VERSION 5.8 ;
BUSBITCHARS "[]" ;
DIVIDERCHAR "/" ;
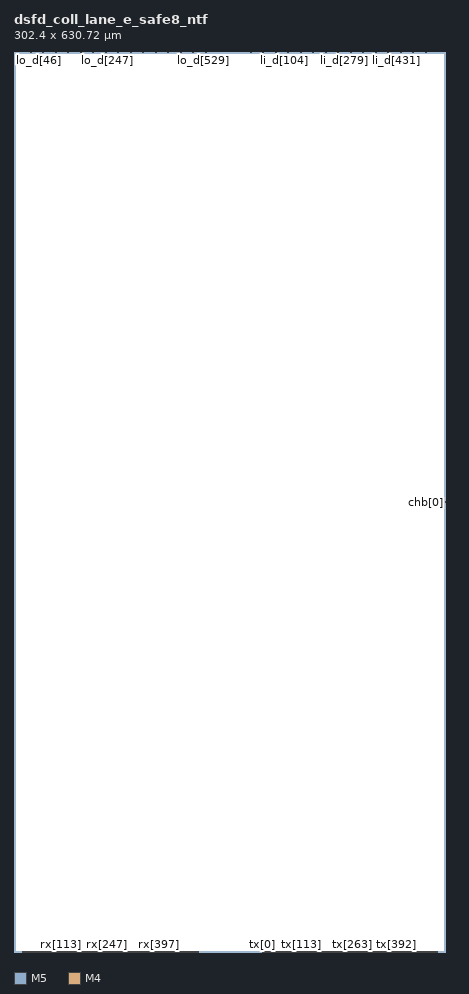
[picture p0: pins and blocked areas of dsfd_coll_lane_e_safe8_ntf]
MACRO dsfd_coll_lane_e_safe8_ntf
 CLASS BLOCK ;
 ORIGIN 0 0 ;
 SIZE 302.4 BY 630.72 ;
 SYMMETRY X Y ;
 PIN rx[0]
  DIRECTION INPUT ;
  USE SIGNAL ;
  PORT
   LAYER M5 ;
   RECT 6.1440 0.0000 6.1680 0.0840 ;
  END
 END rx[0]
 PIN rx[1]
  DIRECTION INPUT ;
  USE SIGNAL ;
  PORT
   LAYER M5 ;
   RECT 6.3840 0.0000 6.4080 0.0840 ;
  END
 END rx[1]
 PIN rx[2]
  DIRECTION INPUT ;
  USE SIGNAL ;
  PORT
   LAYER M5 ;
   RECT 6.6240 0.0000 6.6480 0.0840 ;
  END
 END rx[2]
 PIN rx[3]
  DIRECTION INPUT ;
  USE SIGNAL ;
  PORT
   LAYER M5 ;
   RECT 6.8640 0.0000 6.8880 0.0840 ;
  END
 END rx[3]
 PIN rx[4]
  DIRECTION INPUT ;
  USE SIGNAL ;
  PORT
   LAYER M5 ;
   RECT 7.1040 0.0000 7.1280 0.0840 ;
  END
 END rx[4]
 PIN rx[5]
  DIRECTION INPUT ;
  USE SIGNAL ;
  PORT
   LAYER M5 ;
   RECT 7.3440 0.0000 7.3680 0.0840 ;
  END
 END rx[5]
 PIN rx[6]
  DIRECTION INPUT ;
  USE SIGNAL ;
  PORT
   LAYER M5 ;
   RECT 7.5840 0.0000 7.6080 0.0840 ;
  END
 END rx[6]
 PIN rx[7]
  DIRECTION INPUT ;
  USE SIGNAL ;
  PORT
   LAYER M5 ;
   RECT 7.8240 0.0000 7.8480 0.0840 ;
  END
 END rx[7]
 PIN rx[8]
  DIRECTION INPUT ;
  USE SIGNAL ;
  PORT
   LAYER M5 ;
   RECT 8.0640 0.0000 8.0880 0.0840 ;
  END
 END rx[8]
 PIN rx[9]
  DIRECTION INPUT ;
  USE SIGNAL ;
  PORT
   LAYER M5 ;
   RECT 8.3040 0.0000 8.3280 0.0840 ;
  END
 END rx[9]
 PIN rx[10]
  DIRECTION INPUT ;
  USE SIGNAL ;
  PORT
   LAYER M5 ;
   RECT 8.5440 0.0000 8.5680 0.0840 ;
  END
 END rx[10]
 PIN rx[11]
  DIRECTION INPUT ;
  USE SIGNAL ;
  PORT
   LAYER M5 ;
   RECT 8.7840 0.0000 8.8080 0.0840 ;
  END
 END rx[11]
 PIN rx[12]
  DIRECTION INPUT ;
  USE SIGNAL ;
  PORT
   LAYER M5 ;
   RECT 9.0240 0.0000 9.0480 0.0840 ;
  END
 END rx[12]
 PIN rx[13]
  DIRECTION INPUT ;
  USE SIGNAL ;
  PORT
   LAYER M5 ;
   RECT 9.2640 0.0000 9.2880 0.0840 ;
  END
 END rx[13]
 PIN rx[14]
  DIRECTION INPUT ;
  USE SIGNAL ;
  PORT
   LAYER M5 ;
   RECT 9.5040 0.0000 9.5280 0.0840 ;
  END
 END rx[14]
 PIN rx[15]
  DIRECTION INPUT ;
  USE SIGNAL ;
  PORT
   LAYER M5 ;
   RECT 9.7440 0.0000 9.7680 0.0840 ;
  END
 END rx[15]
 PIN rx[16]
  DIRECTION INPUT ;
  USE SIGNAL ;
  PORT
   LAYER M5 ;
   RECT 9.9840 0.0000 10.0080 0.0840 ;
  END
 END rx[16]
 PIN rx[17]
  DIRECTION INPUT ;
  USE SIGNAL ;
  PORT
   LAYER M5 ;
   RECT 10.2240 0.0000 10.2480 0.0840 ;
  END
 END rx[17]
 PIN rx[18]
  DIRECTION INPUT ;
  USE SIGNAL ;
  PORT
   LAYER M5 ;
   RECT 10.4640 0.0000 10.4880 0.0840 ;
  END
 END rx[18]
 PIN rx[19]
  DIRECTION INPUT ;
  USE SIGNAL ;
  PORT
   LAYER M5 ;
   RECT 10.7040 0.0000 10.7280 0.0840 ;
  END
 END rx[19]
 PIN rx[20]
  DIRECTION INPUT ;
  USE SIGNAL ;
  PORT
   LAYER M5 ;
   RECT 10.9440 0.0000 10.9680 0.0840 ;
  END
 END rx[20]
 PIN rx[21]
  DIRECTION INPUT ;
  USE SIGNAL ;
  PORT
   LAYER M5 ;
   RECT 11.1840 0.0000 11.2080 0.0840 ;
  END
 END rx[21]
 PIN rx[22]
  DIRECTION INPUT ;
  USE SIGNAL ;
  PORT
   LAYER M5 ;
   RECT 11.4240 0.0000 11.4480 0.0840 ;
  END
 END rx[22]
 PIN rx[23]
  DIRECTION INPUT ;
  USE SIGNAL ;
  PORT
   LAYER M5 ;
   RECT 11.6640 0.0000 11.6880 0.0840 ;
  END
 END rx[23]
 PIN rx[24]
  DIRECTION INPUT ;
  USE SIGNAL ;
  PORT
   LAYER M5 ;
   RECT 11.9040 0.0000 11.9280 0.0840 ;
  END
 END rx[24]
 PIN rx[25]
  DIRECTION INPUT ;
  USE SIGNAL ;
  PORT
   LAYER M5 ;
   RECT 12.1440 0.0000 12.1680 0.0840 ;
  END
 END rx[25]
 PIN rx[26]
  DIRECTION INPUT ;
  USE SIGNAL ;
  PORT
   LAYER M5 ;
   RECT 12.3840 0.0000 12.4080 0.0840 ;
  END
 END rx[26]
 PIN rx[27]
  DIRECTION INPUT ;
  USE SIGNAL ;
  PORT
   LAYER M5 ;
   RECT 12.6240 0.0000 12.6480 0.0840 ;
  END
 END rx[27]
 PIN rx[28]
  DIRECTION INPUT ;
  USE SIGNAL ;
  PORT
   LAYER M5 ;
   RECT 12.8640 0.0000 12.8880 0.0840 ;
  END
 END rx[28]
 PIN rx[29]
  DIRECTION INPUT ;
  USE SIGNAL ;
  PORT
   LAYER M5 ;
   RECT 13.1040 0.0000 13.1280 0.0840 ;
  END
 END rx[29]
 PIN rx[30]
  DIRECTION INPUT ;
  USE SIGNAL ;
  PORT
   LAYER M5 ;
   RECT 13.3440 0.0000 13.3680 0.0840 ;
  END
 END rx[30]
 PIN rx[31]
  DIRECTION INPUT ;
  USE SIGNAL ;
  PORT
   LAYER M5 ;
   RECT 13.5840 0.0000 13.6080 0.0840 ;
  END
 END rx[31]
 PIN rx[32]
  DIRECTION INPUT ;
  USE SIGNAL ;
  PORT
   LAYER M5 ;
   RECT 13.8240 0.0000 13.8480 0.0840 ;
  END
 END rx[32]
 PIN rx[33]
  DIRECTION INPUT ;
  USE SIGNAL ;
  PORT
   LAYER M5 ;
   RECT 14.0640 0.0000 14.0880 0.0840 ;
  END
 END rx[33]
 PIN rx[34]
  DIRECTION INPUT ;
  USE SIGNAL ;
  PORT
   LAYER M5 ;
   RECT 14.3040 0.0000 14.3280 0.0840 ;
  END
 END rx[34]
 PIN rx[35]
  DIRECTION INPUT ;
  USE SIGNAL ;
  PORT
   LAYER M5 ;
   RECT 14.5440 0.0000 14.5680 0.0840 ;
  END
 END rx[35]
 PIN rx[36]
  DIRECTION INPUT ;
  USE SIGNAL ;
  PORT
   LAYER M5 ;
   RECT 14.7840 0.0000 14.8080 0.0840 ;
  END
 END rx[36]
 PIN rx[37]
  DIRECTION INPUT ;
  USE SIGNAL ;
  PORT
   LAYER M5 ;
   RECT 15.0240 0.0000 15.0480 0.0840 ;
  END
 END rx[37]
 PIN rx[38]
  DIRECTION INPUT ;
  USE SIGNAL ;
  PORT
   LAYER M5 ;
   RECT 15.2640 0.0000 15.2880 0.0840 ;
  END
 END rx[38]
 PIN rx[39]
  DIRECTION INPUT ;
  USE SIGNAL ;
  PORT
   LAYER M5 ;
   RECT 15.5040 0.0000 15.5280 0.0840 ;
  END
 END rx[39]
 PIN rx[40]
  DIRECTION INPUT ;
  USE SIGNAL ;
  PORT
   LAYER M5 ;
   RECT 15.7440 0.0000 15.7680 0.0840 ;
  END
 END rx[40]
 PIN rx[41]
  DIRECTION INPUT ;
  USE SIGNAL ;
  PORT
   LAYER M5 ;
   RECT 15.9840 0.0000 16.0080 0.0840 ;
  END
 END rx[41]
 PIN rx[42]
  DIRECTION INPUT ;
  USE SIGNAL ;
  PORT
   LAYER M5 ;
   RECT 16.2240 0.0000 16.2480 0.0840 ;
  END
 END rx[42]
 PIN rx[43]
  DIRECTION INPUT ;
  USE SIGNAL ;
  PORT
   LAYER M5 ;
   RECT 16.4640 0.0000 16.4880 0.0840 ;
  END
 END rx[43]
 PIN rx[44]
  DIRECTION INPUT ;
  USE SIGNAL ;
  PORT
   LAYER M5 ;
   RECT 16.7040 0.0000 16.7280 0.0840 ;
  END
 END rx[44]
 PIN rx[45]
  DIRECTION INPUT ;
  USE SIGNAL ;
  PORT
   LAYER M5 ;
   RECT 16.9440 0.0000 16.9680 0.0840 ;
  END
 END rx[45]
 PIN rx[46]
  DIRECTION INPUT ;
  USE SIGNAL ;
  PORT
   LAYER M5 ;
   RECT 17.1840 0.0000 17.2080 0.0840 ;
  END
 END rx[46]
 PIN rx[47]
  DIRECTION INPUT ;
  USE SIGNAL ;
  PORT
   LAYER M5 ;
   RECT 17.4240 0.0000 17.4480 0.0840 ;
  END
 END rx[47]
 PIN rx[48]
  DIRECTION INPUT ;
  USE SIGNAL ;
  PORT
   LAYER M5 ;
   RECT 17.6640 0.0000 17.6880 0.0840 ;
  END
 END rx[48]
 PIN rx[49]
  DIRECTION INPUT ;
  USE SIGNAL ;
  PORT
   LAYER M5 ;
   RECT 17.9040 0.0000 17.9280 0.0840 ;
  END
 END rx[49]
 PIN rx[50]
  DIRECTION INPUT ;
  USE SIGNAL ;
  PORT
   LAYER M5 ;
   RECT 18.1440 0.0000 18.1680 0.0840 ;
  END
 END rx[50]
 PIN rx[51]
  DIRECTION INPUT ;
  USE SIGNAL ;
  PORT
   LAYER M5 ;
   RECT 18.3840 0.0000 18.4080 0.0840 ;
  END
 END rx[51]
 PIN rx[52]
  DIRECTION INPUT ;
  USE SIGNAL ;
  PORT
   LAYER M5 ;
   RECT 18.6240 0.0000 18.6480 0.0840 ;
  END
 END rx[52]
 PIN rx[53]
  DIRECTION INPUT ;
  USE SIGNAL ;
  PORT
   LAYER M5 ;
   RECT 18.8640 0.0000 18.8880 0.0840 ;
  END
 END rx[53]
 PIN rx[54]
  DIRECTION INPUT ;
  USE SIGNAL ;
  PORT
   LAYER M5 ;
   RECT 19.1040 0.0000 19.1280 0.0840 ;
  END
 END rx[54]
 PIN rx[55]
  DIRECTION INPUT ;
  USE SIGNAL ;
  PORT
   LAYER M5 ;
   RECT 19.3440 0.0000 19.3680 0.0840 ;
  END
 END rx[55]
 PIN rx[56]
  DIRECTION INPUT ;
  USE SIGNAL ;
  PORT
   LAYER M5 ;
   RECT 19.5840 0.0000 19.6080 0.0840 ;
  END
 END rx[56]
 PIN rx[57]
  DIRECTION INPUT ;
  USE SIGNAL ;
  PORT
   LAYER M5 ;
   RECT 19.8240 0.0000 19.8480 0.0840 ;
  END
 END rx[57]
 PIN rx[58]
  DIRECTION INPUT ;
  USE SIGNAL ;
  PORT
   LAYER M5 ;
   RECT 20.0640 0.0000 20.0880 0.0840 ;
  END
 END rx[58]
 PIN rx[59]
  DIRECTION INPUT ;
  USE SIGNAL ;
  PORT
   LAYER M5 ;
   RECT 20.3040 0.0000 20.3280 0.0840 ;
  END
 END rx[59]
 PIN rx[60]
  DIRECTION INPUT ;
  USE SIGNAL ;
  PORT
   LAYER M5 ;
   RECT 20.5440 0.0000 20.5680 0.0840 ;
  END
 END rx[60]
 PIN rx[61]
  DIRECTION INPUT ;
  USE SIGNAL ;
  PORT
   LAYER M5 ;
   RECT 20.7840 0.0000 20.8080 0.0840 ;
  END
 END rx[61]
 PIN rx[62]
  DIRECTION INPUT ;
  USE SIGNAL ;
  PORT
   LAYER M5 ;
   RECT 21.0240 0.0000 21.0480 0.0840 ;
  END
 END rx[62]
 PIN rx[63]
  DIRECTION INPUT ;
  USE SIGNAL ;
  PORT
   LAYER M5 ;
   RECT 21.2640 0.0000 21.2880 0.0840 ;
  END
 END rx[63]
 PIN rx[64]
  DIRECTION INPUT ;
  USE SIGNAL ;
  PORT
   LAYER M5 ;
   RECT 21.5040 0.0000 21.5280 0.0840 ;
  END
 END rx[64]
 PIN rx[65]
  DIRECTION INPUT ;
  USE SIGNAL ;
  PORT
   LAYER M5 ;
   RECT 21.7440 0.0000 21.7680 0.0840 ;
  END
 END rx[65]
 PIN rx[66]
  DIRECTION INPUT ;
  USE SIGNAL ;
  PORT
   LAYER M5 ;
   RECT 21.9840 0.0000 22.0080 0.0840 ;
  END
 END rx[66]
 PIN rx[67]
  DIRECTION INPUT ;
  USE SIGNAL ;
  PORT
   LAYER M5 ;
   RECT 22.2240 0.0000 22.2480 0.0840 ;
  END
 END rx[67]
 PIN rx[68]
  DIRECTION INPUT ;
  USE SIGNAL ;
  PORT
   LAYER M5 ;
   RECT 22.4640 0.0000 22.4880 0.0840 ;
  END
 END rx[68]
 PIN rx[69]
  DIRECTION INPUT ;
  USE SIGNAL ;
  PORT
   LAYER M5 ;
   RECT 22.7040 0.0000 22.7280 0.0840 ;
  END
 END rx[69]
 PIN rx[70]
  DIRECTION INPUT ;
  USE SIGNAL ;
  PORT
   LAYER M5 ;
   RECT 22.9440 0.0000 22.9680 0.0840 ;
  END
 END rx[70]
 PIN rx[71]
  DIRECTION INPUT ;
  USE SIGNAL ;
  PORT
   LAYER M5 ;
   RECT 23.1840 0.0000 23.2080 0.0840 ;
  END
 END rx[71]
 PIN rx[72]
  DIRECTION INPUT ;
  USE SIGNAL ;
  PORT
   LAYER M5 ;
   RECT 23.4240 0.0000 23.4480 0.0840 ;
  END
 END rx[72]
 PIN rx[73]
  DIRECTION INPUT ;
  USE SIGNAL ;
  PORT
   LAYER M5 ;
   RECT 23.6640 0.0000 23.6880 0.0840 ;
  END
 END rx[73]
 PIN rx[74]
  DIRECTION INPUT ;
  USE SIGNAL ;
  PORT
   LAYER M5 ;
   RECT 23.9040 0.0000 23.9280 0.0840 ;
  END
 END rx[74]
 PIN rx[75]
  DIRECTION INPUT ;
  USE SIGNAL ;
  PORT
   LAYER M5 ;
   RECT 24.1440 0.0000 24.1680 0.0840 ;
  END
 END rx[75]
 PIN rx[76]
  DIRECTION INPUT ;
  USE SIGNAL ;
  PORT
   LAYER M5 ;
   RECT 24.3840 0.0000 24.4080 0.0840 ;
  END
 END rx[76]
 PIN rx[77]
  DIRECTION INPUT ;
  USE SIGNAL ;
  PORT
   LAYER M5 ;
   RECT 24.6240 0.0000 24.6480 0.0840 ;
  END
 END rx[77]
 PIN rx[78]
  DIRECTION INPUT ;
  USE SIGNAL ;
  PORT
   LAYER M5 ;
   RECT 24.8640 0.0000 24.8880 0.0840 ;
  END
 END rx[78]
 PIN rx[79]
  DIRECTION INPUT ;
  USE SIGNAL ;
  PORT
   LAYER M5 ;
   RECT 25.1040 0.0000 25.1280 0.0840 ;
  END
 END rx[79]
 PIN rx[80]
  DIRECTION INPUT ;
  USE SIGNAL ;
  PORT
   LAYER M5 ;
   RECT 25.3440 0.0000 25.3680 0.0840 ;
  END
 END rx[80]
 PIN rx[81]
  DIRECTION INPUT ;
  USE SIGNAL ;
  PORT
   LAYER M5 ;
   RECT 25.5840 0.0000 25.6080 0.0840 ;
  END
 END rx[81]
 PIN rx[82]
  DIRECTION INPUT ;
  USE SIGNAL ;
  PORT
   LAYER M5 ;
   RECT 25.8240 0.0000 25.8480 0.0840 ;
  END
 END rx[82]
 PIN rx[83]
  DIRECTION INPUT ;
  USE SIGNAL ;
  PORT
   LAYER M5 ;
   RECT 26.0640 0.0000 26.0880 0.0840 ;
  END
 END rx[83]
 PIN rx[84]
  DIRECTION INPUT ;
  USE SIGNAL ;
  PORT
   LAYER M5 ;
   RECT 26.3040 0.0000 26.3280 0.0840 ;
  END
 END rx[84]
 PIN rx[85]
  DIRECTION INPUT ;
  USE SIGNAL ;
  PORT
   LAYER M5 ;
   RECT 26.5440 0.0000 26.5680 0.0840 ;
  END
 END rx[85]
 PIN rx[86]
  DIRECTION INPUT ;
  USE SIGNAL ;
  PORT
   LAYER M5 ;
   RECT 26.7840 0.0000 26.8080 0.0840 ;
  END
 END rx[86]
 PIN rx[87]
  DIRECTION INPUT ;
  USE SIGNAL ;
  PORT
   LAYER M5 ;
   RECT 27.0240 0.0000 27.0480 0.0840 ;
  END
 END rx[87]
 PIN rx[88]
  DIRECTION INPUT ;
  USE SIGNAL ;
  PORT
   LAYER M5 ;
   RECT 27.2640 0.0000 27.2880 0.0840 ;
  END
 END rx[88]
 PIN rx[89]
  DIRECTION INPUT ;
  USE SIGNAL ;
  PORT
   LAYER M5 ;
   RECT 27.5040 0.0000 27.5280 0.0840 ;
  END
 END rx[89]
 PIN rx[90]
  DIRECTION INPUT ;
  USE SIGNAL ;
  PORT
   LAYER M5 ;
   RECT 27.7440 0.0000 27.7680 0.0840 ;
  END
 END rx[90]
 PIN rx[91]
  DIRECTION INPUT ;
  USE SIGNAL ;
  PORT
   LAYER M5 ;
   RECT 27.9840 0.0000 28.0080 0.0840 ;
  END
 END rx[91]
 PIN rx[92]
  DIRECTION INPUT ;
  USE SIGNAL ;
  PORT
   LAYER M5 ;
   RECT 28.2240 0.0000 28.2480 0.0840 ;
  END
 END rx[92]
 PIN rx[93]
  DIRECTION INPUT ;
  USE SIGNAL ;
  PORT
   LAYER M5 ;
   RECT 28.4640 0.0000 28.4880 0.0840 ;
  END
 END rx[93]
 PIN rx[94]
  DIRECTION INPUT ;
  USE SIGNAL ;
  PORT
   LAYER M5 ;
   RECT 28.7040 0.0000 28.7280 0.0840 ;
  END
 END rx[94]
 PIN rx[95]
  DIRECTION INPUT ;
  USE SIGNAL ;
  PORT
   LAYER M5 ;
   RECT 28.9440 0.0000 28.9680 0.0840 ;
  END
 END rx[95]
 PIN rx[96]
  DIRECTION INPUT ;
  USE SIGNAL ;
  PORT
   LAYER M5 ;
   RECT 29.1840 0.0000 29.2080 0.0840 ;
  END
 END rx[96]
 PIN rx[97]
  DIRECTION INPUT ;
  USE SIGNAL ;
  PORT
   LAYER M5 ;
   RECT 29.4240 0.0000 29.4480 0.0840 ;
  END
 END rx[97]
 PIN rx[98]
  DIRECTION INPUT ;
  USE SIGNAL ;
  PORT
   LAYER M5 ;
   RECT 29.6640 0.0000 29.6880 0.0840 ;
  END
 END rx[98]
 PIN rx[99]
  DIRECTION INPUT ;
  USE SIGNAL ;
  PORT
   LAYER M5 ;
   RECT 29.9040 0.0000 29.9280 0.0840 ;
  END
 END rx[99]
 PIN rx[100]
  DIRECTION INPUT ;
  USE SIGNAL ;
  PORT
   LAYER M5 ;
   RECT 30.1440 0.0000 30.1680 0.0840 ;
  END
 END rx[100]
 PIN rx[101]
  DIRECTION INPUT ;
  USE SIGNAL ;
  PORT
   LAYER M5 ;
   RECT 30.3840 0.0000 30.4080 0.0840 ;
  END
 END rx[101]
 PIN rx[102]
  DIRECTION INPUT ;
  USE SIGNAL ;
  PORT
   LAYER M5 ;
   RECT 30.6240 0.0000 30.6480 0.0840 ;
  END
 END rx[102]
 PIN rx[103]
  DIRECTION INPUT ;
  USE SIGNAL ;
  PORT
   LAYER M5 ;
   RECT 30.8640 0.0000 30.8880 0.0840 ;
  END
 END rx[103]
 PIN rx[104]
  DIRECTION INPUT ;
  USE SIGNAL ;
  PORT
   LAYER M5 ;
   RECT 31.1040 0.0000 31.1280 0.0840 ;
  END
 END rx[104]
 PIN rx[105]
  DIRECTION INPUT ;
  USE SIGNAL ;
  PORT
   LAYER M5 ;
   RECT 31.3440 0.0000 31.3680 0.0840 ;
  END
 END rx[105]
 PIN rx[106]
  DIRECTION INPUT ;
  USE SIGNAL ;
  PORT
   LAYER M5 ;
   RECT 31.5840 0.0000 31.6080 0.0840 ;
  END
 END rx[106]
 PIN rx[107]
  DIRECTION INPUT ;
  USE SIGNAL ;
  PORT
   LAYER M5 ;
   RECT 31.8240 0.0000 31.8480 0.0840 ;
  END
 END rx[107]
 PIN rx[108]
  DIRECTION INPUT ;
  USE SIGNAL ;
  PORT
   LAYER M5 ;
   RECT 32.0640 0.0000 32.0880 0.0840 ;
  END
 END rx[108]
 PIN rx[109]
  DIRECTION INPUT ;
  USE SIGNAL ;
  PORT
   LAYER M5 ;
   RECT 32.3040 0.0000 32.3280 0.0840 ;
  END
 END rx[109]
 PIN rx[110]
  DIRECTION INPUT ;
  USE SIGNAL ;
  PORT
   LAYER M5 ;
   RECT 32.5440 0.0000 32.5680 0.0840 ;
  END
 END rx[110]
 PIN rx[111]
  DIRECTION INPUT ;
  USE SIGNAL ;
  PORT
   LAYER M5 ;
   RECT 32.7840 0.0000 32.8080 0.0840 ;
  END
 END rx[111]
 PIN rx[112]
  DIRECTION INPUT ;
  USE SIGNAL ;
  PORT
   LAYER M5 ;
   RECT 33.0240 0.0000 33.0480 0.0840 ;
  END
 END rx[112]
 PIN rx[113]
  DIRECTION INPUT ;
  USE SIGNAL ;
  PORT
   LAYER M5 ;
   RECT 33.2640 0.0000 33.2880 0.0840 ;
  END
 END rx[113]
 PIN rx[114]
  DIRECTION INPUT ;
  USE SIGNAL ;
  PORT
   LAYER M5 ;
   RECT 33.5040 0.0000 33.5280 0.0840 ;
  END
 END rx[114]
 PIN rx[115]
  DIRECTION INPUT ;
  USE SIGNAL ;
  PORT
   LAYER M5 ;
   RECT 33.7440 0.0000 33.7680 0.0840 ;
  END
 END rx[115]
 PIN rx[116]
  DIRECTION INPUT ;
  USE SIGNAL ;
  PORT
   LAYER M5 ;
   RECT 33.9840 0.0000 34.0080 0.0840 ;
  END
 END rx[116]
 PIN rx[117]
  DIRECTION INPUT ;
  USE SIGNAL ;
  PORT
   LAYER M5 ;
   RECT 34.2240 0.0000 34.2480 0.0840 ;
  END
 END rx[117]
 PIN rx[118]
  DIRECTION INPUT ;
  USE SIGNAL ;
  PORT
   LAYER M5 ;
   RECT 34.4640 0.0000 34.4880 0.0840 ;
  END
 END rx[118]
 PIN rx[119]
  DIRECTION INPUT ;
  USE SIGNAL ;
  PORT
   LAYER M5 ;
   RECT 34.7040 0.0000 34.7280 0.0840 ;
  END
 END rx[119]
 PIN rx[120]
  DIRECTION INPUT ;
  USE SIGNAL ;
  PORT
   LAYER M5 ;
   RECT 34.9440 0.0000 34.9680 0.0840 ;
  END
 END rx[120]
 PIN rx[121]
  DIRECTION INPUT ;
  USE SIGNAL ;
  PORT
   LAYER M5 ;
   RECT 35.1840 0.0000 35.2080 0.0840 ;
  END
 END rx[121]
 PIN rx[122]
  DIRECTION INPUT ;
  USE SIGNAL ;
  PORT
   LAYER M5 ;
   RECT 35.4240 0.0000 35.4480 0.0840 ;
  END
 END rx[122]
 PIN rx[123]
  DIRECTION INPUT ;
  USE SIGNAL ;
  PORT
   LAYER M5 ;
   RECT 35.6640 0.0000 35.6880 0.0840 ;
  END
 END rx[123]
 PIN rx[124]
  DIRECTION INPUT ;
  USE SIGNAL ;
  PORT
   LAYER M5 ;
   RECT 35.9040 0.0000 35.9280 0.0840 ;
  END
 END rx[124]
 PIN rx[125]
  DIRECTION INPUT ;
  USE SIGNAL ;
  PORT
   LAYER M5 ;
   RECT 36.1440 0.0000 36.1680 0.0840 ;
  END
 END rx[125]
 PIN rx[126]
  DIRECTION INPUT ;
  USE SIGNAL ;
  PORT
   LAYER M5 ;
   RECT 36.3840 0.0000 36.4080 0.0840 ;
  END
 END rx[126]
 PIN rx[127]
  DIRECTION INPUT ;
  USE SIGNAL ;
  PORT
   LAYER M5 ;
   RECT 36.6240 0.0000 36.6480 0.0840 ;
  END
 END rx[127]
 PIN rx[128]
  DIRECTION INPUT ;
  USE SIGNAL ;
  PORT
   LAYER M5 ;
   RECT 36.8640 0.0000 36.8880 0.0840 ;
  END
 END rx[128]
 PIN rx[129]
  DIRECTION INPUT ;
  USE SIGNAL ;
  PORT
   LAYER M5 ;
   RECT 37.1040 0.0000 37.1280 0.0840 ;
  END
 END rx[129]
 PIN rx[130]
  DIRECTION INPUT ;
  USE SIGNAL ;
  PORT
   LAYER M5 ;
   RECT 37.3440 0.0000 37.3680 0.0840 ;
  END
 END rx[130]
 PIN rx[131]
  DIRECTION INPUT ;
  USE SIGNAL ;
  PORT
   LAYER M5 ;
   RECT 37.5840 0.0000 37.6080 0.0840 ;
  END
 END rx[131]
 PIN rx[132]
  DIRECTION INPUT ;
  USE SIGNAL ;
  PORT
   LAYER M5 ;
   RECT 37.8240 0.0000 37.8480 0.0840 ;
  END
 END rx[132]
 PIN rx[133]
  DIRECTION INPUT ;
  USE SIGNAL ;
  PORT
   LAYER M5 ;
   RECT 38.0640 0.0000 38.0880 0.0840 ;
  END
 END rx[133]
 PIN rx[134]
  DIRECTION INPUT ;
  USE SIGNAL ;
  PORT
   LAYER M5 ;
   RECT 38.3040 0.0000 38.3280 0.0840 ;
  END
 END rx[134]
 PIN rx[135]
  DIRECTION INPUT ;
  USE SIGNAL ;
  PORT
   LAYER M5 ;
   RECT 38.5440 0.0000 38.5680 0.0840 ;
  END
 END rx[135]
 PIN rx[136]
  DIRECTION INPUT ;
  USE SIGNAL ;
  PORT
   LAYER M5 ;
   RECT 38.7840 0.0000 38.8080 0.0840 ;
  END
 END rx[136]
 PIN rx[137]
  DIRECTION INPUT ;
  USE SIGNAL ;
  PORT
   LAYER M5 ;
   RECT 39.0240 0.0000 39.0480 0.0840 ;
  END
 END rx[137]
 PIN rx[138]
  DIRECTION INPUT ;
  USE SIGNAL ;
  PORT
   LAYER M5 ;
   RECT 39.2640 0.0000 39.2880 0.0840 ;
  END
 END rx[138]
 PIN rx[139]
  DIRECTION INPUT ;
  USE SIGNAL ;
  PORT
   LAYER M5 ;
   RECT 39.5040 0.0000 39.5280 0.0840 ;
  END
 END rx[139]
 PIN rx[140]
  DIRECTION INPUT ;
  USE SIGNAL ;
  PORT
   LAYER M5 ;
   RECT 39.7440 0.0000 39.7680 0.0840 ;
  END
 END rx[140]
 PIN rx[141]
  DIRECTION INPUT ;
  USE SIGNAL ;
  PORT
   LAYER M5 ;
   RECT 39.9840 0.0000 40.0080 0.0840 ;
  END
 END rx[141]
 PIN rx[142]
  DIRECTION INPUT ;
  USE SIGNAL ;
  PORT
   LAYER M5 ;
   RECT 40.2240 0.0000 40.2480 0.0840 ;
  END
 END rx[142]
 PIN rx[143]
  DIRECTION INPUT ;
  USE SIGNAL ;
  PORT
   LAYER M5 ;
   RECT 40.4640 0.0000 40.4880 0.0840 ;
  END
 END rx[143]
 PIN rx[144]
  DIRECTION INPUT ;
  USE SIGNAL ;
  PORT
   LAYER M5 ;
   RECT 40.7040 0.0000 40.7280 0.0840 ;
  END
 END rx[144]
 PIN rx[145]
  DIRECTION INPUT ;
  USE SIGNAL ;
  PORT
   LAYER M5 ;
   RECT 40.9440 0.0000 40.9680 0.0840 ;
  END
 END rx[145]
 PIN rx[146]
  DIRECTION INPUT ;
  USE SIGNAL ;
  PORT
   LAYER M5 ;
   RECT 41.1840 0.0000 41.2080 0.0840 ;
  END
 END rx[146]
 PIN rx[147]
  DIRECTION INPUT ;
  USE SIGNAL ;
  PORT
   LAYER M5 ;
   RECT 41.4240 0.0000 41.4480 0.0840 ;
  END
 END rx[147]
 PIN rx[148]
  DIRECTION INPUT ;
  USE SIGNAL ;
  PORT
   LAYER M5 ;
   RECT 41.6640 0.0000 41.6880 0.0840 ;
  END
 END rx[148]
 PIN rx[149]
  DIRECTION INPUT ;
  USE SIGNAL ;
  PORT
   LAYER M5 ;
   RECT 41.9040 0.0000 41.9280 0.0840 ;
  END
 END rx[149]
 PIN rx[150]
  DIRECTION INPUT ;
  USE SIGNAL ;
  PORT
   LAYER M5 ;
   RECT 42.1440 0.0000 42.1680 0.0840 ;
  END
 END rx[150]
 PIN rx[151]
  DIRECTION INPUT ;
  USE SIGNAL ;
  PORT
   LAYER M5 ;
   RECT 42.3840 0.0000 42.4080 0.0840 ;
  END
 END rx[151]
 PIN rx[152]
  DIRECTION INPUT ;
  USE SIGNAL ;
  PORT
   LAYER M5 ;
   RECT 42.6240 0.0000 42.6480 0.0840 ;
  END
 END rx[152]
 PIN rx[153]
  DIRECTION INPUT ;
  USE SIGNAL ;
  PORT
   LAYER M5 ;
   RECT 42.8640 0.0000 42.8880 0.0840 ;
  END
 END rx[153]
 PIN rx[154]
  DIRECTION INPUT ;
  USE SIGNAL ;
  PORT
   LAYER M5 ;
   RECT 43.1040 0.0000 43.1280 0.0840 ;
  END
 END rx[154]
 PIN rx[155]
  DIRECTION INPUT ;
  USE SIGNAL ;
  PORT
   LAYER M5 ;
   RECT 43.3440 0.0000 43.3680 0.0840 ;
  END
 END rx[155]
 PIN rx[156]
  DIRECTION INPUT ;
  USE SIGNAL ;
  PORT
   LAYER M5 ;
   RECT 43.5840 0.0000 43.6080 0.0840 ;
  END
 END rx[156]
 PIN rx[157]
  DIRECTION INPUT ;
  USE SIGNAL ;
  PORT
   LAYER M5 ;
   RECT 43.8240 0.0000 43.8480 0.0840 ;
  END
 END rx[157]
 PIN rx[158]
  DIRECTION INPUT ;
  USE SIGNAL ;
  PORT
   LAYER M5 ;
   RECT 44.0640 0.0000 44.0880 0.0840 ;
  END
 END rx[158]
 PIN rx[159]
  DIRECTION INPUT ;
  USE SIGNAL ;
  PORT
   LAYER M5 ;
   RECT 44.3040 0.0000 44.3280 0.0840 ;
  END
 END rx[159]
 PIN rx[160]
  DIRECTION INPUT ;
  USE SIGNAL ;
  PORT
   LAYER M5 ;
   RECT 44.5440 0.0000 44.5680 0.0840 ;
  END
 END rx[160]
 PIN rx[161]
  DIRECTION INPUT ;
  USE SIGNAL ;
  PORT
   LAYER M5 ;
   RECT 44.7840 0.0000 44.8080 0.0840 ;
  END
 END rx[161]
 PIN rx[162]
  DIRECTION INPUT ;
  USE SIGNAL ;
  PORT
   LAYER M5 ;
   RECT 45.0240 0.0000 45.0480 0.0840 ;
  END
 END rx[162]
 PIN rx[163]
  DIRECTION INPUT ;
  USE SIGNAL ;
  PORT
   LAYER M5 ;
   RECT 45.2640 0.0000 45.2880 0.0840 ;
  END
 END rx[163]
 PIN rx[164]
  DIRECTION INPUT ;
  USE SIGNAL ;
  PORT
   LAYER M5 ;
   RECT 45.5040 0.0000 45.5280 0.0840 ;
  END
 END rx[164]
 PIN rx[165]
  DIRECTION INPUT ;
  USE SIGNAL ;
  PORT
   LAYER M5 ;
   RECT 45.7440 0.0000 45.7680 0.0840 ;
  END
 END rx[165]
 PIN rx[166]
  DIRECTION INPUT ;
  USE SIGNAL ;
  PORT
   LAYER M5 ;
   RECT 45.9840 0.0000 46.0080 0.0840 ;
  END
 END rx[166]
 PIN rx[167]
  DIRECTION INPUT ;
  USE SIGNAL ;
  PORT
   LAYER M5 ;
   RECT 46.2240 0.0000 46.2480 0.0840 ;
  END
 END rx[167]
 PIN rx[168]
  DIRECTION INPUT ;
  USE SIGNAL ;
  PORT
   LAYER M5 ;
   RECT 46.4640 0.0000 46.4880 0.0840 ;
  END
 END rx[168]
 PIN rx[169]
  DIRECTION INPUT ;
  USE SIGNAL ;
  PORT
   LAYER M5 ;
   RECT 46.7040 0.0000 46.7280 0.0840 ;
  END
 END rx[169]
 PIN rx[170]
  DIRECTION INPUT ;
  USE SIGNAL ;
  PORT
   LAYER M5 ;
   RECT 46.9440 0.0000 46.9680 0.0840 ;
  END
 END rx[170]
 PIN rx[171]
  DIRECTION INPUT ;
  USE SIGNAL ;
  PORT
   LAYER M5 ;
   RECT 47.1840 0.0000 47.2080 0.0840 ;
  END
 END rx[171]
 PIN rx[172]
  DIRECTION INPUT ;
  USE SIGNAL ;
  PORT
   LAYER M5 ;
   RECT 47.4240 0.0000 47.4480 0.0840 ;
  END
 END rx[172]
 PIN rx[173]
  DIRECTION INPUT ;
  USE SIGNAL ;
  PORT
   LAYER M5 ;
   RECT 47.6640 0.0000 47.6880 0.0840 ;
  END
 END rx[173]
 PIN rx[174]
  DIRECTION INPUT ;
  USE SIGNAL ;
  PORT
   LAYER M5 ;
   RECT 47.9040 0.0000 47.9280 0.0840 ;
  END
 END rx[174]
 PIN rx[175]
  DIRECTION INPUT ;
  USE SIGNAL ;
  PORT
   LAYER M5 ;
   RECT 48.1440 0.0000 48.1680 0.0840 ;
  END
 END rx[175]
 PIN rx[176]
  DIRECTION INPUT ;
  USE SIGNAL ;
  PORT
   LAYER M5 ;
   RECT 48.3840 0.0000 48.4080 0.0840 ;
  END
 END rx[176]
 PIN rx[177]
  DIRECTION INPUT ;
  USE SIGNAL ;
  PORT
   LAYER M5 ;
   RECT 48.6240 0.0000 48.6480 0.0840 ;
  END
 END rx[177]
 PIN rx[178]
  DIRECTION INPUT ;
  USE SIGNAL ;
  PORT
   LAYER M5 ;
   RECT 48.8640 0.0000 48.8880 0.0840 ;
  END
 END rx[178]
 PIN rx[179]
  DIRECTION INPUT ;
  USE SIGNAL ;
  PORT
   LAYER M5 ;
   RECT 49.1040 0.0000 49.1280 0.0840 ;
  END
 END rx[179]
 PIN rx[180]
  DIRECTION INPUT ;
  USE SIGNAL ;
  PORT
   LAYER M5 ;
   RECT 49.3440 0.0000 49.3680 0.0840 ;
  END
 END rx[180]
 PIN rx[181]
  DIRECTION INPUT ;
  USE SIGNAL ;
  PORT
   LAYER M5 ;
   RECT 49.5840 0.0000 49.6080 0.0840 ;
  END
 END rx[181]
 PIN rx[182]
  DIRECTION INPUT ;
  USE SIGNAL ;
  PORT
   LAYER M5 ;
   RECT 49.8240 0.0000 49.8480 0.0840 ;
  END
 END rx[182]
 PIN rx[183]
  DIRECTION INPUT ;
  USE SIGNAL ;
  PORT
   LAYER M5 ;
   RECT 50.0640 0.0000 50.0880 0.0840 ;
  END
 END rx[183]
 PIN rx[184]
  DIRECTION INPUT ;
  USE SIGNAL ;
  PORT
   LAYER M5 ;
   RECT 50.3040 0.0000 50.3280 0.0840 ;
  END
 END rx[184]
 PIN rx[185]
  DIRECTION INPUT ;
  USE SIGNAL ;
  PORT
   LAYER M5 ;
   RECT 50.5440 0.0000 50.5680 0.0840 ;
  END
 END rx[185]
 PIN rx[186]
  DIRECTION INPUT ;
  USE SIGNAL ;
  PORT
   LAYER M5 ;
   RECT 50.7840 0.0000 50.8080 0.0840 ;
  END
 END rx[186]
 PIN rx[187]
  DIRECTION INPUT ;
  USE SIGNAL ;
  PORT
   LAYER M5 ;
   RECT 51.0240 0.0000 51.0480 0.0840 ;
  END
 END rx[187]
 PIN rx[188]
  DIRECTION INPUT ;
  USE SIGNAL ;
  PORT
   LAYER M5 ;
   RECT 51.2640 0.0000 51.2880 0.0840 ;
  END
 END rx[188]
 PIN rx[189]
  DIRECTION INPUT ;
  USE SIGNAL ;
  PORT
   LAYER M5 ;
   RECT 51.5040 0.0000 51.5280 0.0840 ;
  END
 END rx[189]
 PIN rx[190]
  DIRECTION INPUT ;
  USE SIGNAL ;
  PORT
   LAYER M5 ;
   RECT 51.7440 0.0000 51.7680 0.0840 ;
  END
 END rx[190]
 PIN rx[191]
  DIRECTION INPUT ;
  USE SIGNAL ;
  PORT
   LAYER M5 ;
   RECT 51.9840 0.0000 52.0080 0.0840 ;
  END
 END rx[191]
 PIN rx[192]
  DIRECTION INPUT ;
  USE SIGNAL ;
  PORT
   LAYER M5 ;
   RECT 52.2240 0.0000 52.2480 0.0840 ;
  END
 END rx[192]
 PIN rx[193]
  DIRECTION INPUT ;
  USE SIGNAL ;
  PORT
   LAYER M5 ;
   RECT 52.4640 0.0000 52.4880 0.0840 ;
  END
 END rx[193]
 PIN rx[194]
  DIRECTION INPUT ;
  USE SIGNAL ;
  PORT
   LAYER M5 ;
   RECT 52.7040 0.0000 52.7280 0.0840 ;
  END
 END rx[194]
 PIN rx[195]
  DIRECTION INPUT ;
  USE SIGNAL ;
  PORT
   LAYER M5 ;
   RECT 52.9440 0.0000 52.9680 0.0840 ;
  END
 END rx[195]
 PIN rx[196]
  DIRECTION INPUT ;
  USE SIGNAL ;
  PORT
   LAYER M5 ;
   RECT 53.1840 0.0000 53.2080 0.0840 ;
  END
 END rx[196]
 PIN rx[197]
  DIRECTION INPUT ;
  USE SIGNAL ;
  PORT
   LAYER M5 ;
   RECT 53.4240 0.0000 53.4480 0.0840 ;
  END
 END rx[197]
 PIN rx[198]
  DIRECTION INPUT ;
  USE SIGNAL ;
  PORT
   LAYER M5 ;
   RECT 53.6640 0.0000 53.6880 0.0840 ;
  END
 END rx[198]
 PIN rx[199]
  DIRECTION INPUT ;
  USE SIGNAL ;
  PORT
   LAYER M5 ;
   RECT 53.9040 0.0000 53.9280 0.0840 ;
  END
 END rx[199]
 PIN rx[200]
  DIRECTION INPUT ;
  USE SIGNAL ;
  PORT
   LAYER M5 ;
   RECT 54.1440 0.0000 54.1680 0.0840 ;
  END
 END rx[200]
 PIN rx[201]
  DIRECTION INPUT ;
  USE SIGNAL ;
  PORT
   LAYER M5 ;
   RECT 54.3840 0.0000 54.4080 0.0840 ;
  END
 END rx[201]
 PIN rx[202]
  DIRECTION INPUT ;
  USE SIGNAL ;
  PORT
   LAYER M5 ;
   RECT 54.6240 0.0000 54.6480 0.0840 ;
  END
 END rx[202]
 PIN rx[203]
  DIRECTION INPUT ;
  USE SIGNAL ;
  PORT
   LAYER M5 ;
   RECT 54.8640 0.0000 54.8880 0.0840 ;
  END
 END rx[203]
 PIN rx[204]
  DIRECTION INPUT ;
  USE SIGNAL ;
  PORT
   LAYER M5 ;
   RECT 55.1040 0.0000 55.1280 0.0840 ;
  END
 END rx[204]
 PIN rx[205]
  DIRECTION INPUT ;
  USE SIGNAL ;
  PORT
   LAYER M5 ;
   RECT 55.3440 0.0000 55.3680 0.0840 ;
  END
 END rx[205]
 PIN rx[206]
  DIRECTION INPUT ;
  USE SIGNAL ;
  PORT
   LAYER M5 ;
   RECT 55.5840 0.0000 55.6080 0.0840 ;
  END
 END rx[206]
 PIN rx[207]
  DIRECTION INPUT ;
  USE SIGNAL ;
  PORT
   LAYER M5 ;
   RECT 55.8240 0.0000 55.8480 0.0840 ;
  END
 END rx[207]
 PIN rx[208]
  DIRECTION INPUT ;
  USE SIGNAL ;
  PORT
   LAYER M5 ;
   RECT 56.0640 0.0000 56.0880 0.0840 ;
  END
 END rx[208]
 PIN rx[209]
  DIRECTION INPUT ;
  USE SIGNAL ;
  PORT
   LAYER M5 ;
   RECT 56.3040 0.0000 56.3280 0.0840 ;
  END
 END rx[209]
 PIN rx[210]
  DIRECTION INPUT ;
  USE SIGNAL ;
  PORT
   LAYER M5 ;
   RECT 56.5440 0.0000 56.5680 0.0840 ;
  END
 END rx[210]
 PIN rx[211]
  DIRECTION INPUT ;
  USE SIGNAL ;
  PORT
   LAYER M5 ;
   RECT 56.7840 0.0000 56.8080 0.0840 ;
  END
 END rx[211]
 PIN rx[212]
  DIRECTION INPUT ;
  USE SIGNAL ;
  PORT
   LAYER M5 ;
   RECT 57.0240 0.0000 57.0480 0.0840 ;
  END
 END rx[212]
 PIN rx[213]
  DIRECTION INPUT ;
  USE SIGNAL ;
  PORT
   LAYER M5 ;
   RECT 57.2640 0.0000 57.2880 0.0840 ;
  END
 END rx[213]
 PIN rx[214]
  DIRECTION INPUT ;
  USE SIGNAL ;
  PORT
   LAYER M5 ;
   RECT 57.5040 0.0000 57.5280 0.0840 ;
  END
 END rx[214]
 PIN rx[215]
  DIRECTION INPUT ;
  USE SIGNAL ;
  PORT
   LAYER M5 ;
   RECT 57.7440 0.0000 57.7680 0.0840 ;
  END
 END rx[215]
 PIN rx[216]
  DIRECTION INPUT ;
  USE SIGNAL ;
  PORT
   LAYER M5 ;
   RECT 57.9840 0.0000 58.0080 0.0840 ;
  END
 END rx[216]
 PIN rx[217]
  DIRECTION INPUT ;
  USE SIGNAL ;
  PORT
   LAYER M5 ;
   RECT 58.2240 0.0000 58.2480 0.0840 ;
  END
 END rx[217]
 PIN rx[218]
  DIRECTION INPUT ;
  USE SIGNAL ;
  PORT
   LAYER M5 ;
   RECT 58.4640 0.0000 58.4880 0.0840 ;
  END
 END rx[218]
 PIN rx[219]
  DIRECTION INPUT ;
  USE SIGNAL ;
  PORT
   LAYER M5 ;
   RECT 58.7040 0.0000 58.7280 0.0840 ;
  END
 END rx[219]
 PIN rx[220]
  DIRECTION INPUT ;
  USE SIGNAL ;
  PORT
   LAYER M5 ;
   RECT 58.9440 0.0000 58.9680 0.0840 ;
  END
 END rx[220]
 PIN rx[221]
  DIRECTION INPUT ;
  USE SIGNAL ;
  PORT
   LAYER M5 ;
   RECT 59.1840 0.0000 59.2080 0.0840 ;
  END
 END rx[221]
 PIN rx[222]
  DIRECTION INPUT ;
  USE SIGNAL ;
  PORT
   LAYER M5 ;
   RECT 59.4240 0.0000 59.4480 0.0840 ;
  END
 END rx[222]
 PIN rx[223]
  DIRECTION INPUT ;
  USE SIGNAL ;
  PORT
   LAYER M5 ;
   RECT 59.6640 0.0000 59.6880 0.0840 ;
  END
 END rx[223]
 PIN rx[224]
  DIRECTION INPUT ;
  USE SIGNAL ;
  PORT
   LAYER M5 ;
   RECT 59.9040 0.0000 59.9280 0.0840 ;
  END
 END rx[224]
 PIN rx[225]
  DIRECTION INPUT ;
  USE SIGNAL ;
  PORT
   LAYER M5 ;
   RECT 60.1440 0.0000 60.1680 0.0840 ;
  END
 END rx[225]
 PIN rx[226]
  DIRECTION INPUT ;
  USE SIGNAL ;
  PORT
   LAYER M5 ;
   RECT 60.3840 0.0000 60.4080 0.0840 ;
  END
 END rx[226]
 PIN rx[227]
  DIRECTION INPUT ;
  USE SIGNAL ;
  PORT
   LAYER M5 ;
   RECT 60.6240 0.0000 60.6480 0.0840 ;
  END
 END rx[227]
 PIN rx[228]
  DIRECTION INPUT ;
  USE SIGNAL ;
  PORT
   LAYER M5 ;
   RECT 60.8640 0.0000 60.8880 0.0840 ;
  END
 END rx[228]
 PIN rx[229]
  DIRECTION INPUT ;
  USE SIGNAL ;
  PORT
   LAYER M5 ;
   RECT 61.1040 0.0000 61.1280 0.0840 ;
  END
 END rx[229]
 PIN rx[230]
  DIRECTION INPUT ;
  USE SIGNAL ;
  PORT
   LAYER M5 ;
   RECT 61.3440 0.0000 61.3680 0.0840 ;
  END
 END rx[230]
 PIN rx[231]
  DIRECTION INPUT ;
  USE SIGNAL ;
  PORT
   LAYER M5 ;
   RECT 61.5840 0.0000 61.6080 0.0840 ;
  END
 END rx[231]
 PIN rx[232]
  DIRECTION INPUT ;
  USE SIGNAL ;
  PORT
   LAYER M5 ;
   RECT 61.8240 0.0000 61.8480 0.0840 ;
  END
 END rx[232]
 PIN rx[233]
  DIRECTION INPUT ;
  USE SIGNAL ;
  PORT
   LAYER M5 ;
   RECT 62.0640 0.0000 62.0880 0.0840 ;
  END
 END rx[233]
 PIN rx[234]
  DIRECTION INPUT ;
  USE SIGNAL ;
  PORT
   LAYER M5 ;
   RECT 62.3040 0.0000 62.3280 0.0840 ;
  END
 END rx[234]
 PIN rx[235]
  DIRECTION INPUT ;
  USE SIGNAL ;
  PORT
   LAYER M5 ;
   RECT 62.5440 0.0000 62.5680 0.0840 ;
  END
 END rx[235]
 PIN rx[236]
  DIRECTION INPUT ;
  USE SIGNAL ;
  PORT
   LAYER M5 ;
   RECT 62.7840 0.0000 62.8080 0.0840 ;
  END
 END rx[236]
 PIN rx[237]
  DIRECTION INPUT ;
  USE SIGNAL ;
  PORT
   LAYER M5 ;
   RECT 63.0240 0.0000 63.0480 0.0840 ;
  END
 END rx[237]
 PIN rx[238]
  DIRECTION INPUT ;
  USE SIGNAL ;
  PORT
   LAYER M5 ;
   RECT 63.2640 0.0000 63.2880 0.0840 ;
  END
 END rx[238]
 PIN rx[239]
  DIRECTION INPUT ;
  USE SIGNAL ;
  PORT
   LAYER M5 ;
   RECT 63.5040 0.0000 63.5280 0.0840 ;
  END
 END rx[239]
 PIN rx[240]
  DIRECTION INPUT ;
  USE SIGNAL ;
  PORT
   LAYER M5 ;
   RECT 63.7440 0.0000 63.7680 0.0840 ;
  END
 END rx[240]
 PIN rx[241]
  DIRECTION INPUT ;
  USE SIGNAL ;
  PORT
   LAYER M5 ;
   RECT 63.9840 0.0000 64.0080 0.0840 ;
  END
 END rx[241]
 PIN rx[242]
  DIRECTION INPUT ;
  USE SIGNAL ;
  PORT
   LAYER M5 ;
   RECT 64.2240 0.0000 64.2480 0.0840 ;
  END
 END rx[242]
 PIN rx[243]
  DIRECTION INPUT ;
  USE SIGNAL ;
  PORT
   LAYER M5 ;
   RECT 64.4640 0.0000 64.4880 0.0840 ;
  END
 END rx[243]
 PIN rx[244]
  DIRECTION INPUT ;
  USE SIGNAL ;
  PORT
   LAYER M5 ;
   RECT 64.7040 0.0000 64.7280 0.0840 ;
  END
 END rx[244]
 PIN rx[245]
  DIRECTION INPUT ;
  USE SIGNAL ;
  PORT
   LAYER M5 ;
   RECT 64.9440 0.0000 64.9680 0.0840 ;
  END
 END rx[245]
 PIN rx[246]
  DIRECTION INPUT ;
  USE SIGNAL ;
  PORT
   LAYER M5 ;
   RECT 65.1840 0.0000 65.2080 0.0840 ;
  END
 END rx[246]
 PIN rx[247]
  DIRECTION INPUT ;
  USE SIGNAL ;
  PORT
   LAYER M5 ;
   RECT 65.4240 0.0000 65.4480 0.0840 ;
  END
 END rx[247]
 PIN rx[248]
  DIRECTION INPUT ;
  USE SIGNAL ;
  PORT
   LAYER M5 ;
   RECT 65.6640 0.0000 65.6880 0.0840 ;
  END
 END rx[248]
 PIN rx[249]
  DIRECTION INPUT ;
  USE SIGNAL ;
  PORT
   LAYER M5 ;
   RECT 65.9040 0.0000 65.9280 0.0840 ;
  END
 END rx[249]
 PIN rx[250]
  DIRECTION INPUT ;
  USE SIGNAL ;
  PORT
   LAYER M5 ;
   RECT 66.1440 0.0000 66.1680 0.0840 ;
  END
 END rx[250]
 PIN rx[251]
  DIRECTION INPUT ;
  USE SIGNAL ;
  PORT
   LAYER M5 ;
   RECT 66.3840 0.0000 66.4080 0.0840 ;
  END
 END rx[251]
 PIN rx[252]
  DIRECTION INPUT ;
  USE SIGNAL ;
  PORT
   LAYER M5 ;
   RECT 66.6240 0.0000 66.6480 0.0840 ;
  END
 END rx[252]
 PIN rx[253]
  DIRECTION INPUT ;
  USE SIGNAL ;
  PORT
   LAYER M5 ;
   RECT 66.8640 0.0000 66.8880 0.0840 ;
  END
 END rx[253]
 PIN rx[254]
  DIRECTION INPUT ;
  USE SIGNAL ;
  PORT
   LAYER M5 ;
   RECT 67.1040 0.0000 67.1280 0.0840 ;
  END
 END rx[254]
 PIN rx[255]
  DIRECTION INPUT ;
  USE SIGNAL ;
  PORT
   LAYER M5 ;
   RECT 67.3440 0.0000 67.3680 0.0840 ;
  END
 END rx[255]
 PIN rx[256]
  DIRECTION INPUT ;
  USE SIGNAL ;
  PORT
   LAYER M5 ;
   RECT 67.5840 0.0000 67.6080 0.0840 ;
  END
 END rx[256]
 PIN rx[257]
  DIRECTION INPUT ;
  USE SIGNAL ;
  PORT
   LAYER M5 ;
   RECT 67.8240 0.0000 67.8480 0.0840 ;
  END
 END rx[257]
 PIN rx[258]
  DIRECTION INPUT ;
  USE SIGNAL ;
  PORT
   LAYER M5 ;
   RECT 68.0640 0.0000 68.0880 0.0840 ;
  END
 END rx[258]
 PIN rx[259]
  DIRECTION INPUT ;
  USE SIGNAL ;
  PORT
   LAYER M5 ;
   RECT 68.3040 0.0000 68.3280 0.0840 ;
  END
 END rx[259]
 PIN rx[260]
  DIRECTION INPUT ;
  USE SIGNAL ;
  PORT
   LAYER M5 ;
   RECT 68.5440 0.0000 68.5680 0.0840 ;
  END
 END rx[260]
 PIN rx[261]
  DIRECTION INPUT ;
  USE SIGNAL ;
  PORT
   LAYER M5 ;
   RECT 68.7840 0.0000 68.8080 0.0840 ;
  END
 END rx[261]
 PIN rx[262]
  DIRECTION INPUT ;
  USE SIGNAL ;
  PORT
   LAYER M5 ;
   RECT 69.0240 0.0000 69.0480 0.0840 ;
  END
 END rx[262]
 PIN rx[263]
  DIRECTION INPUT ;
  USE SIGNAL ;
  PORT
   LAYER M5 ;
   RECT 69.2640 0.0000 69.2880 0.0840 ;
  END
 END rx[263]
 PIN rx[264]
  DIRECTION INPUT ;
  USE SIGNAL ;
  PORT
   LAYER M5 ;
   RECT 69.5040 0.0000 69.5280 0.0840 ;
  END
 END rx[264]
 PIN rx[265]
  DIRECTION INPUT ;
  USE SIGNAL ;
  PORT
   LAYER M5 ;
   RECT 69.7440 0.0000 69.7680 0.0840 ;
  END
 END rx[265]
 PIN rx[266]
  DIRECTION INPUT ;
  USE SIGNAL ;
  PORT
   LAYER M5 ;
   RECT 69.9840 0.0000 70.0080 0.0840 ;
  END
 END rx[266]
 PIN rx[267]
  DIRECTION INPUT ;
  USE SIGNAL ;
  PORT
   LAYER M5 ;
   RECT 70.2240 0.0000 70.2480 0.0840 ;
  END
 END rx[267]
 PIN rx[268]
  DIRECTION INPUT ;
  USE SIGNAL ;
  PORT
   LAYER M5 ;
   RECT 70.4640 0.0000 70.4880 0.0840 ;
  END
 END rx[268]
 PIN rx[269]
  DIRECTION INPUT ;
  USE SIGNAL ;
  PORT
   LAYER M5 ;
   RECT 70.7040 0.0000 70.7280 0.0840 ;
  END
 END rx[269]
 PIN rx[270]
  DIRECTION INPUT ;
  USE SIGNAL ;
  PORT
   LAYER M5 ;
   RECT 70.9440 0.0000 70.9680 0.0840 ;
  END
 END rx[270]
 PIN rx[271]
  DIRECTION INPUT ;
  USE SIGNAL ;
  PORT
   LAYER M5 ;
   RECT 71.1840 0.0000 71.2080 0.0840 ;
  END
 END rx[271]
 PIN rx[272]
  DIRECTION INPUT ;
  USE SIGNAL ;
  PORT
   LAYER M5 ;
   RECT 71.4240 0.0000 71.4480 0.0840 ;
  END
 END rx[272]
 PIN rx[273]
  DIRECTION INPUT ;
  USE SIGNAL ;
  PORT
   LAYER M5 ;
   RECT 71.6640 0.0000 71.6880 0.0840 ;
  END
 END rx[273]
 PIN rx[274]
  DIRECTION INPUT ;
  USE SIGNAL ;
  PORT
   LAYER M5 ;
   RECT 71.9040 0.0000 71.9280 0.0840 ;
  END
 END rx[274]
 PIN rx[275]
  DIRECTION INPUT ;
  USE SIGNAL ;
  PORT
   LAYER M5 ;
   RECT 72.1440 0.0000 72.1680 0.0840 ;
  END
 END rx[275]
 PIN rx[276]
  DIRECTION INPUT ;
  USE SIGNAL ;
  PORT
   LAYER M5 ;
   RECT 72.3840 0.0000 72.4080 0.0840 ;
  END
 END rx[276]
 PIN rx[277]
  DIRECTION INPUT ;
  USE SIGNAL ;
  PORT
   LAYER M5 ;
   RECT 72.6240 0.0000 72.6480 0.0840 ;
  END
 END rx[277]
 PIN rx[278]
  DIRECTION INPUT ;
  USE SIGNAL ;
  PORT
   LAYER M5 ;
   RECT 72.8640 0.0000 72.8880 0.0840 ;
  END
 END rx[278]
 PIN rx[279]
  DIRECTION INPUT ;
  USE SIGNAL ;
  PORT
   LAYER M5 ;
   RECT 73.1040 0.0000 73.1280 0.0840 ;
  END
 END rx[279]
 PIN rx[280]
  DIRECTION INPUT ;
  USE SIGNAL ;
  PORT
   LAYER M5 ;
   RECT 73.3440 0.0000 73.3680 0.0840 ;
  END
 END rx[280]
 PIN rx[281]
  DIRECTION INPUT ;
  USE SIGNAL ;
  PORT
   LAYER M5 ;
   RECT 73.5840 0.0000 73.6080 0.0840 ;
  END
 END rx[281]
 PIN rx[282]
  DIRECTION INPUT ;
  USE SIGNAL ;
  PORT
   LAYER M5 ;
   RECT 73.8240 0.0000 73.8480 0.0840 ;
  END
 END rx[282]
 PIN rx[283]
  DIRECTION INPUT ;
  USE SIGNAL ;
  PORT
   LAYER M5 ;
   RECT 74.0640 0.0000 74.0880 0.0840 ;
  END
 END rx[283]
 PIN rx[284]
  DIRECTION INPUT ;
  USE SIGNAL ;
  PORT
   LAYER M5 ;
   RECT 74.3040 0.0000 74.3280 0.0840 ;
  END
 END rx[284]
 PIN rx[285]
  DIRECTION INPUT ;
  USE SIGNAL ;
  PORT
   LAYER M5 ;
   RECT 74.5440 0.0000 74.5680 0.0840 ;
  END
 END rx[285]
 PIN rx[286]
  DIRECTION INPUT ;
  USE SIGNAL ;
  PORT
   LAYER M5 ;
   RECT 74.7840 0.0000 74.8080 0.0840 ;
  END
 END rx[286]
 PIN rx[287]
  DIRECTION INPUT ;
  USE SIGNAL ;
  PORT
   LAYER M5 ;
   RECT 75.0240 0.0000 75.0480 0.0840 ;
  END
 END rx[287]
 PIN rx[288]
  DIRECTION INPUT ;
  USE SIGNAL ;
  PORT
   LAYER M5 ;
   RECT 75.2640 0.0000 75.2880 0.0840 ;
  END
 END rx[288]
 PIN rx[289]
  DIRECTION INPUT ;
  USE SIGNAL ;
  PORT
   LAYER M5 ;
   RECT 75.5040 0.0000 75.5280 0.0840 ;
  END
 END rx[289]
 PIN rx[290]
  DIRECTION INPUT ;
  USE SIGNAL ;
  PORT
   LAYER M5 ;
   RECT 75.7440 0.0000 75.7680 0.0840 ;
  END
 END rx[290]
 PIN rx[291]
  DIRECTION INPUT ;
  USE SIGNAL ;
  PORT
   LAYER M5 ;
   RECT 75.9840 0.0000 76.0080 0.0840 ;
  END
 END rx[291]
 PIN rx[292]
  DIRECTION INPUT ;
  USE SIGNAL ;
  PORT
   LAYER M5 ;
   RECT 76.2240 0.0000 76.2480 0.0840 ;
  END
 END rx[292]
 PIN rx[293]
  DIRECTION INPUT ;
  USE SIGNAL ;
  PORT
   LAYER M5 ;
   RECT 76.4640 0.0000 76.4880 0.0840 ;
  END
 END rx[293]
 PIN rx[294]
  DIRECTION INPUT ;
  USE SIGNAL ;
  PORT
   LAYER M5 ;
   RECT 76.7040 0.0000 76.7280 0.0840 ;
  END
 END rx[294]
 PIN rx[295]
  DIRECTION INPUT ;
  USE SIGNAL ;
  PORT
   LAYER M5 ;
   RECT 76.9440 0.0000 76.9680 0.0840 ;
  END
 END rx[295]
 PIN rx[296]
  DIRECTION INPUT ;
  USE SIGNAL ;
  PORT
   LAYER M5 ;
   RECT 77.1840 0.0000 77.2080 0.0840 ;
  END
 END rx[296]
 PIN rx[297]
  DIRECTION INPUT ;
  USE SIGNAL ;
  PORT
   LAYER M5 ;
   RECT 77.4240 0.0000 77.4480 0.0840 ;
  END
 END rx[297]
 PIN rx[298]
  DIRECTION INPUT ;
  USE SIGNAL ;
  PORT
   LAYER M5 ;
   RECT 77.6640 0.0000 77.6880 0.0840 ;
  END
 END rx[298]
 PIN rx[299]
  DIRECTION INPUT ;
  USE SIGNAL ;
  PORT
   LAYER M5 ;
   RECT 77.9040 0.0000 77.9280 0.0840 ;
  END
 END rx[299]
 PIN rx[300]
  DIRECTION INPUT ;
  USE SIGNAL ;
  PORT
   LAYER M5 ;
   RECT 78.1440 0.0000 78.1680 0.0840 ;
  END
 END rx[300]
 PIN rx[301]
  DIRECTION INPUT ;
  USE SIGNAL ;
  PORT
   LAYER M5 ;
   RECT 78.3840 0.0000 78.4080 0.0840 ;
  END
 END rx[301]
 PIN rx[302]
  DIRECTION INPUT ;
  USE SIGNAL ;
  PORT
   LAYER M5 ;
   RECT 78.6240 0.0000 78.6480 0.0840 ;
  END
 END rx[302]
 PIN rx[303]
  DIRECTION INPUT ;
  USE SIGNAL ;
  PORT
   LAYER M5 ;
   RECT 78.8640 0.0000 78.8880 0.0840 ;
  END
 END rx[303]
 PIN rx[304]
  DIRECTION INPUT ;
  USE SIGNAL ;
  PORT
   LAYER M5 ;
   RECT 79.1040 0.0000 79.1280 0.0840 ;
  END
 END rx[304]
 PIN rx[305]
  DIRECTION INPUT ;
  USE SIGNAL ;
  PORT
   LAYER M5 ;
   RECT 79.3440 0.0000 79.3680 0.0840 ;
  END
 END rx[305]
 PIN rx[306]
  DIRECTION INPUT ;
  USE SIGNAL ;
  PORT
   LAYER M5 ;
   RECT 79.5840 0.0000 79.6080 0.0840 ;
  END
 END rx[306]
 PIN rx[307]
  DIRECTION INPUT ;
  USE SIGNAL ;
  PORT
   LAYER M5 ;
   RECT 79.8240 0.0000 79.8480 0.0840 ;
  END
 END rx[307]
 PIN rx[308]
  DIRECTION INPUT ;
  USE SIGNAL ;
  PORT
   LAYER M5 ;
   RECT 80.0640 0.0000 80.0880 0.0840 ;
  END
 END rx[308]
 PIN rx[309]
  DIRECTION INPUT ;
  USE SIGNAL ;
  PORT
   LAYER M5 ;
   RECT 80.3040 0.0000 80.3280 0.0840 ;
  END
 END rx[309]
 PIN rx[310]
  DIRECTION INPUT ;
  USE SIGNAL ;
  PORT
   LAYER M5 ;
   RECT 80.5440 0.0000 80.5680 0.0840 ;
  END
 END rx[310]
 PIN rx[311]
  DIRECTION INPUT ;
  USE SIGNAL ;
  PORT
   LAYER M5 ;
   RECT 80.7840 0.0000 80.8080 0.0840 ;
  END
 END rx[311]
 PIN rx[312]
  DIRECTION INPUT ;
  USE SIGNAL ;
  PORT
   LAYER M5 ;
   RECT 81.0240 0.0000 81.0480 0.0840 ;
  END
 END rx[312]
 PIN rx[313]
  DIRECTION INPUT ;
  USE SIGNAL ;
  PORT
   LAYER M5 ;
   RECT 81.2640 0.0000 81.2880 0.0840 ;
  END
 END rx[313]
 PIN rx[314]
  DIRECTION INPUT ;
  USE SIGNAL ;
  PORT
   LAYER M5 ;
   RECT 81.5040 0.0000 81.5280 0.0840 ;
  END
 END rx[314]
 PIN rx[315]
  DIRECTION INPUT ;
  USE SIGNAL ;
  PORT
   LAYER M5 ;
   RECT 81.7440 0.0000 81.7680 0.0840 ;
  END
 END rx[315]
 PIN rx[316]
  DIRECTION INPUT ;
  USE SIGNAL ;
  PORT
   LAYER M5 ;
   RECT 81.9840 0.0000 82.0080 0.0840 ;
  END
 END rx[316]
 PIN rx[317]
  DIRECTION INPUT ;
  USE SIGNAL ;
  PORT
   LAYER M5 ;
   RECT 82.2240 0.0000 82.2480 0.0840 ;
  END
 END rx[317]
 PIN rx[318]
  DIRECTION INPUT ;
  USE SIGNAL ;
  PORT
   LAYER M5 ;
   RECT 82.4640 0.0000 82.4880 0.0840 ;
  END
 END rx[318]
 PIN rx[319]
  DIRECTION INPUT ;
  USE SIGNAL ;
  PORT
   LAYER M5 ;
   RECT 82.7040 0.0000 82.7280 0.0840 ;
  END
 END rx[319]
 PIN rx[320]
  DIRECTION INPUT ;
  USE SIGNAL ;
  PORT
   LAYER M5 ;
   RECT 82.9440 0.0000 82.9680 0.0840 ;
  END
 END rx[320]
 PIN rx[321]
  DIRECTION INPUT ;
  USE SIGNAL ;
  PORT
   LAYER M5 ;
   RECT 83.1840 0.0000 83.2080 0.0840 ;
  END
 END rx[321]
 PIN rx[322]
  DIRECTION INPUT ;
  USE SIGNAL ;
  PORT
   LAYER M5 ;
   RECT 83.4240 0.0000 83.4480 0.0840 ;
  END
 END rx[322]
 PIN rx[323]
  DIRECTION INPUT ;
  USE SIGNAL ;
  PORT
   LAYER M5 ;
   RECT 83.6640 0.0000 83.6880 0.0840 ;
  END
 END rx[323]
 PIN rx[324]
  DIRECTION INPUT ;
  USE SIGNAL ;
  PORT
   LAYER M5 ;
   RECT 83.9040 0.0000 83.9280 0.0840 ;
  END
 END rx[324]
 PIN rx[325]
  DIRECTION INPUT ;
  USE SIGNAL ;
  PORT
   LAYER M5 ;
   RECT 84.1440 0.0000 84.1680 0.0840 ;
  END
 END rx[325]
 PIN rx[326]
  DIRECTION INPUT ;
  USE SIGNAL ;
  PORT
   LAYER M5 ;
   RECT 84.3840 0.0000 84.4080 0.0840 ;
  END
 END rx[326]
 PIN rx[327]
  DIRECTION INPUT ;
  USE SIGNAL ;
  PORT
   LAYER M5 ;
   RECT 84.6240 0.0000 84.6480 0.0840 ;
  END
 END rx[327]
 PIN rx[328]
  DIRECTION INPUT ;
  USE SIGNAL ;
  PORT
   LAYER M5 ;
   RECT 84.8640 0.0000 84.8880 0.0840 ;
  END
 END rx[328]
 PIN rx[329]
  DIRECTION INPUT ;
  USE SIGNAL ;
  PORT
   LAYER M5 ;
   RECT 85.1040 0.0000 85.1280 0.0840 ;
  END
 END rx[329]
 PIN rx[330]
  DIRECTION INPUT ;
  USE SIGNAL ;
  PORT
   LAYER M5 ;
   RECT 85.3440 0.0000 85.3680 0.0840 ;
  END
 END rx[330]
 PIN rx[331]
  DIRECTION INPUT ;
  USE SIGNAL ;
  PORT
   LAYER M5 ;
   RECT 85.5840 0.0000 85.6080 0.0840 ;
  END
 END rx[331]
 PIN rx[332]
  DIRECTION INPUT ;
  USE SIGNAL ;
  PORT
   LAYER M5 ;
   RECT 85.8240 0.0000 85.8480 0.0840 ;
  END
 END rx[332]
 PIN rx[333]
  DIRECTION INPUT ;
  USE SIGNAL ;
  PORT
   LAYER M5 ;
   RECT 86.0640 0.0000 86.0880 0.0840 ;
  END
 END rx[333]
 PIN rx[334]
  DIRECTION INPUT ;
  USE SIGNAL ;
  PORT
   LAYER M5 ;
   RECT 86.3040 0.0000 86.3280 0.0840 ;
  END
 END rx[334]
 PIN rx[335]
  DIRECTION INPUT ;
  USE SIGNAL ;
  PORT
   LAYER M5 ;
   RECT 86.5440 0.0000 86.5680 0.0840 ;
  END
 END rx[335]
 PIN rx[336]
  DIRECTION INPUT ;
  USE SIGNAL ;
  PORT
   LAYER M5 ;
   RECT 86.7840 0.0000 86.8080 0.0840 ;
  END
 END rx[336]
 PIN rx[337]
  DIRECTION INPUT ;
  USE SIGNAL ;
  PORT
   LAYER M5 ;
   RECT 87.0240 0.0000 87.0480 0.0840 ;
  END
 END rx[337]
 PIN rx[338]
  DIRECTION INPUT ;
  USE SIGNAL ;
  PORT
   LAYER M5 ;
   RECT 87.2640 0.0000 87.2880 0.0840 ;
  END
 END rx[338]
 PIN rx[339]
  DIRECTION INPUT ;
  USE SIGNAL ;
  PORT
   LAYER M5 ;
   RECT 87.5040 0.0000 87.5280 0.0840 ;
  END
 END rx[339]
 PIN rx[340]
  DIRECTION INPUT ;
  USE SIGNAL ;
  PORT
   LAYER M5 ;
   RECT 87.7440 0.0000 87.7680 0.0840 ;
  END
 END rx[340]
 PIN rx[341]
  DIRECTION INPUT ;
  USE SIGNAL ;
  PORT
   LAYER M5 ;
   RECT 87.9840 0.0000 88.0080 0.0840 ;
  END
 END rx[341]
 PIN rx[342]
  DIRECTION INPUT ;
  USE SIGNAL ;
  PORT
   LAYER M5 ;
   RECT 88.2240 0.0000 88.2480 0.0840 ;
  END
 END rx[342]
 PIN rx[343]
  DIRECTION INPUT ;
  USE SIGNAL ;
  PORT
   LAYER M5 ;
   RECT 88.4640 0.0000 88.4880 0.0840 ;
  END
 END rx[343]
 PIN rx[344]
  DIRECTION INPUT ;
  USE SIGNAL ;
  PORT
   LAYER M5 ;
   RECT 88.7040 0.0000 88.7280 0.0840 ;
  END
 END rx[344]
 PIN rx[345]
  DIRECTION INPUT ;
  USE SIGNAL ;
  PORT
   LAYER M5 ;
   RECT 88.9440 0.0000 88.9680 0.0840 ;
  END
 END rx[345]
 PIN rx[346]
  DIRECTION INPUT ;
  USE SIGNAL ;
  PORT
   LAYER M5 ;
   RECT 89.1840 0.0000 89.2080 0.0840 ;
  END
 END rx[346]
 PIN rx[347]
  DIRECTION INPUT ;
  USE SIGNAL ;
  PORT
   LAYER M5 ;
   RECT 89.4240 0.0000 89.4480 0.0840 ;
  END
 END rx[347]
 PIN rx[348]
  DIRECTION INPUT ;
  USE SIGNAL ;
  PORT
   LAYER M5 ;
   RECT 89.6640 0.0000 89.6880 0.0840 ;
  END
 END rx[348]
 PIN rx[349]
  DIRECTION INPUT ;
  USE SIGNAL ;
  PORT
   LAYER M5 ;
   RECT 89.9040 0.0000 89.9280 0.0840 ;
  END
 END rx[349]
 PIN rx[350]
  DIRECTION INPUT ;
  USE SIGNAL ;
  PORT
   LAYER M5 ;
   RECT 90.1440 0.0000 90.1680 0.0840 ;
  END
 END rx[350]
 PIN rx[351]
  DIRECTION INPUT ;
  USE SIGNAL ;
  PORT
   LAYER M5 ;
   RECT 90.3840 0.0000 90.4080 0.0840 ;
  END
 END rx[351]
 PIN rx[352]
  DIRECTION INPUT ;
  USE SIGNAL ;
  PORT
   LAYER M5 ;
   RECT 90.6240 0.0000 90.6480 0.0840 ;
  END
 END rx[352]
 PIN rx[353]
  DIRECTION INPUT ;
  USE SIGNAL ;
  PORT
   LAYER M5 ;
   RECT 90.8640 0.0000 90.8880 0.0840 ;
  END
 END rx[353]
 PIN rx[354]
  DIRECTION INPUT ;
  USE SIGNAL ;
  PORT
   LAYER M5 ;
   RECT 91.1040 0.0000 91.1280 0.0840 ;
  END
 END rx[354]
 PIN rx[355]
  DIRECTION INPUT ;
  USE SIGNAL ;
  PORT
   LAYER M5 ;
   RECT 91.3440 0.0000 91.3680 0.0840 ;
  END
 END rx[355]
 PIN rx[356]
  DIRECTION INPUT ;
  USE SIGNAL ;
  PORT
   LAYER M5 ;
   RECT 91.5840 0.0000 91.6080 0.0840 ;
  END
 END rx[356]
 PIN rx[357]
  DIRECTION INPUT ;
  USE SIGNAL ;
  PORT
   LAYER M5 ;
   RECT 91.8240 0.0000 91.8480 0.0840 ;
  END
 END rx[357]
 PIN rx[358]
  DIRECTION INPUT ;
  USE SIGNAL ;
  PORT
   LAYER M5 ;
   RECT 92.0640 0.0000 92.0880 0.0840 ;
  END
 END rx[358]
 PIN rx[359]
  DIRECTION INPUT ;
  USE SIGNAL ;
  PORT
   LAYER M5 ;
   RECT 92.3040 0.0000 92.3280 0.0840 ;
  END
 END rx[359]
 PIN rx[360]
  DIRECTION INPUT ;
  USE SIGNAL ;
  PORT
   LAYER M5 ;
   RECT 92.5440 0.0000 92.5680 0.0840 ;
  END
 END rx[360]
 PIN rx[361]
  DIRECTION INPUT ;
  USE SIGNAL ;
  PORT
   LAYER M5 ;
   RECT 92.7840 0.0000 92.8080 0.0840 ;
  END
 END rx[361]
 PIN rx[362]
  DIRECTION INPUT ;
  USE SIGNAL ;
  PORT
   LAYER M5 ;
   RECT 93.0240 0.0000 93.0480 0.0840 ;
  END
 END rx[362]
 PIN rx[363]
  DIRECTION INPUT ;
  USE SIGNAL ;
  PORT
   LAYER M5 ;
   RECT 93.2640 0.0000 93.2880 0.0840 ;
  END
 END rx[363]
 PIN rx[364]
  DIRECTION INPUT ;
  USE SIGNAL ;
  PORT
   LAYER M5 ;
   RECT 93.5040 0.0000 93.5280 0.0840 ;
  END
 END rx[364]
 PIN rx[365]
  DIRECTION INPUT ;
  USE SIGNAL ;
  PORT
   LAYER M5 ;
   RECT 93.7440 0.0000 93.7680 0.0840 ;
  END
 END rx[365]
 PIN rx[366]
  DIRECTION INPUT ;
  USE SIGNAL ;
  PORT
   LAYER M5 ;
   RECT 93.9840 0.0000 94.0080 0.0840 ;
  END
 END rx[366]
 PIN rx[367]
  DIRECTION INPUT ;
  USE SIGNAL ;
  PORT
   LAYER M5 ;
   RECT 94.2240 0.0000 94.2480 0.0840 ;
  END
 END rx[367]
 PIN rx[368]
  DIRECTION INPUT ;
  USE SIGNAL ;
  PORT
   LAYER M5 ;
   RECT 94.4640 0.0000 94.4880 0.0840 ;
  END
 END rx[368]
 PIN rx[369]
  DIRECTION INPUT ;
  USE SIGNAL ;
  PORT
   LAYER M5 ;
   RECT 94.7040 0.0000 94.7280 0.0840 ;
  END
 END rx[369]
 PIN rx[370]
  DIRECTION INPUT ;
  USE SIGNAL ;
  PORT
   LAYER M5 ;
   RECT 94.9440 0.0000 94.9680 0.0840 ;
  END
 END rx[370]
 PIN rx[371]
  DIRECTION INPUT ;
  USE SIGNAL ;
  PORT
   LAYER M5 ;
   RECT 95.1840 0.0000 95.2080 0.0840 ;
  END
 END rx[371]
 PIN rx[372]
  DIRECTION INPUT ;
  USE SIGNAL ;
  PORT
   LAYER M5 ;
   RECT 95.4240 0.0000 95.4480 0.0840 ;
  END
 END rx[372]
 PIN rx[373]
  DIRECTION INPUT ;
  USE SIGNAL ;
  PORT
   LAYER M5 ;
   RECT 95.6640 0.0000 95.6880 0.0840 ;
  END
 END rx[373]
 PIN rx[374]
  DIRECTION INPUT ;
  USE SIGNAL ;
  PORT
   LAYER M5 ;
   RECT 95.9040 0.0000 95.9280 0.0840 ;
  END
 END rx[374]
 PIN rx[375]
  DIRECTION INPUT ;
  USE SIGNAL ;
  PORT
   LAYER M5 ;
   RECT 96.1440 0.0000 96.1680 0.0840 ;
  END
 END rx[375]
 PIN rx[376]
  DIRECTION INPUT ;
  USE SIGNAL ;
  PORT
   LAYER M5 ;
   RECT 96.3840 0.0000 96.4080 0.0840 ;
  END
 END rx[376]
 PIN rx[377]
  DIRECTION INPUT ;
  USE SIGNAL ;
  PORT
   LAYER M5 ;
   RECT 96.6240 0.0000 96.6480 0.0840 ;
  END
 END rx[377]
 PIN rx[378]
  DIRECTION INPUT ;
  USE SIGNAL ;
  PORT
   LAYER M5 ;
   RECT 96.8640 0.0000 96.8880 0.0840 ;
  END
 END rx[378]
 PIN rx[379]
  DIRECTION INPUT ;
  USE SIGNAL ;
  PORT
   LAYER M5 ;
   RECT 97.1040 0.0000 97.1280 0.0840 ;
  END
 END rx[379]
 PIN rx[380]
  DIRECTION INPUT ;
  USE SIGNAL ;
  PORT
   LAYER M5 ;
   RECT 97.3440 0.0000 97.3680 0.0840 ;
  END
 END rx[380]
 PIN rx[381]
  DIRECTION INPUT ;
  USE SIGNAL ;
  PORT
   LAYER M5 ;
   RECT 97.5840 0.0000 97.6080 0.0840 ;
  END
 END rx[381]
 PIN rx[382]
  DIRECTION INPUT ;
  USE SIGNAL ;
  PORT
   LAYER M5 ;
   RECT 97.8240 0.0000 97.8480 0.0840 ;
  END
 END rx[382]
 PIN rx[383]
  DIRECTION INPUT ;
  USE SIGNAL ;
  PORT
   LAYER M5 ;
   RECT 98.0640 0.0000 98.0880 0.0840 ;
  END
 END rx[383]
 PIN rx[384]
  DIRECTION INPUT ;
  USE SIGNAL ;
  PORT
   LAYER M5 ;
   RECT 98.3040 0.0000 98.3280 0.0840 ;
  END
 END rx[384]
 PIN rx[385]
  DIRECTION INPUT ;
  USE SIGNAL ;
  PORT
   LAYER M5 ;
   RECT 98.5440 0.0000 98.5680 0.0840 ;
  END
 END rx[385]
 PIN rx[386]
  DIRECTION INPUT ;
  USE SIGNAL ;
  PORT
   LAYER M5 ;
   RECT 98.7840 0.0000 98.8080 0.0840 ;
  END
 END rx[386]
 PIN rx[387]
  DIRECTION INPUT ;
  USE SIGNAL ;
  PORT
   LAYER M5 ;
   RECT 99.0240 0.0000 99.0480 0.0840 ;
  END
 END rx[387]
 PIN rx[388]
  DIRECTION INPUT ;
  USE SIGNAL ;
  PORT
   LAYER M5 ;
   RECT 99.2640 0.0000 99.2880 0.0840 ;
  END
 END rx[388]
 PIN rx[389]
  DIRECTION INPUT ;
  USE SIGNAL ;
  PORT
   LAYER M5 ;
   RECT 99.5040 0.0000 99.5280 0.0840 ;
  END
 END rx[389]
 PIN rx[390]
  DIRECTION INPUT ;
  USE SIGNAL ;
  PORT
   LAYER M5 ;
   RECT 99.7440 0.0000 99.7680 0.0840 ;
  END
 END rx[390]
 PIN rx[391]
  DIRECTION INPUT ;
  USE SIGNAL ;
  PORT
   LAYER M5 ;
   RECT 99.9840 0.0000 100.0080 0.0840 ;
  END
 END rx[391]
 PIN rx[392]
  DIRECTION INPUT ;
  USE SIGNAL ;
  PORT
   LAYER M5 ;
   RECT 100.2240 0.0000 100.2480 0.0840 ;
  END
 END rx[392]
 PIN rx[393]
  DIRECTION INPUT ;
  USE SIGNAL ;
  PORT
   LAYER M5 ;
   RECT 100.4640 0.0000 100.4880 0.0840 ;
  END
 END rx[393]
 PIN rx[394]
  DIRECTION INPUT ;
  USE SIGNAL ;
  PORT
   LAYER M5 ;
   RECT 100.7040 0.0000 100.7280 0.0840 ;
  END
 END rx[394]
 PIN rx[395]
  DIRECTION INPUT ;
  USE SIGNAL ;
  PORT
   LAYER M5 ;
   RECT 100.9440 0.0000 100.9680 0.0840 ;
  END
 END rx[395]
 PIN rx[396]
  DIRECTION INPUT ;
  USE SIGNAL ;
  PORT
   LAYER M5 ;
   RECT 101.1840 0.0000 101.2080 0.0840 ;
  END
 END rx[396]
 PIN rx[397]
  DIRECTION INPUT ;
  USE SIGNAL ;
  PORT
   LAYER M5 ;
   RECT 101.4240 0.0000 101.4480 0.0840 ;
  END
 END rx[397]
 PIN rx[398]
  DIRECTION INPUT ;
  USE SIGNAL ;
  PORT
   LAYER M5 ;
   RECT 101.6640 0.0000 101.6880 0.0840 ;
  END
 END rx[398]
 PIN rx[399]
  DIRECTION INPUT ;
  USE SIGNAL ;
  PORT
   LAYER M5 ;
   RECT 101.9040 0.0000 101.9280 0.0840 ;
  END
 END rx[399]
 PIN rx[400]
  DIRECTION INPUT ;
  USE SIGNAL ;
  PORT
   LAYER M5 ;
   RECT 102.1440 0.0000 102.1680 0.0840 ;
  END
 END rx[400]
 PIN rx[401]
  DIRECTION INPUT ;
  USE SIGNAL ;
  PORT
   LAYER M5 ;
   RECT 102.3840 0.0000 102.4080 0.0840 ;
  END
 END rx[401]
 PIN rx[402]
  DIRECTION INPUT ;
  USE SIGNAL ;
  PORT
   LAYER M5 ;
   RECT 102.6240 0.0000 102.6480 0.0840 ;
  END
 END rx[402]
 PIN rx[403]
  DIRECTION INPUT ;
  USE SIGNAL ;
  PORT
   LAYER M5 ;
   RECT 102.8640 0.0000 102.8880 0.0840 ;
  END
 END rx[403]
 PIN rx[404]
  DIRECTION INPUT ;
  USE SIGNAL ;
  PORT
   LAYER M5 ;
   RECT 103.1040 0.0000 103.1280 0.0840 ;
  END
 END rx[404]
 PIN rx[405]
  DIRECTION INPUT ;
  USE SIGNAL ;
  PORT
   LAYER M5 ;
   RECT 103.3440 0.0000 103.3680 0.0840 ;
  END
 END rx[405]
 PIN rx[406]
  DIRECTION INPUT ;
  USE SIGNAL ;
  PORT
   LAYER M5 ;
   RECT 103.5840 0.0000 103.6080 0.0840 ;
  END
 END rx[406]
 PIN rx[407]
  DIRECTION INPUT ;
  USE SIGNAL ;
  PORT
   LAYER M5 ;
   RECT 103.8240 0.0000 103.8480 0.0840 ;
  END
 END rx[407]
 PIN rx[408]
  DIRECTION INPUT ;
  USE SIGNAL ;
  PORT
   LAYER M5 ;
   RECT 104.0640 0.0000 104.0880 0.0840 ;
  END
 END rx[408]
 PIN rx[409]
  DIRECTION INPUT ;
  USE SIGNAL ;
  PORT
   LAYER M5 ;
   RECT 104.3040 0.0000 104.3280 0.0840 ;
  END
 END rx[409]
 PIN rx[410]
  DIRECTION INPUT ;
  USE SIGNAL ;
  PORT
   LAYER M5 ;
   RECT 104.5440 0.0000 104.5680 0.0840 ;
  END
 END rx[410]
 PIN rx[411]
  DIRECTION INPUT ;
  USE SIGNAL ;
  PORT
   LAYER M5 ;
   RECT 104.7840 0.0000 104.8080 0.0840 ;
  END
 END rx[411]
 PIN rx[412]
  DIRECTION INPUT ;
  USE SIGNAL ;
  PORT
   LAYER M5 ;
   RECT 105.0240 0.0000 105.0480 0.0840 ;
  END
 END rx[412]
 PIN rx[413]
  DIRECTION INPUT ;
  USE SIGNAL ;
  PORT
   LAYER M5 ;
   RECT 105.2640 0.0000 105.2880 0.0840 ;
  END
 END rx[413]
 PIN rx[414]
  DIRECTION INPUT ;
  USE SIGNAL ;
  PORT
   LAYER M5 ;
   RECT 105.5040 0.0000 105.5280 0.0840 ;
  END
 END rx[414]
 PIN rx[415]
  DIRECTION INPUT ;
  USE SIGNAL ;
  PORT
   LAYER M5 ;
   RECT 105.7440 0.0000 105.7680 0.0840 ;
  END
 END rx[415]
 PIN rx[416]
  DIRECTION INPUT ;
  USE SIGNAL ;
  PORT
   LAYER M5 ;
   RECT 105.9840 0.0000 106.0080 0.0840 ;
  END
 END rx[416]
 PIN rx[417]
  DIRECTION INPUT ;
  USE SIGNAL ;
  PORT
   LAYER M5 ;
   RECT 106.2240 0.0000 106.2480 0.0840 ;
  END
 END rx[417]
 PIN rx[418]
  DIRECTION INPUT ;
  USE SIGNAL ;
  PORT
   LAYER M5 ;
   RECT 106.4640 0.0000 106.4880 0.0840 ;
  END
 END rx[418]
 PIN rx[419]
  DIRECTION INPUT ;
  USE SIGNAL ;
  PORT
   LAYER M5 ;
   RECT 106.7040 0.0000 106.7280 0.0840 ;
  END
 END rx[419]
 PIN rx[420]
  DIRECTION INPUT ;
  USE SIGNAL ;
  PORT
   LAYER M5 ;
   RECT 106.9440 0.0000 106.9680 0.0840 ;
  END
 END rx[420]
 PIN rx[421]
  DIRECTION INPUT ;
  USE SIGNAL ;
  PORT
   LAYER M5 ;
   RECT 107.1840 0.0000 107.2080 0.0840 ;
  END
 END rx[421]
 PIN rx[422]
  DIRECTION INPUT ;
  USE SIGNAL ;
  PORT
   LAYER M5 ;
   RECT 107.4240 0.0000 107.4480 0.0840 ;
  END
 END rx[422]
 PIN rx[423]
  DIRECTION INPUT ;
  USE SIGNAL ;
  PORT
   LAYER M5 ;
   RECT 107.6640 0.0000 107.6880 0.0840 ;
  END
 END rx[423]
 PIN rx[424]
  DIRECTION INPUT ;
  USE SIGNAL ;
  PORT
   LAYER M5 ;
   RECT 107.9040 0.0000 107.9280 0.0840 ;
  END
 END rx[424]
 PIN rx[425]
  DIRECTION INPUT ;
  USE SIGNAL ;
  PORT
   LAYER M5 ;
   RECT 108.1440 0.0000 108.1680 0.0840 ;
  END
 END rx[425]
 PIN rx[426]
  DIRECTION INPUT ;
  USE SIGNAL ;
  PORT
   LAYER M5 ;
   RECT 108.3840 0.0000 108.4080 0.0840 ;
  END
 END rx[426]
 PIN rx[427]
  DIRECTION INPUT ;
  USE SIGNAL ;
  PORT
   LAYER M5 ;
   RECT 108.6240 0.0000 108.6480 0.0840 ;
  END
 END rx[427]
 PIN rx[428]
  DIRECTION INPUT ;
  USE SIGNAL ;
  PORT
   LAYER M5 ;
   RECT 108.8640 0.0000 108.8880 0.0840 ;
  END
 END rx[428]
 PIN rx[429]
  DIRECTION INPUT ;
  USE SIGNAL ;
  PORT
   LAYER M5 ;
   RECT 109.1040 0.0000 109.1280 0.0840 ;
  END
 END rx[429]
 PIN rx[430]
  DIRECTION INPUT ;
  USE SIGNAL ;
  PORT
   LAYER M5 ;
   RECT 109.3440 0.0000 109.3680 0.0840 ;
  END
 END rx[430]
 PIN rx[431]
  DIRECTION INPUT ;
  USE SIGNAL ;
  PORT
   LAYER M5 ;
   RECT 109.5840 0.0000 109.6080 0.0840 ;
  END
 END rx[431]
 PIN rx[432]
  DIRECTION INPUT ;
  USE SIGNAL ;
  PORT
   LAYER M5 ;
   RECT 109.8240 0.0000 109.8480 0.0840 ;
  END
 END rx[432]
 PIN rx[433]
  DIRECTION INPUT ;
  USE SIGNAL ;
  PORT
   LAYER M5 ;
   RECT 110.0640 0.0000 110.0880 0.0840 ;
  END
 END rx[433]
 PIN rx[434]
  DIRECTION INPUT ;
  USE SIGNAL ;
  PORT
   LAYER M5 ;
   RECT 110.3040 0.0000 110.3280 0.0840 ;
  END
 END rx[434]
 PIN rx[435]
  DIRECTION INPUT ;
  USE SIGNAL ;
  PORT
   LAYER M5 ;
   RECT 110.5440 0.0000 110.5680 0.0840 ;
  END
 END rx[435]
 PIN rx[436]
  DIRECTION INPUT ;
  USE SIGNAL ;
  PORT
   LAYER M5 ;
   RECT 110.7840 0.0000 110.8080 0.0840 ;
  END
 END rx[436]
 PIN rx[437]
  DIRECTION INPUT ;
  USE SIGNAL ;
  PORT
   LAYER M5 ;
   RECT 111.0240 0.0000 111.0480 0.0840 ;
  END
 END rx[437]
 PIN rx[438]
  DIRECTION INPUT ;
  USE SIGNAL ;
  PORT
   LAYER M5 ;
   RECT 111.2640 0.0000 111.2880 0.0840 ;
  END
 END rx[438]
 PIN rx[439]
  DIRECTION INPUT ;
  USE SIGNAL ;
  PORT
   LAYER M5 ;
   RECT 111.5040 0.0000 111.5280 0.0840 ;
  END
 END rx[439]
 PIN rx[440]
  DIRECTION INPUT ;
  USE SIGNAL ;
  PORT
   LAYER M5 ;
   RECT 111.7440 0.0000 111.7680 0.0840 ;
  END
 END rx[440]
 PIN rx[441]
  DIRECTION INPUT ;
  USE SIGNAL ;
  PORT
   LAYER M5 ;
   RECT 111.9840 0.0000 112.0080 0.0840 ;
  END
 END rx[441]
 PIN rx[442]
  DIRECTION INPUT ;
  USE SIGNAL ;
  PORT
   LAYER M5 ;
   RECT 112.2240 0.0000 112.2480 0.0840 ;
  END
 END rx[442]
 PIN rx[443]
  DIRECTION INPUT ;
  USE SIGNAL ;
  PORT
   LAYER M5 ;
   RECT 112.4640 0.0000 112.4880 0.0840 ;
  END
 END rx[443]
 PIN rx[444]
  DIRECTION INPUT ;
  USE SIGNAL ;
  PORT
   LAYER M5 ;
   RECT 112.7040 0.0000 112.7280 0.0840 ;
  END
 END rx[444]
 PIN rx[445]
  DIRECTION INPUT ;
  USE SIGNAL ;
  PORT
   LAYER M5 ;
   RECT 112.9440 0.0000 112.9680 0.0840 ;
  END
 END rx[445]
 PIN rx[446]
  DIRECTION INPUT ;
  USE SIGNAL ;
  PORT
   LAYER M5 ;
   RECT 113.1840 0.0000 113.2080 0.0840 ;
  END
 END rx[446]
 PIN rx[447]
  DIRECTION INPUT ;
  USE SIGNAL ;
  PORT
   LAYER M5 ;
   RECT 113.4240 0.0000 113.4480 0.0840 ;
  END
 END rx[447]
 PIN rx[448]
  DIRECTION INPUT ;
  USE SIGNAL ;
  PORT
   LAYER M5 ;
   RECT 113.6640 0.0000 113.6880 0.0840 ;
  END
 END rx[448]
 PIN rx[449]
  DIRECTION INPUT ;
  USE SIGNAL ;
  PORT
   LAYER M5 ;
   RECT 113.9040 0.0000 113.9280 0.0840 ;
  END
 END rx[449]
 PIN rx[450]
  DIRECTION INPUT ;
  USE SIGNAL ;
  PORT
   LAYER M5 ;
   RECT 114.1440 0.0000 114.1680 0.0840 ;
  END
 END rx[450]
 PIN rx[451]
  DIRECTION INPUT ;
  USE SIGNAL ;
  PORT
   LAYER M5 ;
   RECT 114.3840 0.0000 114.4080 0.0840 ;
  END
 END rx[451]
 PIN rx[452]
  DIRECTION INPUT ;
  USE SIGNAL ;
  PORT
   LAYER M5 ;
   RECT 114.6240 0.0000 114.6480 0.0840 ;
  END
 END rx[452]
 PIN rx[453]
  DIRECTION INPUT ;
  USE SIGNAL ;
  PORT
   LAYER M5 ;
   RECT 114.8640 0.0000 114.8880 0.0840 ;
  END
 END rx[453]
 PIN rx[454]
  DIRECTION INPUT ;
  USE SIGNAL ;
  PORT
   LAYER M5 ;
   RECT 115.1040 0.0000 115.1280 0.0840 ;
  END
 END rx[454]
 PIN rx[455]
  DIRECTION INPUT ;
  USE SIGNAL ;
  PORT
   LAYER M5 ;
   RECT 115.3440 0.0000 115.3680 0.0840 ;
  END
 END rx[455]
 PIN rx[456]
  DIRECTION INPUT ;
  USE SIGNAL ;
  PORT
   LAYER M5 ;
   RECT 115.5840 0.0000 115.6080 0.0840 ;
  END
 END rx[456]
 PIN rx[457]
  DIRECTION INPUT ;
  USE SIGNAL ;
  PORT
   LAYER M5 ;
   RECT 115.8240 0.0000 115.8480 0.0840 ;
  END
 END rx[457]
 PIN rx[458]
  DIRECTION INPUT ;
  USE SIGNAL ;
  PORT
   LAYER M5 ;
   RECT 116.0640 0.0000 116.0880 0.0840 ;
  END
 END rx[458]
 PIN rx[459]
  DIRECTION INPUT ;
  USE SIGNAL ;
  PORT
   LAYER M5 ;
   RECT 116.3040 0.0000 116.3280 0.0840 ;
  END
 END rx[459]
 PIN rx[460]
  DIRECTION INPUT ;
  USE SIGNAL ;
  PORT
   LAYER M5 ;
   RECT 116.5440 0.0000 116.5680 0.0840 ;
  END
 END rx[460]
 PIN rx[461]
  DIRECTION INPUT ;
  USE SIGNAL ;
  PORT
   LAYER M5 ;
   RECT 116.7840 0.0000 116.8080 0.0840 ;
  END
 END rx[461]
 PIN rx[462]
  DIRECTION INPUT ;
  USE SIGNAL ;
  PORT
   LAYER M5 ;
   RECT 117.0240 0.0000 117.0480 0.0840 ;
  END
 END rx[462]
 PIN rx[463]
  DIRECTION INPUT ;
  USE SIGNAL ;
  PORT
   LAYER M5 ;
   RECT 117.2640 0.0000 117.2880 0.0840 ;
  END
 END rx[463]
 PIN rx[464]
  DIRECTION INPUT ;
  USE SIGNAL ;
  PORT
   LAYER M5 ;
   RECT 117.5040 0.0000 117.5280 0.0840 ;
  END
 END rx[464]
 PIN rx[465]
  DIRECTION INPUT ;
  USE SIGNAL ;
  PORT
   LAYER M5 ;
   RECT 117.7440 0.0000 117.7680 0.0840 ;
  END
 END rx[465]
 PIN rx[466]
  DIRECTION INPUT ;
  USE SIGNAL ;
  PORT
   LAYER M5 ;
   RECT 117.9840 0.0000 118.0080 0.0840 ;
  END
 END rx[466]
 PIN rx[467]
  DIRECTION INPUT ;
  USE SIGNAL ;
  PORT
   LAYER M5 ;
   RECT 118.2240 0.0000 118.2480 0.0840 ;
  END
 END rx[467]
 PIN rx[468]
  DIRECTION INPUT ;
  USE SIGNAL ;
  PORT
   LAYER M5 ;
   RECT 118.4640 0.0000 118.4880 0.0840 ;
  END
 END rx[468]
 PIN rx[469]
  DIRECTION INPUT ;
  USE SIGNAL ;
  PORT
   LAYER M5 ;
   RECT 118.7040 0.0000 118.7280 0.0840 ;
  END
 END rx[469]
 PIN rx[470]
  DIRECTION INPUT ;
  USE SIGNAL ;
  PORT
   LAYER M5 ;
   RECT 118.9440 0.0000 118.9680 0.0840 ;
  END
 END rx[470]
 PIN rx[471]
  DIRECTION INPUT ;
  USE SIGNAL ;
  PORT
   LAYER M5 ;
   RECT 119.1840 0.0000 119.2080 0.0840 ;
  END
 END rx[471]
 PIN rx[472]
  DIRECTION INPUT ;
  USE SIGNAL ;
  PORT
   LAYER M5 ;
   RECT 119.4240 0.0000 119.4480 0.0840 ;
  END
 END rx[472]
 PIN rx[473]
  DIRECTION INPUT ;
  USE SIGNAL ;
  PORT
   LAYER M5 ;
   RECT 119.6640 0.0000 119.6880 0.0840 ;
  END
 END rx[473]
 PIN rx[474]
  DIRECTION INPUT ;
  USE SIGNAL ;
  PORT
   LAYER M5 ;
   RECT 119.9040 0.0000 119.9280 0.0840 ;
  END
 END rx[474]
 PIN rx[475]
  DIRECTION INPUT ;
  USE SIGNAL ;
  PORT
   LAYER M5 ;
   RECT 120.1440 0.0000 120.1680 0.0840 ;
  END
 END rx[475]
 PIN rx[476]
  DIRECTION INPUT ;
  USE SIGNAL ;
  PORT
   LAYER M5 ;
   RECT 120.3840 0.0000 120.4080 0.0840 ;
  END
 END rx[476]
 PIN rx[477]
  DIRECTION INPUT ;
  USE SIGNAL ;
  PORT
   LAYER M5 ;
   RECT 120.6240 0.0000 120.6480 0.0840 ;
  END
 END rx[477]
 PIN rx[478]
  DIRECTION INPUT ;
  USE SIGNAL ;
  PORT
   LAYER M5 ;
   RECT 120.8640 0.0000 120.8880 0.0840 ;
  END
 END rx[478]
 PIN rx[479]
  DIRECTION INPUT ;
  USE SIGNAL ;
  PORT
   LAYER M5 ;
   RECT 121.1040 0.0000 121.1280 0.0840 ;
  END
 END rx[479]
 PIN rx[480]
  DIRECTION INPUT ;
  USE SIGNAL ;
  PORT
   LAYER M5 ;
   RECT 121.3440 0.0000 121.3680 0.0840 ;
  END
 END rx[480]
 PIN rx[481]
  DIRECTION INPUT ;
  USE SIGNAL ;
  PORT
   LAYER M5 ;
   RECT 121.5840 0.0000 121.6080 0.0840 ;
  END
 END rx[481]
 PIN rx[482]
  DIRECTION INPUT ;
  USE SIGNAL ;
  PORT
   LAYER M5 ;
   RECT 121.8240 0.0000 121.8480 0.0840 ;
  END
 END rx[482]
 PIN rx[483]
  DIRECTION INPUT ;
  USE SIGNAL ;
  PORT
   LAYER M5 ;
   RECT 122.0640 0.0000 122.0880 0.0840 ;
  END
 END rx[483]
 PIN rx[484]
  DIRECTION INPUT ;
  USE SIGNAL ;
  PORT
   LAYER M5 ;
   RECT 122.3040 0.0000 122.3280 0.0840 ;
  END
 END rx[484]
 PIN rx[485]
  DIRECTION INPUT ;
  USE SIGNAL ;
  PORT
   LAYER M5 ;
   RECT 122.5440 0.0000 122.5680 0.0840 ;
  END
 END rx[485]
 PIN rx[486]
  DIRECTION INPUT ;
  USE SIGNAL ;
  PORT
   LAYER M5 ;
   RECT 122.7840 0.0000 122.8080 0.0840 ;
  END
 END rx[486]
 PIN rx[487]
  DIRECTION INPUT ;
  USE SIGNAL ;
  PORT
   LAYER M5 ;
   RECT 123.0240 0.0000 123.0480 0.0840 ;
  END
 END rx[487]
 PIN rx[488]
  DIRECTION INPUT ;
  USE SIGNAL ;
  PORT
   LAYER M5 ;
   RECT 123.2640 0.0000 123.2880 0.0840 ;
  END
 END rx[488]
 PIN rx[489]
  DIRECTION INPUT ;
  USE SIGNAL ;
  PORT
   LAYER M5 ;
   RECT 123.5040 0.0000 123.5280 0.0840 ;
  END
 END rx[489]
 PIN rx[490]
  DIRECTION INPUT ;
  USE SIGNAL ;
  PORT
   LAYER M5 ;
   RECT 123.7440 0.0000 123.7680 0.0840 ;
  END
 END rx[490]
 PIN rx[491]
  DIRECTION INPUT ;
  USE SIGNAL ;
  PORT
   LAYER M5 ;
   RECT 123.9840 0.0000 124.0080 0.0840 ;
  END
 END rx[491]
 PIN rx[492]
  DIRECTION INPUT ;
  USE SIGNAL ;
  PORT
   LAYER M5 ;
   RECT 124.2240 0.0000 124.2480 0.0840 ;
  END
 END rx[492]
 PIN rx[493]
  DIRECTION INPUT ;
  USE SIGNAL ;
  PORT
   LAYER M5 ;
   RECT 124.4640 0.0000 124.4880 0.0840 ;
  END
 END rx[493]
 PIN rx[494]
  DIRECTION INPUT ;
  USE SIGNAL ;
  PORT
   LAYER M5 ;
   RECT 124.7040 0.0000 124.7280 0.0840 ;
  END
 END rx[494]
 PIN rx[495]
  DIRECTION INPUT ;
  USE SIGNAL ;
  PORT
   LAYER M5 ;
   RECT 124.9440 0.0000 124.9680 0.0840 ;
  END
 END rx[495]
 PIN rx[496]
  DIRECTION INPUT ;
  USE SIGNAL ;
  PORT
   LAYER M5 ;
   RECT 125.1840 0.0000 125.2080 0.0840 ;
  END
 END rx[496]
 PIN rx[497]
  DIRECTION INPUT ;
  USE SIGNAL ;
  PORT
   LAYER M5 ;
   RECT 125.4240 0.0000 125.4480 0.0840 ;
  END
 END rx[497]
 PIN rx[498]
  DIRECTION INPUT ;
  USE SIGNAL ;
  PORT
   LAYER M5 ;
   RECT 125.6640 0.0000 125.6880 0.0840 ;
  END
 END rx[498]
 PIN rx[499]
  DIRECTION INPUT ;
  USE SIGNAL ;
  PORT
   LAYER M5 ;
   RECT 125.9040 0.0000 125.9280 0.0840 ;
  END
 END rx[499]
 PIN rx[500]
  DIRECTION INPUT ;
  USE SIGNAL ;
  PORT
   LAYER M5 ;
   RECT 126.1440 0.0000 126.1680 0.0840 ;
  END
 END rx[500]
 PIN rx[501]
  DIRECTION INPUT ;
  USE SIGNAL ;
  PORT
   LAYER M5 ;
   RECT 126.3840 0.0000 126.4080 0.0840 ;
  END
 END rx[501]
 PIN rx[502]
  DIRECTION INPUT ;
  USE SIGNAL ;
  PORT
   LAYER M5 ;
   RECT 126.6240 0.0000 126.6480 0.0840 ;
  END
 END rx[502]
 PIN rx[503]
  DIRECTION INPUT ;
  USE SIGNAL ;
  PORT
   LAYER M5 ;
   RECT 126.8640 0.0000 126.8880 0.0840 ;
  END
 END rx[503]
 PIN rx[504]
  DIRECTION INPUT ;
  USE SIGNAL ;
  PORT
   LAYER M5 ;
   RECT 127.1040 0.0000 127.1280 0.0840 ;
  END
 END rx[504]
 PIN rx[505]
  DIRECTION INPUT ;
  USE SIGNAL ;
  PORT
   LAYER M5 ;
   RECT 127.3440 0.0000 127.3680 0.0840 ;
  END
 END rx[505]
 PIN rx[506]
  DIRECTION INPUT ;
  USE SIGNAL ;
  PORT
   LAYER M5 ;
   RECT 127.5840 0.0000 127.6080 0.0840 ;
  END
 END rx[506]
 PIN rx[507]
  DIRECTION INPUT ;
  USE SIGNAL ;
  PORT
   LAYER M5 ;
   RECT 127.8240 0.0000 127.8480 0.0840 ;
  END
 END rx[507]
 PIN rx[508]
  DIRECTION INPUT ;
  USE SIGNAL ;
  PORT
   LAYER M5 ;
   RECT 128.0640 0.0000 128.0880 0.0840 ;
  END
 END rx[508]
 PIN rx[509]
  DIRECTION INPUT ;
  USE SIGNAL ;
  PORT
   LAYER M5 ;
   RECT 128.3040 0.0000 128.3280 0.0840 ;
  END
 END rx[509]
 PIN rx[510]
  DIRECTION INPUT ;
  USE SIGNAL ;
  PORT
   LAYER M5 ;
   RECT 128.5440 0.0000 128.5680 0.0840 ;
  END
 END rx[510]
 PIN rx[511]
  DIRECTION INPUT ;
  USE SIGNAL ;
  PORT
   LAYER M5 ;
   RECT 128.7840 0.0000 128.8080 0.0840 ;
  END
 END rx[511]
 PIN rx[512]
  DIRECTION INPUT ;
  USE SIGNAL ;
  PORT
   LAYER M5 ;
   RECT 129.0240 0.0000 129.0480 0.0840 ;
  END
 END rx[512]
 PIN rx[513]
  DIRECTION INPUT ;
  USE SIGNAL ;
  PORT
   LAYER M5 ;
   RECT 129.2640 0.0000 129.2880 0.0840 ;
  END
 END rx[513]
 PIN rx[514]
  DIRECTION INPUT ;
  USE SIGNAL ;
  PORT
   LAYER M5 ;
   RECT 129.5040 0.0000 129.5280 0.0840 ;
  END
 END rx[514]
 PIN tx[0]
  DIRECTION OUTPUT ;
  USE SIGNAL ;
  PORT
   LAYER M5 ;
   RECT 174.2400 0.0000 174.2640 0.0840 ;
  END
 END tx[0]
 PIN tx[1]
  DIRECTION OUTPUT ;
  USE SIGNAL ;
  PORT
   LAYER M5 ;
   RECT 174.4800 0.0000 174.5040 0.0840 ;
  END
 END tx[1]
 PIN tx[2]
  DIRECTION OUTPUT ;
  USE SIGNAL ;
  PORT
   LAYER M5 ;
   RECT 174.7200 0.0000 174.7440 0.0840 ;
  END
 END tx[2]
 PIN tx[3]
  DIRECTION OUTPUT ;
  USE SIGNAL ;
  PORT
   LAYER M5 ;
   RECT 174.9600 0.0000 174.9840 0.0840 ;
  END
 END tx[3]
 PIN tx[4]
  DIRECTION OUTPUT ;
  USE SIGNAL ;
  PORT
   LAYER M5 ;
   RECT 175.2000 0.0000 175.2240 0.0840 ;
  END
 END tx[4]
 PIN tx[5]
  DIRECTION OUTPUT ;
  USE SIGNAL ;
  PORT
   LAYER M5 ;
   RECT 175.4400 0.0000 175.4640 0.0840 ;
  END
 END tx[5]
 PIN tx[6]
  DIRECTION OUTPUT ;
  USE SIGNAL ;
  PORT
   LAYER M5 ;
   RECT 175.6800 0.0000 175.7040 0.0840 ;
  END
 END tx[6]
 PIN tx[7]
  DIRECTION OUTPUT ;
  USE SIGNAL ;
  PORT
   LAYER M5 ;
   RECT 175.9200 0.0000 175.9440 0.0840 ;
  END
 END tx[7]
 PIN tx[8]
  DIRECTION OUTPUT ;
  USE SIGNAL ;
  PORT
   LAYER M5 ;
   RECT 176.1600 0.0000 176.1840 0.0840 ;
  END
 END tx[8]
 PIN tx[9]
  DIRECTION OUTPUT ;
  USE SIGNAL ;
  PORT
   LAYER M5 ;
   RECT 176.4000 0.0000 176.4240 0.0840 ;
  END
 END tx[9]
 PIN tx[10]
  DIRECTION OUTPUT ;
  USE SIGNAL ;
  PORT
   LAYER M5 ;
   RECT 176.6400 0.0000 176.6640 0.0840 ;
  END
 END tx[10]
 PIN tx[11]
  DIRECTION OUTPUT ;
  USE SIGNAL ;
  PORT
   LAYER M5 ;
   RECT 176.8800 0.0000 176.9040 0.0840 ;
  END
 END tx[11]
 PIN tx[12]
  DIRECTION OUTPUT ;
  USE SIGNAL ;
  PORT
   LAYER M5 ;
   RECT 177.1200 0.0000 177.1440 0.0840 ;
  END
 END tx[12]
 PIN tx[13]
  DIRECTION OUTPUT ;
  USE SIGNAL ;
  PORT
   LAYER M5 ;
   RECT 177.3600 0.0000 177.3840 0.0840 ;
  END
 END tx[13]
 PIN tx[14]
  DIRECTION OUTPUT ;
  USE SIGNAL ;
  PORT
   LAYER M5 ;
   RECT 177.6000 0.0000 177.6240 0.0840 ;
  END
 END tx[14]
 PIN tx[15]
  DIRECTION OUTPUT ;
  USE SIGNAL ;
  PORT
   LAYER M5 ;
   RECT 177.8400 0.0000 177.8640 0.0840 ;
  END
 END tx[15]
 PIN tx[16]
  DIRECTION OUTPUT ;
  USE SIGNAL ;
  PORT
   LAYER M5 ;
   RECT 178.0800 0.0000 178.1040 0.0840 ;
  END
 END tx[16]
 PIN tx[17]
  DIRECTION OUTPUT ;
  USE SIGNAL ;
  PORT
   LAYER M5 ;
   RECT 178.3200 0.0000 178.3440 0.0840 ;
  END
 END tx[17]
 PIN tx[18]
  DIRECTION OUTPUT ;
  USE SIGNAL ;
  PORT
   LAYER M5 ;
   RECT 178.5600 0.0000 178.5840 0.0840 ;
  END
 END tx[18]
 PIN tx[19]
  DIRECTION OUTPUT ;
  USE SIGNAL ;
  PORT
   LAYER M5 ;
   RECT 178.8000 0.0000 178.8240 0.0840 ;
  END
 END tx[19]
 PIN tx[20]
  DIRECTION OUTPUT ;
  USE SIGNAL ;
  PORT
   LAYER M5 ;
   RECT 179.0400 0.0000 179.0640 0.0840 ;
  END
 END tx[20]
 PIN tx[21]
  DIRECTION OUTPUT ;
  USE SIGNAL ;
  PORT
   LAYER M5 ;
   RECT 179.2800 0.0000 179.3040 0.0840 ;
  END
 END tx[21]
 PIN tx[22]
  DIRECTION OUTPUT ;
  USE SIGNAL ;
  PORT
   LAYER M5 ;
   RECT 179.5200 0.0000 179.5440 0.0840 ;
  END
 END tx[22]
 PIN tx[23]
  DIRECTION OUTPUT ;
  USE SIGNAL ;
  PORT
   LAYER M5 ;
   RECT 179.7600 0.0000 179.7840 0.0840 ;
  END
 END tx[23]
 PIN tx[24]
  DIRECTION OUTPUT ;
  USE SIGNAL ;
  PORT
   LAYER M5 ;
   RECT 180.0000 0.0000 180.0240 0.0840 ;
  END
 END tx[24]
 PIN tx[25]
  DIRECTION OUTPUT ;
  USE SIGNAL ;
  PORT
   LAYER M5 ;
   RECT 180.2400 0.0000 180.2640 0.0840 ;
  END
 END tx[25]
 PIN tx[26]
  DIRECTION OUTPUT ;
  USE SIGNAL ;
  PORT
   LAYER M5 ;
   RECT 180.4800 0.0000 180.5040 0.0840 ;
  END
 END tx[26]
 PIN tx[27]
  DIRECTION OUTPUT ;
  USE SIGNAL ;
  PORT
   LAYER M5 ;
   RECT 180.7200 0.0000 180.7440 0.0840 ;
  END
 END tx[27]
 PIN tx[28]
  DIRECTION OUTPUT ;
  USE SIGNAL ;
  PORT
   LAYER M5 ;
   RECT 180.9600 0.0000 180.9840 0.0840 ;
  END
 END tx[28]
 PIN tx[29]
  DIRECTION OUTPUT ;
  USE SIGNAL ;
  PORT
   LAYER M5 ;
   RECT 181.2000 0.0000 181.2240 0.0840 ;
  END
 END tx[29]
 PIN tx[30]
  DIRECTION OUTPUT ;
  USE SIGNAL ;
  PORT
   LAYER M5 ;
   RECT 181.4400 0.0000 181.4640 0.0840 ;
  END
 END tx[30]
 PIN tx[31]
  DIRECTION OUTPUT ;
  USE SIGNAL ;
  PORT
   LAYER M5 ;
   RECT 181.6800 0.0000 181.7040 0.0840 ;
  END
 END tx[31]
 PIN tx[32]
  DIRECTION OUTPUT ;
  USE SIGNAL ;
  PORT
   LAYER M5 ;
   RECT 181.9200 0.0000 181.9440 0.0840 ;
  END
 END tx[32]
 PIN tx[33]
  DIRECTION OUTPUT ;
  USE SIGNAL ;
  PORT
   LAYER M5 ;
   RECT 182.1600 0.0000 182.1840 0.0840 ;
  END
 END tx[33]
 PIN tx[34]
  DIRECTION OUTPUT ;
  USE SIGNAL ;
  PORT
   LAYER M5 ;
   RECT 182.4000 0.0000 182.4240 0.0840 ;
  END
 END tx[34]
 PIN tx[35]
  DIRECTION OUTPUT ;
  USE SIGNAL ;
  PORT
   LAYER M5 ;
   RECT 182.6400 0.0000 182.6640 0.0840 ;
  END
 END tx[35]
 PIN tx[36]
  DIRECTION OUTPUT ;
  USE SIGNAL ;
  PORT
   LAYER M5 ;
   RECT 182.8800 0.0000 182.9040 0.0840 ;
  END
 END tx[36]
 PIN tx[37]
  DIRECTION OUTPUT ;
  USE SIGNAL ;
  PORT
   LAYER M5 ;
   RECT 183.1200 0.0000 183.1440 0.0840 ;
  END
 END tx[37]
 PIN tx[38]
  DIRECTION OUTPUT ;
  USE SIGNAL ;
  PORT
   LAYER M5 ;
   RECT 183.3600 0.0000 183.3840 0.0840 ;
  END
 END tx[38]
 PIN tx[39]
  DIRECTION OUTPUT ;
  USE SIGNAL ;
  PORT
   LAYER M5 ;
   RECT 183.6000 0.0000 183.6240 0.0840 ;
  END
 END tx[39]
 PIN tx[40]
  DIRECTION OUTPUT ;
  USE SIGNAL ;
  PORT
   LAYER M5 ;
   RECT 183.8400 0.0000 183.8640 0.0840 ;
  END
 END tx[40]
 PIN tx[41]
  DIRECTION OUTPUT ;
  USE SIGNAL ;
  PORT
   LAYER M5 ;
   RECT 184.0800 0.0000 184.1040 0.0840 ;
  END
 END tx[41]
 PIN tx[42]
  DIRECTION OUTPUT ;
  USE SIGNAL ;
  PORT
   LAYER M5 ;
   RECT 184.3200 0.0000 184.3440 0.0840 ;
  END
 END tx[42]
 PIN tx[43]
  DIRECTION OUTPUT ;
  USE SIGNAL ;
  PORT
   LAYER M5 ;
   RECT 184.5600 0.0000 184.5840 0.0840 ;
  END
 END tx[43]
 PIN tx[44]
  DIRECTION OUTPUT ;
  USE SIGNAL ;
  PORT
   LAYER M5 ;
   RECT 184.8000 0.0000 184.8240 0.0840 ;
  END
 END tx[44]
 PIN tx[45]
  DIRECTION OUTPUT ;
  USE SIGNAL ;
  PORT
   LAYER M5 ;
   RECT 185.0400 0.0000 185.0640 0.0840 ;
  END
 END tx[45]
 PIN tx[46]
  DIRECTION OUTPUT ;
  USE SIGNAL ;
  PORT
   LAYER M5 ;
   RECT 185.2800 0.0000 185.3040 0.0840 ;
  END
 END tx[46]
 PIN tx[47]
  DIRECTION OUTPUT ;
  USE SIGNAL ;
  PORT
   LAYER M5 ;
   RECT 185.5200 0.0000 185.5440 0.0840 ;
  END
 END tx[47]
 PIN tx[48]
  DIRECTION OUTPUT ;
  USE SIGNAL ;
  PORT
   LAYER M5 ;
   RECT 185.7600 0.0000 185.7840 0.0840 ;
  END
 END tx[48]
 PIN tx[49]
  DIRECTION OUTPUT ;
  USE SIGNAL ;
  PORT
   LAYER M5 ;
   RECT 186.0000 0.0000 186.0240 0.0840 ;
  END
 END tx[49]
 PIN tx[50]
  DIRECTION OUTPUT ;
  USE SIGNAL ;
  PORT
   LAYER M5 ;
   RECT 186.2400 0.0000 186.2640 0.0840 ;
  END
 END tx[50]
 PIN tx[51]
  DIRECTION OUTPUT ;
  USE SIGNAL ;
  PORT
   LAYER M5 ;
   RECT 186.4800 0.0000 186.5040 0.0840 ;
  END
 END tx[51]
 PIN tx[52]
  DIRECTION OUTPUT ;
  USE SIGNAL ;
  PORT
   LAYER M5 ;
   RECT 186.7200 0.0000 186.7440 0.0840 ;
  END
 END tx[52]
 PIN tx[53]
  DIRECTION OUTPUT ;
  USE SIGNAL ;
  PORT
   LAYER M5 ;
   RECT 186.9600 0.0000 186.9840 0.0840 ;
  END
 END tx[53]
 PIN tx[54]
  DIRECTION OUTPUT ;
  USE SIGNAL ;
  PORT
   LAYER M5 ;
   RECT 187.2000 0.0000 187.2240 0.0840 ;
  END
 END tx[54]
 PIN tx[55]
  DIRECTION OUTPUT ;
  USE SIGNAL ;
  PORT
   LAYER M5 ;
   RECT 187.4400 0.0000 187.4640 0.0840 ;
  END
 END tx[55]
 PIN tx[56]
  DIRECTION OUTPUT ;
  USE SIGNAL ;
  PORT
   LAYER M5 ;
   RECT 187.6800 0.0000 187.7040 0.0840 ;
  END
 END tx[56]
 PIN tx[57]
  DIRECTION OUTPUT ;
  USE SIGNAL ;
  PORT
   LAYER M5 ;
   RECT 187.9200 0.0000 187.9440 0.0840 ;
  END
 END tx[57]
 PIN tx[58]
  DIRECTION OUTPUT ;
  USE SIGNAL ;
  PORT
   LAYER M5 ;
   RECT 188.1600 0.0000 188.1840 0.0840 ;
  END
 END tx[58]
 PIN tx[59]
  DIRECTION OUTPUT ;
  USE SIGNAL ;
  PORT
   LAYER M5 ;
   RECT 188.4000 0.0000 188.4240 0.0840 ;
  END
 END tx[59]
 PIN tx[60]
  DIRECTION OUTPUT ;
  USE SIGNAL ;
  PORT
   LAYER M5 ;
   RECT 188.6400 0.0000 188.6640 0.0840 ;
  END
 END tx[60]
 PIN tx[61]
  DIRECTION OUTPUT ;
  USE SIGNAL ;
  PORT
   LAYER M5 ;
   RECT 188.8800 0.0000 188.9040 0.0840 ;
  END
 END tx[61]
 PIN tx[62]
  DIRECTION OUTPUT ;
  USE SIGNAL ;
  PORT
   LAYER M5 ;
   RECT 189.1200 0.0000 189.1440 0.0840 ;
  END
 END tx[62]
 PIN tx[63]
  DIRECTION OUTPUT ;
  USE SIGNAL ;
  PORT
   LAYER M5 ;
   RECT 189.3600 0.0000 189.3840 0.0840 ;
  END
 END tx[63]
 PIN tx[64]
  DIRECTION OUTPUT ;
  USE SIGNAL ;
  PORT
   LAYER M5 ;
   RECT 189.6000 0.0000 189.6240 0.0840 ;
  END
 END tx[64]
 PIN tx[65]
  DIRECTION OUTPUT ;
  USE SIGNAL ;
  PORT
   LAYER M5 ;
   RECT 189.8400 0.0000 189.8640 0.0840 ;
  END
 END tx[65]
 PIN tx[66]
  DIRECTION OUTPUT ;
  USE SIGNAL ;
  PORT
   LAYER M5 ;
   RECT 190.0800 0.0000 190.1040 0.0840 ;
  END
 END tx[66]
 PIN tx[67]
  DIRECTION OUTPUT ;
  USE SIGNAL ;
  PORT
   LAYER M5 ;
   RECT 190.3200 0.0000 190.3440 0.0840 ;
  END
 END tx[67]
 PIN tx[68]
  DIRECTION OUTPUT ;
  USE SIGNAL ;
  PORT
   LAYER M5 ;
   RECT 190.5600 0.0000 190.5840 0.0840 ;
  END
 END tx[68]
 PIN tx[69]
  DIRECTION OUTPUT ;
  USE SIGNAL ;
  PORT
   LAYER M5 ;
   RECT 190.8000 0.0000 190.8240 0.0840 ;
  END
 END tx[69]
 PIN tx[70]
  DIRECTION OUTPUT ;
  USE SIGNAL ;
  PORT
   LAYER M5 ;
   RECT 191.0400 0.0000 191.0640 0.0840 ;
  END
 END tx[70]
 PIN tx[71]
  DIRECTION OUTPUT ;
  USE SIGNAL ;
  PORT
   LAYER M5 ;
   RECT 191.2800 0.0000 191.3040 0.0840 ;
  END
 END tx[71]
 PIN tx[72]
  DIRECTION OUTPUT ;
  USE SIGNAL ;
  PORT
   LAYER M5 ;
   RECT 191.5200 0.0000 191.5440 0.0840 ;
  END
 END tx[72]
 PIN tx[73]
  DIRECTION OUTPUT ;
  USE SIGNAL ;
  PORT
   LAYER M5 ;
   RECT 191.7600 0.0000 191.7840 0.0840 ;
  END
 END tx[73]
 PIN tx[74]
  DIRECTION OUTPUT ;
  USE SIGNAL ;
  PORT
   LAYER M5 ;
   RECT 192.0000 0.0000 192.0240 0.0840 ;
  END
 END tx[74]
 PIN tx[75]
  DIRECTION OUTPUT ;
  USE SIGNAL ;
  PORT
   LAYER M5 ;
   RECT 192.2400 0.0000 192.2640 0.0840 ;
  END
 END tx[75]
 PIN tx[76]
  DIRECTION OUTPUT ;
  USE SIGNAL ;
  PORT
   LAYER M5 ;
   RECT 192.4800 0.0000 192.5040 0.0840 ;
  END
 END tx[76]
 PIN tx[77]
  DIRECTION OUTPUT ;
  USE SIGNAL ;
  PORT
   LAYER M5 ;
   RECT 192.7200 0.0000 192.7440 0.0840 ;
  END
 END tx[77]
 PIN tx[78]
  DIRECTION OUTPUT ;
  USE SIGNAL ;
  PORT
   LAYER M5 ;
   RECT 192.9600 0.0000 192.9840 0.0840 ;
  END
 END tx[78]
 PIN tx[79]
  DIRECTION OUTPUT ;
  USE SIGNAL ;
  PORT
   LAYER M5 ;
   RECT 193.2000 0.0000 193.2240 0.0840 ;
  END
 END tx[79]
 PIN tx[80]
  DIRECTION OUTPUT ;
  USE SIGNAL ;
  PORT
   LAYER M5 ;
   RECT 193.4400 0.0000 193.4640 0.0840 ;
  END
 END tx[80]
 PIN tx[81]
  DIRECTION OUTPUT ;
  USE SIGNAL ;
  PORT
   LAYER M5 ;
   RECT 193.6800 0.0000 193.7040 0.0840 ;
  END
 END tx[81]
 PIN tx[82]
  DIRECTION OUTPUT ;
  USE SIGNAL ;
  PORT
   LAYER M5 ;
   RECT 193.9200 0.0000 193.9440 0.0840 ;
  END
 END tx[82]
 PIN tx[83]
  DIRECTION OUTPUT ;
  USE SIGNAL ;
  PORT
   LAYER M5 ;
   RECT 194.1600 0.0000 194.1840 0.0840 ;
  END
 END tx[83]
 PIN tx[84]
  DIRECTION OUTPUT ;
  USE SIGNAL ;
  PORT
   LAYER M5 ;
   RECT 194.4000 0.0000 194.4240 0.0840 ;
  END
 END tx[84]
 PIN tx[85]
  DIRECTION OUTPUT ;
  USE SIGNAL ;
  PORT
   LAYER M5 ;
   RECT 194.6400 0.0000 194.6640 0.0840 ;
  END
 END tx[85]
 PIN tx[86]
  DIRECTION OUTPUT ;
  USE SIGNAL ;
  PORT
   LAYER M5 ;
   RECT 194.8800 0.0000 194.9040 0.0840 ;
  END
 END tx[86]
 PIN tx[87]
  DIRECTION OUTPUT ;
  USE SIGNAL ;
  PORT
   LAYER M5 ;
   RECT 195.1200 0.0000 195.1440 0.0840 ;
  END
 END tx[87]
 PIN tx[88]
  DIRECTION OUTPUT ;
  USE SIGNAL ;
  PORT
   LAYER M5 ;
   RECT 195.3600 0.0000 195.3840 0.0840 ;
  END
 END tx[88]
 PIN tx[89]
  DIRECTION OUTPUT ;
  USE SIGNAL ;
  PORT
   LAYER M5 ;
   RECT 195.6000 0.0000 195.6240 0.0840 ;
  END
 END tx[89]
 PIN tx[90]
  DIRECTION OUTPUT ;
  USE SIGNAL ;
  PORT
   LAYER M5 ;
   RECT 195.8400 0.0000 195.8640 0.0840 ;
  END
 END tx[90]
 PIN tx[91]
  DIRECTION OUTPUT ;
  USE SIGNAL ;
  PORT
   LAYER M5 ;
   RECT 196.0800 0.0000 196.1040 0.0840 ;
  END
 END tx[91]
 PIN tx[92]
  DIRECTION OUTPUT ;
  USE SIGNAL ;
  PORT
   LAYER M5 ;
   RECT 196.3200 0.0000 196.3440 0.0840 ;
  END
 END tx[92]
 PIN tx[93]
  DIRECTION OUTPUT ;
  USE SIGNAL ;
  PORT
   LAYER M5 ;
   RECT 196.5600 0.0000 196.5840 0.0840 ;
  END
 END tx[93]
 PIN tx[94]
  DIRECTION OUTPUT ;
  USE SIGNAL ;
  PORT
   LAYER M5 ;
   RECT 196.8000 0.0000 196.8240 0.0840 ;
  END
 END tx[94]
 PIN tx[95]
  DIRECTION OUTPUT ;
  USE SIGNAL ;
  PORT
   LAYER M5 ;
   RECT 197.0400 0.0000 197.0640 0.0840 ;
  END
 END tx[95]
 PIN tx[96]
  DIRECTION OUTPUT ;
  USE SIGNAL ;
  PORT
   LAYER M5 ;
   RECT 197.2800 0.0000 197.3040 0.0840 ;
  END
 END tx[96]
 PIN tx[97]
  DIRECTION OUTPUT ;
  USE SIGNAL ;
  PORT
   LAYER M5 ;
   RECT 197.5200 0.0000 197.5440 0.0840 ;
  END
 END tx[97]
 PIN tx[98]
  DIRECTION OUTPUT ;
  USE SIGNAL ;
  PORT
   LAYER M5 ;
   RECT 197.7600 0.0000 197.7840 0.0840 ;
  END
 END tx[98]
 PIN tx[99]
  DIRECTION OUTPUT ;
  USE SIGNAL ;
  PORT
   LAYER M5 ;
   RECT 198.0000 0.0000 198.0240 0.0840 ;
  END
 END tx[99]
 PIN tx[100]
  DIRECTION OUTPUT ;
  USE SIGNAL ;
  PORT
   LAYER M5 ;
   RECT 198.2400 0.0000 198.2640 0.0840 ;
  END
 END tx[100]
 PIN tx[101]
  DIRECTION OUTPUT ;
  USE SIGNAL ;
  PORT
   LAYER M5 ;
   RECT 198.4800 0.0000 198.5040 0.0840 ;
  END
 END tx[101]
 PIN tx[102]
  DIRECTION OUTPUT ;
  USE SIGNAL ;
  PORT
   LAYER M5 ;
   RECT 198.7200 0.0000 198.7440 0.0840 ;
  END
 END tx[102]
 PIN tx[103]
  DIRECTION OUTPUT ;
  USE SIGNAL ;
  PORT
   LAYER M5 ;
   RECT 198.9600 0.0000 198.9840 0.0840 ;
  END
 END tx[103]
 PIN tx[104]
  DIRECTION OUTPUT ;
  USE SIGNAL ;
  PORT
   LAYER M5 ;
   RECT 199.2000 0.0000 199.2240 0.0840 ;
  END
 END tx[104]
 PIN tx[105]
  DIRECTION OUTPUT ;
  USE SIGNAL ;
  PORT
   LAYER M5 ;
   RECT 199.4400 0.0000 199.4640 0.0840 ;
  END
 END tx[105]
 PIN tx[106]
  DIRECTION OUTPUT ;
  USE SIGNAL ;
  PORT
   LAYER M5 ;
   RECT 199.6800 0.0000 199.7040 0.0840 ;
  END
 END tx[106]
 PIN tx[107]
  DIRECTION OUTPUT ;
  USE SIGNAL ;
  PORT
   LAYER M5 ;
   RECT 199.9200 0.0000 199.9440 0.0840 ;
  END
 END tx[107]
 PIN tx[108]
  DIRECTION OUTPUT ;
  USE SIGNAL ;
  PORT
   LAYER M5 ;
   RECT 200.1600 0.0000 200.1840 0.0840 ;
  END
 END tx[108]
 PIN tx[109]
  DIRECTION OUTPUT ;
  USE SIGNAL ;
  PORT
   LAYER M5 ;
   RECT 200.4000 0.0000 200.4240 0.0840 ;
  END
 END tx[109]
 PIN tx[110]
  DIRECTION OUTPUT ;
  USE SIGNAL ;
  PORT
   LAYER M5 ;
   RECT 200.6400 0.0000 200.6640 0.0840 ;
  END
 END tx[110]
 PIN tx[111]
  DIRECTION OUTPUT ;
  USE SIGNAL ;
  PORT
   LAYER M5 ;
   RECT 200.8800 0.0000 200.9040 0.0840 ;
  END
 END tx[111]
 PIN tx[112]
  DIRECTION OUTPUT ;
  USE SIGNAL ;
  PORT
   LAYER M5 ;
   RECT 201.1200 0.0000 201.1440 0.0840 ;
  END
 END tx[112]
 PIN tx[113]
  DIRECTION OUTPUT ;
  USE SIGNAL ;
  PORT
   LAYER M5 ;
   RECT 201.3600 0.0000 201.3840 0.0840 ;
  END
 END tx[113]
 PIN tx[114]
  DIRECTION OUTPUT ;
  USE SIGNAL ;
  PORT
   LAYER M5 ;
   RECT 201.6000 0.0000 201.6240 0.0840 ;
  END
 END tx[114]
 PIN tx[115]
  DIRECTION OUTPUT ;
  USE SIGNAL ;
  PORT
   LAYER M5 ;
   RECT 201.8400 0.0000 201.8640 0.0840 ;
  END
 END tx[115]
 PIN tx[116]
  DIRECTION OUTPUT ;
  USE SIGNAL ;
  PORT
   LAYER M5 ;
   RECT 202.0800 0.0000 202.1040 0.0840 ;
  END
 END tx[116]
 PIN tx[117]
  DIRECTION OUTPUT ;
  USE SIGNAL ;
  PORT
   LAYER M5 ;
   RECT 202.3200 0.0000 202.3440 0.0840 ;
  END
 END tx[117]
 PIN tx[118]
  DIRECTION OUTPUT ;
  USE SIGNAL ;
  PORT
   LAYER M5 ;
   RECT 202.5600 0.0000 202.5840 0.0840 ;
  END
 END tx[118]
 PIN tx[119]
  DIRECTION OUTPUT ;
  USE SIGNAL ;
  PORT
   LAYER M5 ;
   RECT 202.8000 0.0000 202.8240 0.0840 ;
  END
 END tx[119]
 PIN tx[120]
  DIRECTION OUTPUT ;
  USE SIGNAL ;
  PORT
   LAYER M5 ;
   RECT 203.0400 0.0000 203.0640 0.0840 ;
  END
 END tx[120]
 PIN tx[121]
  DIRECTION OUTPUT ;
  USE SIGNAL ;
  PORT
   LAYER M5 ;
   RECT 203.2800 0.0000 203.3040 0.0840 ;
  END
 END tx[121]
 PIN tx[122]
  DIRECTION OUTPUT ;
  USE SIGNAL ;
  PORT
   LAYER M5 ;
   RECT 203.5200 0.0000 203.5440 0.0840 ;
  END
 END tx[122]
 PIN tx[123]
  DIRECTION OUTPUT ;
  USE SIGNAL ;
  PORT
   LAYER M5 ;
   RECT 203.7600 0.0000 203.7840 0.0840 ;
  END
 END tx[123]
 PIN tx[124]
  DIRECTION OUTPUT ;
  USE SIGNAL ;
  PORT
   LAYER M5 ;
   RECT 204.0000 0.0000 204.0240 0.0840 ;
  END
 END tx[124]
 PIN tx[125]
  DIRECTION OUTPUT ;
  USE SIGNAL ;
  PORT
   LAYER M5 ;
   RECT 204.2400 0.0000 204.2640 0.0840 ;
  END
 END tx[125]
 PIN tx[126]
  DIRECTION OUTPUT ;
  USE SIGNAL ;
  PORT
   LAYER M5 ;
   RECT 204.4800 0.0000 204.5040 0.0840 ;
  END
 END tx[126]
 PIN tx[127]
  DIRECTION OUTPUT ;
  USE SIGNAL ;
  PORT
   LAYER M5 ;
   RECT 204.7200 0.0000 204.7440 0.0840 ;
  END
 END tx[127]
 PIN tx[128]
  DIRECTION OUTPUT ;
  USE SIGNAL ;
  PORT
   LAYER M5 ;
   RECT 204.9600 0.0000 204.9840 0.0840 ;
  END
 END tx[128]
 PIN tx[129]
  DIRECTION OUTPUT ;
  USE SIGNAL ;
  PORT
   LAYER M5 ;
   RECT 205.2000 0.0000 205.2240 0.0840 ;
  END
 END tx[129]
 PIN tx[130]
  DIRECTION OUTPUT ;
  USE SIGNAL ;
  PORT
   LAYER M5 ;
   RECT 205.4400 0.0000 205.4640 0.0840 ;
  END
 END tx[130]
 PIN tx[131]
  DIRECTION OUTPUT ;
  USE SIGNAL ;
  PORT
   LAYER M5 ;
   RECT 205.6800 0.0000 205.7040 0.0840 ;
  END
 END tx[131]
 PIN tx[132]
  DIRECTION OUTPUT ;
  USE SIGNAL ;
  PORT
   LAYER M5 ;
   RECT 205.9200 0.0000 205.9440 0.0840 ;
  END
 END tx[132]
 PIN tx[133]
  DIRECTION OUTPUT ;
  USE SIGNAL ;
  PORT
   LAYER M5 ;
   RECT 206.1600 0.0000 206.1840 0.0840 ;
  END
 END tx[133]
 PIN tx[134]
  DIRECTION OUTPUT ;
  USE SIGNAL ;
  PORT
   LAYER M5 ;
   RECT 206.4000 0.0000 206.4240 0.0840 ;
  END
 END tx[134]
 PIN tx[135]
  DIRECTION OUTPUT ;
  USE SIGNAL ;
  PORT
   LAYER M5 ;
   RECT 206.6400 0.0000 206.6640 0.0840 ;
  END
 END tx[135]
 PIN tx[136]
  DIRECTION OUTPUT ;
  USE SIGNAL ;
  PORT
   LAYER M5 ;
   RECT 206.8800 0.0000 206.9040 0.0840 ;
  END
 END tx[136]
 PIN tx[137]
  DIRECTION OUTPUT ;
  USE SIGNAL ;
  PORT
   LAYER M5 ;
   RECT 207.1200 0.0000 207.1440 0.0840 ;
  END
 END tx[137]
 PIN tx[138]
  DIRECTION OUTPUT ;
  USE SIGNAL ;
  PORT
   LAYER M5 ;
   RECT 207.3600 0.0000 207.3840 0.0840 ;
  END
 END tx[138]
 PIN tx[139]
  DIRECTION OUTPUT ;
  USE SIGNAL ;
  PORT
   LAYER M5 ;
   RECT 207.6000 0.0000 207.6240 0.0840 ;
  END
 END tx[139]
 PIN tx[140]
  DIRECTION OUTPUT ;
  USE SIGNAL ;
  PORT
   LAYER M5 ;
   RECT 207.8400 0.0000 207.8640 0.0840 ;
  END
 END tx[140]
 PIN tx[141]
  DIRECTION OUTPUT ;
  USE SIGNAL ;
  PORT
   LAYER M5 ;
   RECT 208.0800 0.0000 208.1040 0.0840 ;
  END
 END tx[141]
 PIN tx[142]
  DIRECTION OUTPUT ;
  USE SIGNAL ;
  PORT
   LAYER M5 ;
   RECT 208.3200 0.0000 208.3440 0.0840 ;
  END
 END tx[142]
 PIN tx[143]
  DIRECTION OUTPUT ;
  USE SIGNAL ;
  PORT
   LAYER M5 ;
   RECT 208.5600 0.0000 208.5840 0.0840 ;
  END
 END tx[143]
 PIN tx[144]
  DIRECTION OUTPUT ;
  USE SIGNAL ;
  PORT
   LAYER M5 ;
   RECT 208.8000 0.0000 208.8240 0.0840 ;
  END
 END tx[144]
 PIN tx[145]
  DIRECTION OUTPUT ;
  USE SIGNAL ;
  PORT
   LAYER M5 ;
   RECT 209.0400 0.0000 209.0640 0.0840 ;
  END
 END tx[145]
 PIN tx[146]
  DIRECTION OUTPUT ;
  USE SIGNAL ;
  PORT
   LAYER M5 ;
   RECT 209.2800 0.0000 209.3040 0.0840 ;
  END
 END tx[146]
 PIN tx[147]
  DIRECTION OUTPUT ;
  USE SIGNAL ;
  PORT
   LAYER M5 ;
   RECT 209.5200 0.0000 209.5440 0.0840 ;
  END
 END tx[147]
 PIN tx[148]
  DIRECTION OUTPUT ;
  USE SIGNAL ;
  PORT
   LAYER M5 ;
   RECT 209.7600 0.0000 209.7840 0.0840 ;
  END
 END tx[148]
 PIN tx[149]
  DIRECTION OUTPUT ;
  USE SIGNAL ;
  PORT
   LAYER M5 ;
   RECT 210.0000 0.0000 210.0240 0.0840 ;
  END
 END tx[149]
 PIN tx[150]
  DIRECTION OUTPUT ;
  USE SIGNAL ;
  PORT
   LAYER M5 ;
   RECT 210.2400 0.0000 210.2640 0.0840 ;
  END
 END tx[150]
 PIN tx[151]
  DIRECTION OUTPUT ;
  USE SIGNAL ;
  PORT
   LAYER M5 ;
   RECT 210.4800 0.0000 210.5040 0.0840 ;
  END
 END tx[151]
 PIN tx[152]
  DIRECTION OUTPUT ;
  USE SIGNAL ;
  PORT
   LAYER M5 ;
   RECT 210.7200 0.0000 210.7440 0.0840 ;
  END
 END tx[152]
 PIN tx[153]
  DIRECTION OUTPUT ;
  USE SIGNAL ;
  PORT
   LAYER M5 ;
   RECT 210.9600 0.0000 210.9840 0.0840 ;
  END
 END tx[153]
 PIN tx[154]
  DIRECTION OUTPUT ;
  USE SIGNAL ;
  PORT
   LAYER M5 ;
   RECT 211.2000 0.0000 211.2240 0.0840 ;
  END
 END tx[154]
 PIN tx[155]
  DIRECTION OUTPUT ;
  USE SIGNAL ;
  PORT
   LAYER M5 ;
   RECT 211.4400 0.0000 211.4640 0.0840 ;
  END
 END tx[155]
 PIN tx[156]
  DIRECTION OUTPUT ;
  USE SIGNAL ;
  PORT
   LAYER M5 ;
   RECT 211.6800 0.0000 211.7040 0.0840 ;
  END
 END tx[156]
 PIN tx[157]
  DIRECTION OUTPUT ;
  USE SIGNAL ;
  PORT
   LAYER M5 ;
   RECT 211.9200 0.0000 211.9440 0.0840 ;
  END
 END tx[157]
 PIN tx[158]
  DIRECTION OUTPUT ;
  USE SIGNAL ;
  PORT
   LAYER M5 ;
   RECT 212.1600 0.0000 212.1840 0.0840 ;
  END
 END tx[158]
 PIN tx[159]
  DIRECTION OUTPUT ;
  USE SIGNAL ;
  PORT
   LAYER M5 ;
   RECT 212.4000 0.0000 212.4240 0.0840 ;
  END
 END tx[159]
 PIN tx[160]
  DIRECTION OUTPUT ;
  USE SIGNAL ;
  PORT
   LAYER M5 ;
   RECT 212.6400 0.0000 212.6640 0.0840 ;
  END
 END tx[160]
 PIN tx[161]
  DIRECTION OUTPUT ;
  USE SIGNAL ;
  PORT
   LAYER M5 ;
   RECT 212.8800 0.0000 212.9040 0.0840 ;
  END
 END tx[161]
 PIN tx[162]
  DIRECTION OUTPUT ;
  USE SIGNAL ;
  PORT
   LAYER M5 ;
   RECT 213.1200 0.0000 213.1440 0.0840 ;
  END
 END tx[162]
 PIN tx[163]
  DIRECTION OUTPUT ;
  USE SIGNAL ;
  PORT
   LAYER M5 ;
   RECT 213.3600 0.0000 213.3840 0.0840 ;
  END
 END tx[163]
 PIN tx[164]
  DIRECTION OUTPUT ;
  USE SIGNAL ;
  PORT
   LAYER M5 ;
   RECT 213.6000 0.0000 213.6240 0.0840 ;
  END
 END tx[164]
 PIN tx[165]
  DIRECTION OUTPUT ;
  USE SIGNAL ;
  PORT
   LAYER M5 ;
   RECT 213.8400 0.0000 213.8640 0.0840 ;
  END
 END tx[165]
 PIN tx[166]
  DIRECTION OUTPUT ;
  USE SIGNAL ;
  PORT
   LAYER M5 ;
   RECT 214.0800 0.0000 214.1040 0.0840 ;
  END
 END tx[166]
 PIN tx[167]
  DIRECTION OUTPUT ;
  USE SIGNAL ;
  PORT
   LAYER M5 ;
   RECT 214.3200 0.0000 214.3440 0.0840 ;
  END
 END tx[167]
 PIN tx[168]
  DIRECTION OUTPUT ;
  USE SIGNAL ;
  PORT
   LAYER M5 ;
   RECT 214.5600 0.0000 214.5840 0.0840 ;
  END
 END tx[168]
 PIN tx[169]
  DIRECTION OUTPUT ;
  USE SIGNAL ;
  PORT
   LAYER M5 ;
   RECT 214.8000 0.0000 214.8240 0.0840 ;
  END
 END tx[169]
 PIN tx[170]
  DIRECTION OUTPUT ;
  USE SIGNAL ;
  PORT
   LAYER M5 ;
   RECT 215.0400 0.0000 215.0640 0.0840 ;
  END
 END tx[170]
 PIN tx[171]
  DIRECTION OUTPUT ;
  USE SIGNAL ;
  PORT
   LAYER M5 ;
   RECT 215.2800 0.0000 215.3040 0.0840 ;
  END
 END tx[171]
 PIN tx[172]
  DIRECTION OUTPUT ;
  USE SIGNAL ;
  PORT
   LAYER M5 ;
   RECT 215.5200 0.0000 215.5440 0.0840 ;
  END
 END tx[172]
 PIN tx[173]
  DIRECTION OUTPUT ;
  USE SIGNAL ;
  PORT
   LAYER M5 ;
   RECT 215.7600 0.0000 215.7840 0.0840 ;
  END
 END tx[173]
 PIN tx[174]
  DIRECTION OUTPUT ;
  USE SIGNAL ;
  PORT
   LAYER M5 ;
   RECT 216.0000 0.0000 216.0240 0.0840 ;
  END
 END tx[174]
 PIN tx[175]
  DIRECTION OUTPUT ;
  USE SIGNAL ;
  PORT
   LAYER M5 ;
   RECT 216.2400 0.0000 216.2640 0.0840 ;
  END
 END tx[175]
 PIN tx[176]
  DIRECTION OUTPUT ;
  USE SIGNAL ;
  PORT
   LAYER M5 ;
   RECT 216.4800 0.0000 216.5040 0.0840 ;
  END
 END tx[176]
 PIN tx[177]
  DIRECTION OUTPUT ;
  USE SIGNAL ;
  PORT
   LAYER M5 ;
   RECT 216.7200 0.0000 216.7440 0.0840 ;
  END
 END tx[177]
 PIN tx[178]
  DIRECTION OUTPUT ;
  USE SIGNAL ;
  PORT
   LAYER M5 ;
   RECT 216.9600 0.0000 216.9840 0.0840 ;
  END
 END tx[178]
 PIN tx[179]
  DIRECTION OUTPUT ;
  USE SIGNAL ;
  PORT
   LAYER M5 ;
   RECT 217.2000 0.0000 217.2240 0.0840 ;
  END
 END tx[179]
 PIN tx[180]
  DIRECTION OUTPUT ;
  USE SIGNAL ;
  PORT
   LAYER M5 ;
   RECT 217.4400 0.0000 217.4640 0.0840 ;
  END
 END tx[180]
 PIN tx[181]
  DIRECTION OUTPUT ;
  USE SIGNAL ;
  PORT
   LAYER M5 ;
   RECT 217.6800 0.0000 217.7040 0.0840 ;
  END
 END tx[181]
 PIN tx[182]
  DIRECTION OUTPUT ;
  USE SIGNAL ;
  PORT
   LAYER M5 ;
   RECT 217.9200 0.0000 217.9440 0.0840 ;
  END
 END tx[182]
 PIN tx[183]
  DIRECTION OUTPUT ;
  USE SIGNAL ;
  PORT
   LAYER M5 ;
   RECT 218.1600 0.0000 218.1840 0.0840 ;
  END
 END tx[183]
 PIN tx[184]
  DIRECTION OUTPUT ;
  USE SIGNAL ;
  PORT
   LAYER M5 ;
   RECT 218.4000 0.0000 218.4240 0.0840 ;
  END
 END tx[184]
 PIN tx[185]
  DIRECTION OUTPUT ;
  USE SIGNAL ;
  PORT
   LAYER M5 ;
   RECT 218.6400 0.0000 218.6640 0.0840 ;
  END
 END tx[185]
 PIN tx[186]
  DIRECTION OUTPUT ;
  USE SIGNAL ;
  PORT
   LAYER M5 ;
   RECT 218.8800 0.0000 218.9040 0.0840 ;
  END
 END tx[186]
 PIN tx[187]
  DIRECTION OUTPUT ;
  USE SIGNAL ;
  PORT
   LAYER M5 ;
   RECT 219.1200 0.0000 219.1440 0.0840 ;
  END
 END tx[187]
 PIN tx[188]
  DIRECTION OUTPUT ;
  USE SIGNAL ;
  PORT
   LAYER M5 ;
   RECT 219.3600 0.0000 219.3840 0.0840 ;
  END
 END tx[188]
 PIN tx[189]
  DIRECTION OUTPUT ;
  USE SIGNAL ;
  PORT
   LAYER M5 ;
   RECT 219.6000 0.0000 219.6240 0.0840 ;
  END
 END tx[189]
 PIN tx[190]
  DIRECTION OUTPUT ;
  USE SIGNAL ;
  PORT
   LAYER M5 ;
   RECT 219.8400 0.0000 219.8640 0.0840 ;
  END
 END tx[190]
 PIN tx[191]
  DIRECTION OUTPUT ;
  USE SIGNAL ;
  PORT
   LAYER M5 ;
   RECT 220.0800 0.0000 220.1040 0.0840 ;
  END
 END tx[191]
 PIN tx[192]
  DIRECTION OUTPUT ;
  USE SIGNAL ;
  PORT
   LAYER M5 ;
   RECT 220.3200 0.0000 220.3440 0.0840 ;
  END
 END tx[192]
 PIN tx[193]
  DIRECTION OUTPUT ;
  USE SIGNAL ;
  PORT
   LAYER M5 ;
   RECT 220.5600 0.0000 220.5840 0.0840 ;
  END
 END tx[193]
 PIN tx[194]
  DIRECTION OUTPUT ;
  USE SIGNAL ;
  PORT
   LAYER M5 ;
   RECT 220.8000 0.0000 220.8240 0.0840 ;
  END
 END tx[194]
 PIN tx[195]
  DIRECTION OUTPUT ;
  USE SIGNAL ;
  PORT
   LAYER M5 ;
   RECT 221.0400 0.0000 221.0640 0.0840 ;
  END
 END tx[195]
 PIN tx[196]
  DIRECTION OUTPUT ;
  USE SIGNAL ;
  PORT
   LAYER M5 ;
   RECT 221.2800 0.0000 221.3040 0.0840 ;
  END
 END tx[196]
 PIN tx[197]
  DIRECTION OUTPUT ;
  USE SIGNAL ;
  PORT
   LAYER M5 ;
   RECT 221.5200 0.0000 221.5440 0.0840 ;
  END
 END tx[197]
 PIN tx[198]
  DIRECTION OUTPUT ;
  USE SIGNAL ;
  PORT
   LAYER M5 ;
   RECT 221.7600 0.0000 221.7840 0.0840 ;
  END
 END tx[198]
 PIN tx[199]
  DIRECTION OUTPUT ;
  USE SIGNAL ;
  PORT
   LAYER M5 ;
   RECT 222.0000 0.0000 222.0240 0.0840 ;
  END
 END tx[199]
 PIN tx[200]
  DIRECTION OUTPUT ;
  USE SIGNAL ;
  PORT
   LAYER M5 ;
   RECT 222.2400 0.0000 222.2640 0.0840 ;
  END
 END tx[200]
 PIN tx[201]
  DIRECTION OUTPUT ;
  USE SIGNAL ;
  PORT
   LAYER M5 ;
   RECT 222.4800 0.0000 222.5040 0.0840 ;
  END
 END tx[201]
 PIN tx[202]
  DIRECTION OUTPUT ;
  USE SIGNAL ;
  PORT
   LAYER M5 ;
   RECT 222.7200 0.0000 222.7440 0.0840 ;
  END
 END tx[202]
 PIN tx[203]
  DIRECTION OUTPUT ;
  USE SIGNAL ;
  PORT
   LAYER M5 ;
   RECT 222.9600 0.0000 222.9840 0.0840 ;
  END
 END tx[203]
 PIN tx[204]
  DIRECTION OUTPUT ;
  USE SIGNAL ;
  PORT
   LAYER M5 ;
   RECT 223.2000 0.0000 223.2240 0.0840 ;
  END
 END tx[204]
 PIN tx[205]
  DIRECTION OUTPUT ;
  USE SIGNAL ;
  PORT
   LAYER M5 ;
   RECT 223.4400 0.0000 223.4640 0.0840 ;
  END
 END tx[205]
 PIN tx[206]
  DIRECTION OUTPUT ;
  USE SIGNAL ;
  PORT
   LAYER M5 ;
   RECT 223.6800 0.0000 223.7040 0.0840 ;
  END
 END tx[206]
 PIN tx[207]
  DIRECTION OUTPUT ;
  USE SIGNAL ;
  PORT
   LAYER M5 ;
   RECT 223.9200 0.0000 223.9440 0.0840 ;
  END
 END tx[207]
 PIN tx[208]
  DIRECTION OUTPUT ;
  USE SIGNAL ;
  PORT
   LAYER M5 ;
   RECT 224.1600 0.0000 224.1840 0.0840 ;
  END
 END tx[208]
 PIN tx[209]
  DIRECTION OUTPUT ;
  USE SIGNAL ;
  PORT
   LAYER M5 ;
   RECT 224.4000 0.0000 224.4240 0.0840 ;
  END
 END tx[209]
 PIN tx[210]
  DIRECTION OUTPUT ;
  USE SIGNAL ;
  PORT
   LAYER M5 ;
   RECT 224.6400 0.0000 224.6640 0.0840 ;
  END
 END tx[210]
 PIN tx[211]
  DIRECTION OUTPUT ;
  USE SIGNAL ;
  PORT
   LAYER M5 ;
   RECT 224.8800 0.0000 224.9040 0.0840 ;
  END
 END tx[211]
 PIN tx[212]
  DIRECTION OUTPUT ;
  USE SIGNAL ;
  PORT
   LAYER M5 ;
   RECT 225.1200 0.0000 225.1440 0.0840 ;
  END
 END tx[212]
 PIN tx[213]
  DIRECTION OUTPUT ;
  USE SIGNAL ;
  PORT
   LAYER M5 ;
   RECT 225.3600 0.0000 225.3840 0.0840 ;
  END
 END tx[213]
 PIN tx[214]
  DIRECTION OUTPUT ;
  USE SIGNAL ;
  PORT
   LAYER M5 ;
   RECT 225.6000 0.0000 225.6240 0.0840 ;
  END
 END tx[214]
 PIN tx[215]
  DIRECTION OUTPUT ;
  USE SIGNAL ;
  PORT
   LAYER M5 ;
   RECT 225.8400 0.0000 225.8640 0.0840 ;
  END
 END tx[215]
 PIN tx[216]
  DIRECTION OUTPUT ;
  USE SIGNAL ;
  PORT
   LAYER M5 ;
   RECT 226.0800 0.0000 226.1040 0.0840 ;
  END
 END tx[216]
 PIN tx[217]
  DIRECTION OUTPUT ;
  USE SIGNAL ;
  PORT
   LAYER M5 ;
   RECT 226.3200 0.0000 226.3440 0.0840 ;
  END
 END tx[217]
 PIN tx[218]
  DIRECTION OUTPUT ;
  USE SIGNAL ;
  PORT
   LAYER M5 ;
   RECT 226.5600 0.0000 226.5840 0.0840 ;
  END
 END tx[218]
 PIN tx[219]
  DIRECTION OUTPUT ;
  USE SIGNAL ;
  PORT
   LAYER M5 ;
   RECT 226.8000 0.0000 226.8240 0.0840 ;
  END
 END tx[219]
 PIN tx[220]
  DIRECTION OUTPUT ;
  USE SIGNAL ;
  PORT
   LAYER M5 ;
   RECT 227.0400 0.0000 227.0640 0.0840 ;
  END
 END tx[220]
 PIN tx[221]
  DIRECTION OUTPUT ;
  USE SIGNAL ;
  PORT
   LAYER M5 ;
   RECT 227.2800 0.0000 227.3040 0.0840 ;
  END
 END tx[221]
 PIN tx[222]
  DIRECTION OUTPUT ;
  USE SIGNAL ;
  PORT
   LAYER M5 ;
   RECT 227.5200 0.0000 227.5440 0.0840 ;
  END
 END tx[222]
 PIN tx[223]
  DIRECTION OUTPUT ;
  USE SIGNAL ;
  PORT
   LAYER M5 ;
   RECT 227.7600 0.0000 227.7840 0.0840 ;
  END
 END tx[223]
 PIN tx[224]
  DIRECTION OUTPUT ;
  USE SIGNAL ;
  PORT
   LAYER M5 ;
   RECT 228.0000 0.0000 228.0240 0.0840 ;
  END
 END tx[224]
 PIN tx[225]
  DIRECTION OUTPUT ;
  USE SIGNAL ;
  PORT
   LAYER M5 ;
   RECT 228.2400 0.0000 228.2640 0.0840 ;
  END
 END tx[225]
 PIN tx[226]
  DIRECTION OUTPUT ;
  USE SIGNAL ;
  PORT
   LAYER M5 ;
   RECT 228.4800 0.0000 228.5040 0.0840 ;
  END
 END tx[226]
 PIN tx[227]
  DIRECTION OUTPUT ;
  USE SIGNAL ;
  PORT
   LAYER M5 ;
   RECT 228.7200 0.0000 228.7440 0.0840 ;
  END
 END tx[227]
 PIN tx[228]
  DIRECTION OUTPUT ;
  USE SIGNAL ;
  PORT
   LAYER M5 ;
   RECT 228.9600 0.0000 228.9840 0.0840 ;
  END
 END tx[228]
 PIN tx[229]
  DIRECTION OUTPUT ;
  USE SIGNAL ;
  PORT
   LAYER M5 ;
   RECT 229.2000 0.0000 229.2240 0.0840 ;
  END
 END tx[229]
 PIN tx[230]
  DIRECTION OUTPUT ;
  USE SIGNAL ;
  PORT
   LAYER M5 ;
   RECT 229.4400 0.0000 229.4640 0.0840 ;
  END
 END tx[230]
 PIN tx[231]
  DIRECTION OUTPUT ;
  USE SIGNAL ;
  PORT
   LAYER M5 ;
   RECT 229.6800 0.0000 229.7040 0.0840 ;
  END
 END tx[231]
 PIN tx[232]
  DIRECTION OUTPUT ;
  USE SIGNAL ;
  PORT
   LAYER M5 ;
   RECT 229.9200 0.0000 229.9440 0.0840 ;
  END
 END tx[232]
 PIN tx[233]
  DIRECTION OUTPUT ;
  USE SIGNAL ;
  PORT
   LAYER M5 ;
   RECT 230.1600 0.0000 230.1840 0.0840 ;
  END
 END tx[233]
 PIN tx[234]
  DIRECTION OUTPUT ;
  USE SIGNAL ;
  PORT
   LAYER M5 ;
   RECT 230.4000 0.0000 230.4240 0.0840 ;
  END
 END tx[234]
 PIN tx[235]
  DIRECTION OUTPUT ;
  USE SIGNAL ;
  PORT
   LAYER M5 ;
   RECT 230.6400 0.0000 230.6640 0.0840 ;
  END
 END tx[235]
 PIN tx[236]
  DIRECTION OUTPUT ;
  USE SIGNAL ;
  PORT
   LAYER M5 ;
   RECT 230.8800 0.0000 230.9040 0.0840 ;
  END
 END tx[236]
 PIN tx[237]
  DIRECTION OUTPUT ;
  USE SIGNAL ;
  PORT
   LAYER M5 ;
   RECT 231.1200 0.0000 231.1440 0.0840 ;
  END
 END tx[237]
 PIN tx[238]
  DIRECTION OUTPUT ;
  USE SIGNAL ;
  PORT
   LAYER M5 ;
   RECT 231.3600 0.0000 231.3840 0.0840 ;
  END
 END tx[238]
 PIN tx[239]
  DIRECTION OUTPUT ;
  USE SIGNAL ;
  PORT
   LAYER M5 ;
   RECT 231.6000 0.0000 231.6240 0.0840 ;
  END
 END tx[239]
 PIN tx[240]
  DIRECTION OUTPUT ;
  USE SIGNAL ;
  PORT
   LAYER M5 ;
   RECT 231.8400 0.0000 231.8640 0.0840 ;
  END
 END tx[240]
 PIN tx[241]
  DIRECTION OUTPUT ;
  USE SIGNAL ;
  PORT
   LAYER M5 ;
   RECT 232.0800 0.0000 232.1040 0.0840 ;
  END
 END tx[241]
 PIN tx[242]
  DIRECTION OUTPUT ;
  USE SIGNAL ;
  PORT
   LAYER M5 ;
   RECT 232.3200 0.0000 232.3440 0.0840 ;
  END
 END tx[242]
 PIN tx[243]
  DIRECTION OUTPUT ;
  USE SIGNAL ;
  PORT
   LAYER M5 ;
   RECT 232.5600 0.0000 232.5840 0.0840 ;
  END
 END tx[243]
 PIN tx[244]
  DIRECTION OUTPUT ;
  USE SIGNAL ;
  PORT
   LAYER M5 ;
   RECT 232.8000 0.0000 232.8240 0.0840 ;
  END
 END tx[244]
 PIN tx[245]
  DIRECTION OUTPUT ;
  USE SIGNAL ;
  PORT
   LAYER M5 ;
   RECT 233.0400 0.0000 233.0640 0.0840 ;
  END
 END tx[245]
 PIN tx[246]
  DIRECTION OUTPUT ;
  USE SIGNAL ;
  PORT
   LAYER M5 ;
   RECT 233.2800 0.0000 233.3040 0.0840 ;
  END
 END tx[246]
 PIN tx[247]
  DIRECTION OUTPUT ;
  USE SIGNAL ;
  PORT
   LAYER M5 ;
   RECT 233.5200 0.0000 233.5440 0.0840 ;
  END
 END tx[247]
 PIN tx[248]
  DIRECTION OUTPUT ;
  USE SIGNAL ;
  PORT
   LAYER M5 ;
   RECT 233.7600 0.0000 233.7840 0.0840 ;
  END
 END tx[248]
 PIN tx[249]
  DIRECTION OUTPUT ;
  USE SIGNAL ;
  PORT
   LAYER M5 ;
   RECT 234.0000 0.0000 234.0240 0.0840 ;
  END
 END tx[249]
 PIN tx[250]
  DIRECTION OUTPUT ;
  USE SIGNAL ;
  PORT
   LAYER M5 ;
   RECT 234.2400 0.0000 234.2640 0.0840 ;
  END
 END tx[250]
 PIN tx[251]
  DIRECTION OUTPUT ;
  USE SIGNAL ;
  PORT
   LAYER M5 ;
   RECT 234.4800 0.0000 234.5040 0.0840 ;
  END
 END tx[251]
 PIN tx[252]
  DIRECTION OUTPUT ;
  USE SIGNAL ;
  PORT
   LAYER M5 ;
   RECT 234.7200 0.0000 234.7440 0.0840 ;
  END
 END tx[252]
 PIN tx[253]
  DIRECTION OUTPUT ;
  USE SIGNAL ;
  PORT
   LAYER M5 ;
   RECT 234.9600 0.0000 234.9840 0.0840 ;
  END
 END tx[253]
 PIN tx[254]
  DIRECTION OUTPUT ;
  USE SIGNAL ;
  PORT
   LAYER M5 ;
   RECT 235.2000 0.0000 235.2240 0.0840 ;
  END
 END tx[254]
 PIN tx[255]
  DIRECTION OUTPUT ;
  USE SIGNAL ;
  PORT
   LAYER M5 ;
   RECT 235.4400 0.0000 235.4640 0.0840 ;
  END
 END tx[255]
 PIN tx[256]
  DIRECTION OUTPUT ;
  USE SIGNAL ;
  PORT
   LAYER M5 ;
   RECT 235.6800 0.0000 235.7040 0.0840 ;
  END
 END tx[256]
 PIN tx[257]
  DIRECTION OUTPUT ;
  USE SIGNAL ;
  PORT
   LAYER M5 ;
   RECT 235.9200 0.0000 235.9440 0.0840 ;
  END
 END tx[257]
 PIN tx[258]
  DIRECTION OUTPUT ;
  USE SIGNAL ;
  PORT
   LAYER M5 ;
   RECT 236.1600 0.0000 236.1840 0.0840 ;
  END
 END tx[258]
 PIN tx[259]
  DIRECTION OUTPUT ;
  USE SIGNAL ;
  PORT
   LAYER M5 ;
   RECT 236.4000 0.0000 236.4240 0.0840 ;
  END
 END tx[259]
 PIN tx[260]
  DIRECTION OUTPUT ;
  USE SIGNAL ;
  PORT
   LAYER M5 ;
   RECT 236.6400 0.0000 236.6640 0.0840 ;
  END
 END tx[260]
 PIN tx[261]
  DIRECTION OUTPUT ;
  USE SIGNAL ;
  PORT
   LAYER M5 ;
   RECT 236.8800 0.0000 236.9040 0.0840 ;
  END
 END tx[261]
 PIN tx[262]
  DIRECTION OUTPUT ;
  USE SIGNAL ;
  PORT
   LAYER M5 ;
   RECT 237.1200 0.0000 237.1440 0.0840 ;
  END
 END tx[262]
 PIN tx[263]
  DIRECTION OUTPUT ;
  USE SIGNAL ;
  PORT
   LAYER M5 ;
   RECT 237.3600 0.0000 237.3840 0.0840 ;
  END
 END tx[263]
 PIN tx[264]
  DIRECTION OUTPUT ;
  USE SIGNAL ;
  PORT
   LAYER M5 ;
   RECT 237.6000 0.0000 237.6240 0.0840 ;
  END
 END tx[264]
 PIN tx[265]
  DIRECTION OUTPUT ;
  USE SIGNAL ;
  PORT
   LAYER M5 ;
   RECT 237.8400 0.0000 237.8640 0.0840 ;
  END
 END tx[265]
 PIN tx[266]
  DIRECTION OUTPUT ;
  USE SIGNAL ;
  PORT
   LAYER M5 ;
   RECT 238.0800 0.0000 238.1040 0.0840 ;
  END
 END tx[266]
 PIN tx[267]
  DIRECTION OUTPUT ;
  USE SIGNAL ;
  PORT
   LAYER M5 ;
   RECT 238.3200 0.0000 238.3440 0.0840 ;
  END
 END tx[267]
 PIN tx[268]
  DIRECTION OUTPUT ;
  USE SIGNAL ;
  PORT
   LAYER M5 ;
   RECT 238.5600 0.0000 238.5840 0.0840 ;
  END
 END tx[268]
 PIN tx[269]
  DIRECTION OUTPUT ;
  USE SIGNAL ;
  PORT
   LAYER M5 ;
   RECT 238.8000 0.0000 238.8240 0.0840 ;
  END
 END tx[269]
 PIN tx[270]
  DIRECTION OUTPUT ;
  USE SIGNAL ;
  PORT
   LAYER M5 ;
   RECT 239.0400 0.0000 239.0640 0.0840 ;
  END
 END tx[270]
 PIN tx[271]
  DIRECTION OUTPUT ;
  USE SIGNAL ;
  PORT
   LAYER M5 ;
   RECT 239.2800 0.0000 239.3040 0.0840 ;
  END
 END tx[271]
 PIN tx[272]
  DIRECTION OUTPUT ;
  USE SIGNAL ;
  PORT
   LAYER M5 ;
   RECT 239.5200 0.0000 239.5440 0.0840 ;
  END
 END tx[272]
 PIN tx[273]
  DIRECTION OUTPUT ;
  USE SIGNAL ;
  PORT
   LAYER M5 ;
   RECT 239.7600 0.0000 239.7840 0.0840 ;
  END
 END tx[273]
 PIN tx[274]
  DIRECTION OUTPUT ;
  USE SIGNAL ;
  PORT
   LAYER M5 ;
   RECT 240.0000 0.0000 240.0240 0.0840 ;
  END
 END tx[274]
 PIN tx[275]
  DIRECTION OUTPUT ;
  USE SIGNAL ;
  PORT
   LAYER M5 ;
   RECT 240.2400 0.0000 240.2640 0.0840 ;
  END
 END tx[275]
 PIN tx[276]
  DIRECTION OUTPUT ;
  USE SIGNAL ;
  PORT
   LAYER M5 ;
   RECT 240.4800 0.0000 240.5040 0.0840 ;
  END
 END tx[276]
 PIN tx[277]
  DIRECTION OUTPUT ;
  USE SIGNAL ;
  PORT
   LAYER M5 ;
   RECT 240.7200 0.0000 240.7440 0.0840 ;
  END
 END tx[277]
 PIN tx[278]
  DIRECTION OUTPUT ;
  USE SIGNAL ;
  PORT
   LAYER M5 ;
   RECT 240.9600 0.0000 240.9840 0.0840 ;
  END
 END tx[278]
 PIN tx[279]
  DIRECTION OUTPUT ;
  USE SIGNAL ;
  PORT
   LAYER M5 ;
   RECT 241.2000 0.0000 241.2240 0.0840 ;
  END
 END tx[279]
 PIN tx[280]
  DIRECTION OUTPUT ;
  USE SIGNAL ;
  PORT
   LAYER M5 ;
   RECT 241.4400 0.0000 241.4640 0.0840 ;
  END
 END tx[280]
 PIN tx[281]
  DIRECTION OUTPUT ;
  USE SIGNAL ;
  PORT
   LAYER M5 ;
   RECT 241.6800 0.0000 241.7040 0.0840 ;
  END
 END tx[281]
 PIN tx[282]
  DIRECTION OUTPUT ;
  USE SIGNAL ;
  PORT
   LAYER M5 ;
   RECT 241.9200 0.0000 241.9440 0.0840 ;
  END
 END tx[282]
 PIN tx[283]
  DIRECTION OUTPUT ;
  USE SIGNAL ;
  PORT
   LAYER M5 ;
   RECT 242.1600 0.0000 242.1840 0.0840 ;
  END
 END tx[283]
 PIN tx[284]
  DIRECTION OUTPUT ;
  USE SIGNAL ;
  PORT
   LAYER M5 ;
   RECT 242.4000 0.0000 242.4240 0.0840 ;
  END
 END tx[284]
 PIN tx[285]
  DIRECTION OUTPUT ;
  USE SIGNAL ;
  PORT
   LAYER M5 ;
   RECT 242.6400 0.0000 242.6640 0.0840 ;
  END
 END tx[285]
 PIN tx[286]
  DIRECTION OUTPUT ;
  USE SIGNAL ;
  PORT
   LAYER M5 ;
   RECT 242.8800 0.0000 242.9040 0.0840 ;
  END
 END tx[286]
 PIN tx[287]
  DIRECTION OUTPUT ;
  USE SIGNAL ;
  PORT
   LAYER M5 ;
   RECT 243.1200 0.0000 243.1440 0.0840 ;
  END
 END tx[287]
 PIN tx[288]
  DIRECTION OUTPUT ;
  USE SIGNAL ;
  PORT
   LAYER M5 ;
   RECT 243.3600 0.0000 243.3840 0.0840 ;
  END
 END tx[288]
 PIN tx[289]
  DIRECTION OUTPUT ;
  USE SIGNAL ;
  PORT
   LAYER M5 ;
   RECT 243.6000 0.0000 243.6240 0.0840 ;
  END
 END tx[289]
 PIN tx[290]
  DIRECTION OUTPUT ;
  USE SIGNAL ;
  PORT
   LAYER M5 ;
   RECT 243.8400 0.0000 243.8640 0.0840 ;
  END
 END tx[290]
 PIN tx[291]
  DIRECTION OUTPUT ;
  USE SIGNAL ;
  PORT
   LAYER M5 ;
   RECT 244.0800 0.0000 244.1040 0.0840 ;
  END
 END tx[291]
 PIN tx[292]
  DIRECTION OUTPUT ;
  USE SIGNAL ;
  PORT
   LAYER M5 ;
   RECT 244.3200 0.0000 244.3440 0.0840 ;
  END
 END tx[292]
 PIN tx[293]
  DIRECTION OUTPUT ;
  USE SIGNAL ;
  PORT
   LAYER M5 ;
   RECT 244.5600 0.0000 244.5840 0.0840 ;
  END
 END tx[293]
 PIN tx[294]
  DIRECTION OUTPUT ;
  USE SIGNAL ;
  PORT
   LAYER M5 ;
   RECT 244.8000 0.0000 244.8240 0.0840 ;
  END
 END tx[294]
 PIN tx[295]
  DIRECTION OUTPUT ;
  USE SIGNAL ;
  PORT
   LAYER M5 ;
   RECT 245.0400 0.0000 245.0640 0.0840 ;
  END
 END tx[295]
 PIN tx[296]
  DIRECTION OUTPUT ;
  USE SIGNAL ;
  PORT
   LAYER M5 ;
   RECT 245.2800 0.0000 245.3040 0.0840 ;
  END
 END tx[296]
 PIN tx[297]
  DIRECTION OUTPUT ;
  USE SIGNAL ;
  PORT
   LAYER M5 ;
   RECT 245.5200 0.0000 245.5440 0.0840 ;
  END
 END tx[297]
 PIN tx[298]
  DIRECTION OUTPUT ;
  USE SIGNAL ;
  PORT
   LAYER M5 ;
   RECT 245.7600 0.0000 245.7840 0.0840 ;
  END
 END tx[298]
 PIN tx[299]
  DIRECTION OUTPUT ;
  USE SIGNAL ;
  PORT
   LAYER M5 ;
   RECT 246.0000 0.0000 246.0240 0.0840 ;
  END
 END tx[299]
 PIN tx[300]
  DIRECTION OUTPUT ;
  USE SIGNAL ;
  PORT
   LAYER M5 ;
   RECT 246.2400 0.0000 246.2640 0.0840 ;
  END
 END tx[300]
 PIN tx[301]
  DIRECTION OUTPUT ;
  USE SIGNAL ;
  PORT
   LAYER M5 ;
   RECT 246.4800 0.0000 246.5040 0.0840 ;
  END
 END tx[301]
 PIN tx[302]
  DIRECTION OUTPUT ;
  USE SIGNAL ;
  PORT
   LAYER M5 ;
   RECT 246.7200 0.0000 246.7440 0.0840 ;
  END
 END tx[302]
 PIN tx[303]
  DIRECTION OUTPUT ;
  USE SIGNAL ;
  PORT
   LAYER M5 ;
   RECT 246.9600 0.0000 246.9840 0.0840 ;
  END
 END tx[303]
 PIN tx[304]
  DIRECTION OUTPUT ;
  USE SIGNAL ;
  PORT
   LAYER M5 ;
   RECT 247.2000 0.0000 247.2240 0.0840 ;
  END
 END tx[304]
 PIN tx[305]
  DIRECTION OUTPUT ;
  USE SIGNAL ;
  PORT
   LAYER M5 ;
   RECT 247.4400 0.0000 247.4640 0.0840 ;
  END
 END tx[305]
 PIN tx[306]
  DIRECTION OUTPUT ;
  USE SIGNAL ;
  PORT
   LAYER M5 ;
   RECT 247.6800 0.0000 247.7040 0.0840 ;
  END
 END tx[306]
 PIN tx[307]
  DIRECTION OUTPUT ;
  USE SIGNAL ;
  PORT
   LAYER M5 ;
   RECT 247.9200 0.0000 247.9440 0.0840 ;
  END
 END tx[307]
 PIN tx[308]
  DIRECTION OUTPUT ;
  USE SIGNAL ;
  PORT
   LAYER M5 ;
   RECT 248.1600 0.0000 248.1840 0.0840 ;
  END
 END tx[308]
 PIN tx[309]
  DIRECTION OUTPUT ;
  USE SIGNAL ;
  PORT
   LAYER M5 ;
   RECT 248.4000 0.0000 248.4240 0.0840 ;
  END
 END tx[309]
 PIN tx[310]
  DIRECTION OUTPUT ;
  USE SIGNAL ;
  PORT
   LAYER M5 ;
   RECT 248.6400 0.0000 248.6640 0.0840 ;
  END
 END tx[310]
 PIN tx[311]
  DIRECTION OUTPUT ;
  USE SIGNAL ;
  PORT
   LAYER M5 ;
   RECT 248.8800 0.0000 248.9040 0.0840 ;
  END
 END tx[311]
 PIN tx[312]
  DIRECTION OUTPUT ;
  USE SIGNAL ;
  PORT
   LAYER M5 ;
   RECT 249.1200 0.0000 249.1440 0.0840 ;
  END
 END tx[312]
 PIN tx[313]
  DIRECTION OUTPUT ;
  USE SIGNAL ;
  PORT
   LAYER M5 ;
   RECT 249.3600 0.0000 249.3840 0.0840 ;
  END
 END tx[313]
 PIN tx[314]
  DIRECTION OUTPUT ;
  USE SIGNAL ;
  PORT
   LAYER M5 ;
   RECT 249.6000 0.0000 249.6240 0.0840 ;
  END
 END tx[314]
 PIN tx[315]
  DIRECTION OUTPUT ;
  USE SIGNAL ;
  PORT
   LAYER M5 ;
   RECT 249.8400 0.0000 249.8640 0.0840 ;
  END
 END tx[315]
 PIN tx[316]
  DIRECTION OUTPUT ;
  USE SIGNAL ;
  PORT
   LAYER M5 ;
   RECT 250.0800 0.0000 250.1040 0.0840 ;
  END
 END tx[316]
 PIN tx[317]
  DIRECTION OUTPUT ;
  USE SIGNAL ;
  PORT
   LAYER M5 ;
   RECT 250.3200 0.0000 250.3440 0.0840 ;
  END
 END tx[317]
 PIN tx[318]
  DIRECTION OUTPUT ;
  USE SIGNAL ;
  PORT
   LAYER M5 ;
   RECT 250.5600 0.0000 250.5840 0.0840 ;
  END
 END tx[318]
 PIN tx[319]
  DIRECTION OUTPUT ;
  USE SIGNAL ;
  PORT
   LAYER M5 ;
   RECT 250.8000 0.0000 250.8240 0.0840 ;
  END
 END tx[319]
 PIN tx[320]
  DIRECTION OUTPUT ;
  USE SIGNAL ;
  PORT
   LAYER M5 ;
   RECT 251.0400 0.0000 251.0640 0.0840 ;
  END
 END tx[320]
 PIN tx[321]
  DIRECTION OUTPUT ;
  USE SIGNAL ;
  PORT
   LAYER M5 ;
   RECT 251.2800 0.0000 251.3040 0.0840 ;
  END
 END tx[321]
 PIN tx[322]
  DIRECTION OUTPUT ;
  USE SIGNAL ;
  PORT
   LAYER M5 ;
   RECT 251.5200 0.0000 251.5440 0.0840 ;
  END
 END tx[322]
 PIN tx[323]
  DIRECTION OUTPUT ;
  USE SIGNAL ;
  PORT
   LAYER M5 ;
   RECT 251.7600 0.0000 251.7840 0.0840 ;
  END
 END tx[323]
 PIN tx[324]
  DIRECTION OUTPUT ;
  USE SIGNAL ;
  PORT
   LAYER M5 ;
   RECT 252.0000 0.0000 252.0240 0.0840 ;
  END
 END tx[324]
 PIN tx[325]
  DIRECTION OUTPUT ;
  USE SIGNAL ;
  PORT
   LAYER M5 ;
   RECT 252.2400 0.0000 252.2640 0.0840 ;
  END
 END tx[325]
 PIN tx[326]
  DIRECTION OUTPUT ;
  USE SIGNAL ;
  PORT
   LAYER M5 ;
   RECT 252.4800 0.0000 252.5040 0.0840 ;
  END
 END tx[326]
 PIN tx[327]
  DIRECTION OUTPUT ;
  USE SIGNAL ;
  PORT
   LAYER M5 ;
   RECT 252.7200 0.0000 252.7440 0.0840 ;
  END
 END tx[327]
 PIN tx[328]
  DIRECTION OUTPUT ;
  USE SIGNAL ;
  PORT
   LAYER M5 ;
   RECT 252.9600 0.0000 252.9840 0.0840 ;
  END
 END tx[328]
 PIN tx[329]
  DIRECTION OUTPUT ;
  USE SIGNAL ;
  PORT
   LAYER M5 ;
   RECT 253.2000 0.0000 253.2240 0.0840 ;
  END
 END tx[329]
 PIN tx[330]
  DIRECTION OUTPUT ;
  USE SIGNAL ;
  PORT
   LAYER M5 ;
   RECT 253.4400 0.0000 253.4640 0.0840 ;
  END
 END tx[330]
 PIN tx[331]
  DIRECTION OUTPUT ;
  USE SIGNAL ;
  PORT
   LAYER M5 ;
   RECT 253.6800 0.0000 253.7040 0.0840 ;
  END
 END tx[331]
 PIN tx[332]
  DIRECTION OUTPUT ;
  USE SIGNAL ;
  PORT
   LAYER M5 ;
   RECT 253.9200 0.0000 253.9440 0.0840 ;
  END
 END tx[332]
 PIN tx[333]
  DIRECTION OUTPUT ;
  USE SIGNAL ;
  PORT
   LAYER M5 ;
   RECT 254.1600 0.0000 254.1840 0.0840 ;
  END
 END tx[333]
 PIN tx[334]
  DIRECTION OUTPUT ;
  USE SIGNAL ;
  PORT
   LAYER M5 ;
   RECT 254.4000 0.0000 254.4240 0.0840 ;
  END
 END tx[334]
 PIN tx[335]
  DIRECTION OUTPUT ;
  USE SIGNAL ;
  PORT
   LAYER M5 ;
   RECT 254.6400 0.0000 254.6640 0.0840 ;
  END
 END tx[335]
 PIN tx[336]
  DIRECTION OUTPUT ;
  USE SIGNAL ;
  PORT
   LAYER M5 ;
   RECT 254.8800 0.0000 254.9040 0.0840 ;
  END
 END tx[336]
 PIN tx[337]
  DIRECTION OUTPUT ;
  USE SIGNAL ;
  PORT
   LAYER M5 ;
   RECT 255.1200 0.0000 255.1440 0.0840 ;
  END
 END tx[337]
 PIN tx[338]
  DIRECTION OUTPUT ;
  USE SIGNAL ;
  PORT
   LAYER M5 ;
   RECT 255.3600 0.0000 255.3840 0.0840 ;
  END
 END tx[338]
 PIN tx[339]
  DIRECTION OUTPUT ;
  USE SIGNAL ;
  PORT
   LAYER M5 ;
   RECT 255.6000 0.0000 255.6240 0.0840 ;
  END
 END tx[339]
 PIN tx[340]
  DIRECTION OUTPUT ;
  USE SIGNAL ;
  PORT
   LAYER M5 ;
   RECT 255.8400 0.0000 255.8640 0.0840 ;
  END
 END tx[340]
 PIN tx[341]
  DIRECTION OUTPUT ;
  USE SIGNAL ;
  PORT
   LAYER M5 ;
   RECT 256.0800 0.0000 256.1040 0.0840 ;
  END
 END tx[341]
 PIN tx[342]
  DIRECTION OUTPUT ;
  USE SIGNAL ;
  PORT
   LAYER M5 ;
   RECT 256.3200 0.0000 256.3440 0.0840 ;
  END
 END tx[342]
 PIN tx[343]
  DIRECTION OUTPUT ;
  USE SIGNAL ;
  PORT
   LAYER M5 ;
   RECT 256.5600 0.0000 256.5840 0.0840 ;
  END
 END tx[343]
 PIN tx[344]
  DIRECTION OUTPUT ;
  USE SIGNAL ;
  PORT
   LAYER M5 ;
   RECT 256.8000 0.0000 256.8240 0.0840 ;
  END
 END tx[344]
 PIN tx[345]
  DIRECTION OUTPUT ;
  USE SIGNAL ;
  PORT
   LAYER M5 ;
   RECT 257.0400 0.0000 257.0640 0.0840 ;
  END
 END tx[345]
 PIN tx[346]
  DIRECTION OUTPUT ;
  USE SIGNAL ;
  PORT
   LAYER M5 ;
   RECT 257.2800 0.0000 257.3040 0.0840 ;
  END
 END tx[346]
 PIN tx[347]
  DIRECTION OUTPUT ;
  USE SIGNAL ;
  PORT
   LAYER M5 ;
   RECT 257.5200 0.0000 257.5440 0.0840 ;
  END
 END tx[347]
 PIN tx[348]
  DIRECTION OUTPUT ;
  USE SIGNAL ;
  PORT
   LAYER M5 ;
   RECT 257.7600 0.0000 257.7840 0.0840 ;
  END
 END tx[348]
 PIN tx[349]
  DIRECTION OUTPUT ;
  USE SIGNAL ;
  PORT
   LAYER M5 ;
   RECT 258.0000 0.0000 258.0240 0.0840 ;
  END
 END tx[349]
 PIN tx[350]
  DIRECTION OUTPUT ;
  USE SIGNAL ;
  PORT
   LAYER M5 ;
   RECT 258.2400 0.0000 258.2640 0.0840 ;
  END
 END tx[350]
 PIN tx[351]
  DIRECTION OUTPUT ;
  USE SIGNAL ;
  PORT
   LAYER M5 ;
   RECT 258.4800 0.0000 258.5040 0.0840 ;
  END
 END tx[351]
 PIN tx[352]
  DIRECTION OUTPUT ;
  USE SIGNAL ;
  PORT
   LAYER M5 ;
   RECT 258.7200 0.0000 258.7440 0.0840 ;
  END
 END tx[352]
 PIN tx[353]
  DIRECTION OUTPUT ;
  USE SIGNAL ;
  PORT
   LAYER M5 ;
   RECT 258.9600 0.0000 258.9840 0.0840 ;
  END
 END tx[353]
 PIN tx[354]
  DIRECTION OUTPUT ;
  USE SIGNAL ;
  PORT
   LAYER M5 ;
   RECT 259.2000 0.0000 259.2240 0.0840 ;
  END
 END tx[354]
 PIN tx[355]
  DIRECTION OUTPUT ;
  USE SIGNAL ;
  PORT
   LAYER M5 ;
   RECT 259.4400 0.0000 259.4640 0.0840 ;
  END
 END tx[355]
 PIN tx[356]
  DIRECTION OUTPUT ;
  USE SIGNAL ;
  PORT
   LAYER M5 ;
   RECT 259.6800 0.0000 259.7040 0.0840 ;
  END
 END tx[356]
 PIN tx[357]
  DIRECTION OUTPUT ;
  USE SIGNAL ;
  PORT
   LAYER M5 ;
   RECT 259.9200 0.0000 259.9440 0.0840 ;
  END
 END tx[357]
 PIN tx[358]
  DIRECTION OUTPUT ;
  USE SIGNAL ;
  PORT
   LAYER M5 ;
   RECT 260.1600 0.0000 260.1840 0.0840 ;
  END
 END tx[358]
 PIN tx[359]
  DIRECTION OUTPUT ;
  USE SIGNAL ;
  PORT
   LAYER M5 ;
   RECT 260.4000 0.0000 260.4240 0.0840 ;
  END
 END tx[359]
 PIN tx[360]
  DIRECTION OUTPUT ;
  USE SIGNAL ;
  PORT
   LAYER M5 ;
   RECT 260.6400 0.0000 260.6640 0.0840 ;
  END
 END tx[360]
 PIN tx[361]
  DIRECTION OUTPUT ;
  USE SIGNAL ;
  PORT
   LAYER M5 ;
   RECT 260.8800 0.0000 260.9040 0.0840 ;
  END
 END tx[361]
 PIN tx[362]
  DIRECTION OUTPUT ;
  USE SIGNAL ;
  PORT
   LAYER M5 ;
   RECT 261.1200 0.0000 261.1440 0.0840 ;
  END
 END tx[362]
 PIN tx[363]
  DIRECTION OUTPUT ;
  USE SIGNAL ;
  PORT
   LAYER M5 ;
   RECT 261.3600 0.0000 261.3840 0.0840 ;
  END
 END tx[363]
 PIN tx[364]
  DIRECTION OUTPUT ;
  USE SIGNAL ;
  PORT
   LAYER M5 ;
   RECT 261.6000 0.0000 261.6240 0.0840 ;
  END
 END tx[364]
 PIN tx[365]
  DIRECTION OUTPUT ;
  USE SIGNAL ;
  PORT
   LAYER M5 ;
   RECT 261.8400 0.0000 261.8640 0.0840 ;
  END
 END tx[365]
 PIN tx[366]
  DIRECTION OUTPUT ;
  USE SIGNAL ;
  PORT
   LAYER M5 ;
   RECT 262.0800 0.0000 262.1040 0.0840 ;
  END
 END tx[366]
 PIN tx[367]
  DIRECTION OUTPUT ;
  USE SIGNAL ;
  PORT
   LAYER M5 ;
   RECT 262.3200 0.0000 262.3440 0.0840 ;
  END
 END tx[367]
 PIN tx[368]
  DIRECTION OUTPUT ;
  USE SIGNAL ;
  PORT
   LAYER M5 ;
   RECT 262.5600 0.0000 262.5840 0.0840 ;
  END
 END tx[368]
 PIN tx[369]
  DIRECTION OUTPUT ;
  USE SIGNAL ;
  PORT
   LAYER M5 ;
   RECT 262.8000 0.0000 262.8240 0.0840 ;
  END
 END tx[369]
 PIN tx[370]
  DIRECTION OUTPUT ;
  USE SIGNAL ;
  PORT
   LAYER M5 ;
   RECT 263.0400 0.0000 263.0640 0.0840 ;
  END
 END tx[370]
 PIN tx[371]
  DIRECTION OUTPUT ;
  USE SIGNAL ;
  PORT
   LAYER M5 ;
   RECT 263.2800 0.0000 263.3040 0.0840 ;
  END
 END tx[371]
 PIN tx[372]
  DIRECTION OUTPUT ;
  USE SIGNAL ;
  PORT
   LAYER M5 ;
   RECT 263.5200 0.0000 263.5440 0.0840 ;
  END
 END tx[372]
 PIN tx[373]
  DIRECTION OUTPUT ;
  USE SIGNAL ;
  PORT
   LAYER M5 ;
   RECT 263.7600 0.0000 263.7840 0.0840 ;
  END
 END tx[373]
 PIN tx[374]
  DIRECTION OUTPUT ;
  USE SIGNAL ;
  PORT
   LAYER M5 ;
   RECT 264.0000 0.0000 264.0240 0.0840 ;
  END
 END tx[374]
 PIN tx[375]
  DIRECTION OUTPUT ;
  USE SIGNAL ;
  PORT
   LAYER M5 ;
   RECT 264.2400 0.0000 264.2640 0.0840 ;
  END
 END tx[375]
 PIN tx[376]
  DIRECTION OUTPUT ;
  USE SIGNAL ;
  PORT
   LAYER M5 ;
   RECT 264.4800 0.0000 264.5040 0.0840 ;
  END
 END tx[376]
 PIN tx[377]
  DIRECTION OUTPUT ;
  USE SIGNAL ;
  PORT
   LAYER M5 ;
   RECT 264.7200 0.0000 264.7440 0.0840 ;
  END
 END tx[377]
 PIN tx[378]
  DIRECTION OUTPUT ;
  USE SIGNAL ;
  PORT
   LAYER M5 ;
   RECT 264.9600 0.0000 264.9840 0.0840 ;
  END
 END tx[378]
 PIN tx[379]
  DIRECTION OUTPUT ;
  USE SIGNAL ;
  PORT
   LAYER M5 ;
   RECT 265.2000 0.0000 265.2240 0.0840 ;
  END
 END tx[379]
 PIN tx[380]
  DIRECTION OUTPUT ;
  USE SIGNAL ;
  PORT
   LAYER M5 ;
   RECT 265.4400 0.0000 265.4640 0.0840 ;
  END
 END tx[380]
 PIN tx[381]
  DIRECTION OUTPUT ;
  USE SIGNAL ;
  PORT
   LAYER M5 ;
   RECT 265.6800 0.0000 265.7040 0.0840 ;
  END
 END tx[381]
 PIN tx[382]
  DIRECTION OUTPUT ;
  USE SIGNAL ;
  PORT
   LAYER M5 ;
   RECT 265.9200 0.0000 265.9440 0.0840 ;
  END
 END tx[382]
 PIN tx[383]
  DIRECTION OUTPUT ;
  USE SIGNAL ;
  PORT
   LAYER M5 ;
   RECT 266.1600 0.0000 266.1840 0.0840 ;
  END
 END tx[383]
 PIN tx[384]
  DIRECTION OUTPUT ;
  USE SIGNAL ;
  PORT
   LAYER M5 ;
   RECT 266.4000 0.0000 266.4240 0.0840 ;
  END
 END tx[384]
 PIN tx[385]
  DIRECTION OUTPUT ;
  USE SIGNAL ;
  PORT
   LAYER M5 ;
   RECT 266.6400 0.0000 266.6640 0.0840 ;
  END
 END tx[385]
 PIN tx[386]
  DIRECTION OUTPUT ;
  USE SIGNAL ;
  PORT
   LAYER M5 ;
   RECT 266.8800 0.0000 266.9040 0.0840 ;
  END
 END tx[386]
 PIN tx[387]
  DIRECTION OUTPUT ;
  USE SIGNAL ;
  PORT
   LAYER M5 ;
   RECT 267.1200 0.0000 267.1440 0.0840 ;
  END
 END tx[387]
 PIN tx[388]
  DIRECTION OUTPUT ;
  USE SIGNAL ;
  PORT
   LAYER M5 ;
   RECT 267.3600 0.0000 267.3840 0.0840 ;
  END
 END tx[388]
 PIN tx[389]
  DIRECTION OUTPUT ;
  USE SIGNAL ;
  PORT
   LAYER M5 ;
   RECT 267.6000 0.0000 267.6240 0.0840 ;
  END
 END tx[389]
 PIN tx[390]
  DIRECTION OUTPUT ;
  USE SIGNAL ;
  PORT
   LAYER M5 ;
   RECT 267.8400 0.0000 267.8640 0.0840 ;
  END
 END tx[390]
 PIN tx[391]
  DIRECTION OUTPUT ;
  USE SIGNAL ;
  PORT
   LAYER M5 ;
   RECT 268.0800 0.0000 268.1040 0.0840 ;
  END
 END tx[391]
 PIN tx[392]
  DIRECTION OUTPUT ;
  USE SIGNAL ;
  PORT
   LAYER M5 ;
   RECT 268.3200 0.0000 268.3440 0.0840 ;
  END
 END tx[392]
 PIN tx[393]
  DIRECTION OUTPUT ;
  USE SIGNAL ;
  PORT
   LAYER M5 ;
   RECT 268.5600 0.0000 268.5840 0.0840 ;
  END
 END tx[393]
 PIN tx[394]
  DIRECTION OUTPUT ;
  USE SIGNAL ;
  PORT
   LAYER M5 ;
   RECT 268.8000 0.0000 268.8240 0.0840 ;
  END
 END tx[394]
 PIN tx[395]
  DIRECTION OUTPUT ;
  USE SIGNAL ;
  PORT
   LAYER M5 ;
   RECT 269.0400 0.0000 269.0640 0.0840 ;
  END
 END tx[395]
 PIN tx[396]
  DIRECTION OUTPUT ;
  USE SIGNAL ;
  PORT
   LAYER M5 ;
   RECT 269.2800 0.0000 269.3040 0.0840 ;
  END
 END tx[396]
 PIN tx[397]
  DIRECTION OUTPUT ;
  USE SIGNAL ;
  PORT
   LAYER M5 ;
   RECT 269.5200 0.0000 269.5440 0.0840 ;
  END
 END tx[397]
 PIN tx[398]
  DIRECTION OUTPUT ;
  USE SIGNAL ;
  PORT
   LAYER M5 ;
   RECT 269.7600 0.0000 269.7840 0.0840 ;
  END
 END tx[398]
 PIN tx[399]
  DIRECTION OUTPUT ;
  USE SIGNAL ;
  PORT
   LAYER M5 ;
   RECT 270.0000 0.0000 270.0240 0.0840 ;
  END
 END tx[399]
 PIN tx[400]
  DIRECTION OUTPUT ;
  USE SIGNAL ;
  PORT
   LAYER M5 ;
   RECT 270.2400 0.0000 270.2640 0.0840 ;
  END
 END tx[400]
 PIN tx[401]
  DIRECTION OUTPUT ;
  USE SIGNAL ;
  PORT
   LAYER M5 ;
   RECT 270.4800 0.0000 270.5040 0.0840 ;
  END
 END tx[401]
 PIN tx[402]
  DIRECTION OUTPUT ;
  USE SIGNAL ;
  PORT
   LAYER M5 ;
   RECT 270.7200 0.0000 270.7440 0.0840 ;
  END
 END tx[402]
 PIN tx[403]
  DIRECTION OUTPUT ;
  USE SIGNAL ;
  PORT
   LAYER M5 ;
   RECT 270.9600 0.0000 270.9840 0.0840 ;
  END
 END tx[403]
 PIN tx[404]
  DIRECTION OUTPUT ;
  USE SIGNAL ;
  PORT
   LAYER M5 ;
   RECT 271.2000 0.0000 271.2240 0.0840 ;
  END
 END tx[404]
 PIN tx[405]
  DIRECTION OUTPUT ;
  USE SIGNAL ;
  PORT
   LAYER M5 ;
   RECT 271.4400 0.0000 271.4640 0.0840 ;
  END
 END tx[405]
 PIN tx[406]
  DIRECTION OUTPUT ;
  USE SIGNAL ;
  PORT
   LAYER M5 ;
   RECT 271.6800 0.0000 271.7040 0.0840 ;
  END
 END tx[406]
 PIN tx[407]
  DIRECTION OUTPUT ;
  USE SIGNAL ;
  PORT
   LAYER M5 ;
   RECT 271.9200 0.0000 271.9440 0.0840 ;
  END
 END tx[407]
 PIN tx[408]
  DIRECTION OUTPUT ;
  USE SIGNAL ;
  PORT
   LAYER M5 ;
   RECT 272.1600 0.0000 272.1840 0.0840 ;
  END
 END tx[408]
 PIN tx[409]
  DIRECTION OUTPUT ;
  USE SIGNAL ;
  PORT
   LAYER M5 ;
   RECT 272.4000 0.0000 272.4240 0.0840 ;
  END
 END tx[409]
 PIN tx[410]
  DIRECTION OUTPUT ;
  USE SIGNAL ;
  PORT
   LAYER M5 ;
   RECT 272.6400 0.0000 272.6640 0.0840 ;
  END
 END tx[410]
 PIN tx[411]
  DIRECTION OUTPUT ;
  USE SIGNAL ;
  PORT
   LAYER M5 ;
   RECT 272.8800 0.0000 272.9040 0.0840 ;
  END
 END tx[411]
 PIN tx[412]
  DIRECTION OUTPUT ;
  USE SIGNAL ;
  PORT
   LAYER M5 ;
   RECT 273.1200 0.0000 273.1440 0.0840 ;
  END
 END tx[412]
 PIN tx[413]
  DIRECTION OUTPUT ;
  USE SIGNAL ;
  PORT
   LAYER M5 ;
   RECT 273.3600 0.0000 273.3840 0.0840 ;
  END
 END tx[413]
 PIN tx[414]
  DIRECTION OUTPUT ;
  USE SIGNAL ;
  PORT
   LAYER M5 ;
   RECT 273.6000 0.0000 273.6240 0.0840 ;
  END
 END tx[414]
 PIN tx[415]
  DIRECTION OUTPUT ;
  USE SIGNAL ;
  PORT
   LAYER M5 ;
   RECT 273.8400 0.0000 273.8640 0.0840 ;
  END
 END tx[415]
 PIN tx[416]
  DIRECTION OUTPUT ;
  USE SIGNAL ;
  PORT
   LAYER M5 ;
   RECT 274.0800 0.0000 274.1040 0.0840 ;
  END
 END tx[416]
 PIN tx[417]
  DIRECTION OUTPUT ;
  USE SIGNAL ;
  PORT
   LAYER M5 ;
   RECT 274.3200 0.0000 274.3440 0.0840 ;
  END
 END tx[417]
 PIN tx[418]
  DIRECTION OUTPUT ;
  USE SIGNAL ;
  PORT
   LAYER M5 ;
   RECT 274.5600 0.0000 274.5840 0.0840 ;
  END
 END tx[418]
 PIN tx[419]
  DIRECTION OUTPUT ;
  USE SIGNAL ;
  PORT
   LAYER M5 ;
   RECT 274.8000 0.0000 274.8240 0.0840 ;
  END
 END tx[419]
 PIN tx[420]
  DIRECTION OUTPUT ;
  USE SIGNAL ;
  PORT
   LAYER M5 ;
   RECT 275.0400 0.0000 275.0640 0.0840 ;
  END
 END tx[420]
 PIN tx[421]
  DIRECTION OUTPUT ;
  USE SIGNAL ;
  PORT
   LAYER M5 ;
   RECT 275.2800 0.0000 275.3040 0.0840 ;
  END
 END tx[421]
 PIN tx[422]
  DIRECTION OUTPUT ;
  USE SIGNAL ;
  PORT
   LAYER M5 ;
   RECT 275.5200 0.0000 275.5440 0.0840 ;
  END
 END tx[422]
 PIN tx[423]
  DIRECTION OUTPUT ;
  USE SIGNAL ;
  PORT
   LAYER M5 ;
   RECT 275.7600 0.0000 275.7840 0.0840 ;
  END
 END tx[423]
 PIN tx[424]
  DIRECTION OUTPUT ;
  USE SIGNAL ;
  PORT
   LAYER M5 ;
   RECT 276.0000 0.0000 276.0240 0.0840 ;
  END
 END tx[424]
 PIN tx[425]
  DIRECTION OUTPUT ;
  USE SIGNAL ;
  PORT
   LAYER M5 ;
   RECT 276.2400 0.0000 276.2640 0.0840 ;
  END
 END tx[425]
 PIN tx[426]
  DIRECTION OUTPUT ;
  USE SIGNAL ;
  PORT
   LAYER M5 ;
   RECT 276.4800 0.0000 276.5040 0.0840 ;
  END
 END tx[426]
 PIN tx[427]
  DIRECTION OUTPUT ;
  USE SIGNAL ;
  PORT
   LAYER M5 ;
   RECT 276.7200 0.0000 276.7440 0.0840 ;
  END
 END tx[427]
 PIN tx[428]
  DIRECTION OUTPUT ;
  USE SIGNAL ;
  PORT
   LAYER M5 ;
   RECT 276.9600 0.0000 276.9840 0.0840 ;
  END
 END tx[428]
 PIN tx[429]
  DIRECTION OUTPUT ;
  USE SIGNAL ;
  PORT
   LAYER M5 ;
   RECT 277.2000 0.0000 277.2240 0.0840 ;
  END
 END tx[429]
 PIN tx[430]
  DIRECTION OUTPUT ;
  USE SIGNAL ;
  PORT
   LAYER M5 ;
   RECT 277.4400 0.0000 277.4640 0.0840 ;
  END
 END tx[430]
 PIN tx[431]
  DIRECTION OUTPUT ;
  USE SIGNAL ;
  PORT
   LAYER M5 ;
   RECT 277.6800 0.0000 277.7040 0.0840 ;
  END
 END tx[431]
 PIN tx[432]
  DIRECTION OUTPUT ;
  USE SIGNAL ;
  PORT
   LAYER M5 ;
   RECT 277.9200 0.0000 277.9440 0.0840 ;
  END
 END tx[432]
 PIN tx[433]
  DIRECTION OUTPUT ;
  USE SIGNAL ;
  PORT
   LAYER M5 ;
   RECT 278.1600 0.0000 278.1840 0.0840 ;
  END
 END tx[433]
 PIN tx[434]
  DIRECTION OUTPUT ;
  USE SIGNAL ;
  PORT
   LAYER M5 ;
   RECT 278.4000 0.0000 278.4240 0.0840 ;
  END
 END tx[434]
 PIN tx[435]
  DIRECTION OUTPUT ;
  USE SIGNAL ;
  PORT
   LAYER M5 ;
   RECT 278.6400 0.0000 278.6640 0.0840 ;
  END
 END tx[435]
 PIN tx[436]
  DIRECTION OUTPUT ;
  USE SIGNAL ;
  PORT
   LAYER M5 ;
   RECT 278.8800 0.0000 278.9040 0.0840 ;
  END
 END tx[436]
 PIN tx[437]
  DIRECTION OUTPUT ;
  USE SIGNAL ;
  PORT
   LAYER M5 ;
   RECT 279.1200 0.0000 279.1440 0.0840 ;
  END
 END tx[437]
 PIN tx[438]
  DIRECTION OUTPUT ;
  USE SIGNAL ;
  PORT
   LAYER M5 ;
   RECT 279.3600 0.0000 279.3840 0.0840 ;
  END
 END tx[438]
 PIN tx[439]
  DIRECTION OUTPUT ;
  USE SIGNAL ;
  PORT
   LAYER M5 ;
   RECT 279.6000 0.0000 279.6240 0.0840 ;
  END
 END tx[439]
 PIN tx[440]
  DIRECTION OUTPUT ;
  USE SIGNAL ;
  PORT
   LAYER M5 ;
   RECT 279.8400 0.0000 279.8640 0.0840 ;
  END
 END tx[440]
 PIN tx[441]
  DIRECTION OUTPUT ;
  USE SIGNAL ;
  PORT
   LAYER M5 ;
   RECT 280.0800 0.0000 280.1040 0.0840 ;
  END
 END tx[441]
 PIN tx[442]
  DIRECTION OUTPUT ;
  USE SIGNAL ;
  PORT
   LAYER M5 ;
   RECT 280.3200 0.0000 280.3440 0.0840 ;
  END
 END tx[442]
 PIN tx[443]
  DIRECTION OUTPUT ;
  USE SIGNAL ;
  PORT
   LAYER M5 ;
   RECT 280.5600 0.0000 280.5840 0.0840 ;
  END
 END tx[443]
 PIN tx[444]
  DIRECTION OUTPUT ;
  USE SIGNAL ;
  PORT
   LAYER M5 ;
   RECT 280.8000 0.0000 280.8240 0.0840 ;
  END
 END tx[444]
 PIN tx[445]
  DIRECTION OUTPUT ;
  USE SIGNAL ;
  PORT
   LAYER M5 ;
   RECT 281.0400 0.0000 281.0640 0.0840 ;
  END
 END tx[445]
 PIN tx[446]
  DIRECTION OUTPUT ;
  USE SIGNAL ;
  PORT
   LAYER M5 ;
   RECT 281.2800 0.0000 281.3040 0.0840 ;
  END
 END tx[446]
 PIN tx[447]
  DIRECTION OUTPUT ;
  USE SIGNAL ;
  PORT
   LAYER M5 ;
   RECT 281.5200 0.0000 281.5440 0.0840 ;
  END
 END tx[447]
 PIN tx[448]
  DIRECTION OUTPUT ;
  USE SIGNAL ;
  PORT
   LAYER M5 ;
   RECT 281.7600 0.0000 281.7840 0.0840 ;
  END
 END tx[448]
 PIN tx[449]
  DIRECTION OUTPUT ;
  USE SIGNAL ;
  PORT
   LAYER M5 ;
   RECT 282.0000 0.0000 282.0240 0.0840 ;
  END
 END tx[449]
 PIN tx[450]
  DIRECTION OUTPUT ;
  USE SIGNAL ;
  PORT
   LAYER M5 ;
   RECT 282.2400 0.0000 282.2640 0.0840 ;
  END
 END tx[450]
 PIN tx[451]
  DIRECTION OUTPUT ;
  USE SIGNAL ;
  PORT
   LAYER M5 ;
   RECT 282.4800 0.0000 282.5040 0.0840 ;
  END
 END tx[451]
 PIN tx[452]
  DIRECTION OUTPUT ;
  USE SIGNAL ;
  PORT
   LAYER M5 ;
   RECT 282.7200 0.0000 282.7440 0.0840 ;
  END
 END tx[452]
 PIN tx[453]
  DIRECTION OUTPUT ;
  USE SIGNAL ;
  PORT
   LAYER M5 ;
   RECT 282.9600 0.0000 282.9840 0.0840 ;
  END
 END tx[453]
 PIN tx[454]
  DIRECTION OUTPUT ;
  USE SIGNAL ;
  PORT
   LAYER M5 ;
   RECT 283.2000 0.0000 283.2240 0.0840 ;
  END
 END tx[454]
 PIN tx[455]
  DIRECTION OUTPUT ;
  USE SIGNAL ;
  PORT
   LAYER M5 ;
   RECT 283.4400 0.0000 283.4640 0.0840 ;
  END
 END tx[455]
 PIN tx[456]
  DIRECTION OUTPUT ;
  USE SIGNAL ;
  PORT
   LAYER M5 ;
   RECT 283.6800 0.0000 283.7040 0.0840 ;
  END
 END tx[456]
 PIN tx[457]
  DIRECTION OUTPUT ;
  USE SIGNAL ;
  PORT
   LAYER M5 ;
   RECT 283.9200 0.0000 283.9440 0.0840 ;
  END
 END tx[457]
 PIN tx[458]
  DIRECTION OUTPUT ;
  USE SIGNAL ;
  PORT
   LAYER M5 ;
   RECT 284.1600 0.0000 284.1840 0.0840 ;
  END
 END tx[458]
 PIN tx[459]
  DIRECTION OUTPUT ;
  USE SIGNAL ;
  PORT
   LAYER M5 ;
   RECT 284.4000 0.0000 284.4240 0.0840 ;
  END
 END tx[459]
 PIN tx[460]
  DIRECTION OUTPUT ;
  USE SIGNAL ;
  PORT
   LAYER M5 ;
   RECT 284.6400 0.0000 284.6640 0.0840 ;
  END
 END tx[460]
 PIN tx[461]
  DIRECTION OUTPUT ;
  USE SIGNAL ;
  PORT
   LAYER M5 ;
   RECT 284.8800 0.0000 284.9040 0.0840 ;
  END
 END tx[461]
 PIN tx[462]
  DIRECTION OUTPUT ;
  USE SIGNAL ;
  PORT
   LAYER M5 ;
   RECT 285.1200 0.0000 285.1440 0.0840 ;
  END
 END tx[462]
 PIN tx[463]
  DIRECTION OUTPUT ;
  USE SIGNAL ;
  PORT
   LAYER M5 ;
   RECT 285.3600 0.0000 285.3840 0.0840 ;
  END
 END tx[463]
 PIN tx[464]
  DIRECTION OUTPUT ;
  USE SIGNAL ;
  PORT
   LAYER M5 ;
   RECT 285.6000 0.0000 285.6240 0.0840 ;
  END
 END tx[464]
 PIN tx[465]
  DIRECTION OUTPUT ;
  USE SIGNAL ;
  PORT
   LAYER M5 ;
   RECT 285.8400 0.0000 285.8640 0.0840 ;
  END
 END tx[465]
 PIN tx[466]
  DIRECTION OUTPUT ;
  USE SIGNAL ;
  PORT
   LAYER M5 ;
   RECT 286.0800 0.0000 286.1040 0.0840 ;
  END
 END tx[466]
 PIN tx[467]
  DIRECTION OUTPUT ;
  USE SIGNAL ;
  PORT
   LAYER M5 ;
   RECT 286.3200 0.0000 286.3440 0.0840 ;
  END
 END tx[467]
 PIN tx[468]
  DIRECTION OUTPUT ;
  USE SIGNAL ;
  PORT
   LAYER M5 ;
   RECT 286.5600 0.0000 286.5840 0.0840 ;
  END
 END tx[468]
 PIN tx[469]
  DIRECTION OUTPUT ;
  USE SIGNAL ;
  PORT
   LAYER M5 ;
   RECT 286.8000 0.0000 286.8240 0.0840 ;
  END
 END tx[469]
 PIN tx[470]
  DIRECTION OUTPUT ;
  USE SIGNAL ;
  PORT
   LAYER M5 ;
   RECT 287.0400 0.0000 287.0640 0.0840 ;
  END
 END tx[470]
 PIN tx[471]
  DIRECTION OUTPUT ;
  USE SIGNAL ;
  PORT
   LAYER M5 ;
   RECT 287.2800 0.0000 287.3040 0.0840 ;
  END
 END tx[471]
 PIN tx[472]
  DIRECTION OUTPUT ;
  USE SIGNAL ;
  PORT
   LAYER M5 ;
   RECT 287.5200 0.0000 287.5440 0.0840 ;
  END
 END tx[472]
 PIN tx[473]
  DIRECTION OUTPUT ;
  USE SIGNAL ;
  PORT
   LAYER M5 ;
   RECT 287.7600 0.0000 287.7840 0.0840 ;
  END
 END tx[473]
 PIN tx[474]
  DIRECTION OUTPUT ;
  USE SIGNAL ;
  PORT
   LAYER M5 ;
   RECT 288.0000 0.0000 288.0240 0.0840 ;
  END
 END tx[474]
 PIN tx[475]
  DIRECTION OUTPUT ;
  USE SIGNAL ;
  PORT
   LAYER M5 ;
   RECT 288.2400 0.0000 288.2640 0.0840 ;
  END
 END tx[475]
 PIN tx[476]
  DIRECTION OUTPUT ;
  USE SIGNAL ;
  PORT
   LAYER M5 ;
   RECT 288.4800 0.0000 288.5040 0.0840 ;
  END
 END tx[476]
 PIN tx[477]
  DIRECTION OUTPUT ;
  USE SIGNAL ;
  PORT
   LAYER M5 ;
   RECT 288.7200 0.0000 288.7440 0.0840 ;
  END
 END tx[477]
 PIN tx[478]
  DIRECTION OUTPUT ;
  USE SIGNAL ;
  PORT
   LAYER M5 ;
   RECT 288.9600 0.0000 288.9840 0.0840 ;
  END
 END tx[478]
 PIN tx[479]
  DIRECTION OUTPUT ;
  USE SIGNAL ;
  PORT
   LAYER M5 ;
   RECT 289.2000 0.0000 289.2240 0.0840 ;
  END
 END tx[479]
 PIN tx[480]
  DIRECTION OUTPUT ;
  USE SIGNAL ;
  PORT
   LAYER M5 ;
   RECT 289.4400 0.0000 289.4640 0.0840 ;
  END
 END tx[480]
 PIN tx[481]
  DIRECTION OUTPUT ;
  USE SIGNAL ;
  PORT
   LAYER M5 ;
   RECT 289.6800 0.0000 289.7040 0.0840 ;
  END
 END tx[481]
 PIN tx[482]
  DIRECTION OUTPUT ;
  USE SIGNAL ;
  PORT
   LAYER M5 ;
   RECT 289.9200 0.0000 289.9440 0.0840 ;
  END
 END tx[482]
 PIN tx[483]
  DIRECTION OUTPUT ;
  USE SIGNAL ;
  PORT
   LAYER M5 ;
   RECT 290.1600 0.0000 290.1840 0.0840 ;
  END
 END tx[483]
 PIN tx[484]
  DIRECTION OUTPUT ;
  USE SIGNAL ;
  PORT
   LAYER M5 ;
   RECT 290.4000 0.0000 290.4240 0.0840 ;
  END
 END tx[484]
 PIN tx[485]
  DIRECTION OUTPUT ;
  USE SIGNAL ;
  PORT
   LAYER M5 ;
   RECT 290.6400 0.0000 290.6640 0.0840 ;
  END
 END tx[485]
 PIN tx[486]
  DIRECTION OUTPUT ;
  USE SIGNAL ;
  PORT
   LAYER M5 ;
   RECT 290.8800 0.0000 290.9040 0.0840 ;
  END
 END tx[486]
 PIN tx[487]
  DIRECTION OUTPUT ;
  USE SIGNAL ;
  PORT
   LAYER M5 ;
   RECT 291.1200 0.0000 291.1440 0.0840 ;
  END
 END tx[487]
 PIN tx[488]
  DIRECTION OUTPUT ;
  USE SIGNAL ;
  PORT
   LAYER M5 ;
   RECT 291.3600 0.0000 291.3840 0.0840 ;
  END
 END tx[488]
 PIN tx[489]
  DIRECTION OUTPUT ;
  USE SIGNAL ;
  PORT
   LAYER M5 ;
   RECT 291.6000 0.0000 291.6240 0.0840 ;
  END
 END tx[489]
 PIN tx[490]
  DIRECTION OUTPUT ;
  USE SIGNAL ;
  PORT
   LAYER M5 ;
   RECT 291.8400 0.0000 291.8640 0.0840 ;
  END
 END tx[490]
 PIN tx[491]
  DIRECTION OUTPUT ;
  USE SIGNAL ;
  PORT
   LAYER M5 ;
   RECT 292.0800 0.0000 292.1040 0.0840 ;
  END
 END tx[491]
 PIN tx[492]
  DIRECTION OUTPUT ;
  USE SIGNAL ;
  PORT
   LAYER M5 ;
   RECT 292.3200 0.0000 292.3440 0.0840 ;
  END
 END tx[492]
 PIN tx[493]
  DIRECTION OUTPUT ;
  USE SIGNAL ;
  PORT
   LAYER M5 ;
   RECT 292.5600 0.0000 292.5840 0.0840 ;
  END
 END tx[493]
 PIN tx[494]
  DIRECTION OUTPUT ;
  USE SIGNAL ;
  PORT
   LAYER M5 ;
   RECT 292.8000 0.0000 292.8240 0.0840 ;
  END
 END tx[494]
 PIN tx[495]
  DIRECTION OUTPUT ;
  USE SIGNAL ;
  PORT
   LAYER M5 ;
   RECT 293.0400 0.0000 293.0640 0.0840 ;
  END
 END tx[495]
 PIN tx[496]
  DIRECTION OUTPUT ;
  USE SIGNAL ;
  PORT
   LAYER M5 ;
   RECT 293.2800 0.0000 293.3040 0.0840 ;
  END
 END tx[496]
 PIN tx[497]
  DIRECTION OUTPUT ;
  USE SIGNAL ;
  PORT
   LAYER M5 ;
   RECT 293.5200 0.0000 293.5440 0.0840 ;
  END
 END tx[497]
 PIN tx[498]
  DIRECTION OUTPUT ;
  USE SIGNAL ;
  PORT
   LAYER M5 ;
   RECT 293.7600 0.0000 293.7840 0.0840 ;
  END
 END tx[498]
 PIN tx[499]
  DIRECTION OUTPUT ;
  USE SIGNAL ;
  PORT
   LAYER M5 ;
   RECT 294.0000 0.0000 294.0240 0.0840 ;
  END
 END tx[499]
 PIN tx[500]
  DIRECTION OUTPUT ;
  USE SIGNAL ;
  PORT
   LAYER M5 ;
   RECT 294.2400 0.0000 294.2640 0.0840 ;
  END
 END tx[500]
 PIN tx[501]
  DIRECTION OUTPUT ;
  USE SIGNAL ;
  PORT
   LAYER M5 ;
   RECT 294.4800 0.0000 294.5040 0.0840 ;
  END
 END tx[501]
 PIN tx[502]
  DIRECTION OUTPUT ;
  USE SIGNAL ;
  PORT
   LAYER M5 ;
   RECT 294.7200 0.0000 294.7440 0.0840 ;
  END
 END tx[502]
 PIN tx[503]
  DIRECTION OUTPUT ;
  USE SIGNAL ;
  PORT
   LAYER M5 ;
   RECT 294.9600 0.0000 294.9840 0.0840 ;
  END
 END tx[503]
 PIN tx[504]
  DIRECTION OUTPUT ;
  USE SIGNAL ;
  PORT
   LAYER M5 ;
   RECT 295.2000 0.0000 295.2240 0.0840 ;
  END
 END tx[504]
 PIN tx[505]
  DIRECTION OUTPUT ;
  USE SIGNAL ;
  PORT
   LAYER M5 ;
   RECT 295.4400 0.0000 295.4640 0.0840 ;
  END
 END tx[505]
 PIN tx[506]
  DIRECTION OUTPUT ;
  USE SIGNAL ;
  PORT
   LAYER M5 ;
   RECT 295.6800 0.0000 295.7040 0.0840 ;
  END
 END tx[506]
 PIN tx[507]
  DIRECTION OUTPUT ;
  USE SIGNAL ;
  PORT
   LAYER M5 ;
   RECT 295.9200 0.0000 295.9440 0.0840 ;
  END
 END tx[507]
 PIN tx[508]
  DIRECTION OUTPUT ;
  USE SIGNAL ;
  PORT
   LAYER M5 ;
   RECT 296.1600 0.0000 296.1840 0.0840 ;
  END
 END tx[508]
 PIN tx[509]
  DIRECTION OUTPUT ;
  USE SIGNAL ;
  PORT
   LAYER M5 ;
   RECT 296.4000 0.0000 296.4240 0.0840 ;
  END
 END tx[509]
 PIN tx[510]
  DIRECTION OUTPUT ;
  USE SIGNAL ;
  PORT
   LAYER M5 ;
   RECT 296.6400 0.0000 296.6640 0.0840 ;
  END
 END tx[510]
 PIN tx[511]
  DIRECTION OUTPUT ;
  USE SIGNAL ;
  PORT
   LAYER M5 ;
   RECT 296.8800 0.0000 296.9040 0.0840 ;
  END
 END tx[511]
 PIN lo_d[0]
  DIRECTION INPUT ;
  USE SIGNAL ;
  PORT
   LAYER M5 ;
   RECT 6.1440 630.6360 6.1680 630.7200 ;
  END
 END lo_d[0]
 PIN lo_d[1]
  DIRECTION INPUT ;
  USE SIGNAL ;
  PORT
   LAYER M5 ;
   RECT 6.3840 630.6360 6.4080 630.7200 ;
  END
 END lo_d[1]
 PIN lo_d[2]
  DIRECTION INPUT ;
  USE SIGNAL ;
  PORT
   LAYER M5 ;
   RECT 6.6240 630.6360 6.6480 630.7200 ;
  END
 END lo_d[2]
 PIN lo_d[3]
  DIRECTION INPUT ;
  USE SIGNAL ;
  PORT
   LAYER M5 ;
   RECT 6.8640 630.6360 6.8880 630.7200 ;
  END
 END lo_d[3]
 PIN lo_d[4]
  DIRECTION INPUT ;
  USE SIGNAL ;
  PORT
   LAYER M5 ;
   RECT 7.1040 630.6360 7.1280 630.7200 ;
  END
 END lo_d[4]
 PIN lo_d[5]
  DIRECTION INPUT ;
  USE SIGNAL ;
  PORT
   LAYER M5 ;
   RECT 7.3440 630.6360 7.3680 630.7200 ;
  END
 END lo_d[5]
 PIN lo_d[6]
  DIRECTION INPUT ;
  USE SIGNAL ;
  PORT
   LAYER M5 ;
   RECT 7.5840 630.6360 7.6080 630.7200 ;
  END
 END lo_d[6]
 PIN lo_d[7]
  DIRECTION INPUT ;
  USE SIGNAL ;
  PORT
   LAYER M5 ;
   RECT 7.8240 630.6360 7.8480 630.7200 ;
  END
 END lo_d[7]
 PIN lo_d[8]
  DIRECTION INPUT ;
  USE SIGNAL ;
  PORT
   LAYER M5 ;
   RECT 8.0640 630.6360 8.0880 630.7200 ;
  END
 END lo_d[8]
 PIN lo_d[9]
  DIRECTION INPUT ;
  USE SIGNAL ;
  PORT
   LAYER M5 ;
   RECT 8.3040 630.6360 8.3280 630.7200 ;
  END
 END lo_d[9]
 PIN lo_d[10]
  DIRECTION INPUT ;
  USE SIGNAL ;
  PORT
   LAYER M5 ;
   RECT 8.5440 630.6360 8.5680 630.7200 ;
  END
 END lo_d[10]
 PIN lo_d[11]
  DIRECTION INPUT ;
  USE SIGNAL ;
  PORT
   LAYER M5 ;
   RECT 8.7840 630.6360 8.8080 630.7200 ;
  END
 END lo_d[11]
 PIN lo_d[12]
  DIRECTION INPUT ;
  USE SIGNAL ;
  PORT
   LAYER M5 ;
   RECT 9.0240 630.6360 9.0480 630.7200 ;
  END
 END lo_d[12]
 PIN lo_d[13]
  DIRECTION INPUT ;
  USE SIGNAL ;
  PORT
   LAYER M5 ;
   RECT 9.2640 630.6360 9.2880 630.7200 ;
  END
 END lo_d[13]
 PIN lo_d[14]
  DIRECTION INPUT ;
  USE SIGNAL ;
  PORT
   LAYER M5 ;
   RECT 9.5040 630.6360 9.5280 630.7200 ;
  END
 END lo_d[14]
 PIN lo_d[15]
  DIRECTION INPUT ;
  USE SIGNAL ;
  PORT
   LAYER M5 ;
   RECT 9.7440 630.6360 9.7680 630.7200 ;
  END
 END lo_d[15]
 PIN lo_d[16]
  DIRECTION INPUT ;
  USE SIGNAL ;
  PORT
   LAYER M5 ;
   RECT 9.9840 630.6360 10.0080 630.7200 ;
  END
 END lo_d[16]
 PIN lo_d[17]
  DIRECTION INPUT ;
  USE SIGNAL ;
  PORT
   LAYER M5 ;
   RECT 10.2240 630.6360 10.2480 630.7200 ;
  END
 END lo_d[17]
 PIN lo_d[18]
  DIRECTION INPUT ;
  USE SIGNAL ;
  PORT
   LAYER M5 ;
   RECT 10.4640 630.6360 10.4880 630.7200 ;
  END
 END lo_d[18]
 PIN lo_d[19]
  DIRECTION INPUT ;
  USE SIGNAL ;
  PORT
   LAYER M5 ;
   RECT 10.7040 630.6360 10.7280 630.7200 ;
  END
 END lo_d[19]
 PIN lo_d[20]
  DIRECTION INPUT ;
  USE SIGNAL ;
  PORT
   LAYER M5 ;
   RECT 10.9440 630.6360 10.9680 630.7200 ;
  END
 END lo_d[20]
 PIN lo_d[21]
  DIRECTION INPUT ;
  USE SIGNAL ;
  PORT
   LAYER M5 ;
   RECT 11.1840 630.6360 11.2080 630.7200 ;
  END
 END lo_d[21]
 PIN lo_d[22]
  DIRECTION INPUT ;
  USE SIGNAL ;
  PORT
   LAYER M5 ;
   RECT 11.4240 630.6360 11.4480 630.7200 ;
  END
 END lo_d[22]
 PIN lo_d[23]
  DIRECTION INPUT ;
  USE SIGNAL ;
  PORT
   LAYER M5 ;
   RECT 11.6640 630.6360 11.6880 630.7200 ;
  END
 END lo_d[23]
 PIN lo_d[24]
  DIRECTION INPUT ;
  USE SIGNAL ;
  PORT
   LAYER M5 ;
   RECT 11.9040 630.6360 11.9280 630.7200 ;
  END
 END lo_d[24]
 PIN lo_d[25]
  DIRECTION INPUT ;
  USE SIGNAL ;
  PORT
   LAYER M5 ;
   RECT 12.1440 630.6360 12.1680 630.7200 ;
  END
 END lo_d[25]
 PIN lo_d[26]
  DIRECTION INPUT ;
  USE SIGNAL ;
  PORT
   LAYER M5 ;
   RECT 12.3840 630.6360 12.4080 630.7200 ;
  END
 END lo_d[26]
 PIN lo_d[27]
  DIRECTION INPUT ;
  USE SIGNAL ;
  PORT
   LAYER M5 ;
   RECT 12.6240 630.6360 12.6480 630.7200 ;
  END
 END lo_d[27]
 PIN lo_d[28]
  DIRECTION INPUT ;
  USE SIGNAL ;
  PORT
   LAYER M5 ;
   RECT 12.8640 630.6360 12.8880 630.7200 ;
  END
 END lo_d[28]
 PIN lo_d[29]
  DIRECTION INPUT ;
  USE SIGNAL ;
  PORT
   LAYER M5 ;
   RECT 13.1040 630.6360 13.1280 630.7200 ;
  END
 END lo_d[29]
 PIN lo_d[30]
  DIRECTION INPUT ;
  USE SIGNAL ;
  PORT
   LAYER M5 ;
   RECT 13.3440 630.6360 13.3680 630.7200 ;
  END
 END lo_d[30]
 PIN lo_d[31]
  DIRECTION INPUT ;
  USE SIGNAL ;
  PORT
   LAYER M5 ;
   RECT 13.5840 630.6360 13.6080 630.7200 ;
  END
 END lo_d[31]
 PIN lo_d[32]
  DIRECTION INPUT ;
  USE SIGNAL ;
  PORT
   LAYER M5 ;
   RECT 13.8240 630.6360 13.8480 630.7200 ;
  END
 END lo_d[32]
 PIN lo_d[33]
  DIRECTION INPUT ;
  USE SIGNAL ;
  PORT
   LAYER M5 ;
   RECT 14.0640 630.6360 14.0880 630.7200 ;
  END
 END lo_d[33]
 PIN lo_d[34]
  DIRECTION INPUT ;
  USE SIGNAL ;
  PORT
   LAYER M5 ;
   RECT 14.3040 630.6360 14.3280 630.7200 ;
  END
 END lo_d[34]
 PIN lo_d[35]
  DIRECTION INPUT ;
  USE SIGNAL ;
  PORT
   LAYER M5 ;
   RECT 14.5440 630.6360 14.5680 630.7200 ;
  END
 END lo_d[35]
 PIN lo_d[36]
  DIRECTION INPUT ;
  USE SIGNAL ;
  PORT
   LAYER M5 ;
   RECT 14.7840 630.6360 14.8080 630.7200 ;
  END
 END lo_d[36]
 PIN lo_d[37]
  DIRECTION INPUT ;
  USE SIGNAL ;
  PORT
   LAYER M5 ;
   RECT 15.0240 630.6360 15.0480 630.7200 ;
  END
 END lo_d[37]
 PIN lo_d[38]
  DIRECTION INPUT ;
  USE SIGNAL ;
  PORT
   LAYER M5 ;
   RECT 15.2640 630.6360 15.2880 630.7200 ;
  END
 END lo_d[38]
 PIN lo_d[39]
  DIRECTION INPUT ;
  USE SIGNAL ;
  PORT
   LAYER M5 ;
   RECT 15.5040 630.6360 15.5280 630.7200 ;
  END
 END lo_d[39]
 PIN lo_d[40]
  DIRECTION INPUT ;
  USE SIGNAL ;
  PORT
   LAYER M5 ;
   RECT 15.7440 630.6360 15.7680 630.7200 ;
  END
 END lo_d[40]
 PIN lo_d[41]
  DIRECTION INPUT ;
  USE SIGNAL ;
  PORT
   LAYER M5 ;
   RECT 15.9840 630.6360 16.0080 630.7200 ;
  END
 END lo_d[41]
 PIN lo_d[42]
  DIRECTION INPUT ;
  USE SIGNAL ;
  PORT
   LAYER M5 ;
   RECT 16.2240 630.6360 16.2480 630.7200 ;
  END
 END lo_d[42]
 PIN lo_d[43]
  DIRECTION INPUT ;
  USE SIGNAL ;
  PORT
   LAYER M5 ;
   RECT 16.4640 630.6360 16.4880 630.7200 ;
  END
 END lo_d[43]
 PIN lo_d[44]
  DIRECTION INPUT ;
  USE SIGNAL ;
  PORT
   LAYER M5 ;
   RECT 16.7040 630.6360 16.7280 630.7200 ;
  END
 END lo_d[44]
 PIN lo_d[45]
  DIRECTION INPUT ;
  USE SIGNAL ;
  PORT
   LAYER M5 ;
   RECT 16.9440 630.6360 16.9680 630.7200 ;
  END
 END lo_d[45]
 PIN lo_d[46]
  DIRECTION INPUT ;
  USE SIGNAL ;
  PORT
   LAYER M5 ;
   RECT 17.1840 630.6360 17.2080 630.7200 ;
  END
 END lo_d[46]
 PIN lo_d[47]
  DIRECTION INPUT ;
  USE SIGNAL ;
  PORT
   LAYER M5 ;
   RECT 17.4240 630.6360 17.4480 630.7200 ;
  END
 END lo_d[47]
 PIN lo_d[48]
  DIRECTION INPUT ;
  USE SIGNAL ;
  PORT
   LAYER M5 ;
   RECT 17.6640 630.6360 17.6880 630.7200 ;
  END
 END lo_d[48]
 PIN lo_d[49]
  DIRECTION INPUT ;
  USE SIGNAL ;
  PORT
   LAYER M5 ;
   RECT 17.9040 630.6360 17.9280 630.7200 ;
  END
 END lo_d[49]
 PIN lo_d[50]
  DIRECTION INPUT ;
  USE SIGNAL ;
  PORT
   LAYER M5 ;
   RECT 18.1440 630.6360 18.1680 630.7200 ;
  END
 END lo_d[50]
 PIN lo_d[51]
  DIRECTION INPUT ;
  USE SIGNAL ;
  PORT
   LAYER M5 ;
   RECT 18.3840 630.6360 18.4080 630.7200 ;
  END
 END lo_d[51]
 PIN lo_d[52]
  DIRECTION INPUT ;
  USE SIGNAL ;
  PORT
   LAYER M5 ;
   RECT 18.6240 630.6360 18.6480 630.7200 ;
  END
 END lo_d[52]
 PIN lo_d[53]
  DIRECTION INPUT ;
  USE SIGNAL ;
  PORT
   LAYER M5 ;
   RECT 18.8640 630.6360 18.8880 630.7200 ;
  END
 END lo_d[53]
 PIN lo_d[54]
  DIRECTION INPUT ;
  USE SIGNAL ;
  PORT
   LAYER M5 ;
   RECT 19.1040 630.6360 19.1280 630.7200 ;
  END
 END lo_d[54]
 PIN lo_d[55]
  DIRECTION INPUT ;
  USE SIGNAL ;
  PORT
   LAYER M5 ;
   RECT 19.3440 630.6360 19.3680 630.7200 ;
  END
 END lo_d[55]
 PIN lo_d[56]
  DIRECTION INPUT ;
  USE SIGNAL ;
  PORT
   LAYER M5 ;
   RECT 19.5840 630.6360 19.6080 630.7200 ;
  END
 END lo_d[56]
 PIN lo_d[57]
  DIRECTION INPUT ;
  USE SIGNAL ;
  PORT
   LAYER M5 ;
   RECT 19.8240 630.6360 19.8480 630.7200 ;
  END
 END lo_d[57]
 PIN lo_d[58]
  DIRECTION INPUT ;
  USE SIGNAL ;
  PORT
   LAYER M5 ;
   RECT 20.0640 630.6360 20.0880 630.7200 ;
  END
 END lo_d[58]
 PIN lo_d[59]
  DIRECTION INPUT ;
  USE SIGNAL ;
  PORT
   LAYER M5 ;
   RECT 20.3040 630.6360 20.3280 630.7200 ;
  END
 END lo_d[59]
 PIN lo_d[60]
  DIRECTION INPUT ;
  USE SIGNAL ;
  PORT
   LAYER M5 ;
   RECT 20.5440 630.6360 20.5680 630.7200 ;
  END
 END lo_d[60]
 PIN lo_d[61]
  DIRECTION INPUT ;
  USE SIGNAL ;
  PORT
   LAYER M5 ;
   RECT 20.7840 630.6360 20.8080 630.7200 ;
  END
 END lo_d[61]
 PIN lo_d[62]
  DIRECTION INPUT ;
  USE SIGNAL ;
  PORT
   LAYER M5 ;
   RECT 21.0240 630.6360 21.0480 630.7200 ;
  END
 END lo_d[62]
 PIN lo_d[63]
  DIRECTION INPUT ;
  USE SIGNAL ;
  PORT
   LAYER M5 ;
   RECT 21.2640 630.6360 21.2880 630.7200 ;
  END
 END lo_d[63]
 PIN lo_d[64]
  DIRECTION INPUT ;
  USE SIGNAL ;
  PORT
   LAYER M5 ;
   RECT 21.5040 630.6360 21.5280 630.7200 ;
  END
 END lo_d[64]
 PIN lo_d[65]
  DIRECTION INPUT ;
  USE SIGNAL ;
  PORT
   LAYER M5 ;
   RECT 21.7440 630.6360 21.7680 630.7200 ;
  END
 END lo_d[65]
 PIN lo_d[66]
  DIRECTION INPUT ;
  USE SIGNAL ;
  PORT
   LAYER M5 ;
   RECT 21.9840 630.6360 22.0080 630.7200 ;
  END
 END lo_d[66]
 PIN lo_d[67]
  DIRECTION INPUT ;
  USE SIGNAL ;
  PORT
   LAYER M5 ;
   RECT 22.2240 630.6360 22.2480 630.7200 ;
  END
 END lo_d[67]
 PIN lo_d[68]
  DIRECTION INPUT ;
  USE SIGNAL ;
  PORT
   LAYER M5 ;
   RECT 22.4640 630.6360 22.4880 630.7200 ;
  END
 END lo_d[68]
 PIN lo_d[69]
  DIRECTION INPUT ;
  USE SIGNAL ;
  PORT
   LAYER M5 ;
   RECT 22.7040 630.6360 22.7280 630.7200 ;
  END
 END lo_d[69]
 PIN lo_d[70]
  DIRECTION INPUT ;
  USE SIGNAL ;
  PORT
   LAYER M5 ;
   RECT 22.9440 630.6360 22.9680 630.7200 ;
  END
 END lo_d[70]
 PIN lo_d[71]
  DIRECTION INPUT ;
  USE SIGNAL ;
  PORT
   LAYER M5 ;
   RECT 23.1840 630.6360 23.2080 630.7200 ;
  END
 END lo_d[71]
 PIN lo_d[72]
  DIRECTION INPUT ;
  USE SIGNAL ;
  PORT
   LAYER M5 ;
   RECT 23.4240 630.6360 23.4480 630.7200 ;
  END
 END lo_d[72]
 PIN lo_d[73]
  DIRECTION INPUT ;
  USE SIGNAL ;
  PORT
   LAYER M5 ;
   RECT 23.6640 630.6360 23.6880 630.7200 ;
  END
 END lo_d[73]
 PIN lo_d[74]
  DIRECTION INPUT ;
  USE SIGNAL ;
  PORT
   LAYER M5 ;
   RECT 23.9040 630.6360 23.9280 630.7200 ;
  END
 END lo_d[74]
 PIN lo_d[75]
  DIRECTION INPUT ;
  USE SIGNAL ;
  PORT
   LAYER M5 ;
   RECT 24.1440 630.6360 24.1680 630.7200 ;
  END
 END lo_d[75]
 PIN lo_d[76]
  DIRECTION INPUT ;
  USE SIGNAL ;
  PORT
   LAYER M5 ;
   RECT 24.3840 630.6360 24.4080 630.7200 ;
  END
 END lo_d[76]
 PIN lo_d[77]
  DIRECTION INPUT ;
  USE SIGNAL ;
  PORT
   LAYER M5 ;
   RECT 24.6240 630.6360 24.6480 630.7200 ;
  END
 END lo_d[77]
 PIN lo_d[78]
  DIRECTION INPUT ;
  USE SIGNAL ;
  PORT
   LAYER M5 ;
   RECT 24.8640 630.6360 24.8880 630.7200 ;
  END
 END lo_d[78]
 PIN lo_d[79]
  DIRECTION INPUT ;
  USE SIGNAL ;
  PORT
   LAYER M5 ;
   RECT 25.1040 630.6360 25.1280 630.7200 ;
  END
 END lo_d[79]
 PIN lo_d[80]
  DIRECTION INPUT ;
  USE SIGNAL ;
  PORT
   LAYER M5 ;
   RECT 25.3440 630.6360 25.3680 630.7200 ;
  END
 END lo_d[80]
 PIN lo_d[81]
  DIRECTION INPUT ;
  USE SIGNAL ;
  PORT
   LAYER M5 ;
   RECT 25.5840 630.6360 25.6080 630.7200 ;
  END
 END lo_d[81]
 PIN lo_d[82]
  DIRECTION INPUT ;
  USE SIGNAL ;
  PORT
   LAYER M5 ;
   RECT 25.8240 630.6360 25.8480 630.7200 ;
  END
 END lo_d[82]
 PIN lo_d[83]
  DIRECTION INPUT ;
  USE SIGNAL ;
  PORT
   LAYER M5 ;
   RECT 26.0640 630.6360 26.0880 630.7200 ;
  END
 END lo_d[83]
 PIN lo_d[84]
  DIRECTION INPUT ;
  USE SIGNAL ;
  PORT
   LAYER M5 ;
   RECT 26.3040 630.6360 26.3280 630.7200 ;
  END
 END lo_d[84]
 PIN lo_d[85]
  DIRECTION INPUT ;
  USE SIGNAL ;
  PORT
   LAYER M5 ;
   RECT 26.5440 630.6360 26.5680 630.7200 ;
  END
 END lo_d[85]
 PIN lo_d[86]
  DIRECTION INPUT ;
  USE SIGNAL ;
  PORT
   LAYER M5 ;
   RECT 26.7840 630.6360 26.8080 630.7200 ;
  END
 END lo_d[86]
 PIN lo_d[87]
  DIRECTION INPUT ;
  USE SIGNAL ;
  PORT
   LAYER M5 ;
   RECT 27.0240 630.6360 27.0480 630.7200 ;
  END
 END lo_d[87]
 PIN lo_d[88]
  DIRECTION INPUT ;
  USE SIGNAL ;
  PORT
   LAYER M5 ;
   RECT 27.2640 630.6360 27.2880 630.7200 ;
  END
 END lo_d[88]
 PIN lo_d[89]
  DIRECTION INPUT ;
  USE SIGNAL ;
  PORT
   LAYER M5 ;
   RECT 27.5040 630.6360 27.5280 630.7200 ;
  END
 END lo_d[89]
 PIN lo_d[90]
  DIRECTION INPUT ;
  USE SIGNAL ;
  PORT
   LAYER M5 ;
   RECT 27.7440 630.6360 27.7680 630.7200 ;
  END
 END lo_d[90]
 PIN lo_d[91]
  DIRECTION INPUT ;
  USE SIGNAL ;
  PORT
   LAYER M5 ;
   RECT 27.9840 630.6360 28.0080 630.7200 ;
  END
 END lo_d[91]
 PIN lo_d[92]
  DIRECTION INPUT ;
  USE SIGNAL ;
  PORT
   LAYER M5 ;
   RECT 28.2240 630.6360 28.2480 630.7200 ;
  END
 END lo_d[92]
 PIN lo_d[93]
  DIRECTION INPUT ;
  USE SIGNAL ;
  PORT
   LAYER M5 ;
   RECT 28.4640 630.6360 28.4880 630.7200 ;
  END
 END lo_d[93]
 PIN lo_d[94]
  DIRECTION INPUT ;
  USE SIGNAL ;
  PORT
   LAYER M5 ;
   RECT 28.7040 630.6360 28.7280 630.7200 ;
  END
 END lo_d[94]
 PIN lo_d[95]
  DIRECTION INPUT ;
  USE SIGNAL ;
  PORT
   LAYER M5 ;
   RECT 28.9440 630.6360 28.9680 630.7200 ;
  END
 END lo_d[95]
 PIN lo_d[96]
  DIRECTION INPUT ;
  USE SIGNAL ;
  PORT
   LAYER M5 ;
   RECT 29.1840 630.6360 29.2080 630.7200 ;
  END
 END lo_d[96]
 PIN lo_d[97]
  DIRECTION INPUT ;
  USE SIGNAL ;
  PORT
   LAYER M5 ;
   RECT 29.4240 630.6360 29.4480 630.7200 ;
  END
 END lo_d[97]
 PIN lo_d[98]
  DIRECTION INPUT ;
  USE SIGNAL ;
  PORT
   LAYER M5 ;
   RECT 29.6640 630.6360 29.6880 630.7200 ;
  END
 END lo_d[98]
 PIN lo_d[99]
  DIRECTION INPUT ;
  USE SIGNAL ;
  PORT
   LAYER M5 ;
   RECT 29.9040 630.6360 29.9280 630.7200 ;
  END
 END lo_d[99]
 PIN lo_d[100]
  DIRECTION INPUT ;
  USE SIGNAL ;
  PORT
   LAYER M5 ;
   RECT 30.1440 630.6360 30.1680 630.7200 ;
  END
 END lo_d[100]
 PIN lo_d[101]
  DIRECTION INPUT ;
  USE SIGNAL ;
  PORT
   LAYER M5 ;
   RECT 30.3840 630.6360 30.4080 630.7200 ;
  END
 END lo_d[101]
 PIN lo_d[102]
  DIRECTION INPUT ;
  USE SIGNAL ;
  PORT
   LAYER M5 ;
   RECT 30.6240 630.6360 30.6480 630.7200 ;
  END
 END lo_d[102]
 PIN lo_d[103]
  DIRECTION INPUT ;
  USE SIGNAL ;
  PORT
   LAYER M5 ;
   RECT 30.8640 630.6360 30.8880 630.7200 ;
  END
 END lo_d[103]
 PIN lo_d[104]
  DIRECTION INPUT ;
  USE SIGNAL ;
  PORT
   LAYER M5 ;
   RECT 31.1040 630.6360 31.1280 630.7200 ;
  END
 END lo_d[104]
 PIN lo_d[105]
  DIRECTION INPUT ;
  USE SIGNAL ;
  PORT
   LAYER M5 ;
   RECT 31.3440 630.6360 31.3680 630.7200 ;
  END
 END lo_d[105]
 PIN lo_d[106]
  DIRECTION INPUT ;
  USE SIGNAL ;
  PORT
   LAYER M5 ;
   RECT 31.5840 630.6360 31.6080 630.7200 ;
  END
 END lo_d[106]
 PIN lo_d[107]
  DIRECTION INPUT ;
  USE SIGNAL ;
  PORT
   LAYER M5 ;
   RECT 31.8240 630.6360 31.8480 630.7200 ;
  END
 END lo_d[107]
 PIN lo_d[108]
  DIRECTION INPUT ;
  USE SIGNAL ;
  PORT
   LAYER M5 ;
   RECT 32.0640 630.6360 32.0880 630.7200 ;
  END
 END lo_d[108]
 PIN lo_d[109]
  DIRECTION INPUT ;
  USE SIGNAL ;
  PORT
   LAYER M5 ;
   RECT 32.3040 630.6360 32.3280 630.7200 ;
  END
 END lo_d[109]
 PIN lo_d[110]
  DIRECTION INPUT ;
  USE SIGNAL ;
  PORT
   LAYER M5 ;
   RECT 32.5440 630.6360 32.5680 630.7200 ;
  END
 END lo_d[110]
 PIN lo_d[111]
  DIRECTION INPUT ;
  USE SIGNAL ;
  PORT
   LAYER M5 ;
   RECT 32.7840 630.6360 32.8080 630.7200 ;
  END
 END lo_d[111]
 PIN lo_d[112]
  DIRECTION INPUT ;
  USE SIGNAL ;
  PORT
   LAYER M5 ;
   RECT 33.0240 630.6360 33.0480 630.7200 ;
  END
 END lo_d[112]
 PIN lo_d[113]
  DIRECTION INPUT ;
  USE SIGNAL ;
  PORT
   LAYER M5 ;
   RECT 33.2640 630.6360 33.2880 630.7200 ;
  END
 END lo_d[113]
 PIN lo_d[114]
  DIRECTION INPUT ;
  USE SIGNAL ;
  PORT
   LAYER M5 ;
   RECT 33.5040 630.6360 33.5280 630.7200 ;
  END
 END lo_d[114]
 PIN lo_d[115]
  DIRECTION INPUT ;
  USE SIGNAL ;
  PORT
   LAYER M5 ;
   RECT 33.7440 630.6360 33.7680 630.7200 ;
  END
 END lo_d[115]
 PIN lo_d[116]
  DIRECTION INPUT ;
  USE SIGNAL ;
  PORT
   LAYER M5 ;
   RECT 33.9840 630.6360 34.0080 630.7200 ;
  END
 END lo_d[116]
 PIN lo_d[117]
  DIRECTION INPUT ;
  USE SIGNAL ;
  PORT
   LAYER M5 ;
   RECT 34.2240 630.6360 34.2480 630.7200 ;
  END
 END lo_d[117]
 PIN lo_d[118]
  DIRECTION INPUT ;
  USE SIGNAL ;
  PORT
   LAYER M5 ;
   RECT 34.4640 630.6360 34.4880 630.7200 ;
  END
 END lo_d[118]
 PIN lo_d[119]
  DIRECTION INPUT ;
  USE SIGNAL ;
  PORT
   LAYER M5 ;
   RECT 34.7040 630.6360 34.7280 630.7200 ;
  END
 END lo_d[119]
 PIN lo_d[120]
  DIRECTION INPUT ;
  USE SIGNAL ;
  PORT
   LAYER M5 ;
   RECT 34.9440 630.6360 34.9680 630.7200 ;
  END
 END lo_d[120]
 PIN lo_d[121]
  DIRECTION INPUT ;
  USE SIGNAL ;
  PORT
   LAYER M5 ;
   RECT 35.1840 630.6360 35.2080 630.7200 ;
  END
 END lo_d[121]
 PIN lo_d[122]
  DIRECTION INPUT ;
  USE SIGNAL ;
  PORT
   LAYER M5 ;
   RECT 35.4240 630.6360 35.4480 630.7200 ;
  END
 END lo_d[122]
 PIN lo_d[123]
  DIRECTION INPUT ;
  USE SIGNAL ;
  PORT
   LAYER M5 ;
   RECT 35.6640 630.6360 35.6880 630.7200 ;
  END
 END lo_d[123]
 PIN lo_d[124]
  DIRECTION INPUT ;
  USE SIGNAL ;
  PORT
   LAYER M5 ;
   RECT 35.9040 630.6360 35.9280 630.7200 ;
  END
 END lo_d[124]
 PIN lo_d[125]
  DIRECTION INPUT ;
  USE SIGNAL ;
  PORT
   LAYER M5 ;
   RECT 36.1440 630.6360 36.1680 630.7200 ;
  END
 END lo_d[125]
 PIN lo_d[126]
  DIRECTION INPUT ;
  USE SIGNAL ;
  PORT
   LAYER M5 ;
   RECT 36.3840 630.6360 36.4080 630.7200 ;
  END
 END lo_d[126]
 PIN lo_d[127]
  DIRECTION INPUT ;
  USE SIGNAL ;
  PORT
   LAYER M5 ;
   RECT 36.6240 630.6360 36.6480 630.7200 ;
  END
 END lo_d[127]
 PIN lo_d[128]
  DIRECTION INPUT ;
  USE SIGNAL ;
  PORT
   LAYER M5 ;
   RECT 36.8640 630.6360 36.8880 630.7200 ;
  END
 END lo_d[128]
 PIN lo_d[129]
  DIRECTION INPUT ;
  USE SIGNAL ;
  PORT
   LAYER M5 ;
   RECT 37.1040 630.6360 37.1280 630.7200 ;
  END
 END lo_d[129]
 PIN lo_d[130]
  DIRECTION INPUT ;
  USE SIGNAL ;
  PORT
   LAYER M5 ;
   RECT 37.3440 630.6360 37.3680 630.7200 ;
  END
 END lo_d[130]
 PIN lo_d[131]
  DIRECTION INPUT ;
  USE SIGNAL ;
  PORT
   LAYER M5 ;
   RECT 37.5840 630.6360 37.6080 630.7200 ;
  END
 END lo_d[131]
 PIN lo_d[132]
  DIRECTION INPUT ;
  USE SIGNAL ;
  PORT
   LAYER M5 ;
   RECT 37.8240 630.6360 37.8480 630.7200 ;
  END
 END lo_d[132]
 PIN lo_d[133]
  DIRECTION INPUT ;
  USE SIGNAL ;
  PORT
   LAYER M5 ;
   RECT 38.0640 630.6360 38.0880 630.7200 ;
  END
 END lo_d[133]
 PIN lo_d[134]
  DIRECTION INPUT ;
  USE SIGNAL ;
  PORT
   LAYER M5 ;
   RECT 38.3040 630.6360 38.3280 630.7200 ;
  END
 END lo_d[134]
 PIN lo_d[135]
  DIRECTION INPUT ;
  USE SIGNAL ;
  PORT
   LAYER M5 ;
   RECT 38.5440 630.6360 38.5680 630.7200 ;
  END
 END lo_d[135]
 PIN lo_d[136]
  DIRECTION INPUT ;
  USE SIGNAL ;
  PORT
   LAYER M5 ;
   RECT 38.7840 630.6360 38.8080 630.7200 ;
  END
 END lo_d[136]
 PIN lo_d[137]
  DIRECTION INPUT ;
  USE SIGNAL ;
  PORT
   LAYER M5 ;
   RECT 39.0240 630.6360 39.0480 630.7200 ;
  END
 END lo_d[137]
 PIN lo_d[138]
  DIRECTION INPUT ;
  USE SIGNAL ;
  PORT
   LAYER M5 ;
   RECT 39.2640 630.6360 39.2880 630.7200 ;
  END
 END lo_d[138]
 PIN lo_d[139]
  DIRECTION INPUT ;
  USE SIGNAL ;
  PORT
   LAYER M5 ;
   RECT 39.5040 630.6360 39.5280 630.7200 ;
  END
 END lo_d[139]
 PIN lo_d[140]
  DIRECTION INPUT ;
  USE SIGNAL ;
  PORT
   LAYER M5 ;
   RECT 39.7440 630.6360 39.7680 630.7200 ;
  END
 END lo_d[140]
 PIN lo_d[141]
  DIRECTION INPUT ;
  USE SIGNAL ;
  PORT
   LAYER M5 ;
   RECT 39.9840 630.6360 40.0080 630.7200 ;
  END
 END lo_d[141]
 PIN lo_d[142]
  DIRECTION INPUT ;
  USE SIGNAL ;
  PORT
   LAYER M5 ;
   RECT 40.2240 630.6360 40.2480 630.7200 ;
  END
 END lo_d[142]
 PIN lo_d[143]
  DIRECTION INPUT ;
  USE SIGNAL ;
  PORT
   LAYER M5 ;
   RECT 40.4640 630.6360 40.4880 630.7200 ;
  END
 END lo_d[143]
 PIN lo_d[144]
  DIRECTION INPUT ;
  USE SIGNAL ;
  PORT
   LAYER M5 ;
   RECT 40.7040 630.6360 40.7280 630.7200 ;
  END
 END lo_d[144]
 PIN lo_d[145]
  DIRECTION INPUT ;
  USE SIGNAL ;
  PORT
   LAYER M5 ;
   RECT 40.9440 630.6360 40.9680 630.7200 ;
  END
 END lo_d[145]
 PIN lo_d[146]
  DIRECTION INPUT ;
  USE SIGNAL ;
  PORT
   LAYER M5 ;
   RECT 41.1840 630.6360 41.2080 630.7200 ;
  END
 END lo_d[146]
 PIN lo_d[147]
  DIRECTION INPUT ;
  USE SIGNAL ;
  PORT
   LAYER M5 ;
   RECT 41.4240 630.6360 41.4480 630.7200 ;
  END
 END lo_d[147]
 PIN lo_d[148]
  DIRECTION INPUT ;
  USE SIGNAL ;
  PORT
   LAYER M5 ;
   RECT 41.6640 630.6360 41.6880 630.7200 ;
  END
 END lo_d[148]
 PIN lo_d[149]
  DIRECTION INPUT ;
  USE SIGNAL ;
  PORT
   LAYER M5 ;
   RECT 41.9040 630.6360 41.9280 630.7200 ;
  END
 END lo_d[149]
 PIN lo_d[150]
  DIRECTION INPUT ;
  USE SIGNAL ;
  PORT
   LAYER M5 ;
   RECT 42.1440 630.6360 42.1680 630.7200 ;
  END
 END lo_d[150]
 PIN lo_d[151]
  DIRECTION INPUT ;
  USE SIGNAL ;
  PORT
   LAYER M5 ;
   RECT 42.3840 630.6360 42.4080 630.7200 ;
  END
 END lo_d[151]
 PIN lo_d[152]
  DIRECTION INPUT ;
  USE SIGNAL ;
  PORT
   LAYER M5 ;
   RECT 42.6240 630.6360 42.6480 630.7200 ;
  END
 END lo_d[152]
 PIN lo_d[153]
  DIRECTION INPUT ;
  USE SIGNAL ;
  PORT
   LAYER M5 ;
   RECT 42.8640 630.6360 42.8880 630.7200 ;
  END
 END lo_d[153]
 PIN lo_d[154]
  DIRECTION INPUT ;
  USE SIGNAL ;
  PORT
   LAYER M5 ;
   RECT 43.1040 630.6360 43.1280 630.7200 ;
  END
 END lo_d[154]
 PIN lo_d[155]
  DIRECTION INPUT ;
  USE SIGNAL ;
  PORT
   LAYER M5 ;
   RECT 43.3440 630.6360 43.3680 630.7200 ;
  END
 END lo_d[155]
 PIN lo_d[156]
  DIRECTION INPUT ;
  USE SIGNAL ;
  PORT
   LAYER M5 ;
   RECT 43.5840 630.6360 43.6080 630.7200 ;
  END
 END lo_d[156]
 PIN lo_d[157]
  DIRECTION INPUT ;
  USE SIGNAL ;
  PORT
   LAYER M5 ;
   RECT 43.8240 630.6360 43.8480 630.7200 ;
  END
 END lo_d[157]
 PIN lo_d[158]
  DIRECTION INPUT ;
  USE SIGNAL ;
  PORT
   LAYER M5 ;
   RECT 44.0640 630.6360 44.0880 630.7200 ;
  END
 END lo_d[158]
 PIN lo_d[159]
  DIRECTION INPUT ;
  USE SIGNAL ;
  PORT
   LAYER M5 ;
   RECT 44.3040 630.6360 44.3280 630.7200 ;
  END
 END lo_d[159]
 PIN lo_d[160]
  DIRECTION INPUT ;
  USE SIGNAL ;
  PORT
   LAYER M5 ;
   RECT 44.5440 630.6360 44.5680 630.7200 ;
  END
 END lo_d[160]
 PIN lo_d[161]
  DIRECTION INPUT ;
  USE SIGNAL ;
  PORT
   LAYER M5 ;
   RECT 44.7840 630.6360 44.8080 630.7200 ;
  END
 END lo_d[161]
 PIN lo_d[162]
  DIRECTION INPUT ;
  USE SIGNAL ;
  PORT
   LAYER M5 ;
   RECT 45.0240 630.6360 45.0480 630.7200 ;
  END
 END lo_d[162]
 PIN lo_d[163]
  DIRECTION INPUT ;
  USE SIGNAL ;
  PORT
   LAYER M5 ;
   RECT 45.2640 630.6360 45.2880 630.7200 ;
  END
 END lo_d[163]
 PIN lo_d[164]
  DIRECTION INPUT ;
  USE SIGNAL ;
  PORT
   LAYER M5 ;
   RECT 45.5040 630.6360 45.5280 630.7200 ;
  END
 END lo_d[164]
 PIN lo_d[165]
  DIRECTION INPUT ;
  USE SIGNAL ;
  PORT
   LAYER M5 ;
   RECT 45.7440 630.6360 45.7680 630.7200 ;
  END
 END lo_d[165]
 PIN lo_d[166]
  DIRECTION INPUT ;
  USE SIGNAL ;
  PORT
   LAYER M5 ;
   RECT 45.9840 630.6360 46.0080 630.7200 ;
  END
 END lo_d[166]
 PIN lo_d[167]
  DIRECTION INPUT ;
  USE SIGNAL ;
  PORT
   LAYER M5 ;
   RECT 46.2240 630.6360 46.2480 630.7200 ;
  END
 END lo_d[167]
 PIN lo_d[168]
  DIRECTION INPUT ;
  USE SIGNAL ;
  PORT
   LAYER M5 ;
   RECT 46.4640 630.6360 46.4880 630.7200 ;
  END
 END lo_d[168]
 PIN lo_d[169]
  DIRECTION INPUT ;
  USE SIGNAL ;
  PORT
   LAYER M5 ;
   RECT 46.7040 630.6360 46.7280 630.7200 ;
  END
 END lo_d[169]
 PIN lo_d[170]
  DIRECTION INPUT ;
  USE SIGNAL ;
  PORT
   LAYER M5 ;
   RECT 46.9440 630.6360 46.9680 630.7200 ;
  END
 END lo_d[170]
 PIN lo_d[171]
  DIRECTION INPUT ;
  USE SIGNAL ;
  PORT
   LAYER M5 ;
   RECT 47.1840 630.6360 47.2080 630.7200 ;
  END
 END lo_d[171]
 PIN lo_d[172]
  DIRECTION INPUT ;
  USE SIGNAL ;
  PORT
   LAYER M5 ;
   RECT 47.4240 630.6360 47.4480 630.7200 ;
  END
 END lo_d[172]
 PIN lo_d[173]
  DIRECTION INPUT ;
  USE SIGNAL ;
  PORT
   LAYER M5 ;
   RECT 47.6640 630.6360 47.6880 630.7200 ;
  END
 END lo_d[173]
 PIN lo_d[174]
  DIRECTION INPUT ;
  USE SIGNAL ;
  PORT
   LAYER M5 ;
   RECT 47.9040 630.6360 47.9280 630.7200 ;
  END
 END lo_d[174]
 PIN lo_d[175]
  DIRECTION INPUT ;
  USE SIGNAL ;
  PORT
   LAYER M5 ;
   RECT 48.1440 630.6360 48.1680 630.7200 ;
  END
 END lo_d[175]
 PIN lo_d[176]
  DIRECTION INPUT ;
  USE SIGNAL ;
  PORT
   LAYER M5 ;
   RECT 48.3840 630.6360 48.4080 630.7200 ;
  END
 END lo_d[176]
 PIN lo_d[177]
  DIRECTION INPUT ;
  USE SIGNAL ;
  PORT
   LAYER M5 ;
   RECT 48.6240 630.6360 48.6480 630.7200 ;
  END
 END lo_d[177]
 PIN lo_d[178]
  DIRECTION INPUT ;
  USE SIGNAL ;
  PORT
   LAYER M5 ;
   RECT 48.8640 630.6360 48.8880 630.7200 ;
  END
 END lo_d[178]
 PIN lo_d[179]
  DIRECTION INPUT ;
  USE SIGNAL ;
  PORT
   LAYER M5 ;
   RECT 49.1040 630.6360 49.1280 630.7200 ;
  END
 END lo_d[179]
 PIN lo_d[180]
  DIRECTION INPUT ;
  USE SIGNAL ;
  PORT
   LAYER M5 ;
   RECT 49.3440 630.6360 49.3680 630.7200 ;
  END
 END lo_d[180]
 PIN lo_d[181]
  DIRECTION INPUT ;
  USE SIGNAL ;
  PORT
   LAYER M5 ;
   RECT 49.5840 630.6360 49.6080 630.7200 ;
  END
 END lo_d[181]
 PIN lo_d[182]
  DIRECTION INPUT ;
  USE SIGNAL ;
  PORT
   LAYER M5 ;
   RECT 49.8240 630.6360 49.8480 630.7200 ;
  END
 END lo_d[182]
 PIN lo_d[183]
  DIRECTION INPUT ;
  USE SIGNAL ;
  PORT
   LAYER M5 ;
   RECT 50.0640 630.6360 50.0880 630.7200 ;
  END
 END lo_d[183]
 PIN lo_d[184]
  DIRECTION INPUT ;
  USE SIGNAL ;
  PORT
   LAYER M5 ;
   RECT 50.3040 630.6360 50.3280 630.7200 ;
  END
 END lo_d[184]
 PIN lo_d[185]
  DIRECTION INPUT ;
  USE SIGNAL ;
  PORT
   LAYER M5 ;
   RECT 50.5440 630.6360 50.5680 630.7200 ;
  END
 END lo_d[185]
 PIN lo_d[186]
  DIRECTION INPUT ;
  USE SIGNAL ;
  PORT
   LAYER M5 ;
   RECT 50.7840 630.6360 50.8080 630.7200 ;
  END
 END lo_d[186]
 PIN lo_d[187]
  DIRECTION INPUT ;
  USE SIGNAL ;
  PORT
   LAYER M5 ;
   RECT 51.0240 630.6360 51.0480 630.7200 ;
  END
 END lo_d[187]
 PIN lo_d[188]
  DIRECTION INPUT ;
  USE SIGNAL ;
  PORT
   LAYER M5 ;
   RECT 51.2640 630.6360 51.2880 630.7200 ;
  END
 END lo_d[188]
 PIN lo_d[189]
  DIRECTION INPUT ;
  USE SIGNAL ;
  PORT
   LAYER M5 ;
   RECT 51.5040 630.6360 51.5280 630.7200 ;
  END
 END lo_d[189]
 PIN lo_d[190]
  DIRECTION INPUT ;
  USE SIGNAL ;
  PORT
   LAYER M5 ;
   RECT 51.7440 630.6360 51.7680 630.7200 ;
  END
 END lo_d[190]
 PIN lo_d[191]
  DIRECTION INPUT ;
  USE SIGNAL ;
  PORT
   LAYER M5 ;
   RECT 51.9840 630.6360 52.0080 630.7200 ;
  END
 END lo_d[191]
 PIN lo_d[192]
  DIRECTION INPUT ;
  USE SIGNAL ;
  PORT
   LAYER M5 ;
   RECT 52.2240 630.6360 52.2480 630.7200 ;
  END
 END lo_d[192]
 PIN lo_d[193]
  DIRECTION INPUT ;
  USE SIGNAL ;
  PORT
   LAYER M5 ;
   RECT 52.4640 630.6360 52.4880 630.7200 ;
  END
 END lo_d[193]
 PIN lo_d[194]
  DIRECTION INPUT ;
  USE SIGNAL ;
  PORT
   LAYER M5 ;
   RECT 52.7040 630.6360 52.7280 630.7200 ;
  END
 END lo_d[194]
 PIN lo_d[195]
  DIRECTION INPUT ;
  USE SIGNAL ;
  PORT
   LAYER M5 ;
   RECT 52.9440 630.6360 52.9680 630.7200 ;
  END
 END lo_d[195]
 PIN lo_d[196]
  DIRECTION INPUT ;
  USE SIGNAL ;
  PORT
   LAYER M5 ;
   RECT 53.1840 630.6360 53.2080 630.7200 ;
  END
 END lo_d[196]
 PIN lo_d[197]
  DIRECTION INPUT ;
  USE SIGNAL ;
  PORT
   LAYER M5 ;
   RECT 53.4240 630.6360 53.4480 630.7200 ;
  END
 END lo_d[197]
 PIN lo_d[198]
  DIRECTION INPUT ;
  USE SIGNAL ;
  PORT
   LAYER M5 ;
   RECT 53.6640 630.6360 53.6880 630.7200 ;
  END
 END lo_d[198]
 PIN lo_d[199]
  DIRECTION INPUT ;
  USE SIGNAL ;
  PORT
   LAYER M5 ;
   RECT 53.9040 630.6360 53.9280 630.7200 ;
  END
 END lo_d[199]
 PIN lo_d[200]
  DIRECTION INPUT ;
  USE SIGNAL ;
  PORT
   LAYER M5 ;
   RECT 54.1440 630.6360 54.1680 630.7200 ;
  END
 END lo_d[200]
 PIN lo_d[201]
  DIRECTION INPUT ;
  USE SIGNAL ;
  PORT
   LAYER M5 ;
   RECT 54.3840 630.6360 54.4080 630.7200 ;
  END
 END lo_d[201]
 PIN lo_d[202]
  DIRECTION INPUT ;
  USE SIGNAL ;
  PORT
   LAYER M5 ;
   RECT 54.6240 630.6360 54.6480 630.7200 ;
  END
 END lo_d[202]
 PIN lo_d[203]
  DIRECTION INPUT ;
  USE SIGNAL ;
  PORT
   LAYER M5 ;
   RECT 54.8640 630.6360 54.8880 630.7200 ;
  END
 END lo_d[203]
 PIN lo_d[204]
  DIRECTION INPUT ;
  USE SIGNAL ;
  PORT
   LAYER M5 ;
   RECT 55.1040 630.6360 55.1280 630.7200 ;
  END
 END lo_d[204]
 PIN lo_d[205]
  DIRECTION INPUT ;
  USE SIGNAL ;
  PORT
   LAYER M5 ;
   RECT 55.3440 630.6360 55.3680 630.7200 ;
  END
 END lo_d[205]
 PIN lo_d[206]
  DIRECTION INPUT ;
  USE SIGNAL ;
  PORT
   LAYER M5 ;
   RECT 55.5840 630.6360 55.6080 630.7200 ;
  END
 END lo_d[206]
 PIN lo_d[207]
  DIRECTION INPUT ;
  USE SIGNAL ;
  PORT
   LAYER M5 ;
   RECT 55.8240 630.6360 55.8480 630.7200 ;
  END
 END lo_d[207]
 PIN lo_d[208]
  DIRECTION INPUT ;
  USE SIGNAL ;
  PORT
   LAYER M5 ;
   RECT 56.0640 630.6360 56.0880 630.7200 ;
  END
 END lo_d[208]
 PIN lo_d[209]
  DIRECTION INPUT ;
  USE SIGNAL ;
  PORT
   LAYER M5 ;
   RECT 56.3040 630.6360 56.3280 630.7200 ;
  END
 END lo_d[209]
 PIN lo_d[210]
  DIRECTION INPUT ;
  USE SIGNAL ;
  PORT
   LAYER M5 ;
   RECT 56.5440 630.6360 56.5680 630.7200 ;
  END
 END lo_d[210]
 PIN lo_d[211]
  DIRECTION INPUT ;
  USE SIGNAL ;
  PORT
   LAYER M5 ;
   RECT 56.7840 630.6360 56.8080 630.7200 ;
  END
 END lo_d[211]
 PIN lo_d[212]
  DIRECTION INPUT ;
  USE SIGNAL ;
  PORT
   LAYER M5 ;
   RECT 57.0240 630.6360 57.0480 630.7200 ;
  END
 END lo_d[212]
 PIN lo_d[213]
  DIRECTION INPUT ;
  USE SIGNAL ;
  PORT
   LAYER M5 ;
   RECT 57.2640 630.6360 57.2880 630.7200 ;
  END
 END lo_d[213]
 PIN lo_d[214]
  DIRECTION INPUT ;
  USE SIGNAL ;
  PORT
   LAYER M5 ;
   RECT 57.5040 630.6360 57.5280 630.7200 ;
  END
 END lo_d[214]
 PIN lo_d[215]
  DIRECTION INPUT ;
  USE SIGNAL ;
  PORT
   LAYER M5 ;
   RECT 57.7440 630.6360 57.7680 630.7200 ;
  END
 END lo_d[215]
 PIN lo_d[216]
  DIRECTION INPUT ;
  USE SIGNAL ;
  PORT
   LAYER M5 ;
   RECT 57.9840 630.6360 58.0080 630.7200 ;
  END
 END lo_d[216]
 PIN lo_d[217]
  DIRECTION INPUT ;
  USE SIGNAL ;
  PORT
   LAYER M5 ;
   RECT 58.2240 630.6360 58.2480 630.7200 ;
  END
 END lo_d[217]
 PIN lo_d[218]
  DIRECTION INPUT ;
  USE SIGNAL ;
  PORT
   LAYER M5 ;
   RECT 58.4640 630.6360 58.4880 630.7200 ;
  END
 END lo_d[218]
 PIN lo_d[219]
  DIRECTION INPUT ;
  USE SIGNAL ;
  PORT
   LAYER M5 ;
   RECT 58.7040 630.6360 58.7280 630.7200 ;
  END
 END lo_d[219]
 PIN lo_d[220]
  DIRECTION INPUT ;
  USE SIGNAL ;
  PORT
   LAYER M5 ;
   RECT 58.9440 630.6360 58.9680 630.7200 ;
  END
 END lo_d[220]
 PIN lo_d[221]
  DIRECTION INPUT ;
  USE SIGNAL ;
  PORT
   LAYER M5 ;
   RECT 59.1840 630.6360 59.2080 630.7200 ;
  END
 END lo_d[221]
 PIN lo_d[222]
  DIRECTION INPUT ;
  USE SIGNAL ;
  PORT
   LAYER M5 ;
   RECT 59.4240 630.6360 59.4480 630.7200 ;
  END
 END lo_d[222]
 PIN lo_d[223]
  DIRECTION INPUT ;
  USE SIGNAL ;
  PORT
   LAYER M5 ;
   RECT 59.6640 630.6360 59.6880 630.7200 ;
  END
 END lo_d[223]
 PIN lo_d[224]
  DIRECTION INPUT ;
  USE SIGNAL ;
  PORT
   LAYER M5 ;
   RECT 59.9040 630.6360 59.9280 630.7200 ;
  END
 END lo_d[224]
 PIN lo_d[225]
  DIRECTION INPUT ;
  USE SIGNAL ;
  PORT
   LAYER M5 ;
   RECT 60.1440 630.6360 60.1680 630.7200 ;
  END
 END lo_d[225]
 PIN lo_d[226]
  DIRECTION INPUT ;
  USE SIGNAL ;
  PORT
   LAYER M5 ;
   RECT 60.3840 630.6360 60.4080 630.7200 ;
  END
 END lo_d[226]
 PIN lo_d[227]
  DIRECTION INPUT ;
  USE SIGNAL ;
  PORT
   LAYER M5 ;
   RECT 60.6240 630.6360 60.6480 630.7200 ;
  END
 END lo_d[227]
 PIN lo_d[228]
  DIRECTION INPUT ;
  USE SIGNAL ;
  PORT
   LAYER M5 ;
   RECT 60.8640 630.6360 60.8880 630.7200 ;
  END
 END lo_d[228]
 PIN lo_d[229]
  DIRECTION INPUT ;
  USE SIGNAL ;
  PORT
   LAYER M5 ;
   RECT 61.1040 630.6360 61.1280 630.7200 ;
  END
 END lo_d[229]
 PIN lo_d[230]
  DIRECTION INPUT ;
  USE SIGNAL ;
  PORT
   LAYER M5 ;
   RECT 61.3440 630.6360 61.3680 630.7200 ;
  END
 END lo_d[230]
 PIN lo_d[231]
  DIRECTION INPUT ;
  USE SIGNAL ;
  PORT
   LAYER M5 ;
   RECT 61.5840 630.6360 61.6080 630.7200 ;
  END
 END lo_d[231]
 PIN lo_d[232]
  DIRECTION INPUT ;
  USE SIGNAL ;
  PORT
   LAYER M5 ;
   RECT 61.8240 630.6360 61.8480 630.7200 ;
  END
 END lo_d[232]
 PIN lo_d[233]
  DIRECTION INPUT ;
  USE SIGNAL ;
  PORT
   LAYER M5 ;
   RECT 62.0640 630.6360 62.0880 630.7200 ;
  END
 END lo_d[233]
 PIN lo_d[234]
  DIRECTION INPUT ;
  USE SIGNAL ;
  PORT
   LAYER M5 ;
   RECT 62.3040 630.6360 62.3280 630.7200 ;
  END
 END lo_d[234]
 PIN lo_d[235]
  DIRECTION INPUT ;
  USE SIGNAL ;
  PORT
   LAYER M5 ;
   RECT 62.5440 630.6360 62.5680 630.7200 ;
  END
 END lo_d[235]
 PIN lo_d[236]
  DIRECTION INPUT ;
  USE SIGNAL ;
  PORT
   LAYER M5 ;
   RECT 62.7840 630.6360 62.8080 630.7200 ;
  END
 END lo_d[236]
 PIN lo_d[237]
  DIRECTION INPUT ;
  USE SIGNAL ;
  PORT
   LAYER M5 ;
   RECT 63.0240 630.6360 63.0480 630.7200 ;
  END
 END lo_d[237]
 PIN lo_d[238]
  DIRECTION INPUT ;
  USE SIGNAL ;
  PORT
   LAYER M5 ;
   RECT 63.2640 630.6360 63.2880 630.7200 ;
  END
 END lo_d[238]
 PIN lo_d[239]
  DIRECTION INPUT ;
  USE SIGNAL ;
  PORT
   LAYER M5 ;
   RECT 63.5040 630.6360 63.5280 630.7200 ;
  END
 END lo_d[239]
 PIN lo_d[240]
  DIRECTION INPUT ;
  USE SIGNAL ;
  PORT
   LAYER M5 ;
   RECT 63.7440 630.6360 63.7680 630.7200 ;
  END
 END lo_d[240]
 PIN lo_d[241]
  DIRECTION INPUT ;
  USE SIGNAL ;
  PORT
   LAYER M5 ;
   RECT 63.9840 630.6360 64.0080 630.7200 ;
  END
 END lo_d[241]
 PIN lo_d[242]
  DIRECTION INPUT ;
  USE SIGNAL ;
  PORT
   LAYER M5 ;
   RECT 64.2240 630.6360 64.2480 630.7200 ;
  END
 END lo_d[242]
 PIN lo_d[243]
  DIRECTION INPUT ;
  USE SIGNAL ;
  PORT
   LAYER M5 ;
   RECT 64.4640 630.6360 64.4880 630.7200 ;
  END
 END lo_d[243]
 PIN lo_d[244]
  DIRECTION INPUT ;
  USE SIGNAL ;
  PORT
   LAYER M5 ;
   RECT 64.7040 630.6360 64.7280 630.7200 ;
  END
 END lo_d[244]
 PIN lo_d[245]
  DIRECTION INPUT ;
  USE SIGNAL ;
  PORT
   LAYER M5 ;
   RECT 64.9440 630.6360 64.9680 630.7200 ;
  END
 END lo_d[245]
 PIN lo_d[246]
  DIRECTION INPUT ;
  USE SIGNAL ;
  PORT
   LAYER M5 ;
   RECT 65.1840 630.6360 65.2080 630.7200 ;
  END
 END lo_d[246]
 PIN lo_d[247]
  DIRECTION INPUT ;
  USE SIGNAL ;
  PORT
   LAYER M5 ;
   RECT 65.4240 630.6360 65.4480 630.7200 ;
  END
 END lo_d[247]
 PIN lo_d[248]
  DIRECTION INPUT ;
  USE SIGNAL ;
  PORT
   LAYER M5 ;
   RECT 65.6640 630.6360 65.6880 630.7200 ;
  END
 END lo_d[248]
 PIN lo_d[249]
  DIRECTION INPUT ;
  USE SIGNAL ;
  PORT
   LAYER M5 ;
   RECT 65.9040 630.6360 65.9280 630.7200 ;
  END
 END lo_d[249]
 PIN lo_d[250]
  DIRECTION INPUT ;
  USE SIGNAL ;
  PORT
   LAYER M5 ;
   RECT 66.1440 630.6360 66.1680 630.7200 ;
  END
 END lo_d[250]
 PIN lo_d[251]
  DIRECTION INPUT ;
  USE SIGNAL ;
  PORT
   LAYER M5 ;
   RECT 66.3840 630.6360 66.4080 630.7200 ;
  END
 END lo_d[251]
 PIN lo_d[252]
  DIRECTION INPUT ;
  USE SIGNAL ;
  PORT
   LAYER M5 ;
   RECT 66.6240 630.6360 66.6480 630.7200 ;
  END
 END lo_d[252]
 PIN lo_d[253]
  DIRECTION INPUT ;
  USE SIGNAL ;
  PORT
   LAYER M5 ;
   RECT 66.8640 630.6360 66.8880 630.7200 ;
  END
 END lo_d[253]
 PIN lo_d[254]
  DIRECTION INPUT ;
  USE SIGNAL ;
  PORT
   LAYER M5 ;
   RECT 67.1040 630.6360 67.1280 630.7200 ;
  END
 END lo_d[254]
 PIN lo_d[255]
  DIRECTION INPUT ;
  USE SIGNAL ;
  PORT
   LAYER M5 ;
   RECT 67.3440 630.6360 67.3680 630.7200 ;
  END
 END lo_d[255]
 PIN lo_d[256]
  DIRECTION INPUT ;
  USE SIGNAL ;
  PORT
   LAYER M5 ;
   RECT 67.5840 630.6360 67.6080 630.7200 ;
  END
 END lo_d[256]
 PIN lo_d[257]
  DIRECTION INPUT ;
  USE SIGNAL ;
  PORT
   LAYER M5 ;
   RECT 67.8240 630.6360 67.8480 630.7200 ;
  END
 END lo_d[257]
 PIN lo_d[258]
  DIRECTION INPUT ;
  USE SIGNAL ;
  PORT
   LAYER M5 ;
   RECT 68.0640 630.6360 68.0880 630.7200 ;
  END
 END lo_d[258]
 PIN lo_d[259]
  DIRECTION INPUT ;
  USE SIGNAL ;
  PORT
   LAYER M5 ;
   RECT 68.3040 630.6360 68.3280 630.7200 ;
  END
 END lo_d[259]
 PIN lo_d[260]
  DIRECTION INPUT ;
  USE SIGNAL ;
  PORT
   LAYER M5 ;
   RECT 68.5440 630.6360 68.5680 630.7200 ;
  END
 END lo_d[260]
 PIN lo_d[261]
  DIRECTION INPUT ;
  USE SIGNAL ;
  PORT
   LAYER M5 ;
   RECT 68.7840 630.6360 68.8080 630.7200 ;
  END
 END lo_d[261]
 PIN lo_d[262]
  DIRECTION INPUT ;
  USE SIGNAL ;
  PORT
   LAYER M5 ;
   RECT 69.0240 630.6360 69.0480 630.7200 ;
  END
 END lo_d[262]
 PIN lo_d[263]
  DIRECTION INPUT ;
  USE SIGNAL ;
  PORT
   LAYER M5 ;
   RECT 69.2640 630.6360 69.2880 630.7200 ;
  END
 END lo_d[263]
 PIN lo_d[264]
  DIRECTION INPUT ;
  USE SIGNAL ;
  PORT
   LAYER M5 ;
   RECT 69.5040 630.6360 69.5280 630.7200 ;
  END
 END lo_d[264]
 PIN lo_d[265]
  DIRECTION INPUT ;
  USE SIGNAL ;
  PORT
   LAYER M5 ;
   RECT 69.7440 630.6360 69.7680 630.7200 ;
  END
 END lo_d[265]
 PIN lo_d[266]
  DIRECTION INPUT ;
  USE SIGNAL ;
  PORT
   LAYER M5 ;
   RECT 69.9840 630.6360 70.0080 630.7200 ;
  END
 END lo_d[266]
 PIN lo_d[267]
  DIRECTION INPUT ;
  USE SIGNAL ;
  PORT
   LAYER M5 ;
   RECT 70.2240 630.6360 70.2480 630.7200 ;
  END
 END lo_d[267]
 PIN lo_d[268]
  DIRECTION INPUT ;
  USE SIGNAL ;
  PORT
   LAYER M5 ;
   RECT 70.4640 630.6360 70.4880 630.7200 ;
  END
 END lo_d[268]
 PIN lo_d[269]
  DIRECTION INPUT ;
  USE SIGNAL ;
  PORT
   LAYER M5 ;
   RECT 70.7040 630.6360 70.7280 630.7200 ;
  END
 END lo_d[269]
 PIN lo_d[270]
  DIRECTION INPUT ;
  USE SIGNAL ;
  PORT
   LAYER M5 ;
   RECT 70.9440 630.6360 70.9680 630.7200 ;
  END
 END lo_d[270]
 PIN lo_d[271]
  DIRECTION INPUT ;
  USE SIGNAL ;
  PORT
   LAYER M5 ;
   RECT 71.1840 630.6360 71.2080 630.7200 ;
  END
 END lo_d[271]
 PIN lo_d[272]
  DIRECTION INPUT ;
  USE SIGNAL ;
  PORT
   LAYER M5 ;
   RECT 71.4240 630.6360 71.4480 630.7200 ;
  END
 END lo_d[272]
 PIN lo_d[273]
  DIRECTION INPUT ;
  USE SIGNAL ;
  PORT
   LAYER M5 ;
   RECT 71.6640 630.6360 71.6880 630.7200 ;
  END
 END lo_d[273]
 PIN lo_d[274]
  DIRECTION INPUT ;
  USE SIGNAL ;
  PORT
   LAYER M5 ;
   RECT 71.9040 630.6360 71.9280 630.7200 ;
  END
 END lo_d[274]
 PIN lo_d[275]
  DIRECTION INPUT ;
  USE SIGNAL ;
  PORT
   LAYER M5 ;
   RECT 72.1440 630.6360 72.1680 630.7200 ;
  END
 END lo_d[275]
 PIN lo_d[276]
  DIRECTION INPUT ;
  USE SIGNAL ;
  PORT
   LAYER M5 ;
   RECT 72.3840 630.6360 72.4080 630.7200 ;
  END
 END lo_d[276]
 PIN lo_d[277]
  DIRECTION INPUT ;
  USE SIGNAL ;
  PORT
   LAYER M5 ;
   RECT 72.6240 630.6360 72.6480 630.7200 ;
  END
 END lo_d[277]
 PIN lo_d[278]
  DIRECTION INPUT ;
  USE SIGNAL ;
  PORT
   LAYER M5 ;
   RECT 72.8640 630.6360 72.8880 630.7200 ;
  END
 END lo_d[278]
 PIN lo_d[279]
  DIRECTION INPUT ;
  USE SIGNAL ;
  PORT
   LAYER M5 ;
   RECT 73.1040 630.6360 73.1280 630.7200 ;
  END
 END lo_d[279]
 PIN lo_d[280]
  DIRECTION INPUT ;
  USE SIGNAL ;
  PORT
   LAYER M5 ;
   RECT 73.3440 630.6360 73.3680 630.7200 ;
  END
 END lo_d[280]
 PIN lo_d[281]
  DIRECTION INPUT ;
  USE SIGNAL ;
  PORT
   LAYER M5 ;
   RECT 73.5840 630.6360 73.6080 630.7200 ;
  END
 END lo_d[281]
 PIN lo_d[282]
  DIRECTION INPUT ;
  USE SIGNAL ;
  PORT
   LAYER M5 ;
   RECT 73.8240 630.6360 73.8480 630.7200 ;
  END
 END lo_d[282]
 PIN lo_d[283]
  DIRECTION INPUT ;
  USE SIGNAL ;
  PORT
   LAYER M5 ;
   RECT 74.0640 630.6360 74.0880 630.7200 ;
  END
 END lo_d[283]
 PIN lo_d[284]
  DIRECTION INPUT ;
  USE SIGNAL ;
  PORT
   LAYER M5 ;
   RECT 74.3040 630.6360 74.3280 630.7200 ;
  END
 END lo_d[284]
 PIN lo_d[285]
  DIRECTION INPUT ;
  USE SIGNAL ;
  PORT
   LAYER M5 ;
   RECT 74.5440 630.6360 74.5680 630.7200 ;
  END
 END lo_d[285]
 PIN lo_d[286]
  DIRECTION INPUT ;
  USE SIGNAL ;
  PORT
   LAYER M5 ;
   RECT 74.7840 630.6360 74.8080 630.7200 ;
  END
 END lo_d[286]
 PIN lo_d[287]
  DIRECTION INPUT ;
  USE SIGNAL ;
  PORT
   LAYER M5 ;
   RECT 75.0240 630.6360 75.0480 630.7200 ;
  END
 END lo_d[287]
 PIN lo_d[288]
  DIRECTION INPUT ;
  USE SIGNAL ;
  PORT
   LAYER M5 ;
   RECT 75.2640 630.6360 75.2880 630.7200 ;
  END
 END lo_d[288]
 PIN lo_d[289]
  DIRECTION INPUT ;
  USE SIGNAL ;
  PORT
   LAYER M5 ;
   RECT 75.5040 630.6360 75.5280 630.7200 ;
  END
 END lo_d[289]
 PIN lo_d[290]
  DIRECTION INPUT ;
  USE SIGNAL ;
  PORT
   LAYER M5 ;
   RECT 75.7440 630.6360 75.7680 630.7200 ;
  END
 END lo_d[290]
 PIN lo_d[291]
  DIRECTION INPUT ;
  USE SIGNAL ;
  PORT
   LAYER M5 ;
   RECT 75.9840 630.6360 76.0080 630.7200 ;
  END
 END lo_d[291]
 PIN lo_d[292]
  DIRECTION INPUT ;
  USE SIGNAL ;
  PORT
   LAYER M5 ;
   RECT 76.2240 630.6360 76.2480 630.7200 ;
  END
 END lo_d[292]
 PIN lo_d[293]
  DIRECTION INPUT ;
  USE SIGNAL ;
  PORT
   LAYER M5 ;
   RECT 76.4640 630.6360 76.4880 630.7200 ;
  END
 END lo_d[293]
 PIN lo_d[294]
  DIRECTION INPUT ;
  USE SIGNAL ;
  PORT
   LAYER M5 ;
   RECT 76.7040 630.6360 76.7280 630.7200 ;
  END
 END lo_d[294]
 PIN lo_d[295]
  DIRECTION INPUT ;
  USE SIGNAL ;
  PORT
   LAYER M5 ;
   RECT 76.9440 630.6360 76.9680 630.7200 ;
  END
 END lo_d[295]
 PIN lo_d[296]
  DIRECTION INPUT ;
  USE SIGNAL ;
  PORT
   LAYER M5 ;
   RECT 77.1840 630.6360 77.2080 630.7200 ;
  END
 END lo_d[296]
 PIN lo_d[297]
  DIRECTION INPUT ;
  USE SIGNAL ;
  PORT
   LAYER M5 ;
   RECT 77.4240 630.6360 77.4480 630.7200 ;
  END
 END lo_d[297]
 PIN lo_d[298]
  DIRECTION INPUT ;
  USE SIGNAL ;
  PORT
   LAYER M5 ;
   RECT 77.6640 630.6360 77.6880 630.7200 ;
  END
 END lo_d[298]
 PIN lo_d[299]
  DIRECTION INPUT ;
  USE SIGNAL ;
  PORT
   LAYER M5 ;
   RECT 77.9040 630.6360 77.9280 630.7200 ;
  END
 END lo_d[299]
 PIN lo_d[300]
  DIRECTION INPUT ;
  USE SIGNAL ;
  PORT
   LAYER M5 ;
   RECT 78.1440 630.6360 78.1680 630.7200 ;
  END
 END lo_d[300]
 PIN lo_d[301]
  DIRECTION INPUT ;
  USE SIGNAL ;
  PORT
   LAYER M5 ;
   RECT 78.3840 630.6360 78.4080 630.7200 ;
  END
 END lo_d[301]
 PIN lo_d[302]
  DIRECTION INPUT ;
  USE SIGNAL ;
  PORT
   LAYER M5 ;
   RECT 78.6240 630.6360 78.6480 630.7200 ;
  END
 END lo_d[302]
 PIN lo_d[303]
  DIRECTION INPUT ;
  USE SIGNAL ;
  PORT
   LAYER M5 ;
   RECT 78.8640 630.6360 78.8880 630.7200 ;
  END
 END lo_d[303]
 PIN lo_d[304]
  DIRECTION INPUT ;
  USE SIGNAL ;
  PORT
   LAYER M5 ;
   RECT 79.1040 630.6360 79.1280 630.7200 ;
  END
 END lo_d[304]
 PIN lo_d[305]
  DIRECTION INPUT ;
  USE SIGNAL ;
  PORT
   LAYER M5 ;
   RECT 79.3440 630.6360 79.3680 630.7200 ;
  END
 END lo_d[305]
 PIN lo_d[306]
  DIRECTION INPUT ;
  USE SIGNAL ;
  PORT
   LAYER M5 ;
   RECT 79.5840 630.6360 79.6080 630.7200 ;
  END
 END lo_d[306]
 PIN lo_d[307]
  DIRECTION INPUT ;
  USE SIGNAL ;
  PORT
   LAYER M5 ;
   RECT 79.8240 630.6360 79.8480 630.7200 ;
  END
 END lo_d[307]
 PIN lo_d[308]
  DIRECTION INPUT ;
  USE SIGNAL ;
  PORT
   LAYER M5 ;
   RECT 80.0640 630.6360 80.0880 630.7200 ;
  END
 END lo_d[308]
 PIN lo_d[309]
  DIRECTION INPUT ;
  USE SIGNAL ;
  PORT
   LAYER M5 ;
   RECT 80.3040 630.6360 80.3280 630.7200 ;
  END
 END lo_d[309]
 PIN lo_d[310]
  DIRECTION INPUT ;
  USE SIGNAL ;
  PORT
   LAYER M5 ;
   RECT 80.5440 630.6360 80.5680 630.7200 ;
  END
 END lo_d[310]
 PIN lo_d[311]
  DIRECTION INPUT ;
  USE SIGNAL ;
  PORT
   LAYER M5 ;
   RECT 80.7840 630.6360 80.8080 630.7200 ;
  END
 END lo_d[311]
 PIN lo_d[312]
  DIRECTION INPUT ;
  USE SIGNAL ;
  PORT
   LAYER M5 ;
   RECT 81.0240 630.6360 81.0480 630.7200 ;
  END
 END lo_d[312]
 PIN lo_d[313]
  DIRECTION INPUT ;
  USE SIGNAL ;
  PORT
   LAYER M5 ;
   RECT 81.2640 630.6360 81.2880 630.7200 ;
  END
 END lo_d[313]
 PIN lo_d[314]
  DIRECTION INPUT ;
  USE SIGNAL ;
  PORT
   LAYER M5 ;
   RECT 81.5040 630.6360 81.5280 630.7200 ;
  END
 END lo_d[314]
 PIN lo_d[315]
  DIRECTION INPUT ;
  USE SIGNAL ;
  PORT
   LAYER M5 ;
   RECT 81.7440 630.6360 81.7680 630.7200 ;
  END
 END lo_d[315]
 PIN lo_d[316]
  DIRECTION INPUT ;
  USE SIGNAL ;
  PORT
   LAYER M5 ;
   RECT 81.9840 630.6360 82.0080 630.7200 ;
  END
 END lo_d[316]
 PIN lo_d[317]
  DIRECTION INPUT ;
  USE SIGNAL ;
  PORT
   LAYER M5 ;
   RECT 82.2240 630.6360 82.2480 630.7200 ;
  END
 END lo_d[317]
 PIN lo_d[318]
  DIRECTION INPUT ;
  USE SIGNAL ;
  PORT
   LAYER M5 ;
   RECT 82.4640 630.6360 82.4880 630.7200 ;
  END
 END lo_d[318]
 PIN lo_d[319]
  DIRECTION INPUT ;
  USE SIGNAL ;
  PORT
   LAYER M5 ;
   RECT 82.7040 630.6360 82.7280 630.7200 ;
  END
 END lo_d[319]
 PIN lo_d[320]
  DIRECTION INPUT ;
  USE SIGNAL ;
  PORT
   LAYER M5 ;
   RECT 82.9440 630.6360 82.9680 630.7200 ;
  END
 END lo_d[320]
 PIN lo_d[321]
  DIRECTION INPUT ;
  USE SIGNAL ;
  PORT
   LAYER M5 ;
   RECT 83.1840 630.6360 83.2080 630.7200 ;
  END
 END lo_d[321]
 PIN lo_d[322]
  DIRECTION INPUT ;
  USE SIGNAL ;
  PORT
   LAYER M5 ;
   RECT 83.4240 630.6360 83.4480 630.7200 ;
  END
 END lo_d[322]
 PIN lo_d[323]
  DIRECTION INPUT ;
  USE SIGNAL ;
  PORT
   LAYER M5 ;
   RECT 83.6640 630.6360 83.6880 630.7200 ;
  END
 END lo_d[323]
 PIN lo_d[324]
  DIRECTION INPUT ;
  USE SIGNAL ;
  PORT
   LAYER M5 ;
   RECT 83.9040 630.6360 83.9280 630.7200 ;
  END
 END lo_d[324]
 PIN lo_d[325]
  DIRECTION INPUT ;
  USE SIGNAL ;
  PORT
   LAYER M5 ;
   RECT 84.1440 630.6360 84.1680 630.7200 ;
  END
 END lo_d[325]
 PIN lo_d[326]
  DIRECTION INPUT ;
  USE SIGNAL ;
  PORT
   LAYER M5 ;
   RECT 84.3840 630.6360 84.4080 630.7200 ;
  END
 END lo_d[326]
 PIN lo_d[327]
  DIRECTION INPUT ;
  USE SIGNAL ;
  PORT
   LAYER M5 ;
   RECT 84.6240 630.6360 84.6480 630.7200 ;
  END
 END lo_d[327]
 PIN lo_d[328]
  DIRECTION INPUT ;
  USE SIGNAL ;
  PORT
   LAYER M5 ;
   RECT 84.8640 630.6360 84.8880 630.7200 ;
  END
 END lo_d[328]
 PIN lo_d[329]
  DIRECTION INPUT ;
  USE SIGNAL ;
  PORT
   LAYER M5 ;
   RECT 85.1040 630.6360 85.1280 630.7200 ;
  END
 END lo_d[329]
 PIN lo_d[330]
  DIRECTION INPUT ;
  USE SIGNAL ;
  PORT
   LAYER M5 ;
   RECT 85.3440 630.6360 85.3680 630.7200 ;
  END
 END lo_d[330]
 PIN lo_d[331]
  DIRECTION INPUT ;
  USE SIGNAL ;
  PORT
   LAYER M5 ;
   RECT 85.5840 630.6360 85.6080 630.7200 ;
  END
 END lo_d[331]
 PIN lo_d[332]
  DIRECTION INPUT ;
  USE SIGNAL ;
  PORT
   LAYER M5 ;
   RECT 85.8240 630.6360 85.8480 630.7200 ;
  END
 END lo_d[332]
 PIN lo_d[333]
  DIRECTION INPUT ;
  USE SIGNAL ;
  PORT
   LAYER M5 ;
   RECT 86.0640 630.6360 86.0880 630.7200 ;
  END
 END lo_d[333]
 PIN lo_d[334]
  DIRECTION INPUT ;
  USE SIGNAL ;
  PORT
   LAYER M5 ;
   RECT 86.3040 630.6360 86.3280 630.7200 ;
  END
 END lo_d[334]
 PIN lo_d[335]
  DIRECTION INPUT ;
  USE SIGNAL ;
  PORT
   LAYER M5 ;
   RECT 86.5440 630.6360 86.5680 630.7200 ;
  END
 END lo_d[335]
 PIN lo_d[336]
  DIRECTION INPUT ;
  USE SIGNAL ;
  PORT
   LAYER M5 ;
   RECT 86.7840 630.6360 86.8080 630.7200 ;
  END
 END lo_d[336]
 PIN lo_d[337]
  DIRECTION INPUT ;
  USE SIGNAL ;
  PORT
   LAYER M5 ;
   RECT 87.0240 630.6360 87.0480 630.7200 ;
  END
 END lo_d[337]
 PIN lo_d[338]
  DIRECTION INPUT ;
  USE SIGNAL ;
  PORT
   LAYER M5 ;
   RECT 87.2640 630.6360 87.2880 630.7200 ;
  END
 END lo_d[338]
 PIN lo_d[339]
  DIRECTION INPUT ;
  USE SIGNAL ;
  PORT
   LAYER M5 ;
   RECT 87.5040 630.6360 87.5280 630.7200 ;
  END
 END lo_d[339]
 PIN lo_d[340]
  DIRECTION INPUT ;
  USE SIGNAL ;
  PORT
   LAYER M5 ;
   RECT 87.7440 630.6360 87.7680 630.7200 ;
  END
 END lo_d[340]
 PIN lo_d[341]
  DIRECTION INPUT ;
  USE SIGNAL ;
  PORT
   LAYER M5 ;
   RECT 87.9840 630.6360 88.0080 630.7200 ;
  END
 END lo_d[341]
 PIN lo_d[342]
  DIRECTION INPUT ;
  USE SIGNAL ;
  PORT
   LAYER M5 ;
   RECT 88.2240 630.6360 88.2480 630.7200 ;
  END
 END lo_d[342]
 PIN lo_d[343]
  DIRECTION INPUT ;
  USE SIGNAL ;
  PORT
   LAYER M5 ;
   RECT 88.4640 630.6360 88.4880 630.7200 ;
  END
 END lo_d[343]
 PIN lo_d[344]
  DIRECTION INPUT ;
  USE SIGNAL ;
  PORT
   LAYER M5 ;
   RECT 88.7040 630.6360 88.7280 630.7200 ;
  END
 END lo_d[344]
 PIN lo_d[345]
  DIRECTION INPUT ;
  USE SIGNAL ;
  PORT
   LAYER M5 ;
   RECT 88.9440 630.6360 88.9680 630.7200 ;
  END
 END lo_d[345]
 PIN lo_d[346]
  DIRECTION INPUT ;
  USE SIGNAL ;
  PORT
   LAYER M5 ;
   RECT 89.1840 630.6360 89.2080 630.7200 ;
  END
 END lo_d[346]
 PIN lo_d[347]
  DIRECTION INPUT ;
  USE SIGNAL ;
  PORT
   LAYER M5 ;
   RECT 89.4240 630.6360 89.4480 630.7200 ;
  END
 END lo_d[347]
 PIN lo_d[348]
  DIRECTION INPUT ;
  USE SIGNAL ;
  PORT
   LAYER M5 ;
   RECT 89.6640 630.6360 89.6880 630.7200 ;
  END
 END lo_d[348]
 PIN lo_d[349]
  DIRECTION INPUT ;
  USE SIGNAL ;
  PORT
   LAYER M5 ;
   RECT 89.9040 630.6360 89.9280 630.7200 ;
  END
 END lo_d[349]
 PIN lo_d[350]
  DIRECTION INPUT ;
  USE SIGNAL ;
  PORT
   LAYER M5 ;
   RECT 90.1440 630.6360 90.1680 630.7200 ;
  END
 END lo_d[350]
 PIN lo_d[351]
  DIRECTION INPUT ;
  USE SIGNAL ;
  PORT
   LAYER M5 ;
   RECT 90.3840 630.6360 90.4080 630.7200 ;
  END
 END lo_d[351]
 PIN lo_d[352]
  DIRECTION INPUT ;
  USE SIGNAL ;
  PORT
   LAYER M5 ;
   RECT 90.6240 630.6360 90.6480 630.7200 ;
  END
 END lo_d[352]
 PIN lo_d[353]
  DIRECTION INPUT ;
  USE SIGNAL ;
  PORT
   LAYER M5 ;
   RECT 90.8640 630.6360 90.8880 630.7200 ;
  END
 END lo_d[353]
 PIN lo_d[354]
  DIRECTION INPUT ;
  USE SIGNAL ;
  PORT
   LAYER M5 ;
   RECT 91.1040 630.6360 91.1280 630.7200 ;
  END
 END lo_d[354]
 PIN lo_d[355]
  DIRECTION INPUT ;
  USE SIGNAL ;
  PORT
   LAYER M5 ;
   RECT 91.3440 630.6360 91.3680 630.7200 ;
  END
 END lo_d[355]
 PIN lo_d[356]
  DIRECTION INPUT ;
  USE SIGNAL ;
  PORT
   LAYER M5 ;
   RECT 91.5840 630.6360 91.6080 630.7200 ;
  END
 END lo_d[356]
 PIN lo_d[357]
  DIRECTION INPUT ;
  USE SIGNAL ;
  PORT
   LAYER M5 ;
   RECT 91.8240 630.6360 91.8480 630.7200 ;
  END
 END lo_d[357]
 PIN lo_d[358]
  DIRECTION INPUT ;
  USE SIGNAL ;
  PORT
   LAYER M5 ;
   RECT 92.0640 630.6360 92.0880 630.7200 ;
  END
 END lo_d[358]
 PIN lo_d[359]
  DIRECTION INPUT ;
  USE SIGNAL ;
  PORT
   LAYER M5 ;
   RECT 92.3040 630.6360 92.3280 630.7200 ;
  END
 END lo_d[359]
 PIN lo_d[360]
  DIRECTION INPUT ;
  USE SIGNAL ;
  PORT
   LAYER M5 ;
   RECT 92.5440 630.6360 92.5680 630.7200 ;
  END
 END lo_d[360]
 PIN lo_d[361]
  DIRECTION INPUT ;
  USE SIGNAL ;
  PORT
   LAYER M5 ;
   RECT 92.7840 630.6360 92.8080 630.7200 ;
  END
 END lo_d[361]
 PIN lo_d[362]
  DIRECTION INPUT ;
  USE SIGNAL ;
  PORT
   LAYER M5 ;
   RECT 93.0240 630.6360 93.0480 630.7200 ;
  END
 END lo_d[362]
 PIN lo_d[363]
  DIRECTION INPUT ;
  USE SIGNAL ;
  PORT
   LAYER M5 ;
   RECT 93.2640 630.6360 93.2880 630.7200 ;
  END
 END lo_d[363]
 PIN lo_d[364]
  DIRECTION INPUT ;
  USE SIGNAL ;
  PORT
   LAYER M5 ;
   RECT 93.5040 630.6360 93.5280 630.7200 ;
  END
 END lo_d[364]
 PIN lo_d[365]
  DIRECTION INPUT ;
  USE SIGNAL ;
  PORT
   LAYER M5 ;
   RECT 93.7440 630.6360 93.7680 630.7200 ;
  END
 END lo_d[365]
 PIN lo_d[366]
  DIRECTION INPUT ;
  USE SIGNAL ;
  PORT
   LAYER M5 ;
   RECT 93.9840 630.6360 94.0080 630.7200 ;
  END
 END lo_d[366]
 PIN lo_d[367]
  DIRECTION INPUT ;
  USE SIGNAL ;
  PORT
   LAYER M5 ;
   RECT 94.2240 630.6360 94.2480 630.7200 ;
  END
 END lo_d[367]
 PIN lo_d[368]
  DIRECTION INPUT ;
  USE SIGNAL ;
  PORT
   LAYER M5 ;
   RECT 94.4640 630.6360 94.4880 630.7200 ;
  END
 END lo_d[368]
 PIN lo_d[369]
  DIRECTION INPUT ;
  USE SIGNAL ;
  PORT
   LAYER M5 ;
   RECT 94.7040 630.6360 94.7280 630.7200 ;
  END
 END lo_d[369]
 PIN lo_d[370]
  DIRECTION INPUT ;
  USE SIGNAL ;
  PORT
   LAYER M5 ;
   RECT 94.9440 630.6360 94.9680 630.7200 ;
  END
 END lo_d[370]
 PIN lo_d[371]
  DIRECTION INPUT ;
  USE SIGNAL ;
  PORT
   LAYER M5 ;
   RECT 95.1840 630.6360 95.2080 630.7200 ;
  END
 END lo_d[371]
 PIN lo_d[372]
  DIRECTION INPUT ;
  USE SIGNAL ;
  PORT
   LAYER M5 ;
   RECT 95.4240 630.6360 95.4480 630.7200 ;
  END
 END lo_d[372]
 PIN lo_d[373]
  DIRECTION INPUT ;
  USE SIGNAL ;
  PORT
   LAYER M5 ;
   RECT 95.6640 630.6360 95.6880 630.7200 ;
  END
 END lo_d[373]
 PIN lo_d[374]
  DIRECTION INPUT ;
  USE SIGNAL ;
  PORT
   LAYER M5 ;
   RECT 95.9040 630.6360 95.9280 630.7200 ;
  END
 END lo_d[374]
 PIN lo_d[375]
  DIRECTION INPUT ;
  USE SIGNAL ;
  PORT
   LAYER M5 ;
   RECT 96.1440 630.6360 96.1680 630.7200 ;
  END
 END lo_d[375]
 PIN lo_d[376]
  DIRECTION INPUT ;
  USE SIGNAL ;
  PORT
   LAYER M5 ;
   RECT 96.3840 630.6360 96.4080 630.7200 ;
  END
 END lo_d[376]
 PIN lo_d[377]
  DIRECTION INPUT ;
  USE SIGNAL ;
  PORT
   LAYER M5 ;
   RECT 96.6240 630.6360 96.6480 630.7200 ;
  END
 END lo_d[377]
 PIN lo_d[378]
  DIRECTION INPUT ;
  USE SIGNAL ;
  PORT
   LAYER M5 ;
   RECT 96.8640 630.6360 96.8880 630.7200 ;
  END
 END lo_d[378]
 PIN lo_d[379]
  DIRECTION INPUT ;
  USE SIGNAL ;
  PORT
   LAYER M5 ;
   RECT 97.1040 630.6360 97.1280 630.7200 ;
  END
 END lo_d[379]
 PIN lo_d[380]
  DIRECTION INPUT ;
  USE SIGNAL ;
  PORT
   LAYER M5 ;
   RECT 97.3440 630.6360 97.3680 630.7200 ;
  END
 END lo_d[380]
 PIN lo_d[381]
  DIRECTION INPUT ;
  USE SIGNAL ;
  PORT
   LAYER M5 ;
   RECT 97.5840 630.6360 97.6080 630.7200 ;
  END
 END lo_d[381]
 PIN lo_d[382]
  DIRECTION INPUT ;
  USE SIGNAL ;
  PORT
   LAYER M5 ;
   RECT 97.8240 630.6360 97.8480 630.7200 ;
  END
 END lo_d[382]
 PIN lo_d[383]
  DIRECTION INPUT ;
  USE SIGNAL ;
  PORT
   LAYER M5 ;
   RECT 98.0640 630.6360 98.0880 630.7200 ;
  END
 END lo_d[383]
 PIN lo_d[384]
  DIRECTION INPUT ;
  USE SIGNAL ;
  PORT
   LAYER M5 ;
   RECT 98.3040 630.6360 98.3280 630.7200 ;
  END
 END lo_d[384]
 PIN lo_d[385]
  DIRECTION INPUT ;
  USE SIGNAL ;
  PORT
   LAYER M5 ;
   RECT 98.5440 630.6360 98.5680 630.7200 ;
  END
 END lo_d[385]
 PIN lo_d[386]
  DIRECTION INPUT ;
  USE SIGNAL ;
  PORT
   LAYER M5 ;
   RECT 98.7840 630.6360 98.8080 630.7200 ;
  END
 END lo_d[386]
 PIN lo_d[387]
  DIRECTION INPUT ;
  USE SIGNAL ;
  PORT
   LAYER M5 ;
   RECT 99.0240 630.6360 99.0480 630.7200 ;
  END
 END lo_d[387]
 PIN lo_d[388]
  DIRECTION INPUT ;
  USE SIGNAL ;
  PORT
   LAYER M5 ;
   RECT 99.2640 630.6360 99.2880 630.7200 ;
  END
 END lo_d[388]
 PIN lo_d[389]
  DIRECTION INPUT ;
  USE SIGNAL ;
  PORT
   LAYER M5 ;
   RECT 99.5040 630.6360 99.5280 630.7200 ;
  END
 END lo_d[389]
 PIN lo_d[390]
  DIRECTION INPUT ;
  USE SIGNAL ;
  PORT
   LAYER M5 ;
   RECT 99.7440 630.6360 99.7680 630.7200 ;
  END
 END lo_d[390]
 PIN lo_d[391]
  DIRECTION INPUT ;
  USE SIGNAL ;
  PORT
   LAYER M5 ;
   RECT 99.9840 630.6360 100.0080 630.7200 ;
  END
 END lo_d[391]
 PIN lo_d[392]
  DIRECTION INPUT ;
  USE SIGNAL ;
  PORT
   LAYER M5 ;
   RECT 100.2240 630.6360 100.2480 630.7200 ;
  END
 END lo_d[392]
 PIN lo_d[393]
  DIRECTION INPUT ;
  USE SIGNAL ;
  PORT
   LAYER M5 ;
   RECT 100.4640 630.6360 100.4880 630.7200 ;
  END
 END lo_d[393]
 PIN lo_d[394]
  DIRECTION INPUT ;
  USE SIGNAL ;
  PORT
   LAYER M5 ;
   RECT 100.7040 630.6360 100.7280 630.7200 ;
  END
 END lo_d[394]
 PIN lo_d[395]
  DIRECTION INPUT ;
  USE SIGNAL ;
  PORT
   LAYER M5 ;
   RECT 100.9440 630.6360 100.9680 630.7200 ;
  END
 END lo_d[395]
 PIN lo_d[396]
  DIRECTION INPUT ;
  USE SIGNAL ;
  PORT
   LAYER M5 ;
   RECT 101.1840 630.6360 101.2080 630.7200 ;
  END
 END lo_d[396]
 PIN lo_d[397]
  DIRECTION INPUT ;
  USE SIGNAL ;
  PORT
   LAYER M5 ;
   RECT 101.4240 630.6360 101.4480 630.7200 ;
  END
 END lo_d[397]
 PIN lo_d[398]
  DIRECTION INPUT ;
  USE SIGNAL ;
  PORT
   LAYER M5 ;
   RECT 101.6640 630.6360 101.6880 630.7200 ;
  END
 END lo_d[398]
 PIN lo_d[399]
  DIRECTION INPUT ;
  USE SIGNAL ;
  PORT
   LAYER M5 ;
   RECT 101.9040 630.6360 101.9280 630.7200 ;
  END
 END lo_d[399]
 PIN lo_d[400]
  DIRECTION INPUT ;
  USE SIGNAL ;
  PORT
   LAYER M5 ;
   RECT 102.1440 630.6360 102.1680 630.7200 ;
  END
 END lo_d[400]
 PIN lo_d[401]
  DIRECTION INPUT ;
  USE SIGNAL ;
  PORT
   LAYER M5 ;
   RECT 102.3840 630.6360 102.4080 630.7200 ;
  END
 END lo_d[401]
 PIN lo_d[402]
  DIRECTION INPUT ;
  USE SIGNAL ;
  PORT
   LAYER M5 ;
   RECT 102.6240 630.6360 102.6480 630.7200 ;
  END
 END lo_d[402]
 PIN lo_d[403]
  DIRECTION INPUT ;
  USE SIGNAL ;
  PORT
   LAYER M5 ;
   RECT 102.8640 630.6360 102.8880 630.7200 ;
  END
 END lo_d[403]
 PIN lo_d[404]
  DIRECTION INPUT ;
  USE SIGNAL ;
  PORT
   LAYER M5 ;
   RECT 103.1040 630.6360 103.1280 630.7200 ;
  END
 END lo_d[404]
 PIN lo_d[405]
  DIRECTION INPUT ;
  USE SIGNAL ;
  PORT
   LAYER M5 ;
   RECT 103.3440 630.6360 103.3680 630.7200 ;
  END
 END lo_d[405]
 PIN lo_d[406]
  DIRECTION INPUT ;
  USE SIGNAL ;
  PORT
   LAYER M5 ;
   RECT 103.5840 630.6360 103.6080 630.7200 ;
  END
 END lo_d[406]
 PIN lo_d[407]
  DIRECTION INPUT ;
  USE SIGNAL ;
  PORT
   LAYER M5 ;
   RECT 103.8240 630.6360 103.8480 630.7200 ;
  END
 END lo_d[407]
 PIN lo_d[408]
  DIRECTION INPUT ;
  USE SIGNAL ;
  PORT
   LAYER M5 ;
   RECT 104.0640 630.6360 104.0880 630.7200 ;
  END
 END lo_d[408]
 PIN lo_d[409]
  DIRECTION INPUT ;
  USE SIGNAL ;
  PORT
   LAYER M5 ;
   RECT 104.3040 630.6360 104.3280 630.7200 ;
  END
 END lo_d[409]
 PIN lo_d[410]
  DIRECTION INPUT ;
  USE SIGNAL ;
  PORT
   LAYER M5 ;
   RECT 104.5440 630.6360 104.5680 630.7200 ;
  END
 END lo_d[410]
 PIN lo_d[411]
  DIRECTION INPUT ;
  USE SIGNAL ;
  PORT
   LAYER M5 ;
   RECT 104.7840 630.6360 104.8080 630.7200 ;
  END
 END lo_d[411]
 PIN lo_d[412]
  DIRECTION INPUT ;
  USE SIGNAL ;
  PORT
   LAYER M5 ;
   RECT 105.0240 630.6360 105.0480 630.7200 ;
  END
 END lo_d[412]
 PIN lo_d[413]
  DIRECTION INPUT ;
  USE SIGNAL ;
  PORT
   LAYER M5 ;
   RECT 105.2640 630.6360 105.2880 630.7200 ;
  END
 END lo_d[413]
 PIN lo_d[414]
  DIRECTION INPUT ;
  USE SIGNAL ;
  PORT
   LAYER M5 ;
   RECT 105.5040 630.6360 105.5280 630.7200 ;
  END
 END lo_d[414]
 PIN lo_d[415]
  DIRECTION INPUT ;
  USE SIGNAL ;
  PORT
   LAYER M5 ;
   RECT 105.7440 630.6360 105.7680 630.7200 ;
  END
 END lo_d[415]
 PIN lo_d[416]
  DIRECTION INPUT ;
  USE SIGNAL ;
  PORT
   LAYER M5 ;
   RECT 105.9840 630.6360 106.0080 630.7200 ;
  END
 END lo_d[416]
 PIN lo_d[417]
  DIRECTION INPUT ;
  USE SIGNAL ;
  PORT
   LAYER M5 ;
   RECT 106.2240 630.6360 106.2480 630.7200 ;
  END
 END lo_d[417]
 PIN lo_d[418]
  DIRECTION INPUT ;
  USE SIGNAL ;
  PORT
   LAYER M5 ;
   RECT 106.4640 630.6360 106.4880 630.7200 ;
  END
 END lo_d[418]
 PIN lo_d[419]
  DIRECTION INPUT ;
  USE SIGNAL ;
  PORT
   LAYER M5 ;
   RECT 106.7040 630.6360 106.7280 630.7200 ;
  END
 END lo_d[419]
 PIN lo_d[420]
  DIRECTION INPUT ;
  USE SIGNAL ;
  PORT
   LAYER M5 ;
   RECT 106.9440 630.6360 106.9680 630.7200 ;
  END
 END lo_d[420]
 PIN lo_d[421]
  DIRECTION INPUT ;
  USE SIGNAL ;
  PORT
   LAYER M5 ;
   RECT 107.1840 630.6360 107.2080 630.7200 ;
  END
 END lo_d[421]
 PIN lo_d[422]
  DIRECTION INPUT ;
  USE SIGNAL ;
  PORT
   LAYER M5 ;
   RECT 107.4240 630.6360 107.4480 630.7200 ;
  END
 END lo_d[422]
 PIN lo_d[423]
  DIRECTION INPUT ;
  USE SIGNAL ;
  PORT
   LAYER M5 ;
   RECT 107.6640 630.6360 107.6880 630.7200 ;
  END
 END lo_d[423]
 PIN lo_d[424]
  DIRECTION INPUT ;
  USE SIGNAL ;
  PORT
   LAYER M5 ;
   RECT 107.9040 630.6360 107.9280 630.7200 ;
  END
 END lo_d[424]
 PIN lo_d[425]
  DIRECTION INPUT ;
  USE SIGNAL ;
  PORT
   LAYER M5 ;
   RECT 108.1440 630.6360 108.1680 630.7200 ;
  END
 END lo_d[425]
 PIN lo_d[426]
  DIRECTION INPUT ;
  USE SIGNAL ;
  PORT
   LAYER M5 ;
   RECT 108.3840 630.6360 108.4080 630.7200 ;
  END
 END lo_d[426]
 PIN lo_d[427]
  DIRECTION INPUT ;
  USE SIGNAL ;
  PORT
   LAYER M5 ;
   RECT 108.6240 630.6360 108.6480 630.7200 ;
  END
 END lo_d[427]
 PIN lo_d[428]
  DIRECTION INPUT ;
  USE SIGNAL ;
  PORT
   LAYER M5 ;
   RECT 108.8640 630.6360 108.8880 630.7200 ;
  END
 END lo_d[428]
 PIN lo_d[429]
  DIRECTION INPUT ;
  USE SIGNAL ;
  PORT
   LAYER M5 ;
   RECT 109.1040 630.6360 109.1280 630.7200 ;
  END
 END lo_d[429]
 PIN lo_d[430]
  DIRECTION INPUT ;
  USE SIGNAL ;
  PORT
   LAYER M5 ;
   RECT 109.3440 630.6360 109.3680 630.7200 ;
  END
 END lo_d[430]
 PIN lo_d[431]
  DIRECTION INPUT ;
  USE SIGNAL ;
  PORT
   LAYER M5 ;
   RECT 109.5840 630.6360 109.6080 630.7200 ;
  END
 END lo_d[431]
 PIN lo_d[432]
  DIRECTION INPUT ;
  USE SIGNAL ;
  PORT
   LAYER M5 ;
   RECT 109.8240 630.6360 109.8480 630.7200 ;
  END
 END lo_d[432]
 PIN lo_d[433]
  DIRECTION INPUT ;
  USE SIGNAL ;
  PORT
   LAYER M5 ;
   RECT 110.0640 630.6360 110.0880 630.7200 ;
  END
 END lo_d[433]
 PIN lo_d[434]
  DIRECTION INPUT ;
  USE SIGNAL ;
  PORT
   LAYER M5 ;
   RECT 110.3040 630.6360 110.3280 630.7200 ;
  END
 END lo_d[434]
 PIN lo_d[435]
  DIRECTION INPUT ;
  USE SIGNAL ;
  PORT
   LAYER M5 ;
   RECT 110.5440 630.6360 110.5680 630.7200 ;
  END
 END lo_d[435]
 PIN lo_d[436]
  DIRECTION INPUT ;
  USE SIGNAL ;
  PORT
   LAYER M5 ;
   RECT 110.7840 630.6360 110.8080 630.7200 ;
  END
 END lo_d[436]
 PIN lo_d[437]
  DIRECTION INPUT ;
  USE SIGNAL ;
  PORT
   LAYER M5 ;
   RECT 111.0240 630.6360 111.0480 630.7200 ;
  END
 END lo_d[437]
 PIN lo_d[438]
  DIRECTION INPUT ;
  USE SIGNAL ;
  PORT
   LAYER M5 ;
   RECT 111.2640 630.6360 111.2880 630.7200 ;
  END
 END lo_d[438]
 PIN lo_d[439]
  DIRECTION INPUT ;
  USE SIGNAL ;
  PORT
   LAYER M5 ;
   RECT 111.5040 630.6360 111.5280 630.7200 ;
  END
 END lo_d[439]
 PIN lo_d[440]
  DIRECTION INPUT ;
  USE SIGNAL ;
  PORT
   LAYER M5 ;
   RECT 111.7440 630.6360 111.7680 630.7200 ;
  END
 END lo_d[440]
 PIN lo_d[441]
  DIRECTION INPUT ;
  USE SIGNAL ;
  PORT
   LAYER M5 ;
   RECT 111.9840 630.6360 112.0080 630.7200 ;
  END
 END lo_d[441]
 PIN lo_d[442]
  DIRECTION INPUT ;
  USE SIGNAL ;
  PORT
   LAYER M5 ;
   RECT 112.2240 630.6360 112.2480 630.7200 ;
  END
 END lo_d[442]
 PIN lo_d[443]
  DIRECTION INPUT ;
  USE SIGNAL ;
  PORT
   LAYER M5 ;
   RECT 112.4640 630.6360 112.4880 630.7200 ;
  END
 END lo_d[443]
 PIN lo_d[444]
  DIRECTION INPUT ;
  USE SIGNAL ;
  PORT
   LAYER M5 ;
   RECT 112.7040 630.6360 112.7280 630.7200 ;
  END
 END lo_d[444]
 PIN lo_d[445]
  DIRECTION INPUT ;
  USE SIGNAL ;
  PORT
   LAYER M5 ;
   RECT 112.9440 630.6360 112.9680 630.7200 ;
  END
 END lo_d[445]
 PIN lo_d[446]
  DIRECTION INPUT ;
  USE SIGNAL ;
  PORT
   LAYER M5 ;
   RECT 113.1840 630.6360 113.2080 630.7200 ;
  END
 END lo_d[446]
 PIN lo_d[447]
  DIRECTION INPUT ;
  USE SIGNAL ;
  PORT
   LAYER M5 ;
   RECT 113.4240 630.6360 113.4480 630.7200 ;
  END
 END lo_d[447]
 PIN lo_d[448]
  DIRECTION INPUT ;
  USE SIGNAL ;
  PORT
   LAYER M5 ;
   RECT 113.6640 630.6360 113.6880 630.7200 ;
  END
 END lo_d[448]
 PIN lo_d[449]
  DIRECTION INPUT ;
  USE SIGNAL ;
  PORT
   LAYER M5 ;
   RECT 113.9040 630.6360 113.9280 630.7200 ;
  END
 END lo_d[449]
 PIN lo_d[450]
  DIRECTION INPUT ;
  USE SIGNAL ;
  PORT
   LAYER M5 ;
   RECT 114.1440 630.6360 114.1680 630.7200 ;
  END
 END lo_d[450]
 PIN lo_d[451]
  DIRECTION INPUT ;
  USE SIGNAL ;
  PORT
   LAYER M5 ;
   RECT 114.3840 630.6360 114.4080 630.7200 ;
  END
 END lo_d[451]
 PIN lo_d[452]
  DIRECTION INPUT ;
  USE SIGNAL ;
  PORT
   LAYER M5 ;
   RECT 114.6240 630.6360 114.6480 630.7200 ;
  END
 END lo_d[452]
 PIN lo_d[453]
  DIRECTION INPUT ;
  USE SIGNAL ;
  PORT
   LAYER M5 ;
   RECT 114.8640 630.6360 114.8880 630.7200 ;
  END
 END lo_d[453]
 PIN lo_d[454]
  DIRECTION INPUT ;
  USE SIGNAL ;
  PORT
   LAYER M5 ;
   RECT 115.1040 630.6360 115.1280 630.7200 ;
  END
 END lo_d[454]
 PIN lo_d[455]
  DIRECTION INPUT ;
  USE SIGNAL ;
  PORT
   LAYER M5 ;
   RECT 115.3440 630.6360 115.3680 630.7200 ;
  END
 END lo_d[455]
 PIN lo_d[456]
  DIRECTION INPUT ;
  USE SIGNAL ;
  PORT
   LAYER M5 ;
   RECT 115.5840 630.6360 115.6080 630.7200 ;
  END
 END lo_d[456]
 PIN lo_d[457]
  DIRECTION INPUT ;
  USE SIGNAL ;
  PORT
   LAYER M5 ;
   RECT 115.8240 630.6360 115.8480 630.7200 ;
  END
 END lo_d[457]
 PIN lo_d[458]
  DIRECTION INPUT ;
  USE SIGNAL ;
  PORT
   LAYER M5 ;
   RECT 116.0640 630.6360 116.0880 630.7200 ;
  END
 END lo_d[458]
 PIN lo_d[459]
  DIRECTION INPUT ;
  USE SIGNAL ;
  PORT
   LAYER M5 ;
   RECT 116.3040 630.6360 116.3280 630.7200 ;
  END
 END lo_d[459]
 PIN lo_d[460]
  DIRECTION INPUT ;
  USE SIGNAL ;
  PORT
   LAYER M5 ;
   RECT 116.5440 630.6360 116.5680 630.7200 ;
  END
 END lo_d[460]
 PIN lo_d[461]
  DIRECTION INPUT ;
  USE SIGNAL ;
  PORT
   LAYER M5 ;
   RECT 116.7840 630.6360 116.8080 630.7200 ;
  END
 END lo_d[461]
 PIN lo_d[462]
  DIRECTION INPUT ;
  USE SIGNAL ;
  PORT
   LAYER M5 ;
   RECT 117.0240 630.6360 117.0480 630.7200 ;
  END
 END lo_d[462]
 PIN lo_d[463]
  DIRECTION INPUT ;
  USE SIGNAL ;
  PORT
   LAYER M5 ;
   RECT 117.2640 630.6360 117.2880 630.7200 ;
  END
 END lo_d[463]
 PIN lo_d[464]
  DIRECTION INPUT ;
  USE SIGNAL ;
  PORT
   LAYER M5 ;
   RECT 117.5040 630.6360 117.5280 630.7200 ;
  END
 END lo_d[464]
 PIN lo_d[465]
  DIRECTION INPUT ;
  USE SIGNAL ;
  PORT
   LAYER M5 ;
   RECT 117.7440 630.6360 117.7680 630.7200 ;
  END
 END lo_d[465]
 PIN lo_d[466]
  DIRECTION INPUT ;
  USE SIGNAL ;
  PORT
   LAYER M5 ;
   RECT 117.9840 630.6360 118.0080 630.7200 ;
  END
 END lo_d[466]
 PIN lo_d[467]
  DIRECTION INPUT ;
  USE SIGNAL ;
  PORT
   LAYER M5 ;
   RECT 118.2240 630.6360 118.2480 630.7200 ;
  END
 END lo_d[467]
 PIN lo_d[468]
  DIRECTION INPUT ;
  USE SIGNAL ;
  PORT
   LAYER M5 ;
   RECT 118.4640 630.6360 118.4880 630.7200 ;
  END
 END lo_d[468]
 PIN lo_d[469]
  DIRECTION INPUT ;
  USE SIGNAL ;
  PORT
   LAYER M5 ;
   RECT 118.7040 630.6360 118.7280 630.7200 ;
  END
 END lo_d[469]
 PIN lo_d[470]
  DIRECTION INPUT ;
  USE SIGNAL ;
  PORT
   LAYER M5 ;
   RECT 118.9440 630.6360 118.9680 630.7200 ;
  END
 END lo_d[470]
 PIN lo_d[471]
  DIRECTION INPUT ;
  USE SIGNAL ;
  PORT
   LAYER M5 ;
   RECT 119.1840 630.6360 119.2080 630.7200 ;
  END
 END lo_d[471]
 PIN lo_d[472]
  DIRECTION INPUT ;
  USE SIGNAL ;
  PORT
   LAYER M5 ;
   RECT 119.4240 630.6360 119.4480 630.7200 ;
  END
 END lo_d[472]
 PIN lo_d[473]
  DIRECTION INPUT ;
  USE SIGNAL ;
  PORT
   LAYER M5 ;
   RECT 119.6640 630.6360 119.6880 630.7200 ;
  END
 END lo_d[473]
 PIN lo_d[474]
  DIRECTION INPUT ;
  USE SIGNAL ;
  PORT
   LAYER M5 ;
   RECT 119.9040 630.6360 119.9280 630.7200 ;
  END
 END lo_d[474]
 PIN lo_d[475]
  DIRECTION INPUT ;
  USE SIGNAL ;
  PORT
   LAYER M5 ;
   RECT 120.1440 630.6360 120.1680 630.7200 ;
  END
 END lo_d[475]
 PIN lo_d[476]
  DIRECTION INPUT ;
  USE SIGNAL ;
  PORT
   LAYER M5 ;
   RECT 120.3840 630.6360 120.4080 630.7200 ;
  END
 END lo_d[476]
 PIN lo_d[477]
  DIRECTION INPUT ;
  USE SIGNAL ;
  PORT
   LAYER M5 ;
   RECT 120.6240 630.6360 120.6480 630.7200 ;
  END
 END lo_d[477]
 PIN lo_d[478]
  DIRECTION INPUT ;
  USE SIGNAL ;
  PORT
   LAYER M5 ;
   RECT 120.8640 630.6360 120.8880 630.7200 ;
  END
 END lo_d[478]
 PIN lo_d[479]
  DIRECTION INPUT ;
  USE SIGNAL ;
  PORT
   LAYER M5 ;
   RECT 121.1040 630.6360 121.1280 630.7200 ;
  END
 END lo_d[479]
 PIN lo_d[480]
  DIRECTION INPUT ;
  USE SIGNAL ;
  PORT
   LAYER M5 ;
   RECT 121.3440 630.6360 121.3680 630.7200 ;
  END
 END lo_d[480]
 PIN lo_d[481]
  DIRECTION INPUT ;
  USE SIGNAL ;
  PORT
   LAYER M5 ;
   RECT 121.5840 630.6360 121.6080 630.7200 ;
  END
 END lo_d[481]
 PIN lo_d[482]
  DIRECTION INPUT ;
  USE SIGNAL ;
  PORT
   LAYER M5 ;
   RECT 121.8240 630.6360 121.8480 630.7200 ;
  END
 END lo_d[482]
 PIN lo_d[483]
  DIRECTION INPUT ;
  USE SIGNAL ;
  PORT
   LAYER M5 ;
   RECT 122.0640 630.6360 122.0880 630.7200 ;
  END
 END lo_d[483]
 PIN lo_d[484]
  DIRECTION INPUT ;
  USE SIGNAL ;
  PORT
   LAYER M5 ;
   RECT 122.3040 630.6360 122.3280 630.7200 ;
  END
 END lo_d[484]
 PIN lo_d[485]
  DIRECTION INPUT ;
  USE SIGNAL ;
  PORT
   LAYER M5 ;
   RECT 122.5440 630.6360 122.5680 630.7200 ;
  END
 END lo_d[485]
 PIN lo_d[486]
  DIRECTION INPUT ;
  USE SIGNAL ;
  PORT
   LAYER M5 ;
   RECT 122.7840 630.6360 122.8080 630.7200 ;
  END
 END lo_d[486]
 PIN lo_d[487]
  DIRECTION INPUT ;
  USE SIGNAL ;
  PORT
   LAYER M5 ;
   RECT 123.0240 630.6360 123.0480 630.7200 ;
  END
 END lo_d[487]
 PIN lo_d[488]
  DIRECTION INPUT ;
  USE SIGNAL ;
  PORT
   LAYER M5 ;
   RECT 123.2640 630.6360 123.2880 630.7200 ;
  END
 END lo_d[488]
 PIN lo_d[489]
  DIRECTION INPUT ;
  USE SIGNAL ;
  PORT
   LAYER M5 ;
   RECT 123.5040 630.6360 123.5280 630.7200 ;
  END
 END lo_d[489]
 PIN lo_d[490]
  DIRECTION INPUT ;
  USE SIGNAL ;
  PORT
   LAYER M5 ;
   RECT 123.7440 630.6360 123.7680 630.7200 ;
  END
 END lo_d[490]
 PIN lo_d[491]
  DIRECTION INPUT ;
  USE SIGNAL ;
  PORT
   LAYER M5 ;
   RECT 123.9840 630.6360 124.0080 630.7200 ;
  END
 END lo_d[491]
 PIN lo_d[492]
  DIRECTION INPUT ;
  USE SIGNAL ;
  PORT
   LAYER M5 ;
   RECT 124.2240 630.6360 124.2480 630.7200 ;
  END
 END lo_d[492]
 PIN lo_d[493]
  DIRECTION INPUT ;
  USE SIGNAL ;
  PORT
   LAYER M5 ;
   RECT 124.4640 630.6360 124.4880 630.7200 ;
  END
 END lo_d[493]
 PIN lo_d[494]
  DIRECTION INPUT ;
  USE SIGNAL ;
  PORT
   LAYER M5 ;
   RECT 124.7040 630.6360 124.7280 630.7200 ;
  END
 END lo_d[494]
 PIN lo_d[495]
  DIRECTION INPUT ;
  USE SIGNAL ;
  PORT
   LAYER M5 ;
   RECT 124.9440 630.6360 124.9680 630.7200 ;
  END
 END lo_d[495]
 PIN lo_d[496]
  DIRECTION INPUT ;
  USE SIGNAL ;
  PORT
   LAYER M5 ;
   RECT 125.1840 630.6360 125.2080 630.7200 ;
  END
 END lo_d[496]
 PIN lo_d[497]
  DIRECTION INPUT ;
  USE SIGNAL ;
  PORT
   LAYER M5 ;
   RECT 125.4240 630.6360 125.4480 630.7200 ;
  END
 END lo_d[497]
 PIN lo_d[498]
  DIRECTION INPUT ;
  USE SIGNAL ;
  PORT
   LAYER M5 ;
   RECT 125.6640 630.6360 125.6880 630.7200 ;
  END
 END lo_d[498]
 PIN lo_d[499]
  DIRECTION INPUT ;
  USE SIGNAL ;
  PORT
   LAYER M5 ;
   RECT 125.9040 630.6360 125.9280 630.7200 ;
  END
 END lo_d[499]
 PIN lo_d[500]
  DIRECTION INPUT ;
  USE SIGNAL ;
  PORT
   LAYER M5 ;
   RECT 126.1440 630.6360 126.1680 630.7200 ;
  END
 END lo_d[500]
 PIN lo_d[501]
  DIRECTION INPUT ;
  USE SIGNAL ;
  PORT
   LAYER M5 ;
   RECT 126.3840 630.6360 126.4080 630.7200 ;
  END
 END lo_d[501]
 PIN lo_d[502]
  DIRECTION INPUT ;
  USE SIGNAL ;
  PORT
   LAYER M5 ;
   RECT 126.6240 630.6360 126.6480 630.7200 ;
  END
 END lo_d[502]
 PIN lo_d[503]
  DIRECTION INPUT ;
  USE SIGNAL ;
  PORT
   LAYER M5 ;
   RECT 126.8640 630.6360 126.8880 630.7200 ;
  END
 END lo_d[503]
 PIN lo_d[504]
  DIRECTION INPUT ;
  USE SIGNAL ;
  PORT
   LAYER M5 ;
   RECT 127.1040 630.6360 127.1280 630.7200 ;
  END
 END lo_d[504]
 PIN lo_d[505]
  DIRECTION INPUT ;
  USE SIGNAL ;
  PORT
   LAYER M5 ;
   RECT 127.3440 630.6360 127.3680 630.7200 ;
  END
 END lo_d[505]
 PIN lo_d[506]
  DIRECTION INPUT ;
  USE SIGNAL ;
  PORT
   LAYER M5 ;
   RECT 127.5840 630.6360 127.6080 630.7200 ;
  END
 END lo_d[506]
 PIN lo_d[507]
  DIRECTION INPUT ;
  USE SIGNAL ;
  PORT
   LAYER M5 ;
   RECT 127.8240 630.6360 127.8480 630.7200 ;
  END
 END lo_d[507]
 PIN lo_d[508]
  DIRECTION INPUT ;
  USE SIGNAL ;
  PORT
   LAYER M5 ;
   RECT 128.0640 630.6360 128.0880 630.7200 ;
  END
 END lo_d[508]
 PIN lo_d[509]
  DIRECTION INPUT ;
  USE SIGNAL ;
  PORT
   LAYER M5 ;
   RECT 128.3040 630.6360 128.3280 630.7200 ;
  END
 END lo_d[509]
 PIN lo_d[510]
  DIRECTION INPUT ;
  USE SIGNAL ;
  PORT
   LAYER M5 ;
   RECT 128.5440 630.6360 128.5680 630.7200 ;
  END
 END lo_d[510]
 PIN lo_d[511]
  DIRECTION INPUT ;
  USE SIGNAL ;
  PORT
   LAYER M5 ;
   RECT 128.7840 630.6360 128.8080 630.7200 ;
  END
 END lo_d[511]
 PIN lo_d[512]
  DIRECTION INPUT ;
  USE SIGNAL ;
  PORT
   LAYER M5 ;
   RECT 129.0240 630.6360 129.0480 630.7200 ;
  END
 END lo_d[512]
 PIN lo_d[513]
  DIRECTION INPUT ;
  USE SIGNAL ;
  PORT
   LAYER M5 ;
   RECT 129.2640 630.6360 129.2880 630.7200 ;
  END
 END lo_d[513]
 PIN lo_d[514]
  DIRECTION INPUT ;
  USE SIGNAL ;
  PORT
   LAYER M5 ;
   RECT 129.5040 630.6360 129.5280 630.7200 ;
  END
 END lo_d[514]
 PIN lo_d[515]
  DIRECTION INPUT ;
  USE SIGNAL ;
  PORT
   LAYER M5 ;
   RECT 129.7440 630.6360 129.7680 630.7200 ;
  END
 END lo_d[515]
 PIN lo_d[516]
  DIRECTION INPUT ;
  USE SIGNAL ;
  PORT
   LAYER M5 ;
   RECT 129.9840 630.6360 130.0080 630.7200 ;
  END
 END lo_d[516]
 PIN lo_d[517]
  DIRECTION INPUT ;
  USE SIGNAL ;
  PORT
   LAYER M5 ;
   RECT 130.2240 630.6360 130.2480 630.7200 ;
  END
 END lo_d[517]
 PIN lo_d[518]
  DIRECTION INPUT ;
  USE SIGNAL ;
  PORT
   LAYER M5 ;
   RECT 130.4640 630.6360 130.4880 630.7200 ;
  END
 END lo_d[518]
 PIN lo_d[519]
  DIRECTION INPUT ;
  USE SIGNAL ;
  PORT
   LAYER M5 ;
   RECT 130.7040 630.6360 130.7280 630.7200 ;
  END
 END lo_d[519]
 PIN lo_d[520]
  DIRECTION INPUT ;
  USE SIGNAL ;
  PORT
   LAYER M5 ;
   RECT 130.9440 630.6360 130.9680 630.7200 ;
  END
 END lo_d[520]
 PIN lo_d[521]
  DIRECTION INPUT ;
  USE SIGNAL ;
  PORT
   LAYER M5 ;
   RECT 131.1840 630.6360 131.2080 630.7200 ;
  END
 END lo_d[521]
 PIN lo_d[522]
  DIRECTION INPUT ;
  USE SIGNAL ;
  PORT
   LAYER M5 ;
   RECT 131.4240 630.6360 131.4480 630.7200 ;
  END
 END lo_d[522]
 PIN lo_d[523]
  DIRECTION INPUT ;
  USE SIGNAL ;
  PORT
   LAYER M5 ;
   RECT 131.6640 630.6360 131.6880 630.7200 ;
  END
 END lo_d[523]
 PIN lo_d[524]
  DIRECTION INPUT ;
  USE SIGNAL ;
  PORT
   LAYER M5 ;
   RECT 131.9040 630.6360 131.9280 630.7200 ;
  END
 END lo_d[524]
 PIN lo_d[525]
  DIRECTION INPUT ;
  USE SIGNAL ;
  PORT
   LAYER M5 ;
   RECT 132.1440 630.6360 132.1680 630.7200 ;
  END
 END lo_d[525]
 PIN lo_d[526]
  DIRECTION INPUT ;
  USE SIGNAL ;
  PORT
   LAYER M5 ;
   RECT 132.3840 630.6360 132.4080 630.7200 ;
  END
 END lo_d[526]
 PIN lo_d[527]
  DIRECTION INPUT ;
  USE SIGNAL ;
  PORT
   LAYER M5 ;
   RECT 132.6240 630.6360 132.6480 630.7200 ;
  END
 END lo_d[527]
 PIN lo_d[528]
  DIRECTION INPUT ;
  USE SIGNAL ;
  PORT
   LAYER M5 ;
   RECT 132.8640 630.6360 132.8880 630.7200 ;
  END
 END lo_d[528]
 PIN lo_d[529]
  DIRECTION INPUT ;
  USE SIGNAL ;
  PORT
   LAYER M5 ;
   RECT 133.1040 630.6360 133.1280 630.7200 ;
  END
 END lo_d[529]
 PIN lo_d[530]
  DIRECTION INPUT ;
  USE SIGNAL ;
  PORT
   LAYER M5 ;
   RECT 133.3440 630.6360 133.3680 630.7200 ;
  END
 END lo_d[530]
 PIN lo_d[531]
  DIRECTION INPUT ;
  USE SIGNAL ;
  PORT
   LAYER M5 ;
   RECT 133.5840 630.6360 133.6080 630.7200 ;
  END
 END lo_d[531]
 PIN lo_d[532]
  DIRECTION INPUT ;
  USE SIGNAL ;
  PORT
   LAYER M5 ;
   RECT 133.8240 630.6360 133.8480 630.7200 ;
  END
 END lo_d[532]
 PIN lo_d[533]
  DIRECTION INPUT ;
  USE SIGNAL ;
  PORT
   LAYER M5 ;
   RECT 134.0640 630.6360 134.0880 630.7200 ;
  END
 END lo_d[533]
 PIN lo_d[534]
  DIRECTION INPUT ;
  USE SIGNAL ;
  PORT
   LAYER M5 ;
   RECT 134.3040 630.6360 134.3280 630.7200 ;
  END
 END lo_d[534]
 PIN lo_d[535]
  DIRECTION INPUT ;
  USE SIGNAL ;
  PORT
   LAYER M5 ;
   RECT 134.5440 630.6360 134.5680 630.7200 ;
  END
 END lo_d[535]
 PIN lo_d[536]
  DIRECTION INPUT ;
  USE SIGNAL ;
  PORT
   LAYER M5 ;
   RECT 134.7840 630.6360 134.8080 630.7200 ;
  END
 END lo_d[536]
 PIN lo_d[537]
  DIRECTION INPUT ;
  USE SIGNAL ;
  PORT
   LAYER M5 ;
   RECT 135.0240 630.6360 135.0480 630.7200 ;
  END
 END lo_d[537]
 PIN lo_d[538]
  DIRECTION INPUT ;
  USE SIGNAL ;
  PORT
   LAYER M5 ;
   RECT 135.2640 630.6360 135.2880 630.7200 ;
  END
 END lo_d[538]
 PIN lo_d[539]
  DIRECTION INPUT ;
  USE SIGNAL ;
  PORT
   LAYER M5 ;
   RECT 135.5040 630.6360 135.5280 630.7200 ;
  END
 END lo_d[539]
 PIN lo_d[540]
  DIRECTION INPUT ;
  USE SIGNAL ;
  PORT
   LAYER M5 ;
   RECT 135.7440 630.6360 135.7680 630.7200 ;
  END
 END lo_d[540]
 PIN lo_d[541]
  DIRECTION INPUT ;
  USE SIGNAL ;
  PORT
   LAYER M5 ;
   RECT 135.9840 630.6360 136.0080 630.7200 ;
  END
 END lo_d[541]
 PIN lo_d[542]
  DIRECTION INPUT ;
  USE SIGNAL ;
  PORT
   LAYER M5 ;
   RECT 136.2240 630.6360 136.2480 630.7200 ;
  END
 END lo_d[542]
 PIN lo_d[543]
  DIRECTION INPUT ;
  USE SIGNAL ;
  PORT
   LAYER M5 ;
   RECT 136.4640 630.6360 136.4880 630.7200 ;
  END
 END lo_d[543]
 PIN lo_d[544]
  DIRECTION INPUT ;
  USE SIGNAL ;
  PORT
   LAYER M5 ;
   RECT 136.7040 630.6360 136.7280 630.7200 ;
  END
 END lo_d[544]
 PIN lo_d[545]
  DIRECTION INPUT ;
  USE SIGNAL ;
  PORT
   LAYER M5 ;
   RECT 136.9440 630.6360 136.9680 630.7200 ;
  END
 END lo_d[545]
 PIN lo_d[546]
  DIRECTION INPUT ;
  USE SIGNAL ;
  PORT
   LAYER M5 ;
   RECT 137.1840 630.6360 137.2080 630.7200 ;
  END
 END lo_d[546]
 PIN lo_d[547]
  DIRECTION INPUT ;
  USE SIGNAL ;
  PORT
   LAYER M5 ;
   RECT 137.4240 630.6360 137.4480 630.7200 ;
  END
 END lo_d[547]
 PIN lo_d[548]
  DIRECTION INPUT ;
  USE SIGNAL ;
  PORT
   LAYER M5 ;
   RECT 137.6640 630.6360 137.6880 630.7200 ;
  END
 END lo_d[548]
 PIN lo_d[549]
  DIRECTION INPUT ;
  USE SIGNAL ;
  PORT
   LAYER M5 ;
   RECT 137.9040 630.6360 137.9280 630.7200 ;
  END
 END lo_d[549]
 PIN lo_d[550]
  DIRECTION INPUT ;
  USE SIGNAL ;
  PORT
   LAYER M5 ;
   RECT 138.1440 630.6360 138.1680 630.7200 ;
  END
 END lo_d[550]
 PIN lo_d[551]
  DIRECTION INPUT ;
  USE SIGNAL ;
  PORT
   LAYER M5 ;
   RECT 138.3840 630.6360 138.4080 630.7200 ;
  END
 END lo_d[551]
 PIN lo_d[552]
  DIRECTION INPUT ;
  USE SIGNAL ;
  PORT
   LAYER M5 ;
   RECT 138.6240 630.6360 138.6480 630.7200 ;
  END
 END lo_d[552]
 PIN lo_v[0]
  DIRECTION INPUT ;
  USE SIGNAL ;
  PORT
   LAYER M5 ;
   RECT 138.8640 630.6360 138.8880 630.7200 ;
  END
 END lo_v[0]
 PIN lo_r[0]
  DIRECTION OUTPUT ;
  USE SIGNAL ;
  PORT
   LAYER M5 ;
   RECT 139.1040 630.6360 139.1280 630.7200 ;
  END
 END lo_r[0]
 PIN li_v[0]
  DIRECTION OUTPUT ;
  USE SIGNAL ;
  PORT
   LAYER M5 ;
   RECT 163.9200 630.6360 163.9440 630.7200 ;
  END
 END li_v[0]
 PIN li_r[0]
  DIRECTION INPUT ;
  USE SIGNAL ;
  PORT
   LAYER M5 ;
   RECT 164.1600 630.6360 164.1840 630.7200 ;
  END
 END li_r[0]
 PIN li_d[0]
  DIRECTION OUTPUT ;
  USE SIGNAL ;
  PORT
   LAYER M5 ;
   RECT 164.4000 630.6360 164.4240 630.7200 ;
  END
 END li_d[0]
 PIN li_d[1]
  DIRECTION OUTPUT ;
  USE SIGNAL ;
  PORT
   LAYER M5 ;
   RECT 164.6400 630.6360 164.6640 630.7200 ;
  END
 END li_d[1]
 PIN li_d[2]
  DIRECTION OUTPUT ;
  USE SIGNAL ;
  PORT
   LAYER M5 ;
   RECT 164.8800 630.6360 164.9040 630.7200 ;
  END
 END li_d[2]
 PIN li_d[3]
  DIRECTION OUTPUT ;
  USE SIGNAL ;
  PORT
   LAYER M5 ;
   RECT 165.1200 630.6360 165.1440 630.7200 ;
  END
 END li_d[3]
 PIN li_d[4]
  DIRECTION OUTPUT ;
  USE SIGNAL ;
  PORT
   LAYER M5 ;
   RECT 165.3600 630.6360 165.3840 630.7200 ;
  END
 END li_d[4]
 PIN li_d[5]
  DIRECTION OUTPUT ;
  USE SIGNAL ;
  PORT
   LAYER M5 ;
   RECT 165.6000 630.6360 165.6240 630.7200 ;
  END
 END li_d[5]
 PIN li_d[6]
  DIRECTION OUTPUT ;
  USE SIGNAL ;
  PORT
   LAYER M5 ;
   RECT 165.8400 630.6360 165.8640 630.7200 ;
  END
 END li_d[6]
 PIN li_d[7]
  DIRECTION OUTPUT ;
  USE SIGNAL ;
  PORT
   LAYER M5 ;
   RECT 166.0800 630.6360 166.1040 630.7200 ;
  END
 END li_d[7]
 PIN li_d[8]
  DIRECTION OUTPUT ;
  USE SIGNAL ;
  PORT
   LAYER M5 ;
   RECT 166.3200 630.6360 166.3440 630.7200 ;
  END
 END li_d[8]
 PIN li_d[9]
  DIRECTION OUTPUT ;
  USE SIGNAL ;
  PORT
   LAYER M5 ;
   RECT 166.5600 630.6360 166.5840 630.7200 ;
  END
 END li_d[9]
 PIN li_d[10]
  DIRECTION OUTPUT ;
  USE SIGNAL ;
  PORT
   LAYER M5 ;
   RECT 166.8000 630.6360 166.8240 630.7200 ;
  END
 END li_d[10]
 PIN li_d[11]
  DIRECTION OUTPUT ;
  USE SIGNAL ;
  PORT
   LAYER M5 ;
   RECT 167.0400 630.6360 167.0640 630.7200 ;
  END
 END li_d[11]
 PIN li_d[12]
  DIRECTION OUTPUT ;
  USE SIGNAL ;
  PORT
   LAYER M5 ;
   RECT 167.2800 630.6360 167.3040 630.7200 ;
  END
 END li_d[12]
 PIN li_d[13]
  DIRECTION OUTPUT ;
  USE SIGNAL ;
  PORT
   LAYER M5 ;
   RECT 167.5200 630.6360 167.5440 630.7200 ;
  END
 END li_d[13]
 PIN li_d[14]
  DIRECTION OUTPUT ;
  USE SIGNAL ;
  PORT
   LAYER M5 ;
   RECT 167.7600 630.6360 167.7840 630.7200 ;
  END
 END li_d[14]
 PIN li_d[15]
  DIRECTION OUTPUT ;
  USE SIGNAL ;
  PORT
   LAYER M5 ;
   RECT 168.0000 630.6360 168.0240 630.7200 ;
  END
 END li_d[15]
 PIN li_d[16]
  DIRECTION OUTPUT ;
  USE SIGNAL ;
  PORT
   LAYER M5 ;
   RECT 168.2400 630.6360 168.2640 630.7200 ;
  END
 END li_d[16]
 PIN li_d[17]
  DIRECTION OUTPUT ;
  USE SIGNAL ;
  PORT
   LAYER M5 ;
   RECT 168.4800 630.6360 168.5040 630.7200 ;
  END
 END li_d[17]
 PIN li_d[18]
  DIRECTION OUTPUT ;
  USE SIGNAL ;
  PORT
   LAYER M5 ;
   RECT 168.7200 630.6360 168.7440 630.7200 ;
  END
 END li_d[18]
 PIN li_d[19]
  DIRECTION OUTPUT ;
  USE SIGNAL ;
  PORT
   LAYER M5 ;
   RECT 168.9600 630.6360 168.9840 630.7200 ;
  END
 END li_d[19]
 PIN li_d[20]
  DIRECTION OUTPUT ;
  USE SIGNAL ;
  PORT
   LAYER M5 ;
   RECT 169.2000 630.6360 169.2240 630.7200 ;
  END
 END li_d[20]
 PIN li_d[21]
  DIRECTION OUTPUT ;
  USE SIGNAL ;
  PORT
   LAYER M5 ;
   RECT 169.4400 630.6360 169.4640 630.7200 ;
  END
 END li_d[21]
 PIN li_d[22]
  DIRECTION OUTPUT ;
  USE SIGNAL ;
  PORT
   LAYER M5 ;
   RECT 169.6800 630.6360 169.7040 630.7200 ;
  END
 END li_d[22]
 PIN li_d[23]
  DIRECTION OUTPUT ;
  USE SIGNAL ;
  PORT
   LAYER M5 ;
   RECT 169.9200 630.6360 169.9440 630.7200 ;
  END
 END li_d[23]
 PIN li_d[24]
  DIRECTION OUTPUT ;
  USE SIGNAL ;
  PORT
   LAYER M5 ;
   RECT 170.1600 630.6360 170.1840 630.7200 ;
  END
 END li_d[24]
 PIN li_d[25]
  DIRECTION OUTPUT ;
  USE SIGNAL ;
  PORT
   LAYER M5 ;
   RECT 170.4000 630.6360 170.4240 630.7200 ;
  END
 END li_d[25]
 PIN li_d[26]
  DIRECTION OUTPUT ;
  USE SIGNAL ;
  PORT
   LAYER M5 ;
   RECT 170.6400 630.6360 170.6640 630.7200 ;
  END
 END li_d[26]
 PIN li_d[27]
  DIRECTION OUTPUT ;
  USE SIGNAL ;
  PORT
   LAYER M5 ;
   RECT 170.8800 630.6360 170.9040 630.7200 ;
  END
 END li_d[27]
 PIN li_d[28]
  DIRECTION OUTPUT ;
  USE SIGNAL ;
  PORT
   LAYER M5 ;
   RECT 171.1200 630.6360 171.1440 630.7200 ;
  END
 END li_d[28]
 PIN li_d[29]
  DIRECTION OUTPUT ;
  USE SIGNAL ;
  PORT
   LAYER M5 ;
   RECT 171.3600 630.6360 171.3840 630.7200 ;
  END
 END li_d[29]
 PIN li_d[30]
  DIRECTION OUTPUT ;
  USE SIGNAL ;
  PORT
   LAYER M5 ;
   RECT 171.6000 630.6360 171.6240 630.7200 ;
  END
 END li_d[30]
 PIN li_d[31]
  DIRECTION OUTPUT ;
  USE SIGNAL ;
  PORT
   LAYER M5 ;
   RECT 171.8400 630.6360 171.8640 630.7200 ;
  END
 END li_d[31]
 PIN li_d[32]
  DIRECTION OUTPUT ;
  USE SIGNAL ;
  PORT
   LAYER M5 ;
   RECT 172.0800 630.6360 172.1040 630.7200 ;
  END
 END li_d[32]
 PIN li_d[33]
  DIRECTION OUTPUT ;
  USE SIGNAL ;
  PORT
   LAYER M5 ;
   RECT 172.3200 630.6360 172.3440 630.7200 ;
  END
 END li_d[33]
 PIN li_d[34]
  DIRECTION OUTPUT ;
  USE SIGNAL ;
  PORT
   LAYER M5 ;
   RECT 172.5600 630.6360 172.5840 630.7200 ;
  END
 END li_d[34]
 PIN li_d[35]
  DIRECTION OUTPUT ;
  USE SIGNAL ;
  PORT
   LAYER M5 ;
   RECT 172.8000 630.6360 172.8240 630.7200 ;
  END
 END li_d[35]
 PIN li_d[36]
  DIRECTION OUTPUT ;
  USE SIGNAL ;
  PORT
   LAYER M5 ;
   RECT 173.0400 630.6360 173.0640 630.7200 ;
  END
 END li_d[36]
 PIN li_d[37]
  DIRECTION OUTPUT ;
  USE SIGNAL ;
  PORT
   LAYER M5 ;
   RECT 173.2800 630.6360 173.3040 630.7200 ;
  END
 END li_d[37]
 PIN li_d[38]
  DIRECTION OUTPUT ;
  USE SIGNAL ;
  PORT
   LAYER M5 ;
   RECT 173.5200 630.6360 173.5440 630.7200 ;
  END
 END li_d[38]
 PIN li_d[39]
  DIRECTION OUTPUT ;
  USE SIGNAL ;
  PORT
   LAYER M5 ;
   RECT 173.7600 630.6360 173.7840 630.7200 ;
  END
 END li_d[39]
 PIN li_d[40]
  DIRECTION OUTPUT ;
  USE SIGNAL ;
  PORT
   LAYER M5 ;
   RECT 174.0000 630.6360 174.0240 630.7200 ;
  END
 END li_d[40]
 PIN li_d[41]
  DIRECTION OUTPUT ;
  USE SIGNAL ;
  PORT
   LAYER M5 ;
   RECT 174.2400 630.6360 174.2640 630.7200 ;
  END
 END li_d[41]
 PIN li_d[42]
  DIRECTION OUTPUT ;
  USE SIGNAL ;
  PORT
   LAYER M5 ;
   RECT 174.4800 630.6360 174.5040 630.7200 ;
  END
 END li_d[42]
 PIN li_d[43]
  DIRECTION OUTPUT ;
  USE SIGNAL ;
  PORT
   LAYER M5 ;
   RECT 174.7200 630.6360 174.7440 630.7200 ;
  END
 END li_d[43]
 PIN li_d[44]
  DIRECTION OUTPUT ;
  USE SIGNAL ;
  PORT
   LAYER M5 ;
   RECT 174.9600 630.6360 174.9840 630.7200 ;
  END
 END li_d[44]
 PIN li_d[45]
  DIRECTION OUTPUT ;
  USE SIGNAL ;
  PORT
   LAYER M5 ;
   RECT 175.2000 630.6360 175.2240 630.7200 ;
  END
 END li_d[45]
 PIN li_d[46]
  DIRECTION OUTPUT ;
  USE SIGNAL ;
  PORT
   LAYER M5 ;
   RECT 175.4400 630.6360 175.4640 630.7200 ;
  END
 END li_d[46]
 PIN li_d[47]
  DIRECTION OUTPUT ;
  USE SIGNAL ;
  PORT
   LAYER M5 ;
   RECT 175.6800 630.6360 175.7040 630.7200 ;
  END
 END li_d[47]
 PIN li_d[48]
  DIRECTION OUTPUT ;
  USE SIGNAL ;
  PORT
   LAYER M5 ;
   RECT 175.9200 630.6360 175.9440 630.7200 ;
  END
 END li_d[48]
 PIN li_d[49]
  DIRECTION OUTPUT ;
  USE SIGNAL ;
  PORT
   LAYER M5 ;
   RECT 176.1600 630.6360 176.1840 630.7200 ;
  END
 END li_d[49]
 PIN li_d[50]
  DIRECTION OUTPUT ;
  USE SIGNAL ;
  PORT
   LAYER M5 ;
   RECT 176.4000 630.6360 176.4240 630.7200 ;
  END
 END li_d[50]
 PIN li_d[51]
  DIRECTION OUTPUT ;
  USE SIGNAL ;
  PORT
   LAYER M5 ;
   RECT 176.6400 630.6360 176.6640 630.7200 ;
  END
 END li_d[51]
 PIN li_d[52]
  DIRECTION OUTPUT ;
  USE SIGNAL ;
  PORT
   LAYER M5 ;
   RECT 176.8800 630.6360 176.9040 630.7200 ;
  END
 END li_d[52]
 PIN li_d[53]
  DIRECTION OUTPUT ;
  USE SIGNAL ;
  PORT
   LAYER M5 ;
   RECT 177.1200 630.6360 177.1440 630.7200 ;
  END
 END li_d[53]
 PIN li_d[54]
  DIRECTION OUTPUT ;
  USE SIGNAL ;
  PORT
   LAYER M5 ;
   RECT 177.3600 630.6360 177.3840 630.7200 ;
  END
 END li_d[54]
 PIN li_d[55]
  DIRECTION OUTPUT ;
  USE SIGNAL ;
  PORT
   LAYER M5 ;
   RECT 177.6000 630.6360 177.6240 630.7200 ;
  END
 END li_d[55]
 PIN li_d[56]
  DIRECTION OUTPUT ;
  USE SIGNAL ;
  PORT
   LAYER M5 ;
   RECT 177.8400 630.6360 177.8640 630.7200 ;
  END
 END li_d[56]
 PIN li_d[57]
  DIRECTION OUTPUT ;
  USE SIGNAL ;
  PORT
   LAYER M5 ;
   RECT 178.0800 630.6360 178.1040 630.7200 ;
  END
 END li_d[57]
 PIN li_d[58]
  DIRECTION OUTPUT ;
  USE SIGNAL ;
  PORT
   LAYER M5 ;
   RECT 178.3200 630.6360 178.3440 630.7200 ;
  END
 END li_d[58]
 PIN li_d[59]
  DIRECTION OUTPUT ;
  USE SIGNAL ;
  PORT
   LAYER M5 ;
   RECT 178.5600 630.6360 178.5840 630.7200 ;
  END
 END li_d[59]
 PIN li_d[60]
  DIRECTION OUTPUT ;
  USE SIGNAL ;
  PORT
   LAYER M5 ;
   RECT 178.8000 630.6360 178.8240 630.7200 ;
  END
 END li_d[60]
 PIN li_d[61]
  DIRECTION OUTPUT ;
  USE SIGNAL ;
  PORT
   LAYER M5 ;
   RECT 179.0400 630.6360 179.0640 630.7200 ;
  END
 END li_d[61]
 PIN li_d[62]
  DIRECTION OUTPUT ;
  USE SIGNAL ;
  PORT
   LAYER M5 ;
   RECT 179.2800 630.6360 179.3040 630.7200 ;
  END
 END li_d[62]
 PIN li_d[63]
  DIRECTION OUTPUT ;
  USE SIGNAL ;
  PORT
   LAYER M5 ;
   RECT 179.5200 630.6360 179.5440 630.7200 ;
  END
 END li_d[63]
 PIN li_d[64]
  DIRECTION OUTPUT ;
  USE SIGNAL ;
  PORT
   LAYER M5 ;
   RECT 179.7600 630.6360 179.7840 630.7200 ;
  END
 END li_d[64]
 PIN li_d[65]
  DIRECTION OUTPUT ;
  USE SIGNAL ;
  PORT
   LAYER M5 ;
   RECT 180.0000 630.6360 180.0240 630.7200 ;
  END
 END li_d[65]
 PIN li_d[66]
  DIRECTION OUTPUT ;
  USE SIGNAL ;
  PORT
   LAYER M5 ;
   RECT 180.2400 630.6360 180.2640 630.7200 ;
  END
 END li_d[66]
 PIN li_d[67]
  DIRECTION OUTPUT ;
  USE SIGNAL ;
  PORT
   LAYER M5 ;
   RECT 180.4800 630.6360 180.5040 630.7200 ;
  END
 END li_d[67]
 PIN li_d[68]
  DIRECTION OUTPUT ;
  USE SIGNAL ;
  PORT
   LAYER M5 ;
   RECT 180.7200 630.6360 180.7440 630.7200 ;
  END
 END li_d[68]
 PIN li_d[69]
  DIRECTION OUTPUT ;
  USE SIGNAL ;
  PORT
   LAYER M5 ;
   RECT 180.9600 630.6360 180.9840 630.7200 ;
  END
 END li_d[69]
 PIN li_d[70]
  DIRECTION OUTPUT ;
  USE SIGNAL ;
  PORT
   LAYER M5 ;
   RECT 181.2000 630.6360 181.2240 630.7200 ;
  END
 END li_d[70]
 PIN li_d[71]
  DIRECTION OUTPUT ;
  USE SIGNAL ;
  PORT
   LAYER M5 ;
   RECT 181.4400 630.6360 181.4640 630.7200 ;
  END
 END li_d[71]
 PIN li_d[72]
  DIRECTION OUTPUT ;
  USE SIGNAL ;
  PORT
   LAYER M5 ;
   RECT 181.6800 630.6360 181.7040 630.7200 ;
  END
 END li_d[72]
 PIN li_d[73]
  DIRECTION OUTPUT ;
  USE SIGNAL ;
  PORT
   LAYER M5 ;
   RECT 181.9200 630.6360 181.9440 630.7200 ;
  END
 END li_d[73]
 PIN li_d[74]
  DIRECTION OUTPUT ;
  USE SIGNAL ;
  PORT
   LAYER M5 ;
   RECT 182.1600 630.6360 182.1840 630.7200 ;
  END
 END li_d[74]
 PIN li_d[75]
  DIRECTION OUTPUT ;
  USE SIGNAL ;
  PORT
   LAYER M5 ;
   RECT 182.4000 630.6360 182.4240 630.7200 ;
  END
 END li_d[75]
 PIN li_d[76]
  DIRECTION OUTPUT ;
  USE SIGNAL ;
  PORT
   LAYER M5 ;
   RECT 182.6400 630.6360 182.6640 630.7200 ;
  END
 END li_d[76]
 PIN li_d[77]
  DIRECTION OUTPUT ;
  USE SIGNAL ;
  PORT
   LAYER M5 ;
   RECT 182.8800 630.6360 182.9040 630.7200 ;
  END
 END li_d[77]
 PIN li_d[78]
  DIRECTION OUTPUT ;
  USE SIGNAL ;
  PORT
   LAYER M5 ;
   RECT 183.1200 630.6360 183.1440 630.7200 ;
  END
 END li_d[78]
 PIN li_d[79]
  DIRECTION OUTPUT ;
  USE SIGNAL ;
  PORT
   LAYER M5 ;
   RECT 183.3600 630.6360 183.3840 630.7200 ;
  END
 END li_d[79]
 PIN li_d[80]
  DIRECTION OUTPUT ;
  USE SIGNAL ;
  PORT
   LAYER M5 ;
   RECT 183.6000 630.6360 183.6240 630.7200 ;
  END
 END li_d[80]
 PIN li_d[81]
  DIRECTION OUTPUT ;
  USE SIGNAL ;
  PORT
   LAYER M5 ;
   RECT 183.8400 630.6360 183.8640 630.7200 ;
  END
 END li_d[81]
 PIN li_d[82]
  DIRECTION OUTPUT ;
  USE SIGNAL ;
  PORT
   LAYER M5 ;
   RECT 184.0800 630.6360 184.1040 630.7200 ;
  END
 END li_d[82]
 PIN li_d[83]
  DIRECTION OUTPUT ;
  USE SIGNAL ;
  PORT
   LAYER M5 ;
   RECT 184.3200 630.6360 184.3440 630.7200 ;
  END
 END li_d[83]
 PIN li_d[84]
  DIRECTION OUTPUT ;
  USE SIGNAL ;
  PORT
   LAYER M5 ;
   RECT 184.5600 630.6360 184.5840 630.7200 ;
  END
 END li_d[84]
 PIN li_d[85]
  DIRECTION OUTPUT ;
  USE SIGNAL ;
  PORT
   LAYER M5 ;
   RECT 184.8000 630.6360 184.8240 630.7200 ;
  END
 END li_d[85]
 PIN li_d[86]
  DIRECTION OUTPUT ;
  USE SIGNAL ;
  PORT
   LAYER M5 ;
   RECT 185.0400 630.6360 185.0640 630.7200 ;
  END
 END li_d[86]
 PIN li_d[87]
  DIRECTION OUTPUT ;
  USE SIGNAL ;
  PORT
   LAYER M5 ;
   RECT 185.2800 630.6360 185.3040 630.7200 ;
  END
 END li_d[87]
 PIN li_d[88]
  DIRECTION OUTPUT ;
  USE SIGNAL ;
  PORT
   LAYER M5 ;
   RECT 185.5200 630.6360 185.5440 630.7200 ;
  END
 END li_d[88]
 PIN li_d[89]
  DIRECTION OUTPUT ;
  USE SIGNAL ;
  PORT
   LAYER M5 ;
   RECT 185.7600 630.6360 185.7840 630.7200 ;
  END
 END li_d[89]
 PIN li_d[90]
  DIRECTION OUTPUT ;
  USE SIGNAL ;
  PORT
   LAYER M5 ;
   RECT 186.0000 630.6360 186.0240 630.7200 ;
  END
 END li_d[90]
 PIN li_d[91]
  DIRECTION OUTPUT ;
  USE SIGNAL ;
  PORT
   LAYER M5 ;
   RECT 186.2400 630.6360 186.2640 630.7200 ;
  END
 END li_d[91]
 PIN li_d[92]
  DIRECTION OUTPUT ;
  USE SIGNAL ;
  PORT
   LAYER M5 ;
   RECT 186.4800 630.6360 186.5040 630.7200 ;
  END
 END li_d[92]
 PIN li_d[93]
  DIRECTION OUTPUT ;
  USE SIGNAL ;
  PORT
   LAYER M5 ;
   RECT 186.7200 630.6360 186.7440 630.7200 ;
  END
 END li_d[93]
 PIN li_d[94]
  DIRECTION OUTPUT ;
  USE SIGNAL ;
  PORT
   LAYER M5 ;
   RECT 186.9600 630.6360 186.9840 630.7200 ;
  END
 END li_d[94]
 PIN li_d[95]
  DIRECTION OUTPUT ;
  USE SIGNAL ;
  PORT
   LAYER M5 ;
   RECT 187.2000 630.6360 187.2240 630.7200 ;
  END
 END li_d[95]
 PIN li_d[96]
  DIRECTION OUTPUT ;
  USE SIGNAL ;
  PORT
   LAYER M5 ;
   RECT 187.4400 630.6360 187.4640 630.7200 ;
  END
 END li_d[96]
 PIN li_d[97]
  DIRECTION OUTPUT ;
  USE SIGNAL ;
  PORT
   LAYER M5 ;
   RECT 187.6800 630.6360 187.7040 630.7200 ;
  END
 END li_d[97]
 PIN li_d[98]
  DIRECTION OUTPUT ;
  USE SIGNAL ;
  PORT
   LAYER M5 ;
   RECT 187.9200 630.6360 187.9440 630.7200 ;
  END
 END li_d[98]
 PIN li_d[99]
  DIRECTION OUTPUT ;
  USE SIGNAL ;
  PORT
   LAYER M5 ;
   RECT 188.1600 630.6360 188.1840 630.7200 ;
  END
 END li_d[99]
 PIN li_d[100]
  DIRECTION OUTPUT ;
  USE SIGNAL ;
  PORT
   LAYER M5 ;
   RECT 188.4000 630.6360 188.4240 630.7200 ;
  END
 END li_d[100]
 PIN li_d[101]
  DIRECTION OUTPUT ;
  USE SIGNAL ;
  PORT
   LAYER M5 ;
   RECT 188.6400 630.6360 188.6640 630.7200 ;
  END
 END li_d[101]
 PIN li_d[102]
  DIRECTION OUTPUT ;
  USE SIGNAL ;
  PORT
   LAYER M5 ;
   RECT 188.8800 630.6360 188.9040 630.7200 ;
  END
 END li_d[102]
 PIN li_d[103]
  DIRECTION OUTPUT ;
  USE SIGNAL ;
  PORT
   LAYER M5 ;
   RECT 189.1200 630.6360 189.1440 630.7200 ;
  END
 END li_d[103]
 PIN li_d[104]
  DIRECTION OUTPUT ;
  USE SIGNAL ;
  PORT
   LAYER M5 ;
   RECT 189.3600 630.6360 189.3840 630.7200 ;
  END
 END li_d[104]
 PIN li_d[105]
  DIRECTION OUTPUT ;
  USE SIGNAL ;
  PORT
   LAYER M5 ;
   RECT 189.6000 630.6360 189.6240 630.7200 ;
  END
 END li_d[105]
 PIN li_d[106]
  DIRECTION OUTPUT ;
  USE SIGNAL ;
  PORT
   LAYER M5 ;
   RECT 189.8400 630.6360 189.8640 630.7200 ;
  END
 END li_d[106]
 PIN li_d[107]
  DIRECTION OUTPUT ;
  USE SIGNAL ;
  PORT
   LAYER M5 ;
   RECT 190.0800 630.6360 190.1040 630.7200 ;
  END
 END li_d[107]
 PIN li_d[108]
  DIRECTION OUTPUT ;
  USE SIGNAL ;
  PORT
   LAYER M5 ;
   RECT 190.3200 630.6360 190.3440 630.7200 ;
  END
 END li_d[108]
 PIN li_d[109]
  DIRECTION OUTPUT ;
  USE SIGNAL ;
  PORT
   LAYER M5 ;
   RECT 190.5600 630.6360 190.5840 630.7200 ;
  END
 END li_d[109]
 PIN li_d[110]
  DIRECTION OUTPUT ;
  USE SIGNAL ;
  PORT
   LAYER M5 ;
   RECT 190.8000 630.6360 190.8240 630.7200 ;
  END
 END li_d[110]
 PIN li_d[111]
  DIRECTION OUTPUT ;
  USE SIGNAL ;
  PORT
   LAYER M5 ;
   RECT 191.0400 630.6360 191.0640 630.7200 ;
  END
 END li_d[111]
 PIN li_d[112]
  DIRECTION OUTPUT ;
  USE SIGNAL ;
  PORT
   LAYER M5 ;
   RECT 191.2800 630.6360 191.3040 630.7200 ;
  END
 END li_d[112]
 PIN li_d[113]
  DIRECTION OUTPUT ;
  USE SIGNAL ;
  PORT
   LAYER M5 ;
   RECT 191.5200 630.6360 191.5440 630.7200 ;
  END
 END li_d[113]
 PIN li_d[114]
  DIRECTION OUTPUT ;
  USE SIGNAL ;
  PORT
   LAYER M5 ;
   RECT 191.7600 630.6360 191.7840 630.7200 ;
  END
 END li_d[114]
 PIN li_d[115]
  DIRECTION OUTPUT ;
  USE SIGNAL ;
  PORT
   LAYER M5 ;
   RECT 192.0000 630.6360 192.0240 630.7200 ;
  END
 END li_d[115]
 PIN li_d[116]
  DIRECTION OUTPUT ;
  USE SIGNAL ;
  PORT
   LAYER M5 ;
   RECT 192.2400 630.6360 192.2640 630.7200 ;
  END
 END li_d[116]
 PIN li_d[117]
  DIRECTION OUTPUT ;
  USE SIGNAL ;
  PORT
   LAYER M5 ;
   RECT 192.4800 630.6360 192.5040 630.7200 ;
  END
 END li_d[117]
 PIN li_d[118]
  DIRECTION OUTPUT ;
  USE SIGNAL ;
  PORT
   LAYER M5 ;
   RECT 192.7200 630.6360 192.7440 630.7200 ;
  END
 END li_d[118]
 PIN li_d[119]
  DIRECTION OUTPUT ;
  USE SIGNAL ;
  PORT
   LAYER M5 ;
   RECT 192.9600 630.6360 192.9840 630.7200 ;
  END
 END li_d[119]
 PIN li_d[120]
  DIRECTION OUTPUT ;
  USE SIGNAL ;
  PORT
   LAYER M5 ;
   RECT 193.2000 630.6360 193.2240 630.7200 ;
  END
 END li_d[120]
 PIN li_d[121]
  DIRECTION OUTPUT ;
  USE SIGNAL ;
  PORT
   LAYER M5 ;
   RECT 193.4400 630.6360 193.4640 630.7200 ;
  END
 END li_d[121]
 PIN li_d[122]
  DIRECTION OUTPUT ;
  USE SIGNAL ;
  PORT
   LAYER M5 ;
   RECT 193.6800 630.6360 193.7040 630.7200 ;
  END
 END li_d[122]
 PIN li_d[123]
  DIRECTION OUTPUT ;
  USE SIGNAL ;
  PORT
   LAYER M5 ;
   RECT 193.9200 630.6360 193.9440 630.7200 ;
  END
 END li_d[123]
 PIN li_d[124]
  DIRECTION OUTPUT ;
  USE SIGNAL ;
  PORT
   LAYER M5 ;
   RECT 194.1600 630.6360 194.1840 630.7200 ;
  END
 END li_d[124]
 PIN li_d[125]
  DIRECTION OUTPUT ;
  USE SIGNAL ;
  PORT
   LAYER M5 ;
   RECT 194.4000 630.6360 194.4240 630.7200 ;
  END
 END li_d[125]
 PIN li_d[126]
  DIRECTION OUTPUT ;
  USE SIGNAL ;
  PORT
   LAYER M5 ;
   RECT 194.6400 630.6360 194.6640 630.7200 ;
  END
 END li_d[126]
 PIN li_d[127]
  DIRECTION OUTPUT ;
  USE SIGNAL ;
  PORT
   LAYER M5 ;
   RECT 194.8800 630.6360 194.9040 630.7200 ;
  END
 END li_d[127]
 PIN li_d[128]
  DIRECTION OUTPUT ;
  USE SIGNAL ;
  PORT
   LAYER M5 ;
   RECT 195.1200 630.6360 195.1440 630.7200 ;
  END
 END li_d[128]
 PIN li_d[129]
  DIRECTION OUTPUT ;
  USE SIGNAL ;
  PORT
   LAYER M5 ;
   RECT 195.3600 630.6360 195.3840 630.7200 ;
  END
 END li_d[129]
 PIN li_d[130]
  DIRECTION OUTPUT ;
  USE SIGNAL ;
  PORT
   LAYER M5 ;
   RECT 195.6000 630.6360 195.6240 630.7200 ;
  END
 END li_d[130]
 PIN li_d[131]
  DIRECTION OUTPUT ;
  USE SIGNAL ;
  PORT
   LAYER M5 ;
   RECT 195.8400 630.6360 195.8640 630.7200 ;
  END
 END li_d[131]
 PIN li_d[132]
  DIRECTION OUTPUT ;
  USE SIGNAL ;
  PORT
   LAYER M5 ;
   RECT 196.0800 630.6360 196.1040 630.7200 ;
  END
 END li_d[132]
 PIN li_d[133]
  DIRECTION OUTPUT ;
  USE SIGNAL ;
  PORT
   LAYER M5 ;
   RECT 196.3200 630.6360 196.3440 630.7200 ;
  END
 END li_d[133]
 PIN li_d[134]
  DIRECTION OUTPUT ;
  USE SIGNAL ;
  PORT
   LAYER M5 ;
   RECT 196.5600 630.6360 196.5840 630.7200 ;
  END
 END li_d[134]
 PIN li_d[135]
  DIRECTION OUTPUT ;
  USE SIGNAL ;
  PORT
   LAYER M5 ;
   RECT 196.8000 630.6360 196.8240 630.7200 ;
  END
 END li_d[135]
 PIN li_d[136]
  DIRECTION OUTPUT ;
  USE SIGNAL ;
  PORT
   LAYER M5 ;
   RECT 197.0400 630.6360 197.0640 630.7200 ;
  END
 END li_d[136]
 PIN li_d[137]
  DIRECTION OUTPUT ;
  USE SIGNAL ;
  PORT
   LAYER M5 ;
   RECT 197.2800 630.6360 197.3040 630.7200 ;
  END
 END li_d[137]
 PIN li_d[138]
  DIRECTION OUTPUT ;
  USE SIGNAL ;
  PORT
   LAYER M5 ;
   RECT 197.5200 630.6360 197.5440 630.7200 ;
  END
 END li_d[138]
 PIN li_d[139]
  DIRECTION OUTPUT ;
  USE SIGNAL ;
  PORT
   LAYER M5 ;
   RECT 197.7600 630.6360 197.7840 630.7200 ;
  END
 END li_d[139]
 PIN li_d[140]
  DIRECTION OUTPUT ;
  USE SIGNAL ;
  PORT
   LAYER M5 ;
   RECT 198.0000 630.6360 198.0240 630.7200 ;
  END
 END li_d[140]
 PIN li_d[141]
  DIRECTION OUTPUT ;
  USE SIGNAL ;
  PORT
   LAYER M5 ;
   RECT 198.2400 630.6360 198.2640 630.7200 ;
  END
 END li_d[141]
 PIN li_d[142]
  DIRECTION OUTPUT ;
  USE SIGNAL ;
  PORT
   LAYER M5 ;
   RECT 198.4800 630.6360 198.5040 630.7200 ;
  END
 END li_d[142]
 PIN li_d[143]
  DIRECTION OUTPUT ;
  USE SIGNAL ;
  PORT
   LAYER M5 ;
   RECT 198.7200 630.6360 198.7440 630.7200 ;
  END
 END li_d[143]
 PIN li_d[144]
  DIRECTION OUTPUT ;
  USE SIGNAL ;
  PORT
   LAYER M5 ;
   RECT 198.9600 630.6360 198.9840 630.7200 ;
  END
 END li_d[144]
 PIN li_d[145]
  DIRECTION OUTPUT ;
  USE SIGNAL ;
  PORT
   LAYER M5 ;
   RECT 199.2000 630.6360 199.2240 630.7200 ;
  END
 END li_d[145]
 PIN li_d[146]
  DIRECTION OUTPUT ;
  USE SIGNAL ;
  PORT
   LAYER M5 ;
   RECT 199.4400 630.6360 199.4640 630.7200 ;
  END
 END li_d[146]
 PIN li_d[147]
  DIRECTION OUTPUT ;
  USE SIGNAL ;
  PORT
   LAYER M5 ;
   RECT 199.6800 630.6360 199.7040 630.7200 ;
  END
 END li_d[147]
 PIN li_d[148]
  DIRECTION OUTPUT ;
  USE SIGNAL ;
  PORT
   LAYER M5 ;
   RECT 199.9200 630.6360 199.9440 630.7200 ;
  END
 END li_d[148]
 PIN li_d[149]
  DIRECTION OUTPUT ;
  USE SIGNAL ;
  PORT
   LAYER M5 ;
   RECT 200.1600 630.6360 200.1840 630.7200 ;
  END
 END li_d[149]
 PIN li_d[150]
  DIRECTION OUTPUT ;
  USE SIGNAL ;
  PORT
   LAYER M5 ;
   RECT 200.4000 630.6360 200.4240 630.7200 ;
  END
 END li_d[150]
 PIN li_d[151]
  DIRECTION OUTPUT ;
  USE SIGNAL ;
  PORT
   LAYER M5 ;
   RECT 200.6400 630.6360 200.6640 630.7200 ;
  END
 END li_d[151]
 PIN li_d[152]
  DIRECTION OUTPUT ;
  USE SIGNAL ;
  PORT
   LAYER M5 ;
   RECT 200.8800 630.6360 200.9040 630.7200 ;
  END
 END li_d[152]
 PIN li_d[153]
  DIRECTION OUTPUT ;
  USE SIGNAL ;
  PORT
   LAYER M5 ;
   RECT 201.1200 630.6360 201.1440 630.7200 ;
  END
 END li_d[153]
 PIN li_d[154]
  DIRECTION OUTPUT ;
  USE SIGNAL ;
  PORT
   LAYER M5 ;
   RECT 201.3600 630.6360 201.3840 630.7200 ;
  END
 END li_d[154]
 PIN li_d[155]
  DIRECTION OUTPUT ;
  USE SIGNAL ;
  PORT
   LAYER M5 ;
   RECT 201.6000 630.6360 201.6240 630.7200 ;
  END
 END li_d[155]
 PIN li_d[156]
  DIRECTION OUTPUT ;
  USE SIGNAL ;
  PORT
   LAYER M5 ;
   RECT 201.8400 630.6360 201.8640 630.7200 ;
  END
 END li_d[156]
 PIN li_d[157]
  DIRECTION OUTPUT ;
  USE SIGNAL ;
  PORT
   LAYER M5 ;
   RECT 202.0800 630.6360 202.1040 630.7200 ;
  END
 END li_d[157]
 PIN li_d[158]
  DIRECTION OUTPUT ;
  USE SIGNAL ;
  PORT
   LAYER M5 ;
   RECT 202.3200 630.6360 202.3440 630.7200 ;
  END
 END li_d[158]
 PIN li_d[159]
  DIRECTION OUTPUT ;
  USE SIGNAL ;
  PORT
   LAYER M5 ;
   RECT 202.5600 630.6360 202.5840 630.7200 ;
  END
 END li_d[159]
 PIN li_d[160]
  DIRECTION OUTPUT ;
  USE SIGNAL ;
  PORT
   LAYER M5 ;
   RECT 202.8000 630.6360 202.8240 630.7200 ;
  END
 END li_d[160]
 PIN li_d[161]
  DIRECTION OUTPUT ;
  USE SIGNAL ;
  PORT
   LAYER M5 ;
   RECT 203.0400 630.6360 203.0640 630.7200 ;
  END
 END li_d[161]
 PIN li_d[162]
  DIRECTION OUTPUT ;
  USE SIGNAL ;
  PORT
   LAYER M5 ;
   RECT 203.2800 630.6360 203.3040 630.7200 ;
  END
 END li_d[162]
 PIN li_d[163]
  DIRECTION OUTPUT ;
  USE SIGNAL ;
  PORT
   LAYER M5 ;
   RECT 203.5200 630.6360 203.5440 630.7200 ;
  END
 END li_d[163]
 PIN li_d[164]
  DIRECTION OUTPUT ;
  USE SIGNAL ;
  PORT
   LAYER M5 ;
   RECT 203.7600 630.6360 203.7840 630.7200 ;
  END
 END li_d[164]
 PIN li_d[165]
  DIRECTION OUTPUT ;
  USE SIGNAL ;
  PORT
   LAYER M5 ;
   RECT 204.0000 630.6360 204.0240 630.7200 ;
  END
 END li_d[165]
 PIN li_d[166]
  DIRECTION OUTPUT ;
  USE SIGNAL ;
  PORT
   LAYER M5 ;
   RECT 204.2400 630.6360 204.2640 630.7200 ;
  END
 END li_d[166]
 PIN li_d[167]
  DIRECTION OUTPUT ;
  USE SIGNAL ;
  PORT
   LAYER M5 ;
   RECT 204.4800 630.6360 204.5040 630.7200 ;
  END
 END li_d[167]
 PIN li_d[168]
  DIRECTION OUTPUT ;
  USE SIGNAL ;
  PORT
   LAYER M5 ;
   RECT 204.7200 630.6360 204.7440 630.7200 ;
  END
 END li_d[168]
 PIN li_d[169]
  DIRECTION OUTPUT ;
  USE SIGNAL ;
  PORT
   LAYER M5 ;
   RECT 204.9600 630.6360 204.9840 630.7200 ;
  END
 END li_d[169]
 PIN li_d[170]
  DIRECTION OUTPUT ;
  USE SIGNAL ;
  PORT
   LAYER M5 ;
   RECT 205.2000 630.6360 205.2240 630.7200 ;
  END
 END li_d[170]
 PIN li_d[171]
  DIRECTION OUTPUT ;
  USE SIGNAL ;
  PORT
   LAYER M5 ;
   RECT 205.4400 630.6360 205.4640 630.7200 ;
  END
 END li_d[171]
 PIN li_d[172]
  DIRECTION OUTPUT ;
  USE SIGNAL ;
  PORT
   LAYER M5 ;
   RECT 205.6800 630.6360 205.7040 630.7200 ;
  END
 END li_d[172]
 PIN li_d[173]
  DIRECTION OUTPUT ;
  USE SIGNAL ;
  PORT
   LAYER M5 ;
   RECT 205.9200 630.6360 205.9440 630.7200 ;
  END
 END li_d[173]
 PIN li_d[174]
  DIRECTION OUTPUT ;
  USE SIGNAL ;
  PORT
   LAYER M5 ;
   RECT 206.1600 630.6360 206.1840 630.7200 ;
  END
 END li_d[174]
 PIN li_d[175]
  DIRECTION OUTPUT ;
  USE SIGNAL ;
  PORT
   LAYER M5 ;
   RECT 206.4000 630.6360 206.4240 630.7200 ;
  END
 END li_d[175]
 PIN li_d[176]
  DIRECTION OUTPUT ;
  USE SIGNAL ;
  PORT
   LAYER M5 ;
   RECT 206.6400 630.6360 206.6640 630.7200 ;
  END
 END li_d[176]
 PIN li_d[177]
  DIRECTION OUTPUT ;
  USE SIGNAL ;
  PORT
   LAYER M5 ;
   RECT 206.8800 630.6360 206.9040 630.7200 ;
  END
 END li_d[177]
 PIN li_d[178]
  DIRECTION OUTPUT ;
  USE SIGNAL ;
  PORT
   LAYER M5 ;
   RECT 207.1200 630.6360 207.1440 630.7200 ;
  END
 END li_d[178]
 PIN li_d[179]
  DIRECTION OUTPUT ;
  USE SIGNAL ;
  PORT
   LAYER M5 ;
   RECT 207.3600 630.6360 207.3840 630.7200 ;
  END
 END li_d[179]
 PIN li_d[180]
  DIRECTION OUTPUT ;
  USE SIGNAL ;
  PORT
   LAYER M5 ;
   RECT 207.6000 630.6360 207.6240 630.7200 ;
  END
 END li_d[180]
 PIN li_d[181]
  DIRECTION OUTPUT ;
  USE SIGNAL ;
  PORT
   LAYER M5 ;
   RECT 207.8400 630.6360 207.8640 630.7200 ;
  END
 END li_d[181]
 PIN li_d[182]
  DIRECTION OUTPUT ;
  USE SIGNAL ;
  PORT
   LAYER M5 ;
   RECT 208.0800 630.6360 208.1040 630.7200 ;
  END
 END li_d[182]
 PIN li_d[183]
  DIRECTION OUTPUT ;
  USE SIGNAL ;
  PORT
   LAYER M5 ;
   RECT 208.3200 630.6360 208.3440 630.7200 ;
  END
 END li_d[183]
 PIN li_d[184]
  DIRECTION OUTPUT ;
  USE SIGNAL ;
  PORT
   LAYER M5 ;
   RECT 208.5600 630.6360 208.5840 630.7200 ;
  END
 END li_d[184]
 PIN li_d[185]
  DIRECTION OUTPUT ;
  USE SIGNAL ;
  PORT
   LAYER M5 ;
   RECT 208.8000 630.6360 208.8240 630.7200 ;
  END
 END li_d[185]
 PIN li_d[186]
  DIRECTION OUTPUT ;
  USE SIGNAL ;
  PORT
   LAYER M5 ;
   RECT 209.0400 630.6360 209.0640 630.7200 ;
  END
 END li_d[186]
 PIN li_d[187]
  DIRECTION OUTPUT ;
  USE SIGNAL ;
  PORT
   LAYER M5 ;
   RECT 209.2800 630.6360 209.3040 630.7200 ;
  END
 END li_d[187]
 PIN li_d[188]
  DIRECTION OUTPUT ;
  USE SIGNAL ;
  PORT
   LAYER M5 ;
   RECT 209.5200 630.6360 209.5440 630.7200 ;
  END
 END li_d[188]
 PIN li_d[189]
  DIRECTION OUTPUT ;
  USE SIGNAL ;
  PORT
   LAYER M5 ;
   RECT 209.7600 630.6360 209.7840 630.7200 ;
  END
 END li_d[189]
 PIN li_d[190]
  DIRECTION OUTPUT ;
  USE SIGNAL ;
  PORT
   LAYER M5 ;
   RECT 210.0000 630.6360 210.0240 630.7200 ;
  END
 END li_d[190]
 PIN li_d[191]
  DIRECTION OUTPUT ;
  USE SIGNAL ;
  PORT
   LAYER M5 ;
   RECT 210.2400 630.6360 210.2640 630.7200 ;
  END
 END li_d[191]
 PIN li_d[192]
  DIRECTION OUTPUT ;
  USE SIGNAL ;
  PORT
   LAYER M5 ;
   RECT 210.4800 630.6360 210.5040 630.7200 ;
  END
 END li_d[192]
 PIN li_d[193]
  DIRECTION OUTPUT ;
  USE SIGNAL ;
  PORT
   LAYER M5 ;
   RECT 210.7200 630.6360 210.7440 630.7200 ;
  END
 END li_d[193]
 PIN li_d[194]
  DIRECTION OUTPUT ;
  USE SIGNAL ;
  PORT
   LAYER M5 ;
   RECT 210.9600 630.6360 210.9840 630.7200 ;
  END
 END li_d[194]
 PIN li_d[195]
  DIRECTION OUTPUT ;
  USE SIGNAL ;
  PORT
   LAYER M5 ;
   RECT 211.2000 630.6360 211.2240 630.7200 ;
  END
 END li_d[195]
 PIN li_d[196]
  DIRECTION OUTPUT ;
  USE SIGNAL ;
  PORT
   LAYER M5 ;
   RECT 211.4400 630.6360 211.4640 630.7200 ;
  END
 END li_d[196]
 PIN li_d[197]
  DIRECTION OUTPUT ;
  USE SIGNAL ;
  PORT
   LAYER M5 ;
   RECT 211.6800 630.6360 211.7040 630.7200 ;
  END
 END li_d[197]
 PIN li_d[198]
  DIRECTION OUTPUT ;
  USE SIGNAL ;
  PORT
   LAYER M5 ;
   RECT 211.9200 630.6360 211.9440 630.7200 ;
  END
 END li_d[198]
 PIN li_d[199]
  DIRECTION OUTPUT ;
  USE SIGNAL ;
  PORT
   LAYER M5 ;
   RECT 212.1600 630.6360 212.1840 630.7200 ;
  END
 END li_d[199]
 PIN li_d[200]
  DIRECTION OUTPUT ;
  USE SIGNAL ;
  PORT
   LAYER M5 ;
   RECT 212.4000 630.6360 212.4240 630.7200 ;
  END
 END li_d[200]
 PIN li_d[201]
  DIRECTION OUTPUT ;
  USE SIGNAL ;
  PORT
   LAYER M5 ;
   RECT 212.6400 630.6360 212.6640 630.7200 ;
  END
 END li_d[201]
 PIN li_d[202]
  DIRECTION OUTPUT ;
  USE SIGNAL ;
  PORT
   LAYER M5 ;
   RECT 212.8800 630.6360 212.9040 630.7200 ;
  END
 END li_d[202]
 PIN li_d[203]
  DIRECTION OUTPUT ;
  USE SIGNAL ;
  PORT
   LAYER M5 ;
   RECT 213.1200 630.6360 213.1440 630.7200 ;
  END
 END li_d[203]
 PIN li_d[204]
  DIRECTION OUTPUT ;
  USE SIGNAL ;
  PORT
   LAYER M5 ;
   RECT 213.3600 630.6360 213.3840 630.7200 ;
  END
 END li_d[204]
 PIN li_d[205]
  DIRECTION OUTPUT ;
  USE SIGNAL ;
  PORT
   LAYER M5 ;
   RECT 213.6000 630.6360 213.6240 630.7200 ;
  END
 END li_d[205]
 PIN li_d[206]
  DIRECTION OUTPUT ;
  USE SIGNAL ;
  PORT
   LAYER M5 ;
   RECT 213.8400 630.6360 213.8640 630.7200 ;
  END
 END li_d[206]
 PIN li_d[207]
  DIRECTION OUTPUT ;
  USE SIGNAL ;
  PORT
   LAYER M5 ;
   RECT 214.0800 630.6360 214.1040 630.7200 ;
  END
 END li_d[207]
 PIN li_d[208]
  DIRECTION OUTPUT ;
  USE SIGNAL ;
  PORT
   LAYER M5 ;
   RECT 214.3200 630.6360 214.3440 630.7200 ;
  END
 END li_d[208]
 PIN li_d[209]
  DIRECTION OUTPUT ;
  USE SIGNAL ;
  PORT
   LAYER M5 ;
   RECT 214.5600 630.6360 214.5840 630.7200 ;
  END
 END li_d[209]
 PIN li_d[210]
  DIRECTION OUTPUT ;
  USE SIGNAL ;
  PORT
   LAYER M5 ;
   RECT 214.8000 630.6360 214.8240 630.7200 ;
  END
 END li_d[210]
 PIN li_d[211]
  DIRECTION OUTPUT ;
  USE SIGNAL ;
  PORT
   LAYER M5 ;
   RECT 215.0400 630.6360 215.0640 630.7200 ;
  END
 END li_d[211]
 PIN li_d[212]
  DIRECTION OUTPUT ;
  USE SIGNAL ;
  PORT
   LAYER M5 ;
   RECT 215.2800 630.6360 215.3040 630.7200 ;
  END
 END li_d[212]
 PIN li_d[213]
  DIRECTION OUTPUT ;
  USE SIGNAL ;
  PORT
   LAYER M5 ;
   RECT 215.5200 630.6360 215.5440 630.7200 ;
  END
 END li_d[213]
 PIN li_d[214]
  DIRECTION OUTPUT ;
  USE SIGNAL ;
  PORT
   LAYER M5 ;
   RECT 215.7600 630.6360 215.7840 630.7200 ;
  END
 END li_d[214]
 PIN li_d[215]
  DIRECTION OUTPUT ;
  USE SIGNAL ;
  PORT
   LAYER M5 ;
   RECT 216.0000 630.6360 216.0240 630.7200 ;
  END
 END li_d[215]
 PIN li_d[216]
  DIRECTION OUTPUT ;
  USE SIGNAL ;
  PORT
   LAYER M5 ;
   RECT 216.2400 630.6360 216.2640 630.7200 ;
  END
 END li_d[216]
 PIN li_d[217]
  DIRECTION OUTPUT ;
  USE SIGNAL ;
  PORT
   LAYER M5 ;
   RECT 216.4800 630.6360 216.5040 630.7200 ;
  END
 END li_d[217]
 PIN li_d[218]
  DIRECTION OUTPUT ;
  USE SIGNAL ;
  PORT
   LAYER M5 ;
   RECT 216.7200 630.6360 216.7440 630.7200 ;
  END
 END li_d[218]
 PIN li_d[219]
  DIRECTION OUTPUT ;
  USE SIGNAL ;
  PORT
   LAYER M5 ;
   RECT 216.9600 630.6360 216.9840 630.7200 ;
  END
 END li_d[219]
 PIN li_d[220]
  DIRECTION OUTPUT ;
  USE SIGNAL ;
  PORT
   LAYER M5 ;
   RECT 217.2000 630.6360 217.2240 630.7200 ;
  END
 END li_d[220]
 PIN li_d[221]
  DIRECTION OUTPUT ;
  USE SIGNAL ;
  PORT
   LAYER M5 ;
   RECT 217.4400 630.6360 217.4640 630.7200 ;
  END
 END li_d[221]
 PIN li_d[222]
  DIRECTION OUTPUT ;
  USE SIGNAL ;
  PORT
   LAYER M5 ;
   RECT 217.6800 630.6360 217.7040 630.7200 ;
  END
 END li_d[222]
 PIN li_d[223]
  DIRECTION OUTPUT ;
  USE SIGNAL ;
  PORT
   LAYER M5 ;
   RECT 217.9200 630.6360 217.9440 630.7200 ;
  END
 END li_d[223]
 PIN li_d[224]
  DIRECTION OUTPUT ;
  USE SIGNAL ;
  PORT
   LAYER M5 ;
   RECT 218.1600 630.6360 218.1840 630.7200 ;
  END
 END li_d[224]
 PIN li_d[225]
  DIRECTION OUTPUT ;
  USE SIGNAL ;
  PORT
   LAYER M5 ;
   RECT 218.4000 630.6360 218.4240 630.7200 ;
  END
 END li_d[225]
 PIN li_d[226]
  DIRECTION OUTPUT ;
  USE SIGNAL ;
  PORT
   LAYER M5 ;
   RECT 218.6400 630.6360 218.6640 630.7200 ;
  END
 END li_d[226]
 PIN li_d[227]
  DIRECTION OUTPUT ;
  USE SIGNAL ;
  PORT
   LAYER M5 ;
   RECT 218.8800 630.6360 218.9040 630.7200 ;
  END
 END li_d[227]
 PIN li_d[228]
  DIRECTION OUTPUT ;
  USE SIGNAL ;
  PORT
   LAYER M5 ;
   RECT 219.1200 630.6360 219.1440 630.7200 ;
  END
 END li_d[228]
 PIN li_d[229]
  DIRECTION OUTPUT ;
  USE SIGNAL ;
  PORT
   LAYER M5 ;
   RECT 219.3600 630.6360 219.3840 630.7200 ;
  END
 END li_d[229]
 PIN li_d[230]
  DIRECTION OUTPUT ;
  USE SIGNAL ;
  PORT
   LAYER M5 ;
   RECT 219.6000 630.6360 219.6240 630.7200 ;
  END
 END li_d[230]
 PIN li_d[231]
  DIRECTION OUTPUT ;
  USE SIGNAL ;
  PORT
   LAYER M5 ;
   RECT 219.8400 630.6360 219.8640 630.7200 ;
  END
 END li_d[231]
 PIN li_d[232]
  DIRECTION OUTPUT ;
  USE SIGNAL ;
  PORT
   LAYER M5 ;
   RECT 220.0800 630.6360 220.1040 630.7200 ;
  END
 END li_d[232]
 PIN li_d[233]
  DIRECTION OUTPUT ;
  USE SIGNAL ;
  PORT
   LAYER M5 ;
   RECT 220.3200 630.6360 220.3440 630.7200 ;
  END
 END li_d[233]
 PIN li_d[234]
  DIRECTION OUTPUT ;
  USE SIGNAL ;
  PORT
   LAYER M5 ;
   RECT 220.5600 630.6360 220.5840 630.7200 ;
  END
 END li_d[234]
 PIN li_d[235]
  DIRECTION OUTPUT ;
  USE SIGNAL ;
  PORT
   LAYER M5 ;
   RECT 220.8000 630.6360 220.8240 630.7200 ;
  END
 END li_d[235]
 PIN li_d[236]
  DIRECTION OUTPUT ;
  USE SIGNAL ;
  PORT
   LAYER M5 ;
   RECT 221.0400 630.6360 221.0640 630.7200 ;
  END
 END li_d[236]
 PIN li_d[237]
  DIRECTION OUTPUT ;
  USE SIGNAL ;
  PORT
   LAYER M5 ;
   RECT 221.2800 630.6360 221.3040 630.7200 ;
  END
 END li_d[237]
 PIN li_d[238]
  DIRECTION OUTPUT ;
  USE SIGNAL ;
  PORT
   LAYER M5 ;
   RECT 221.5200 630.6360 221.5440 630.7200 ;
  END
 END li_d[238]
 PIN li_d[239]
  DIRECTION OUTPUT ;
  USE SIGNAL ;
  PORT
   LAYER M5 ;
   RECT 221.7600 630.6360 221.7840 630.7200 ;
  END
 END li_d[239]
 PIN li_d[240]
  DIRECTION OUTPUT ;
  USE SIGNAL ;
  PORT
   LAYER M5 ;
   RECT 222.0000 630.6360 222.0240 630.7200 ;
  END
 END li_d[240]
 PIN li_d[241]
  DIRECTION OUTPUT ;
  USE SIGNAL ;
  PORT
   LAYER M5 ;
   RECT 222.2400 630.6360 222.2640 630.7200 ;
  END
 END li_d[241]
 PIN li_d[242]
  DIRECTION OUTPUT ;
  USE SIGNAL ;
  PORT
   LAYER M5 ;
   RECT 222.4800 630.6360 222.5040 630.7200 ;
  END
 END li_d[242]
 PIN li_d[243]
  DIRECTION OUTPUT ;
  USE SIGNAL ;
  PORT
   LAYER M5 ;
   RECT 222.7200 630.6360 222.7440 630.7200 ;
  END
 END li_d[243]
 PIN li_d[244]
  DIRECTION OUTPUT ;
  USE SIGNAL ;
  PORT
   LAYER M5 ;
   RECT 222.9600 630.6360 222.9840 630.7200 ;
  END
 END li_d[244]
 PIN li_d[245]
  DIRECTION OUTPUT ;
  USE SIGNAL ;
  PORT
   LAYER M5 ;
   RECT 223.2000 630.6360 223.2240 630.7200 ;
  END
 END li_d[245]
 PIN li_d[246]
  DIRECTION OUTPUT ;
  USE SIGNAL ;
  PORT
   LAYER M5 ;
   RECT 223.4400 630.6360 223.4640 630.7200 ;
  END
 END li_d[246]
 PIN li_d[247]
  DIRECTION OUTPUT ;
  USE SIGNAL ;
  PORT
   LAYER M5 ;
   RECT 223.6800 630.6360 223.7040 630.7200 ;
  END
 END li_d[247]
 PIN li_d[248]
  DIRECTION OUTPUT ;
  USE SIGNAL ;
  PORT
   LAYER M5 ;
   RECT 223.9200 630.6360 223.9440 630.7200 ;
  END
 END li_d[248]
 PIN li_d[249]
  DIRECTION OUTPUT ;
  USE SIGNAL ;
  PORT
   LAYER M5 ;
   RECT 224.1600 630.6360 224.1840 630.7200 ;
  END
 END li_d[249]
 PIN li_d[250]
  DIRECTION OUTPUT ;
  USE SIGNAL ;
  PORT
   LAYER M5 ;
   RECT 224.4000 630.6360 224.4240 630.7200 ;
  END
 END li_d[250]
 PIN li_d[251]
  DIRECTION OUTPUT ;
  USE SIGNAL ;
  PORT
   LAYER M5 ;
   RECT 224.6400 630.6360 224.6640 630.7200 ;
  END
 END li_d[251]
 PIN li_d[252]
  DIRECTION OUTPUT ;
  USE SIGNAL ;
  PORT
   LAYER M5 ;
   RECT 224.8800 630.6360 224.9040 630.7200 ;
  END
 END li_d[252]
 PIN li_d[253]
  DIRECTION OUTPUT ;
  USE SIGNAL ;
  PORT
   LAYER M5 ;
   RECT 225.1200 630.6360 225.1440 630.7200 ;
  END
 END li_d[253]
 PIN li_d[254]
  DIRECTION OUTPUT ;
  USE SIGNAL ;
  PORT
   LAYER M5 ;
   RECT 225.3600 630.6360 225.3840 630.7200 ;
  END
 END li_d[254]
 PIN li_d[255]
  DIRECTION OUTPUT ;
  USE SIGNAL ;
  PORT
   LAYER M5 ;
   RECT 225.6000 630.6360 225.6240 630.7200 ;
  END
 END li_d[255]
 PIN li_d[256]
  DIRECTION OUTPUT ;
  USE SIGNAL ;
  PORT
   LAYER M5 ;
   RECT 225.8400 630.6360 225.8640 630.7200 ;
  END
 END li_d[256]
 PIN li_d[257]
  DIRECTION OUTPUT ;
  USE SIGNAL ;
  PORT
   LAYER M5 ;
   RECT 226.0800 630.6360 226.1040 630.7200 ;
  END
 END li_d[257]
 PIN li_d[258]
  DIRECTION OUTPUT ;
  USE SIGNAL ;
  PORT
   LAYER M5 ;
   RECT 226.3200 630.6360 226.3440 630.7200 ;
  END
 END li_d[258]
 PIN li_d[259]
  DIRECTION OUTPUT ;
  USE SIGNAL ;
  PORT
   LAYER M5 ;
   RECT 226.5600 630.6360 226.5840 630.7200 ;
  END
 END li_d[259]
 PIN li_d[260]
  DIRECTION OUTPUT ;
  USE SIGNAL ;
  PORT
   LAYER M5 ;
   RECT 226.8000 630.6360 226.8240 630.7200 ;
  END
 END li_d[260]
 PIN li_d[261]
  DIRECTION OUTPUT ;
  USE SIGNAL ;
  PORT
   LAYER M5 ;
   RECT 227.0400 630.6360 227.0640 630.7200 ;
  END
 END li_d[261]
 PIN li_d[262]
  DIRECTION OUTPUT ;
  USE SIGNAL ;
  PORT
   LAYER M5 ;
   RECT 227.2800 630.6360 227.3040 630.7200 ;
  END
 END li_d[262]
 PIN li_d[263]
  DIRECTION OUTPUT ;
  USE SIGNAL ;
  PORT
   LAYER M5 ;
   RECT 227.5200 630.6360 227.5440 630.7200 ;
  END
 END li_d[263]
 PIN li_d[264]
  DIRECTION OUTPUT ;
  USE SIGNAL ;
  PORT
   LAYER M5 ;
   RECT 227.7600 630.6360 227.7840 630.7200 ;
  END
 END li_d[264]
 PIN li_d[265]
  DIRECTION OUTPUT ;
  USE SIGNAL ;
  PORT
   LAYER M5 ;
   RECT 228.0000 630.6360 228.0240 630.7200 ;
  END
 END li_d[265]
 PIN li_d[266]
  DIRECTION OUTPUT ;
  USE SIGNAL ;
  PORT
   LAYER M5 ;
   RECT 228.2400 630.6360 228.2640 630.7200 ;
  END
 END li_d[266]
 PIN li_d[267]
  DIRECTION OUTPUT ;
  USE SIGNAL ;
  PORT
   LAYER M5 ;
   RECT 228.4800 630.6360 228.5040 630.7200 ;
  END
 END li_d[267]
 PIN li_d[268]
  DIRECTION OUTPUT ;
  USE SIGNAL ;
  PORT
   LAYER M5 ;
   RECT 228.7200 630.6360 228.7440 630.7200 ;
  END
 END li_d[268]
 PIN li_d[269]
  DIRECTION OUTPUT ;
  USE SIGNAL ;
  PORT
   LAYER M5 ;
   RECT 228.9600 630.6360 228.9840 630.7200 ;
  END
 END li_d[269]
 PIN li_d[270]
  DIRECTION OUTPUT ;
  USE SIGNAL ;
  PORT
   LAYER M5 ;
   RECT 229.2000 630.6360 229.2240 630.7200 ;
  END
 END li_d[270]
 PIN li_d[271]
  DIRECTION OUTPUT ;
  USE SIGNAL ;
  PORT
   LAYER M5 ;
   RECT 229.4400 630.6360 229.4640 630.7200 ;
  END
 END li_d[271]
 PIN li_d[272]
  DIRECTION OUTPUT ;
  USE SIGNAL ;
  PORT
   LAYER M5 ;
   RECT 229.6800 630.6360 229.7040 630.7200 ;
  END
 END li_d[272]
 PIN li_d[273]
  DIRECTION OUTPUT ;
  USE SIGNAL ;
  PORT
   LAYER M5 ;
   RECT 229.9200 630.6360 229.9440 630.7200 ;
  END
 END li_d[273]
 PIN li_d[274]
  DIRECTION OUTPUT ;
  USE SIGNAL ;
  PORT
   LAYER M5 ;
   RECT 230.1600 630.6360 230.1840 630.7200 ;
  END
 END li_d[274]
 PIN li_d[275]
  DIRECTION OUTPUT ;
  USE SIGNAL ;
  PORT
   LAYER M5 ;
   RECT 230.4000 630.6360 230.4240 630.7200 ;
  END
 END li_d[275]
 PIN li_d[276]
  DIRECTION OUTPUT ;
  USE SIGNAL ;
  PORT
   LAYER M5 ;
   RECT 230.6400 630.6360 230.6640 630.7200 ;
  END
 END li_d[276]
 PIN li_d[277]
  DIRECTION OUTPUT ;
  USE SIGNAL ;
  PORT
   LAYER M5 ;
   RECT 230.8800 630.6360 230.9040 630.7200 ;
  END
 END li_d[277]
 PIN li_d[278]
  DIRECTION OUTPUT ;
  USE SIGNAL ;
  PORT
   LAYER M5 ;
   RECT 231.1200 630.6360 231.1440 630.7200 ;
  END
 END li_d[278]
 PIN li_d[279]
  DIRECTION OUTPUT ;
  USE SIGNAL ;
  PORT
   LAYER M5 ;
   RECT 231.3600 630.6360 231.3840 630.7200 ;
  END
 END li_d[279]
 PIN li_d[280]
  DIRECTION OUTPUT ;
  USE SIGNAL ;
  PORT
   LAYER M5 ;
   RECT 231.6000 630.6360 231.6240 630.7200 ;
  END
 END li_d[280]
 PIN li_d[281]
  DIRECTION OUTPUT ;
  USE SIGNAL ;
  PORT
   LAYER M5 ;
   RECT 231.8400 630.6360 231.8640 630.7200 ;
  END
 END li_d[281]
 PIN li_d[282]
  DIRECTION OUTPUT ;
  USE SIGNAL ;
  PORT
   LAYER M5 ;
   RECT 232.0800 630.6360 232.1040 630.7200 ;
  END
 END li_d[282]
 PIN li_d[283]
  DIRECTION OUTPUT ;
  USE SIGNAL ;
  PORT
   LAYER M5 ;
   RECT 232.3200 630.6360 232.3440 630.7200 ;
  END
 END li_d[283]
 PIN li_d[284]
  DIRECTION OUTPUT ;
  USE SIGNAL ;
  PORT
   LAYER M5 ;
   RECT 232.5600 630.6360 232.5840 630.7200 ;
  END
 END li_d[284]
 PIN li_d[285]
  DIRECTION OUTPUT ;
  USE SIGNAL ;
  PORT
   LAYER M5 ;
   RECT 232.8000 630.6360 232.8240 630.7200 ;
  END
 END li_d[285]
 PIN li_d[286]
  DIRECTION OUTPUT ;
  USE SIGNAL ;
  PORT
   LAYER M5 ;
   RECT 233.0400 630.6360 233.0640 630.7200 ;
  END
 END li_d[286]
 PIN li_d[287]
  DIRECTION OUTPUT ;
  USE SIGNAL ;
  PORT
   LAYER M5 ;
   RECT 233.2800 630.6360 233.3040 630.7200 ;
  END
 END li_d[287]
 PIN li_d[288]
  DIRECTION OUTPUT ;
  USE SIGNAL ;
  PORT
   LAYER M5 ;
   RECT 233.5200 630.6360 233.5440 630.7200 ;
  END
 END li_d[288]
 PIN li_d[289]
  DIRECTION OUTPUT ;
  USE SIGNAL ;
  PORT
   LAYER M5 ;
   RECT 233.7600 630.6360 233.7840 630.7200 ;
  END
 END li_d[289]
 PIN li_d[290]
  DIRECTION OUTPUT ;
  USE SIGNAL ;
  PORT
   LAYER M5 ;
   RECT 234.0000 630.6360 234.0240 630.7200 ;
  END
 END li_d[290]
 PIN li_d[291]
  DIRECTION OUTPUT ;
  USE SIGNAL ;
  PORT
   LAYER M5 ;
   RECT 234.2400 630.6360 234.2640 630.7200 ;
  END
 END li_d[291]
 PIN li_d[292]
  DIRECTION OUTPUT ;
  USE SIGNAL ;
  PORT
   LAYER M5 ;
   RECT 234.4800 630.6360 234.5040 630.7200 ;
  END
 END li_d[292]
 PIN li_d[293]
  DIRECTION OUTPUT ;
  USE SIGNAL ;
  PORT
   LAYER M5 ;
   RECT 234.7200 630.6360 234.7440 630.7200 ;
  END
 END li_d[293]
 PIN li_d[294]
  DIRECTION OUTPUT ;
  USE SIGNAL ;
  PORT
   LAYER M5 ;
   RECT 234.9600 630.6360 234.9840 630.7200 ;
  END
 END li_d[294]
 PIN li_d[295]
  DIRECTION OUTPUT ;
  USE SIGNAL ;
  PORT
   LAYER M5 ;
   RECT 235.2000 630.6360 235.2240 630.7200 ;
  END
 END li_d[295]
 PIN li_d[296]
  DIRECTION OUTPUT ;
  USE SIGNAL ;
  PORT
   LAYER M5 ;
   RECT 235.4400 630.6360 235.4640 630.7200 ;
  END
 END li_d[296]
 PIN li_d[297]
  DIRECTION OUTPUT ;
  USE SIGNAL ;
  PORT
   LAYER M5 ;
   RECT 235.6800 630.6360 235.7040 630.7200 ;
  END
 END li_d[297]
 PIN li_d[298]
  DIRECTION OUTPUT ;
  USE SIGNAL ;
  PORT
   LAYER M5 ;
   RECT 235.9200 630.6360 235.9440 630.7200 ;
  END
 END li_d[298]
 PIN li_d[299]
  DIRECTION OUTPUT ;
  USE SIGNAL ;
  PORT
   LAYER M5 ;
   RECT 236.1600 630.6360 236.1840 630.7200 ;
  END
 END li_d[299]
 PIN li_d[300]
  DIRECTION OUTPUT ;
  USE SIGNAL ;
  PORT
   LAYER M5 ;
   RECT 236.4000 630.6360 236.4240 630.7200 ;
  END
 END li_d[300]
 PIN li_d[301]
  DIRECTION OUTPUT ;
  USE SIGNAL ;
  PORT
   LAYER M5 ;
   RECT 236.6400 630.6360 236.6640 630.7200 ;
  END
 END li_d[301]
 PIN li_d[302]
  DIRECTION OUTPUT ;
  USE SIGNAL ;
  PORT
   LAYER M5 ;
   RECT 236.8800 630.6360 236.9040 630.7200 ;
  END
 END li_d[302]
 PIN li_d[303]
  DIRECTION OUTPUT ;
  USE SIGNAL ;
  PORT
   LAYER M5 ;
   RECT 237.1200 630.6360 237.1440 630.7200 ;
  END
 END li_d[303]
 PIN li_d[304]
  DIRECTION OUTPUT ;
  USE SIGNAL ;
  PORT
   LAYER M5 ;
   RECT 237.3600 630.6360 237.3840 630.7200 ;
  END
 END li_d[304]
 PIN li_d[305]
  DIRECTION OUTPUT ;
  USE SIGNAL ;
  PORT
   LAYER M5 ;
   RECT 237.6000 630.6360 237.6240 630.7200 ;
  END
 END li_d[305]
 PIN li_d[306]
  DIRECTION OUTPUT ;
  USE SIGNAL ;
  PORT
   LAYER M5 ;
   RECT 237.8400 630.6360 237.8640 630.7200 ;
  END
 END li_d[306]
 PIN li_d[307]
  DIRECTION OUTPUT ;
  USE SIGNAL ;
  PORT
   LAYER M5 ;
   RECT 238.0800 630.6360 238.1040 630.7200 ;
  END
 END li_d[307]
 PIN li_d[308]
  DIRECTION OUTPUT ;
  USE SIGNAL ;
  PORT
   LAYER M5 ;
   RECT 238.3200 630.6360 238.3440 630.7200 ;
  END
 END li_d[308]
 PIN li_d[309]
  DIRECTION OUTPUT ;
  USE SIGNAL ;
  PORT
   LAYER M5 ;
   RECT 238.5600 630.6360 238.5840 630.7200 ;
  END
 END li_d[309]
 PIN li_d[310]
  DIRECTION OUTPUT ;
  USE SIGNAL ;
  PORT
   LAYER M5 ;
   RECT 238.8000 630.6360 238.8240 630.7200 ;
  END
 END li_d[310]
 PIN li_d[311]
  DIRECTION OUTPUT ;
  USE SIGNAL ;
  PORT
   LAYER M5 ;
   RECT 239.0400 630.6360 239.0640 630.7200 ;
  END
 END li_d[311]
 PIN li_d[312]
  DIRECTION OUTPUT ;
  USE SIGNAL ;
  PORT
   LAYER M5 ;
   RECT 239.2800 630.6360 239.3040 630.7200 ;
  END
 END li_d[312]
 PIN li_d[313]
  DIRECTION OUTPUT ;
  USE SIGNAL ;
  PORT
   LAYER M5 ;
   RECT 239.5200 630.6360 239.5440 630.7200 ;
  END
 END li_d[313]
 PIN li_d[314]
  DIRECTION OUTPUT ;
  USE SIGNAL ;
  PORT
   LAYER M5 ;
   RECT 239.7600 630.6360 239.7840 630.7200 ;
  END
 END li_d[314]
 PIN li_d[315]
  DIRECTION OUTPUT ;
  USE SIGNAL ;
  PORT
   LAYER M5 ;
   RECT 240.0000 630.6360 240.0240 630.7200 ;
  END
 END li_d[315]
 PIN li_d[316]
  DIRECTION OUTPUT ;
  USE SIGNAL ;
  PORT
   LAYER M5 ;
   RECT 240.2400 630.6360 240.2640 630.7200 ;
  END
 END li_d[316]
 PIN li_d[317]
  DIRECTION OUTPUT ;
  USE SIGNAL ;
  PORT
   LAYER M5 ;
   RECT 240.4800 630.6360 240.5040 630.7200 ;
  END
 END li_d[317]
 PIN li_d[318]
  DIRECTION OUTPUT ;
  USE SIGNAL ;
  PORT
   LAYER M5 ;
   RECT 240.7200 630.6360 240.7440 630.7200 ;
  END
 END li_d[318]
 PIN li_d[319]
  DIRECTION OUTPUT ;
  USE SIGNAL ;
  PORT
   LAYER M5 ;
   RECT 240.9600 630.6360 240.9840 630.7200 ;
  END
 END li_d[319]
 PIN li_d[320]
  DIRECTION OUTPUT ;
  USE SIGNAL ;
  PORT
   LAYER M5 ;
   RECT 241.2000 630.6360 241.2240 630.7200 ;
  END
 END li_d[320]
 PIN li_d[321]
  DIRECTION OUTPUT ;
  USE SIGNAL ;
  PORT
   LAYER M5 ;
   RECT 241.4400 630.6360 241.4640 630.7200 ;
  END
 END li_d[321]
 PIN li_d[322]
  DIRECTION OUTPUT ;
  USE SIGNAL ;
  PORT
   LAYER M5 ;
   RECT 241.6800 630.6360 241.7040 630.7200 ;
  END
 END li_d[322]
 PIN li_d[323]
  DIRECTION OUTPUT ;
  USE SIGNAL ;
  PORT
   LAYER M5 ;
   RECT 241.9200 630.6360 241.9440 630.7200 ;
  END
 END li_d[323]
 PIN li_d[324]
  DIRECTION OUTPUT ;
  USE SIGNAL ;
  PORT
   LAYER M5 ;
   RECT 242.1600 630.6360 242.1840 630.7200 ;
  END
 END li_d[324]
 PIN li_d[325]
  DIRECTION OUTPUT ;
  USE SIGNAL ;
  PORT
   LAYER M5 ;
   RECT 242.4000 630.6360 242.4240 630.7200 ;
  END
 END li_d[325]
 PIN li_d[326]
  DIRECTION OUTPUT ;
  USE SIGNAL ;
  PORT
   LAYER M5 ;
   RECT 242.6400 630.6360 242.6640 630.7200 ;
  END
 END li_d[326]
 PIN li_d[327]
  DIRECTION OUTPUT ;
  USE SIGNAL ;
  PORT
   LAYER M5 ;
   RECT 242.8800 630.6360 242.9040 630.7200 ;
  END
 END li_d[327]
 PIN li_d[328]
  DIRECTION OUTPUT ;
  USE SIGNAL ;
  PORT
   LAYER M5 ;
   RECT 243.1200 630.6360 243.1440 630.7200 ;
  END
 END li_d[328]
 PIN li_d[329]
  DIRECTION OUTPUT ;
  USE SIGNAL ;
  PORT
   LAYER M5 ;
   RECT 243.3600 630.6360 243.3840 630.7200 ;
  END
 END li_d[329]
 PIN li_d[330]
  DIRECTION OUTPUT ;
  USE SIGNAL ;
  PORT
   LAYER M5 ;
   RECT 243.6000 630.6360 243.6240 630.7200 ;
  END
 END li_d[330]
 PIN li_d[331]
  DIRECTION OUTPUT ;
  USE SIGNAL ;
  PORT
   LAYER M5 ;
   RECT 243.8400 630.6360 243.8640 630.7200 ;
  END
 END li_d[331]
 PIN li_d[332]
  DIRECTION OUTPUT ;
  USE SIGNAL ;
  PORT
   LAYER M5 ;
   RECT 244.0800 630.6360 244.1040 630.7200 ;
  END
 END li_d[332]
 PIN li_d[333]
  DIRECTION OUTPUT ;
  USE SIGNAL ;
  PORT
   LAYER M5 ;
   RECT 244.3200 630.6360 244.3440 630.7200 ;
  END
 END li_d[333]
 PIN li_d[334]
  DIRECTION OUTPUT ;
  USE SIGNAL ;
  PORT
   LAYER M5 ;
   RECT 244.5600 630.6360 244.5840 630.7200 ;
  END
 END li_d[334]
 PIN li_d[335]
  DIRECTION OUTPUT ;
  USE SIGNAL ;
  PORT
   LAYER M5 ;
   RECT 244.8000 630.6360 244.8240 630.7200 ;
  END
 END li_d[335]
 PIN li_d[336]
  DIRECTION OUTPUT ;
  USE SIGNAL ;
  PORT
   LAYER M5 ;
   RECT 245.0400 630.6360 245.0640 630.7200 ;
  END
 END li_d[336]
 PIN li_d[337]
  DIRECTION OUTPUT ;
  USE SIGNAL ;
  PORT
   LAYER M5 ;
   RECT 245.2800 630.6360 245.3040 630.7200 ;
  END
 END li_d[337]
 PIN li_d[338]
  DIRECTION OUTPUT ;
  USE SIGNAL ;
  PORT
   LAYER M5 ;
   RECT 245.5200 630.6360 245.5440 630.7200 ;
  END
 END li_d[338]
 PIN li_d[339]
  DIRECTION OUTPUT ;
  USE SIGNAL ;
  PORT
   LAYER M5 ;
   RECT 245.7600 630.6360 245.7840 630.7200 ;
  END
 END li_d[339]
 PIN li_d[340]
  DIRECTION OUTPUT ;
  USE SIGNAL ;
  PORT
   LAYER M5 ;
   RECT 246.0000 630.6360 246.0240 630.7200 ;
  END
 END li_d[340]
 PIN li_d[341]
  DIRECTION OUTPUT ;
  USE SIGNAL ;
  PORT
   LAYER M5 ;
   RECT 246.2400 630.6360 246.2640 630.7200 ;
  END
 END li_d[341]
 PIN li_d[342]
  DIRECTION OUTPUT ;
  USE SIGNAL ;
  PORT
   LAYER M5 ;
   RECT 246.4800 630.6360 246.5040 630.7200 ;
  END
 END li_d[342]
 PIN li_d[343]
  DIRECTION OUTPUT ;
  USE SIGNAL ;
  PORT
   LAYER M5 ;
   RECT 246.7200 630.6360 246.7440 630.7200 ;
  END
 END li_d[343]
 PIN li_d[344]
  DIRECTION OUTPUT ;
  USE SIGNAL ;
  PORT
   LAYER M5 ;
   RECT 246.9600 630.6360 246.9840 630.7200 ;
  END
 END li_d[344]
 PIN li_d[345]
  DIRECTION OUTPUT ;
  USE SIGNAL ;
  PORT
   LAYER M5 ;
   RECT 247.2000 630.6360 247.2240 630.7200 ;
  END
 END li_d[345]
 PIN li_d[346]
  DIRECTION OUTPUT ;
  USE SIGNAL ;
  PORT
   LAYER M5 ;
   RECT 247.4400 630.6360 247.4640 630.7200 ;
  END
 END li_d[346]
 PIN li_d[347]
  DIRECTION OUTPUT ;
  USE SIGNAL ;
  PORT
   LAYER M5 ;
   RECT 247.6800 630.6360 247.7040 630.7200 ;
  END
 END li_d[347]
 PIN li_d[348]
  DIRECTION OUTPUT ;
  USE SIGNAL ;
  PORT
   LAYER M5 ;
   RECT 247.9200 630.6360 247.9440 630.7200 ;
  END
 END li_d[348]
 PIN li_d[349]
  DIRECTION OUTPUT ;
  USE SIGNAL ;
  PORT
   LAYER M5 ;
   RECT 248.1600 630.6360 248.1840 630.7200 ;
  END
 END li_d[349]
 PIN li_d[350]
  DIRECTION OUTPUT ;
  USE SIGNAL ;
  PORT
   LAYER M5 ;
   RECT 248.4000 630.6360 248.4240 630.7200 ;
  END
 END li_d[350]
 PIN li_d[351]
  DIRECTION OUTPUT ;
  USE SIGNAL ;
  PORT
   LAYER M5 ;
   RECT 248.6400 630.6360 248.6640 630.7200 ;
  END
 END li_d[351]
 PIN li_d[352]
  DIRECTION OUTPUT ;
  USE SIGNAL ;
  PORT
   LAYER M5 ;
   RECT 248.8800 630.6360 248.9040 630.7200 ;
  END
 END li_d[352]
 PIN li_d[353]
  DIRECTION OUTPUT ;
  USE SIGNAL ;
  PORT
   LAYER M5 ;
   RECT 249.1200 630.6360 249.1440 630.7200 ;
  END
 END li_d[353]
 PIN li_d[354]
  DIRECTION OUTPUT ;
  USE SIGNAL ;
  PORT
   LAYER M5 ;
   RECT 249.3600 630.6360 249.3840 630.7200 ;
  END
 END li_d[354]
 PIN li_d[355]
  DIRECTION OUTPUT ;
  USE SIGNAL ;
  PORT
   LAYER M5 ;
   RECT 249.6000 630.6360 249.6240 630.7200 ;
  END
 END li_d[355]
 PIN li_d[356]
  DIRECTION OUTPUT ;
  USE SIGNAL ;
  PORT
   LAYER M5 ;
   RECT 249.8400 630.6360 249.8640 630.7200 ;
  END
 END li_d[356]
 PIN li_d[357]
  DIRECTION OUTPUT ;
  USE SIGNAL ;
  PORT
   LAYER M5 ;
   RECT 250.0800 630.6360 250.1040 630.7200 ;
  END
 END li_d[357]
 PIN li_d[358]
  DIRECTION OUTPUT ;
  USE SIGNAL ;
  PORT
   LAYER M5 ;
   RECT 250.3200 630.6360 250.3440 630.7200 ;
  END
 END li_d[358]
 PIN li_d[359]
  DIRECTION OUTPUT ;
  USE SIGNAL ;
  PORT
   LAYER M5 ;
   RECT 250.5600 630.6360 250.5840 630.7200 ;
  END
 END li_d[359]
 PIN li_d[360]
  DIRECTION OUTPUT ;
  USE SIGNAL ;
  PORT
   LAYER M5 ;
   RECT 250.8000 630.6360 250.8240 630.7200 ;
  END
 END li_d[360]
 PIN li_d[361]
  DIRECTION OUTPUT ;
  USE SIGNAL ;
  PORT
   LAYER M5 ;
   RECT 251.0400 630.6360 251.0640 630.7200 ;
  END
 END li_d[361]
 PIN li_d[362]
  DIRECTION OUTPUT ;
  USE SIGNAL ;
  PORT
   LAYER M5 ;
   RECT 251.2800 630.6360 251.3040 630.7200 ;
  END
 END li_d[362]
 PIN li_d[363]
  DIRECTION OUTPUT ;
  USE SIGNAL ;
  PORT
   LAYER M5 ;
   RECT 251.5200 630.6360 251.5440 630.7200 ;
  END
 END li_d[363]
 PIN li_d[364]
  DIRECTION OUTPUT ;
  USE SIGNAL ;
  PORT
   LAYER M5 ;
   RECT 251.7600 630.6360 251.7840 630.7200 ;
  END
 END li_d[364]
 PIN li_d[365]
  DIRECTION OUTPUT ;
  USE SIGNAL ;
  PORT
   LAYER M5 ;
   RECT 252.0000 630.6360 252.0240 630.7200 ;
  END
 END li_d[365]
 PIN li_d[366]
  DIRECTION OUTPUT ;
  USE SIGNAL ;
  PORT
   LAYER M5 ;
   RECT 252.2400 630.6360 252.2640 630.7200 ;
  END
 END li_d[366]
 PIN li_d[367]
  DIRECTION OUTPUT ;
  USE SIGNAL ;
  PORT
   LAYER M5 ;
   RECT 252.4800 630.6360 252.5040 630.7200 ;
  END
 END li_d[367]
 PIN li_d[368]
  DIRECTION OUTPUT ;
  USE SIGNAL ;
  PORT
   LAYER M5 ;
   RECT 252.7200 630.6360 252.7440 630.7200 ;
  END
 END li_d[368]
 PIN li_d[369]
  DIRECTION OUTPUT ;
  USE SIGNAL ;
  PORT
   LAYER M5 ;
   RECT 252.9600 630.6360 252.9840 630.7200 ;
  END
 END li_d[369]
 PIN li_d[370]
  DIRECTION OUTPUT ;
  USE SIGNAL ;
  PORT
   LAYER M5 ;
   RECT 253.2000 630.6360 253.2240 630.7200 ;
  END
 END li_d[370]
 PIN li_d[371]
  DIRECTION OUTPUT ;
  USE SIGNAL ;
  PORT
   LAYER M5 ;
   RECT 253.4400 630.6360 253.4640 630.7200 ;
  END
 END li_d[371]
 PIN li_d[372]
  DIRECTION OUTPUT ;
  USE SIGNAL ;
  PORT
   LAYER M5 ;
   RECT 253.6800 630.6360 253.7040 630.7200 ;
  END
 END li_d[372]
 PIN li_d[373]
  DIRECTION OUTPUT ;
  USE SIGNAL ;
  PORT
   LAYER M5 ;
   RECT 253.9200 630.6360 253.9440 630.7200 ;
  END
 END li_d[373]
 PIN li_d[374]
  DIRECTION OUTPUT ;
  USE SIGNAL ;
  PORT
   LAYER M5 ;
   RECT 254.1600 630.6360 254.1840 630.7200 ;
  END
 END li_d[374]
 PIN li_d[375]
  DIRECTION OUTPUT ;
  USE SIGNAL ;
  PORT
   LAYER M5 ;
   RECT 254.4000 630.6360 254.4240 630.7200 ;
  END
 END li_d[375]
 PIN li_d[376]
  DIRECTION OUTPUT ;
  USE SIGNAL ;
  PORT
   LAYER M5 ;
   RECT 254.6400 630.6360 254.6640 630.7200 ;
  END
 END li_d[376]
 PIN li_d[377]
  DIRECTION OUTPUT ;
  USE SIGNAL ;
  PORT
   LAYER M5 ;
   RECT 254.8800 630.6360 254.9040 630.7200 ;
  END
 END li_d[377]
 PIN li_d[378]
  DIRECTION OUTPUT ;
  USE SIGNAL ;
  PORT
   LAYER M5 ;
   RECT 255.1200 630.6360 255.1440 630.7200 ;
  END
 END li_d[378]
 PIN li_d[379]
  DIRECTION OUTPUT ;
  USE SIGNAL ;
  PORT
   LAYER M5 ;
   RECT 255.3600 630.6360 255.3840 630.7200 ;
  END
 END li_d[379]
 PIN li_d[380]
  DIRECTION OUTPUT ;
  USE SIGNAL ;
  PORT
   LAYER M5 ;
   RECT 255.6000 630.6360 255.6240 630.7200 ;
  END
 END li_d[380]
 PIN li_d[381]
  DIRECTION OUTPUT ;
  USE SIGNAL ;
  PORT
   LAYER M5 ;
   RECT 255.8400 630.6360 255.8640 630.7200 ;
  END
 END li_d[381]
 PIN li_d[382]
  DIRECTION OUTPUT ;
  USE SIGNAL ;
  PORT
   LAYER M5 ;
   RECT 256.0800 630.6360 256.1040 630.7200 ;
  END
 END li_d[382]
 PIN li_d[383]
  DIRECTION OUTPUT ;
  USE SIGNAL ;
  PORT
   LAYER M5 ;
   RECT 256.3200 630.6360 256.3440 630.7200 ;
  END
 END li_d[383]
 PIN li_d[384]
  DIRECTION OUTPUT ;
  USE SIGNAL ;
  PORT
   LAYER M5 ;
   RECT 256.5600 630.6360 256.5840 630.7200 ;
  END
 END li_d[384]
 PIN li_d[385]
  DIRECTION OUTPUT ;
  USE SIGNAL ;
  PORT
   LAYER M5 ;
   RECT 256.8000 630.6360 256.8240 630.7200 ;
  END
 END li_d[385]
 PIN li_d[386]
  DIRECTION OUTPUT ;
  USE SIGNAL ;
  PORT
   LAYER M5 ;
   RECT 257.0400 630.6360 257.0640 630.7200 ;
  END
 END li_d[386]
 PIN li_d[387]
  DIRECTION OUTPUT ;
  USE SIGNAL ;
  PORT
   LAYER M5 ;
   RECT 257.2800 630.6360 257.3040 630.7200 ;
  END
 END li_d[387]
 PIN li_d[388]
  DIRECTION OUTPUT ;
  USE SIGNAL ;
  PORT
   LAYER M5 ;
   RECT 257.5200 630.6360 257.5440 630.7200 ;
  END
 END li_d[388]
 PIN li_d[389]
  DIRECTION OUTPUT ;
  USE SIGNAL ;
  PORT
   LAYER M5 ;
   RECT 257.7600 630.6360 257.7840 630.7200 ;
  END
 END li_d[389]
 PIN li_d[390]
  DIRECTION OUTPUT ;
  USE SIGNAL ;
  PORT
   LAYER M5 ;
   RECT 258.0000 630.6360 258.0240 630.7200 ;
  END
 END li_d[390]
 PIN li_d[391]
  DIRECTION OUTPUT ;
  USE SIGNAL ;
  PORT
   LAYER M5 ;
   RECT 258.2400 630.6360 258.2640 630.7200 ;
  END
 END li_d[391]
 PIN li_d[392]
  DIRECTION OUTPUT ;
  USE SIGNAL ;
  PORT
   LAYER M5 ;
   RECT 258.4800 630.6360 258.5040 630.7200 ;
  END
 END li_d[392]
 PIN li_d[393]
  DIRECTION OUTPUT ;
  USE SIGNAL ;
  PORT
   LAYER M5 ;
   RECT 258.7200 630.6360 258.7440 630.7200 ;
  END
 END li_d[393]
 PIN li_d[394]
  DIRECTION OUTPUT ;
  USE SIGNAL ;
  PORT
   LAYER M5 ;
   RECT 258.9600 630.6360 258.9840 630.7200 ;
  END
 END li_d[394]
 PIN li_d[395]
  DIRECTION OUTPUT ;
  USE SIGNAL ;
  PORT
   LAYER M5 ;
   RECT 259.2000 630.6360 259.2240 630.7200 ;
  END
 END li_d[395]
 PIN li_d[396]
  DIRECTION OUTPUT ;
  USE SIGNAL ;
  PORT
   LAYER M5 ;
   RECT 259.4400 630.6360 259.4640 630.7200 ;
  END
 END li_d[396]
 PIN li_d[397]
  DIRECTION OUTPUT ;
  USE SIGNAL ;
  PORT
   LAYER M5 ;
   RECT 259.6800 630.6360 259.7040 630.7200 ;
  END
 END li_d[397]
 PIN li_d[398]
  DIRECTION OUTPUT ;
  USE SIGNAL ;
  PORT
   LAYER M5 ;
   RECT 259.9200 630.6360 259.9440 630.7200 ;
  END
 END li_d[398]
 PIN li_d[399]
  DIRECTION OUTPUT ;
  USE SIGNAL ;
  PORT
   LAYER M5 ;
   RECT 260.1600 630.6360 260.1840 630.7200 ;
  END
 END li_d[399]
 PIN li_d[400]
  DIRECTION OUTPUT ;
  USE SIGNAL ;
  PORT
   LAYER M5 ;
   RECT 260.4000 630.6360 260.4240 630.7200 ;
  END
 END li_d[400]
 PIN li_d[401]
  DIRECTION OUTPUT ;
  USE SIGNAL ;
  PORT
   LAYER M5 ;
   RECT 260.6400 630.6360 260.6640 630.7200 ;
  END
 END li_d[401]
 PIN li_d[402]
  DIRECTION OUTPUT ;
  USE SIGNAL ;
  PORT
   LAYER M5 ;
   RECT 260.8800 630.6360 260.9040 630.7200 ;
  END
 END li_d[402]
 PIN li_d[403]
  DIRECTION OUTPUT ;
  USE SIGNAL ;
  PORT
   LAYER M5 ;
   RECT 261.1200 630.6360 261.1440 630.7200 ;
  END
 END li_d[403]
 PIN li_d[404]
  DIRECTION OUTPUT ;
  USE SIGNAL ;
  PORT
   LAYER M5 ;
   RECT 261.3600 630.6360 261.3840 630.7200 ;
  END
 END li_d[404]
 PIN li_d[405]
  DIRECTION OUTPUT ;
  USE SIGNAL ;
  PORT
   LAYER M5 ;
   RECT 261.6000 630.6360 261.6240 630.7200 ;
  END
 END li_d[405]
 PIN li_d[406]
  DIRECTION OUTPUT ;
  USE SIGNAL ;
  PORT
   LAYER M5 ;
   RECT 261.8400 630.6360 261.8640 630.7200 ;
  END
 END li_d[406]
 PIN li_d[407]
  DIRECTION OUTPUT ;
  USE SIGNAL ;
  PORT
   LAYER M5 ;
   RECT 262.0800 630.6360 262.1040 630.7200 ;
  END
 END li_d[407]
 PIN li_d[408]
  DIRECTION OUTPUT ;
  USE SIGNAL ;
  PORT
   LAYER M5 ;
   RECT 262.3200 630.6360 262.3440 630.7200 ;
  END
 END li_d[408]
 PIN li_d[409]
  DIRECTION OUTPUT ;
  USE SIGNAL ;
  PORT
   LAYER M5 ;
   RECT 262.5600 630.6360 262.5840 630.7200 ;
  END
 END li_d[409]
 PIN li_d[410]
  DIRECTION OUTPUT ;
  USE SIGNAL ;
  PORT
   LAYER M5 ;
   RECT 262.8000 630.6360 262.8240 630.7200 ;
  END
 END li_d[410]
 PIN li_d[411]
  DIRECTION OUTPUT ;
  USE SIGNAL ;
  PORT
   LAYER M5 ;
   RECT 263.0400 630.6360 263.0640 630.7200 ;
  END
 END li_d[411]
 PIN li_d[412]
  DIRECTION OUTPUT ;
  USE SIGNAL ;
  PORT
   LAYER M5 ;
   RECT 263.2800 630.6360 263.3040 630.7200 ;
  END
 END li_d[412]
 PIN li_d[413]
  DIRECTION OUTPUT ;
  USE SIGNAL ;
  PORT
   LAYER M5 ;
   RECT 263.5200 630.6360 263.5440 630.7200 ;
  END
 END li_d[413]
 PIN li_d[414]
  DIRECTION OUTPUT ;
  USE SIGNAL ;
  PORT
   LAYER M5 ;
   RECT 263.7600 630.6360 263.7840 630.7200 ;
  END
 END li_d[414]
 PIN li_d[415]
  DIRECTION OUTPUT ;
  USE SIGNAL ;
  PORT
   LAYER M5 ;
   RECT 264.0000 630.6360 264.0240 630.7200 ;
  END
 END li_d[415]
 PIN li_d[416]
  DIRECTION OUTPUT ;
  USE SIGNAL ;
  PORT
   LAYER M5 ;
   RECT 264.2400 630.6360 264.2640 630.7200 ;
  END
 END li_d[416]
 PIN li_d[417]
  DIRECTION OUTPUT ;
  USE SIGNAL ;
  PORT
   LAYER M5 ;
   RECT 264.4800 630.6360 264.5040 630.7200 ;
  END
 END li_d[417]
 PIN li_d[418]
  DIRECTION OUTPUT ;
  USE SIGNAL ;
  PORT
   LAYER M5 ;
   RECT 264.7200 630.6360 264.7440 630.7200 ;
  END
 END li_d[418]
 PIN li_d[419]
  DIRECTION OUTPUT ;
  USE SIGNAL ;
  PORT
   LAYER M5 ;
   RECT 264.9600 630.6360 264.9840 630.7200 ;
  END
 END li_d[419]
 PIN li_d[420]
  DIRECTION OUTPUT ;
  USE SIGNAL ;
  PORT
   LAYER M5 ;
   RECT 265.2000 630.6360 265.2240 630.7200 ;
  END
 END li_d[420]
 PIN li_d[421]
  DIRECTION OUTPUT ;
  USE SIGNAL ;
  PORT
   LAYER M5 ;
   RECT 265.4400 630.6360 265.4640 630.7200 ;
  END
 END li_d[421]
 PIN li_d[422]
  DIRECTION OUTPUT ;
  USE SIGNAL ;
  PORT
   LAYER M5 ;
   RECT 265.6800 630.6360 265.7040 630.7200 ;
  END
 END li_d[422]
 PIN li_d[423]
  DIRECTION OUTPUT ;
  USE SIGNAL ;
  PORT
   LAYER M5 ;
   RECT 265.9200 630.6360 265.9440 630.7200 ;
  END
 END li_d[423]
 PIN li_d[424]
  DIRECTION OUTPUT ;
  USE SIGNAL ;
  PORT
   LAYER M5 ;
   RECT 266.1600 630.6360 266.1840 630.7200 ;
  END
 END li_d[424]
 PIN li_d[425]
  DIRECTION OUTPUT ;
  USE SIGNAL ;
  PORT
   LAYER M5 ;
   RECT 266.4000 630.6360 266.4240 630.7200 ;
  END
 END li_d[425]
 PIN li_d[426]
  DIRECTION OUTPUT ;
  USE SIGNAL ;
  PORT
   LAYER M5 ;
   RECT 266.6400 630.6360 266.6640 630.7200 ;
  END
 END li_d[426]
 PIN li_d[427]
  DIRECTION OUTPUT ;
  USE SIGNAL ;
  PORT
   LAYER M5 ;
   RECT 266.8800 630.6360 266.9040 630.7200 ;
  END
 END li_d[427]
 PIN li_d[428]
  DIRECTION OUTPUT ;
  USE SIGNAL ;
  PORT
   LAYER M5 ;
   RECT 267.1200 630.6360 267.1440 630.7200 ;
  END
 END li_d[428]
 PIN li_d[429]
  DIRECTION OUTPUT ;
  USE SIGNAL ;
  PORT
   LAYER M5 ;
   RECT 267.3600 630.6360 267.3840 630.7200 ;
  END
 END li_d[429]
 PIN li_d[430]
  DIRECTION OUTPUT ;
  USE SIGNAL ;
  PORT
   LAYER M5 ;
   RECT 267.6000 630.6360 267.6240 630.7200 ;
  END
 END li_d[430]
 PIN li_d[431]
  DIRECTION OUTPUT ;
  USE SIGNAL ;
  PORT
   LAYER M5 ;
   RECT 267.8400 630.6360 267.8640 630.7200 ;
  END
 END li_d[431]
 PIN li_d[432]
  DIRECTION OUTPUT ;
  USE SIGNAL ;
  PORT
   LAYER M5 ;
   RECT 268.0800 630.6360 268.1040 630.7200 ;
  END
 END li_d[432]
 PIN li_d[433]
  DIRECTION OUTPUT ;
  USE SIGNAL ;
  PORT
   LAYER M5 ;
   RECT 268.3200 630.6360 268.3440 630.7200 ;
  END
 END li_d[433]
 PIN li_d[434]
  DIRECTION OUTPUT ;
  USE SIGNAL ;
  PORT
   LAYER M5 ;
   RECT 268.5600 630.6360 268.5840 630.7200 ;
  END
 END li_d[434]
 PIN li_d[435]
  DIRECTION OUTPUT ;
  USE SIGNAL ;
  PORT
   LAYER M5 ;
   RECT 268.8000 630.6360 268.8240 630.7200 ;
  END
 END li_d[435]
 PIN li_d[436]
  DIRECTION OUTPUT ;
  USE SIGNAL ;
  PORT
   LAYER M5 ;
   RECT 269.0400 630.6360 269.0640 630.7200 ;
  END
 END li_d[436]
 PIN li_d[437]
  DIRECTION OUTPUT ;
  USE SIGNAL ;
  PORT
   LAYER M5 ;
   RECT 269.2800 630.6360 269.3040 630.7200 ;
  END
 END li_d[437]
 PIN li_d[438]
  DIRECTION OUTPUT ;
  USE SIGNAL ;
  PORT
   LAYER M5 ;
   RECT 269.5200 630.6360 269.5440 630.7200 ;
  END
 END li_d[438]
 PIN li_d[439]
  DIRECTION OUTPUT ;
  USE SIGNAL ;
  PORT
   LAYER M5 ;
   RECT 269.7600 630.6360 269.7840 630.7200 ;
  END
 END li_d[439]
 PIN li_d[440]
  DIRECTION OUTPUT ;
  USE SIGNAL ;
  PORT
   LAYER M5 ;
   RECT 270.0000 630.6360 270.0240 630.7200 ;
  END
 END li_d[440]
 PIN li_d[441]
  DIRECTION OUTPUT ;
  USE SIGNAL ;
  PORT
   LAYER M5 ;
   RECT 270.2400 630.6360 270.2640 630.7200 ;
  END
 END li_d[441]
 PIN li_d[442]
  DIRECTION OUTPUT ;
  USE SIGNAL ;
  PORT
   LAYER M5 ;
   RECT 270.4800 630.6360 270.5040 630.7200 ;
  END
 END li_d[442]
 PIN li_d[443]
  DIRECTION OUTPUT ;
  USE SIGNAL ;
  PORT
   LAYER M5 ;
   RECT 270.7200 630.6360 270.7440 630.7200 ;
  END
 END li_d[443]
 PIN li_d[444]
  DIRECTION OUTPUT ;
  USE SIGNAL ;
  PORT
   LAYER M5 ;
   RECT 270.9600 630.6360 270.9840 630.7200 ;
  END
 END li_d[444]
 PIN li_d[445]
  DIRECTION OUTPUT ;
  USE SIGNAL ;
  PORT
   LAYER M5 ;
   RECT 271.2000 630.6360 271.2240 630.7200 ;
  END
 END li_d[445]
 PIN li_d[446]
  DIRECTION OUTPUT ;
  USE SIGNAL ;
  PORT
   LAYER M5 ;
   RECT 271.4400 630.6360 271.4640 630.7200 ;
  END
 END li_d[446]
 PIN li_d[447]
  DIRECTION OUTPUT ;
  USE SIGNAL ;
  PORT
   LAYER M5 ;
   RECT 271.6800 630.6360 271.7040 630.7200 ;
  END
 END li_d[447]
 PIN li_d[448]
  DIRECTION OUTPUT ;
  USE SIGNAL ;
  PORT
   LAYER M5 ;
   RECT 271.9200 630.6360 271.9440 630.7200 ;
  END
 END li_d[448]
 PIN li_d[449]
  DIRECTION OUTPUT ;
  USE SIGNAL ;
  PORT
   LAYER M5 ;
   RECT 272.1600 630.6360 272.1840 630.7200 ;
  END
 END li_d[449]
 PIN li_d[450]
  DIRECTION OUTPUT ;
  USE SIGNAL ;
  PORT
   LAYER M5 ;
   RECT 272.4000 630.6360 272.4240 630.7200 ;
  END
 END li_d[450]
 PIN li_d[451]
  DIRECTION OUTPUT ;
  USE SIGNAL ;
  PORT
   LAYER M5 ;
   RECT 272.6400 630.6360 272.6640 630.7200 ;
  END
 END li_d[451]
 PIN li_d[452]
  DIRECTION OUTPUT ;
  USE SIGNAL ;
  PORT
   LAYER M5 ;
   RECT 272.8800 630.6360 272.9040 630.7200 ;
  END
 END li_d[452]
 PIN li_d[453]
  DIRECTION OUTPUT ;
  USE SIGNAL ;
  PORT
   LAYER M5 ;
   RECT 273.1200 630.6360 273.1440 630.7200 ;
  END
 END li_d[453]
 PIN li_d[454]
  DIRECTION OUTPUT ;
  USE SIGNAL ;
  PORT
   LAYER M5 ;
   RECT 273.3600 630.6360 273.3840 630.7200 ;
  END
 END li_d[454]
 PIN li_d[455]
  DIRECTION OUTPUT ;
  USE SIGNAL ;
  PORT
   LAYER M5 ;
   RECT 273.6000 630.6360 273.6240 630.7200 ;
  END
 END li_d[455]
 PIN li_d[456]
  DIRECTION OUTPUT ;
  USE SIGNAL ;
  PORT
   LAYER M5 ;
   RECT 273.8400 630.6360 273.8640 630.7200 ;
  END
 END li_d[456]
 PIN li_d[457]
  DIRECTION OUTPUT ;
  USE SIGNAL ;
  PORT
   LAYER M5 ;
   RECT 274.0800 630.6360 274.1040 630.7200 ;
  END
 END li_d[457]
 PIN li_d[458]
  DIRECTION OUTPUT ;
  USE SIGNAL ;
  PORT
   LAYER M5 ;
   RECT 274.3200 630.6360 274.3440 630.7200 ;
  END
 END li_d[458]
 PIN li_d[459]
  DIRECTION OUTPUT ;
  USE SIGNAL ;
  PORT
   LAYER M5 ;
   RECT 274.5600 630.6360 274.5840 630.7200 ;
  END
 END li_d[459]
 PIN li_d[460]
  DIRECTION OUTPUT ;
  USE SIGNAL ;
  PORT
   LAYER M5 ;
   RECT 274.8000 630.6360 274.8240 630.7200 ;
  END
 END li_d[460]
 PIN li_d[461]
  DIRECTION OUTPUT ;
  USE SIGNAL ;
  PORT
   LAYER M5 ;
   RECT 275.0400 630.6360 275.0640 630.7200 ;
  END
 END li_d[461]
 PIN li_d[462]
  DIRECTION OUTPUT ;
  USE SIGNAL ;
  PORT
   LAYER M5 ;
   RECT 275.2800 630.6360 275.3040 630.7200 ;
  END
 END li_d[462]
 PIN li_d[463]
  DIRECTION OUTPUT ;
  USE SIGNAL ;
  PORT
   LAYER M5 ;
   RECT 275.5200 630.6360 275.5440 630.7200 ;
  END
 END li_d[463]
 PIN li_d[464]
  DIRECTION OUTPUT ;
  USE SIGNAL ;
  PORT
   LAYER M5 ;
   RECT 275.7600 630.6360 275.7840 630.7200 ;
  END
 END li_d[464]
 PIN li_d[465]
  DIRECTION OUTPUT ;
  USE SIGNAL ;
  PORT
   LAYER M5 ;
   RECT 276.0000 630.6360 276.0240 630.7200 ;
  END
 END li_d[465]
 PIN li_d[466]
  DIRECTION OUTPUT ;
  USE SIGNAL ;
  PORT
   LAYER M5 ;
   RECT 276.2400 630.6360 276.2640 630.7200 ;
  END
 END li_d[466]
 PIN li_d[467]
  DIRECTION OUTPUT ;
  USE SIGNAL ;
  PORT
   LAYER M5 ;
   RECT 276.4800 630.6360 276.5040 630.7200 ;
  END
 END li_d[467]
 PIN li_d[468]
  DIRECTION OUTPUT ;
  USE SIGNAL ;
  PORT
   LAYER M5 ;
   RECT 276.7200 630.6360 276.7440 630.7200 ;
  END
 END li_d[468]
 PIN li_d[469]
  DIRECTION OUTPUT ;
  USE SIGNAL ;
  PORT
   LAYER M5 ;
   RECT 276.9600 630.6360 276.9840 630.7200 ;
  END
 END li_d[469]
 PIN li_d[470]
  DIRECTION OUTPUT ;
  USE SIGNAL ;
  PORT
   LAYER M5 ;
   RECT 277.2000 630.6360 277.2240 630.7200 ;
  END
 END li_d[470]
 PIN li_d[471]
  DIRECTION OUTPUT ;
  USE SIGNAL ;
  PORT
   LAYER M5 ;
   RECT 277.4400 630.6360 277.4640 630.7200 ;
  END
 END li_d[471]
 PIN li_d[472]
  DIRECTION OUTPUT ;
  USE SIGNAL ;
  PORT
   LAYER M5 ;
   RECT 277.6800 630.6360 277.7040 630.7200 ;
  END
 END li_d[472]
 PIN li_d[473]
  DIRECTION OUTPUT ;
  USE SIGNAL ;
  PORT
   LAYER M5 ;
   RECT 277.9200 630.6360 277.9440 630.7200 ;
  END
 END li_d[473]
 PIN li_d[474]
  DIRECTION OUTPUT ;
  USE SIGNAL ;
  PORT
   LAYER M5 ;
   RECT 278.1600 630.6360 278.1840 630.7200 ;
  END
 END li_d[474]
 PIN li_d[475]
  DIRECTION OUTPUT ;
  USE SIGNAL ;
  PORT
   LAYER M5 ;
   RECT 278.4000 630.6360 278.4240 630.7200 ;
  END
 END li_d[475]
 PIN li_d[476]
  DIRECTION OUTPUT ;
  USE SIGNAL ;
  PORT
   LAYER M5 ;
   RECT 278.6400 630.6360 278.6640 630.7200 ;
  END
 END li_d[476]
 PIN li_d[477]
  DIRECTION OUTPUT ;
  USE SIGNAL ;
  PORT
   LAYER M5 ;
   RECT 278.8800 630.6360 278.9040 630.7200 ;
  END
 END li_d[477]
 PIN li_d[478]
  DIRECTION OUTPUT ;
  USE SIGNAL ;
  PORT
   LAYER M5 ;
   RECT 279.1200 630.6360 279.1440 630.7200 ;
  END
 END li_d[478]
 PIN li_d[479]
  DIRECTION OUTPUT ;
  USE SIGNAL ;
  PORT
   LAYER M5 ;
   RECT 279.3600 630.6360 279.3840 630.7200 ;
  END
 END li_d[479]
 PIN li_d[480]
  DIRECTION OUTPUT ;
  USE SIGNAL ;
  PORT
   LAYER M5 ;
   RECT 279.6000 630.6360 279.6240 630.7200 ;
  END
 END li_d[480]
 PIN li_d[481]
  DIRECTION OUTPUT ;
  USE SIGNAL ;
  PORT
   LAYER M5 ;
   RECT 279.8400 630.6360 279.8640 630.7200 ;
  END
 END li_d[481]
 PIN li_d[482]
  DIRECTION OUTPUT ;
  USE SIGNAL ;
  PORT
   LAYER M5 ;
   RECT 280.0800 630.6360 280.1040 630.7200 ;
  END
 END li_d[482]
 PIN li_d[483]
  DIRECTION OUTPUT ;
  USE SIGNAL ;
  PORT
   LAYER M5 ;
   RECT 280.3200 630.6360 280.3440 630.7200 ;
  END
 END li_d[483]
 PIN li_d[484]
  DIRECTION OUTPUT ;
  USE SIGNAL ;
  PORT
   LAYER M5 ;
   RECT 280.5600 630.6360 280.5840 630.7200 ;
  END
 END li_d[484]
 PIN li_d[485]
  DIRECTION OUTPUT ;
  USE SIGNAL ;
  PORT
   LAYER M5 ;
   RECT 280.8000 630.6360 280.8240 630.7200 ;
  END
 END li_d[485]
 PIN li_d[486]
  DIRECTION OUTPUT ;
  USE SIGNAL ;
  PORT
   LAYER M5 ;
   RECT 281.0400 630.6360 281.0640 630.7200 ;
  END
 END li_d[486]
 PIN li_d[487]
  DIRECTION OUTPUT ;
  USE SIGNAL ;
  PORT
   LAYER M5 ;
   RECT 281.2800 630.6360 281.3040 630.7200 ;
  END
 END li_d[487]
 PIN li_d[488]
  DIRECTION OUTPUT ;
  USE SIGNAL ;
  PORT
   LAYER M5 ;
   RECT 281.5200 630.6360 281.5440 630.7200 ;
  END
 END li_d[488]
 PIN li_d[489]
  DIRECTION OUTPUT ;
  USE SIGNAL ;
  PORT
   LAYER M5 ;
   RECT 281.7600 630.6360 281.7840 630.7200 ;
  END
 END li_d[489]
 PIN li_d[490]
  DIRECTION OUTPUT ;
  USE SIGNAL ;
  PORT
   LAYER M5 ;
   RECT 282.0000 630.6360 282.0240 630.7200 ;
  END
 END li_d[490]
 PIN li_d[491]
  DIRECTION OUTPUT ;
  USE SIGNAL ;
  PORT
   LAYER M5 ;
   RECT 282.2400 630.6360 282.2640 630.7200 ;
  END
 END li_d[491]
 PIN li_d[492]
  DIRECTION OUTPUT ;
  USE SIGNAL ;
  PORT
   LAYER M5 ;
   RECT 282.4800 630.6360 282.5040 630.7200 ;
  END
 END li_d[492]
 PIN li_d[493]
  DIRECTION OUTPUT ;
  USE SIGNAL ;
  PORT
   LAYER M5 ;
   RECT 282.7200 630.6360 282.7440 630.7200 ;
  END
 END li_d[493]
 PIN li_d[494]
  DIRECTION OUTPUT ;
  USE SIGNAL ;
  PORT
   LAYER M5 ;
   RECT 282.9600 630.6360 282.9840 630.7200 ;
  END
 END li_d[494]
 PIN li_d[495]
  DIRECTION OUTPUT ;
  USE SIGNAL ;
  PORT
   LAYER M5 ;
   RECT 283.2000 630.6360 283.2240 630.7200 ;
  END
 END li_d[495]
 PIN li_d[496]
  DIRECTION OUTPUT ;
  USE SIGNAL ;
  PORT
   LAYER M5 ;
   RECT 283.4400 630.6360 283.4640 630.7200 ;
  END
 END li_d[496]
 PIN li_d[497]
  DIRECTION OUTPUT ;
  USE SIGNAL ;
  PORT
   LAYER M5 ;
   RECT 283.6800 630.6360 283.7040 630.7200 ;
  END
 END li_d[497]
 PIN li_d[498]
  DIRECTION OUTPUT ;
  USE SIGNAL ;
  PORT
   LAYER M5 ;
   RECT 283.9200 630.6360 283.9440 630.7200 ;
  END
 END li_d[498]
 PIN li_d[499]
  DIRECTION OUTPUT ;
  USE SIGNAL ;
  PORT
   LAYER M5 ;
   RECT 284.1600 630.6360 284.1840 630.7200 ;
  END
 END li_d[499]
 PIN li_d[500]
  DIRECTION OUTPUT ;
  USE SIGNAL ;
  PORT
   LAYER M5 ;
   RECT 284.4000 630.6360 284.4240 630.7200 ;
  END
 END li_d[500]
 PIN li_d[501]
  DIRECTION OUTPUT ;
  USE SIGNAL ;
  PORT
   LAYER M5 ;
   RECT 284.6400 630.6360 284.6640 630.7200 ;
  END
 END li_d[501]
 PIN li_d[502]
  DIRECTION OUTPUT ;
  USE SIGNAL ;
  PORT
   LAYER M5 ;
   RECT 284.8800 630.6360 284.9040 630.7200 ;
  END
 END li_d[502]
 PIN li_d[503]
  DIRECTION OUTPUT ;
  USE SIGNAL ;
  PORT
   LAYER M5 ;
   RECT 285.1200 630.6360 285.1440 630.7200 ;
  END
 END li_d[503]
 PIN li_d[504]
  DIRECTION OUTPUT ;
  USE SIGNAL ;
  PORT
   LAYER M5 ;
   RECT 285.3600 630.6360 285.3840 630.7200 ;
  END
 END li_d[504]
 PIN li_d[505]
  DIRECTION OUTPUT ;
  USE SIGNAL ;
  PORT
   LAYER M5 ;
   RECT 285.6000 630.6360 285.6240 630.7200 ;
  END
 END li_d[505]
 PIN li_d[506]
  DIRECTION OUTPUT ;
  USE SIGNAL ;
  PORT
   LAYER M5 ;
   RECT 285.8400 630.6360 285.8640 630.7200 ;
  END
 END li_d[506]
 PIN li_d[507]
  DIRECTION OUTPUT ;
  USE SIGNAL ;
  PORT
   LAYER M5 ;
   RECT 286.0800 630.6360 286.1040 630.7200 ;
  END
 END li_d[507]
 PIN li_d[508]
  DIRECTION OUTPUT ;
  USE SIGNAL ;
  PORT
   LAYER M5 ;
   RECT 286.3200 630.6360 286.3440 630.7200 ;
  END
 END li_d[508]
 PIN li_d[509]
  DIRECTION OUTPUT ;
  USE SIGNAL ;
  PORT
   LAYER M5 ;
   RECT 286.5600 630.6360 286.5840 630.7200 ;
  END
 END li_d[509]
 PIN li_d[510]
  DIRECTION OUTPUT ;
  USE SIGNAL ;
  PORT
   LAYER M5 ;
   RECT 286.8000 630.6360 286.8240 630.7200 ;
  END
 END li_d[510]
 PIN li_d[511]
  DIRECTION OUTPUT ;
  USE SIGNAL ;
  PORT
   LAYER M5 ;
   RECT 287.0400 630.6360 287.0640 630.7200 ;
  END
 END li_d[511]
 PIN li_d[512]
  DIRECTION OUTPUT ;
  USE SIGNAL ;
  PORT
   LAYER M5 ;
   RECT 287.2800 630.6360 287.3040 630.7200 ;
  END
 END li_d[512]
 PIN li_d[513]
  DIRECTION OUTPUT ;
  USE SIGNAL ;
  PORT
   LAYER M5 ;
   RECT 287.5200 630.6360 287.5440 630.7200 ;
  END
 END li_d[513]
 PIN li_d[514]
  DIRECTION OUTPUT ;
  USE SIGNAL ;
  PORT
   LAYER M5 ;
   RECT 287.7600 630.6360 287.7840 630.7200 ;
  END
 END li_d[514]
 PIN li_d[515]
  DIRECTION OUTPUT ;
  USE SIGNAL ;
  PORT
   LAYER M5 ;
   RECT 288.0000 630.6360 288.0240 630.7200 ;
  END
 END li_d[515]
 PIN li_d[516]
  DIRECTION OUTPUT ;
  USE SIGNAL ;
  PORT
   LAYER M5 ;
   RECT 288.2400 630.6360 288.2640 630.7200 ;
  END
 END li_d[516]
 PIN li_d[517]
  DIRECTION OUTPUT ;
  USE SIGNAL ;
  PORT
   LAYER M5 ;
   RECT 288.4800 630.6360 288.5040 630.7200 ;
  END
 END li_d[517]
 PIN li_d[518]
  DIRECTION OUTPUT ;
  USE SIGNAL ;
  PORT
   LAYER M5 ;
   RECT 288.7200 630.6360 288.7440 630.7200 ;
  END
 END li_d[518]
 PIN li_d[519]
  DIRECTION OUTPUT ;
  USE SIGNAL ;
  PORT
   LAYER M5 ;
   RECT 288.9600 630.6360 288.9840 630.7200 ;
  END
 END li_d[519]
 PIN li_d[520]
  DIRECTION OUTPUT ;
  USE SIGNAL ;
  PORT
   LAYER M5 ;
   RECT 289.2000 630.6360 289.2240 630.7200 ;
  END
 END li_d[520]
 PIN li_d[521]
  DIRECTION OUTPUT ;
  USE SIGNAL ;
  PORT
   LAYER M5 ;
   RECT 289.4400 630.6360 289.4640 630.7200 ;
  END
 END li_d[521]
 PIN li_d[522]
  DIRECTION OUTPUT ;
  USE SIGNAL ;
  PORT
   LAYER M5 ;
   RECT 289.6800 630.6360 289.7040 630.7200 ;
  END
 END li_d[522]
 PIN li_d[523]
  DIRECTION OUTPUT ;
  USE SIGNAL ;
  PORT
   LAYER M5 ;
   RECT 289.9200 630.6360 289.9440 630.7200 ;
  END
 END li_d[523]
 PIN li_d[524]
  DIRECTION OUTPUT ;
  USE SIGNAL ;
  PORT
   LAYER M5 ;
   RECT 290.1600 630.6360 290.1840 630.7200 ;
  END
 END li_d[524]
 PIN li_d[525]
  DIRECTION OUTPUT ;
  USE SIGNAL ;
  PORT
   LAYER M5 ;
   RECT 290.4000 630.6360 290.4240 630.7200 ;
  END
 END li_d[525]
 PIN li_d[526]
  DIRECTION OUTPUT ;
  USE SIGNAL ;
  PORT
   LAYER M5 ;
   RECT 290.6400 630.6360 290.6640 630.7200 ;
  END
 END li_d[526]
 PIN li_d[527]
  DIRECTION OUTPUT ;
  USE SIGNAL ;
  PORT
   LAYER M5 ;
   RECT 290.8800 630.6360 290.9040 630.7200 ;
  END
 END li_d[527]
 PIN li_d[528]
  DIRECTION OUTPUT ;
  USE SIGNAL ;
  PORT
   LAYER M5 ;
   RECT 291.1200 630.6360 291.1440 630.7200 ;
  END
 END li_d[528]
 PIN li_d[529]
  DIRECTION OUTPUT ;
  USE SIGNAL ;
  PORT
   LAYER M5 ;
   RECT 291.3600 630.6360 291.3840 630.7200 ;
  END
 END li_d[529]
 PIN li_d[530]
  DIRECTION OUTPUT ;
  USE SIGNAL ;
  PORT
   LAYER M5 ;
   RECT 291.6000 630.6360 291.6240 630.7200 ;
  END
 END li_d[530]
 PIN li_d[531]
  DIRECTION OUTPUT ;
  USE SIGNAL ;
  PORT
   LAYER M5 ;
   RECT 291.8400 630.6360 291.8640 630.7200 ;
  END
 END li_d[531]
 PIN li_d[532]
  DIRECTION OUTPUT ;
  USE SIGNAL ;
  PORT
   LAYER M5 ;
   RECT 292.0800 630.6360 292.1040 630.7200 ;
  END
 END li_d[532]
 PIN li_d[533]
  DIRECTION OUTPUT ;
  USE SIGNAL ;
  PORT
   LAYER M5 ;
   RECT 292.3200 630.6360 292.3440 630.7200 ;
  END
 END li_d[533]
 PIN li_d[534]
  DIRECTION OUTPUT ;
  USE SIGNAL ;
  PORT
   LAYER M5 ;
   RECT 292.5600 630.6360 292.5840 630.7200 ;
  END
 END li_d[534]
 PIN li_d[535]
  DIRECTION OUTPUT ;
  USE SIGNAL ;
  PORT
   LAYER M5 ;
   RECT 292.8000 630.6360 292.8240 630.7200 ;
  END
 END li_d[535]
 PIN li_d[536]
  DIRECTION OUTPUT ;
  USE SIGNAL ;
  PORT
   LAYER M5 ;
   RECT 293.0400 630.6360 293.0640 630.7200 ;
  END
 END li_d[536]
 PIN li_d[537]
  DIRECTION OUTPUT ;
  USE SIGNAL ;
  PORT
   LAYER M5 ;
   RECT 293.2800 630.6360 293.3040 630.7200 ;
  END
 END li_d[537]
 PIN li_d[538]
  DIRECTION OUTPUT ;
  USE SIGNAL ;
  PORT
   LAYER M5 ;
   RECT 293.5200 630.6360 293.5440 630.7200 ;
  END
 END li_d[538]
 PIN li_d[539]
  DIRECTION OUTPUT ;
  USE SIGNAL ;
  PORT
   LAYER M5 ;
   RECT 293.7600 630.6360 293.7840 630.7200 ;
  END
 END li_d[539]
 PIN li_d[540]
  DIRECTION OUTPUT ;
  USE SIGNAL ;
  PORT
   LAYER M5 ;
   RECT 294.0000 630.6360 294.0240 630.7200 ;
  END
 END li_d[540]
 PIN li_d[541]
  DIRECTION OUTPUT ;
  USE SIGNAL ;
  PORT
   LAYER M5 ;
   RECT 294.2400 630.6360 294.2640 630.7200 ;
  END
 END li_d[541]
 PIN li_d[542]
  DIRECTION OUTPUT ;
  USE SIGNAL ;
  PORT
   LAYER M5 ;
   RECT 294.4800 630.6360 294.5040 630.7200 ;
  END
 END li_d[542]
 PIN li_d[543]
  DIRECTION OUTPUT ;
  USE SIGNAL ;
  PORT
   LAYER M5 ;
   RECT 294.7200 630.6360 294.7440 630.7200 ;
  END
 END li_d[543]
 PIN li_d[544]
  DIRECTION OUTPUT ;
  USE SIGNAL ;
  PORT
   LAYER M5 ;
   RECT 294.9600 630.6360 294.9840 630.7200 ;
  END
 END li_d[544]
 PIN li_d[545]
  DIRECTION OUTPUT ;
  USE SIGNAL ;
  PORT
   LAYER M5 ;
   RECT 295.2000 630.6360 295.2240 630.7200 ;
  END
 END li_d[545]
 PIN li_d[546]
  DIRECTION OUTPUT ;
  USE SIGNAL ;
  PORT
   LAYER M5 ;
   RECT 295.4400 630.6360 295.4640 630.7200 ;
  END
 END li_d[546]
 PIN li_d[547]
  DIRECTION OUTPUT ;
  USE SIGNAL ;
  PORT
   LAYER M5 ;
   RECT 295.6800 630.6360 295.7040 630.7200 ;
  END
 END li_d[547]
 PIN li_d[548]
  DIRECTION OUTPUT ;
  USE SIGNAL ;
  PORT
   LAYER M5 ;
   RECT 295.9200 630.6360 295.9440 630.7200 ;
  END
 END li_d[548]
 PIN li_d[549]
  DIRECTION OUTPUT ;
  USE SIGNAL ;
  PORT
   LAYER M5 ;
   RECT 296.1600 630.6360 296.1840 630.7200 ;
  END
 END li_d[549]
 PIN li_d[550]
  DIRECTION OUTPUT ;
  USE SIGNAL ;
  PORT
   LAYER M5 ;
   RECT 296.4000 630.6360 296.4240 630.7200 ;
  END
 END li_d[550]
 PIN li_d[551]
  DIRECTION OUTPUT ;
  USE SIGNAL ;
  PORT
   LAYER M5 ;
   RECT 296.6400 630.6360 296.6640 630.7200 ;
  END
 END li_d[551]
 PIN li_d[552]
  DIRECTION OUTPUT ;
  USE SIGNAL ;
  PORT
   LAYER M5 ;
   RECT 296.8800 630.6360 296.9040 630.7200 ;
  END
 END li_d[552]
 PIN ck[0]
  DIRECTION INPUT ;
  USE CLOCK ;
  PORT
   LAYER M5 ;
   RECT 151.1880 630.2400 151.2360 630.7200 ;
  END
 END ck[0]
 PIN flt[0]
  DIRECTION OUTPUT ;
  USE SIGNAL ;
  PORT
   LAYER M4 ;
   RECT 302.3160 313.4400 302.4000 313.4640 ;
  END
 END flt[0]
 PIN flt[1]
  DIRECTION OUTPUT ;
  USE SIGNAL ;
  PORT
   LAYER M4 ;
   RECT 302.3160 313.9200 302.4000 313.9440 ;
  END
 END flt[1]
 PIN flt[2]
  DIRECTION OUTPUT ;
  USE SIGNAL ;
  PORT
   LAYER M4 ;
   RECT 302.3160 314.4000 302.4000 314.4240 ;
  END
 END flt[2]
 PIN chb[0]
  DIRECTION INPUT ;
  USE SIGNAL ;
  PORT
   LAYER M4 ;
   RECT 302.3160 314.8800 302.4000 314.9040 ;
  END
 END chb[0]
 PIN rs[0]
  DIRECTION INPUT ;
  USE SIGNAL ;
  PORT
   LAYER M4 ;
   RECT 302.3160 315.3600 302.4000 315.3840 ;
  END
 END rs[0]
END dsfd_coll_lane_e_safe8_ntf
END LIBRARY
